VERSION 5.8 ;
BUSBITCHARS "[]" ;
DIVIDERCHAR "/" ;
UNITS
    DATABASE MICRONS 1000 ;
END UNITS

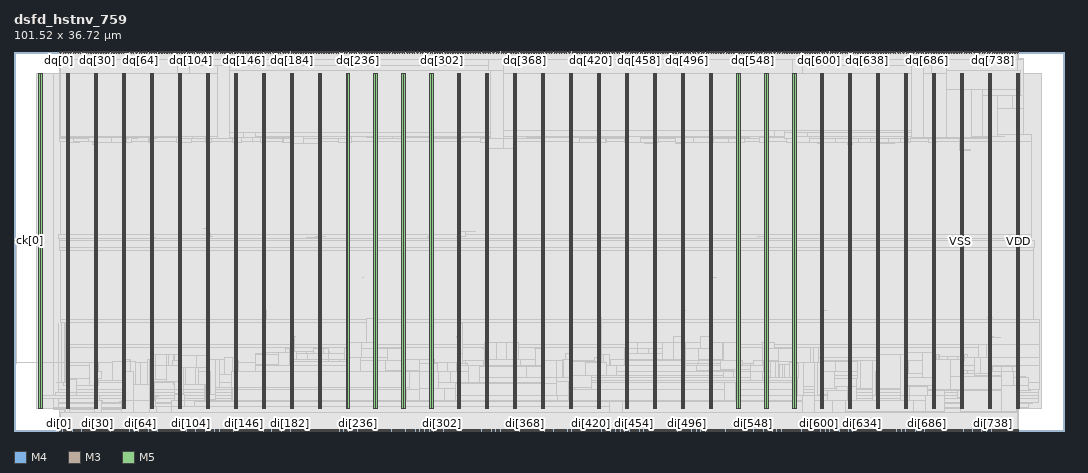
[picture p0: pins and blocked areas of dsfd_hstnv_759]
MACRO dsfd_hstnv_759
  FOREIGN dsfd_hstnv_759 0 0 ;
  CLASS BLOCK ;
  SIZE 101.52 BY 36.72 ;
  PIN ck[0]
    DIRECTION INPUT ;
    USE SIGNAL ;
    PORT
      LAYER M4 ;
        RECT  0 18.384 0.192 18.408 ;
    END
    PORT
      LAYER M4 ;
        RECT  0.156 18.384 0.275 18.408 ;
    END
  END ck[0]
  PIN di[0]
    DIRECTION INPUT ;
    USE SIGNAL ;
    PORT
      LAYER M3 ;
        RECT  4.356 0 4.374 0.144 ;
    END
  END di[0]
  PIN di[100]
    DIRECTION INPUT ;
    USE SIGNAL ;
    PORT
      LAYER M3 ;
        RECT  16.596 0 16.614 0.144 ;
    END
  END di[100]
  PIN di[101]
    DIRECTION INPUT ;
    USE SIGNAL ;
    PORT
      LAYER M5 ;
        RECT  16.752 0 16.776 0.192 ;
    END
  END di[101]
  PIN di[102]
    DIRECTION INPUT ;
    USE SIGNAL ;
    PORT
      LAYER M3 ;
        RECT  16.848 0 16.866 0.144 ;
    END
  END di[102]
  PIN di[103]
    DIRECTION INPUT ;
    USE SIGNAL ;
    PORT
      LAYER M5 ;
        RECT  16.992 0 17.016 0.192 ;
    END
  END di[103]
  PIN di[104]
    DIRECTION INPUT ;
    USE SIGNAL ;
    PORT
      LAYER M3 ;
        RECT  17.1 0 17.118 0.144 ;
    END
  END di[104]
  PIN di[105]
    DIRECTION INPUT ;
    USE SIGNAL ;
    PORT
      LAYER M5 ;
        RECT  17.232 0 17.256 0.192 ;
    END
  END di[105]
  PIN di[106]
    DIRECTION INPUT ;
    USE SIGNAL ;
    PORT
      LAYER M3 ;
        RECT  17.352 0 17.37 0.144 ;
    END
  END di[106]
  PIN di[107]
    DIRECTION INPUT ;
    USE SIGNAL ;
    PORT
      LAYER M5 ;
        RECT  17.472 0 17.496 0.192 ;
    END
  END di[107]
  PIN di[108]
    DIRECTION INPUT ;
    USE SIGNAL ;
    PORT
      LAYER M3 ;
        RECT  17.604 0 17.622 0.144 ;
    END
  END di[108]
  PIN di[109]
    DIRECTION INPUT ;
    USE SIGNAL ;
    PORT
      LAYER M5 ;
        RECT  17.712 0 17.736 0.192 ;
    END
  END di[109]
  PIN di[10]
    DIRECTION INPUT ;
    USE SIGNAL ;
    PORT
      LAYER M3 ;
        RECT  5.58 0 5.598 0.144 ;
    END
  END di[10]
  PIN di[110]
    DIRECTION INPUT ;
    USE SIGNAL ;
    PORT
      LAYER M3 ;
        RECT  17.82 0 17.838 0.144 ;
    END
  END di[110]
  PIN di[111]
    DIRECTION INPUT ;
    USE SIGNAL ;
    PORT
      LAYER M5 ;
        RECT  17.952 0 17.976 0.192 ;
    END
  END di[111]
  PIN di[112]
    DIRECTION INPUT ;
    USE SIGNAL ;
    PORT
      LAYER M3 ;
        RECT  18.072 0 18.09 0.144 ;
    END
  END di[112]
  PIN di[113]
    DIRECTION INPUT ;
    USE SIGNAL ;
    PORT
      LAYER M5 ;
        RECT  18.192 0 18.216 0.192 ;
    END
  END di[113]
  PIN di[114]
    DIRECTION INPUT ;
    USE SIGNAL ;
    PORT
      LAYER M3 ;
        RECT  18.324 0 18.342 0.144 ;
    END
  END di[114]
  PIN di[115]
    DIRECTION INPUT ;
    USE SIGNAL ;
    PORT
      LAYER M5 ;
        RECT  18.432 0 18.456 0.192 ;
    END
  END di[115]
  PIN di[116]
    DIRECTION INPUT ;
    USE SIGNAL ;
    PORT
      LAYER M3 ;
        RECT  18.576 0 18.594 0.144 ;
    END
  END di[116]
  PIN di[117]
    DIRECTION INPUT ;
    USE SIGNAL ;
    PORT
      LAYER M5 ;
        RECT  18.672 0 18.696 0.192 ;
    END
  END di[117]
  PIN di[118]
    DIRECTION INPUT ;
    USE SIGNAL ;
    PORT
      LAYER M3 ;
        RECT  18.828 0 18.846 0.144 ;
    END
  END di[118]
  PIN di[119]
    DIRECTION INPUT ;
    USE SIGNAL ;
    PORT
      LAYER M5 ;
        RECT  18.912 0 18.936 0.192 ;
    END
  END di[119]
  PIN di[11]
    DIRECTION INPUT ;
    USE SIGNAL ;
    PORT
      LAYER M5 ;
        RECT  5.712 0 5.736 0.192 ;
    END
  END di[11]
  PIN di[120]
    DIRECTION INPUT ;
    USE SIGNAL ;
    PORT
      LAYER M3 ;
        RECT  19.044 0 19.062 0.144 ;
    END
  END di[120]
  PIN di[121]
    DIRECTION INPUT ;
    USE SIGNAL ;
    PORT
      LAYER M5 ;
        RECT  19.2 0 19.224 0.192 ;
    END
  END di[121]
  PIN di[122]
    DIRECTION INPUT ;
    USE SIGNAL ;
    PORT
      LAYER M3 ;
        RECT  19.296 0 19.314 0.144 ;
    END
  END di[122]
  PIN di[123]
    DIRECTION INPUT ;
    USE SIGNAL ;
    PORT
      LAYER M5 ;
        RECT  19.44 0 19.464 0.192 ;
    END
  END di[123]
  PIN di[124]
    DIRECTION INPUT ;
    USE SIGNAL ;
    PORT
      LAYER M3 ;
        RECT  19.548 0 19.566 0.144 ;
    END
  END di[124]
  PIN di[125]
    DIRECTION INPUT ;
    USE SIGNAL ;
    PORT
      LAYER M5 ;
        RECT  19.68 0 19.704 0.192 ;
    END
  END di[125]
  PIN di[126]
    DIRECTION INPUT ;
    USE SIGNAL ;
    PORT
      LAYER M3 ;
        RECT  19.8 0 19.818 0.144 ;
    END
  END di[126]
  PIN di[127]
    DIRECTION INPUT ;
    USE SIGNAL ;
    PORT
      LAYER M5 ;
        RECT  19.92 0 19.944 0.192 ;
    END
  END di[127]
  PIN di[128]
    DIRECTION INPUT ;
    USE SIGNAL ;
    PORT
      LAYER M3 ;
        RECT  20.052 0 20.07 0.144 ;
    END
  END di[128]
  PIN di[129]
    DIRECTION INPUT ;
    USE SIGNAL ;
    PORT
      LAYER M5 ;
        RECT  20.16 0 20.184 0.192 ;
    END
  END di[129]
  PIN di[12]
    DIRECTION INPUT ;
    USE SIGNAL ;
    PORT
      LAYER M3 ;
        RECT  5.832 0 5.85 0.144 ;
    END
  END di[12]
  PIN di[130]
    DIRECTION INPUT ;
    USE SIGNAL ;
    PORT
      LAYER M3 ;
        RECT  20.268 0 20.286 0.144 ;
    END
  END di[130]
  PIN di[131]
    DIRECTION INPUT ;
    USE SIGNAL ;
    PORT
      LAYER M5 ;
        RECT  20.4 0 20.424 0.192 ;
    END
  END di[131]
  PIN di[132]
    DIRECTION INPUT ;
    USE SIGNAL ;
    PORT
      LAYER M3 ;
        RECT  20.52 0 20.538 0.144 ;
    END
  END di[132]
  PIN di[133]
    DIRECTION INPUT ;
    USE SIGNAL ;
    PORT
      LAYER M5 ;
        RECT  20.64 0 20.664 0.192 ;
    END
  END di[133]
  PIN di[134]
    DIRECTION INPUT ;
    USE SIGNAL ;
    PORT
      LAYER M3 ;
        RECT  20.772 0 20.79 0.144 ;
    END
  END di[134]
  PIN di[135]
    DIRECTION INPUT ;
    USE SIGNAL ;
    PORT
      LAYER M5 ;
        RECT  20.88 0 20.904 0.192 ;
    END
  END di[135]
  PIN di[136]
    DIRECTION INPUT ;
    USE SIGNAL ;
    PORT
      LAYER M3 ;
        RECT  21.024 0 21.042 0.144 ;
    END
  END di[136]
  PIN di[137]
    DIRECTION INPUT ;
    USE SIGNAL ;
    PORT
      LAYER M5 ;
        RECT  21.12 0 21.144 0.192 ;
    END
  END di[137]
  PIN di[138]
    DIRECTION INPUT ;
    USE SIGNAL ;
    PORT
      LAYER M3 ;
        RECT  21.276 0 21.294 0.144 ;
    END
  END di[138]
  PIN di[139]
    DIRECTION INPUT ;
    USE SIGNAL ;
    PORT
      LAYER M5 ;
        RECT  21.36 0 21.384 0.192 ;
    END
  END di[139]
  PIN di[13]
    DIRECTION INPUT ;
    USE SIGNAL ;
    PORT
      LAYER M5 ;
        RECT  5.952 0 5.976 0.192 ;
    END
  END di[13]
  PIN di[140]
    DIRECTION INPUT ;
    USE SIGNAL ;
    PORT
      LAYER M3 ;
        RECT  21.492 0 21.51 0.144 ;
    END
  END di[140]
  PIN di[141]
    DIRECTION INPUT ;
    USE SIGNAL ;
    PORT
      LAYER M5 ;
        RECT  21.6 0 21.624 0.192 ;
    END
  END di[141]
  PIN di[142]
    DIRECTION INPUT ;
    USE SIGNAL ;
    PORT
      LAYER M3 ;
        RECT  21.744 0 21.762 0.144 ;
    END
  END di[142]
  PIN di[143]
    DIRECTION INPUT ;
    USE SIGNAL ;
    PORT
      LAYER M5 ;
        RECT  21.888 0 21.912 0.192 ;
    END
  END di[143]
  PIN di[144]
    DIRECTION INPUT ;
    USE SIGNAL ;
    PORT
      LAYER M3 ;
        RECT  21.996 0 22.014 0.144 ;
    END
  END di[144]
  PIN di[145]
    DIRECTION INPUT ;
    USE SIGNAL ;
    PORT
      LAYER M5 ;
        RECT  22.128 0 22.152 0.192 ;
    END
  END di[145]
  PIN di[146]
    DIRECTION INPUT ;
    USE SIGNAL ;
    PORT
      LAYER M3 ;
        RECT  22.248 0 22.266 0.144 ;
    END
  END di[146]
  PIN di[147]
    DIRECTION INPUT ;
    USE SIGNAL ;
    PORT
      LAYER M5 ;
        RECT  22.368 0 22.392 0.192 ;
    END
  END di[147]
  PIN di[148]
    DIRECTION INPUT ;
    USE SIGNAL ;
    PORT
      LAYER M3 ;
        RECT  22.5 0 22.518 0.144 ;
    END
  END di[148]
  PIN di[149]
    DIRECTION INPUT ;
    USE SIGNAL ;
    PORT
      LAYER M5 ;
        RECT  22.608 0 22.632 0.192 ;
    END
    PORT
      LAYER M5 ;
        RECT  22.512 0.133 22.776 0.144 ;
    END
  END di[149]
  PIN di[14]
    DIRECTION INPUT ;
    USE SIGNAL ;
    PORT
      LAYER M3 ;
        RECT  6.084 0 6.102 0.144 ;
    END
  END di[14]
  PIN di[150]
    DIRECTION INPUT ;
    USE SIGNAL ;
    PORT
      LAYER M3 ;
        RECT  22.716 0 22.734 0.144 ;
    END
  END di[150]
  PIN di[151]
    DIRECTION INPUT ;
    USE SIGNAL ;
    PORT
      LAYER M5 ;
        RECT  22.848 0 22.872 0.192 ;
    END
  END di[151]
  PIN di[152]
    DIRECTION INPUT ;
    USE SIGNAL ;
    PORT
      LAYER M3 ;
        RECT  22.968 0 22.986 0.144 ;
    END
  END di[152]
  PIN di[153]
    DIRECTION INPUT ;
    USE SIGNAL ;
    PORT
      LAYER M5 ;
        RECT  23.088 0 23.112 0.192 ;
    END
  END di[153]
  PIN di[154]
    DIRECTION INPUT ;
    USE SIGNAL ;
    PORT
      LAYER M3 ;
        RECT  23.22 0 23.238 0.144 ;
    END
  END di[154]
  PIN di[155]
    DIRECTION INPUT ;
    USE SIGNAL ;
    PORT
      LAYER M5 ;
        RECT  23.328 0 23.352 0.192 ;
    END
  END di[155]
  PIN di[156]
    DIRECTION INPUT ;
    USE SIGNAL ;
    PORT
      LAYER M3 ;
        RECT  23.472 0 23.49 0.144 ;
    END
  END di[156]
  PIN di[157]
    DIRECTION INPUT ;
    USE SIGNAL ;
    PORT
      LAYER M5 ;
        RECT  23.568 0 23.592 0.192 ;
    END
  END di[157]
  PIN di[158]
    DIRECTION INPUT ;
    USE SIGNAL ;
    PORT
      LAYER M3 ;
        RECT  23.724 0 23.742 0.144 ;
    END
  END di[158]
  PIN di[159]
    DIRECTION INPUT ;
    USE SIGNAL ;
    PORT
      LAYER M5 ;
        RECT  23.808 0 23.832 0.192 ;
    END
  END di[159]
  PIN di[15]
    DIRECTION INPUT ;
    USE SIGNAL ;
    PORT
      LAYER M5 ;
        RECT  6.192 0 6.216 0.192 ;
    END
  END di[15]
  PIN di[160]
    DIRECTION INPUT ;
    USE SIGNAL ;
    PORT
      LAYER M3 ;
        RECT  23.94 0 23.958 0.144 ;
    END
  END di[160]
  PIN di[161]
    DIRECTION INPUT ;
    USE SIGNAL ;
    PORT
      LAYER M5 ;
        RECT  24.048 0 24.072 0.192 ;
    END
  END di[161]
  PIN di[162]
    DIRECTION INPUT ;
    USE SIGNAL ;
    PORT
      LAYER M3 ;
        RECT  24.192 0 24.21 0.144 ;
    END
  END di[162]
  PIN di[163]
    DIRECTION INPUT ;
    USE SIGNAL ;
    PORT
      LAYER M5 ;
        RECT  24.336 0 24.36 0.192 ;
    END
  END di[163]
  PIN di[164]
    DIRECTION INPUT ;
    USE SIGNAL ;
    PORT
      LAYER M3 ;
        RECT  24.444 0 24.462 0.144 ;
    END
  END di[164]
  PIN di[165]
    DIRECTION INPUT ;
    USE SIGNAL ;
    PORT
      LAYER M5 ;
        RECT  24.576 0 24.6 0.192 ;
    END
  END di[165]
  PIN di[166]
    DIRECTION INPUT ;
    USE SIGNAL ;
    PORT
      LAYER M3 ;
        RECT  24.696 0 24.714 0.144 ;
    END
  END di[166]
  PIN di[167]
    DIRECTION INPUT ;
    USE SIGNAL ;
    PORT
      LAYER M5 ;
        RECT  24.816 0 24.84 0.192 ;
    END
  END di[167]
  PIN di[168]
    DIRECTION INPUT ;
    USE SIGNAL ;
    PORT
      LAYER M3 ;
        RECT  24.948 0 24.966 0.144 ;
    END
  END di[168]
  PIN di[169]
    DIRECTION INPUT ;
    USE SIGNAL ;
    PORT
      LAYER M5 ;
        RECT  25.056 0 25.08 0.192 ;
    END
  END di[169]
  PIN di[16]
    DIRECTION INPUT ;
    USE SIGNAL ;
    PORT
      LAYER M3 ;
        RECT  6.336 0 6.354 0.144 ;
    END
  END di[16]
  PIN di[170]
    DIRECTION INPUT ;
    USE SIGNAL ;
    PORT
      LAYER M3 ;
        RECT  25.164 0 25.182 0.144 ;
    END
  END di[170]
  PIN di[171]
    DIRECTION INPUT ;
    USE SIGNAL ;
    PORT
      LAYER M5 ;
        RECT  25.296 0 25.32 0.192 ;
    END
  END di[171]
  PIN di[172]
    DIRECTION INPUT ;
    USE SIGNAL ;
    PORT
      LAYER M3 ;
        RECT  25.416 0 25.434 0.144 ;
    END
  END di[172]
  PIN di[173]
    DIRECTION INPUT ;
    USE SIGNAL ;
    PORT
      LAYER M5 ;
        RECT  25.536 0 25.56 0.192 ;
    END
  END di[173]
  PIN di[174]
    DIRECTION INPUT ;
    USE SIGNAL ;
    PORT
      LAYER M3 ;
        RECT  25.668 0 25.686 0.144 ;
    END
  END di[174]
  PIN di[175]
    DIRECTION INPUT ;
    USE SIGNAL ;
    PORT
      LAYER M5 ;
        RECT  25.776 0 25.8 0.192 ;
    END
  END di[175]
  PIN di[176]
    DIRECTION INPUT ;
    USE SIGNAL ;
    PORT
      LAYER M3 ;
        RECT  25.92 0 25.938 0.144 ;
    END
  END di[176]
  PIN di[177]
    DIRECTION INPUT ;
    USE SIGNAL ;
    PORT
      LAYER M5 ;
        RECT  26.016 0 26.04 0.192 ;
    END
  END di[177]
  PIN di[178]
    DIRECTION INPUT ;
    USE SIGNAL ;
    PORT
      LAYER M3 ;
        RECT  26.172 0 26.19 0.144 ;
    END
  END di[178]
  PIN di[179]
    DIRECTION INPUT ;
    USE SIGNAL ;
    PORT
      LAYER M5 ;
        RECT  26.256 0 26.28 0.192 ;
    END
  END di[179]
  PIN di[17]
    DIRECTION INPUT ;
    USE SIGNAL ;
    PORT
      LAYER M5 ;
        RECT  6.432 0 6.456 0.192 ;
    END
  END di[17]
  PIN di[180]
    DIRECTION INPUT ;
    USE SIGNAL ;
    PORT
      LAYER M3 ;
        RECT  26.388 0 26.406 0.144 ;
    END
  END di[180]
  PIN di[181]
    DIRECTION INPUT ;
    USE SIGNAL ;
    PORT
      LAYER M5 ;
        RECT  26.496 0 26.52 0.192 ;
    END
  END di[181]
  PIN di[182]
    DIRECTION INPUT ;
    USE SIGNAL ;
    PORT
      LAYER M3 ;
        RECT  26.64 0 26.658 0.144 ;
    END
  END di[182]
  PIN di[183]
    DIRECTION INPUT ;
    USE SIGNAL ;
    PORT
      LAYER M5 ;
        RECT  26.784 0 26.808 0.192 ;
    END
  END di[183]
  PIN di[184]
    DIRECTION INPUT ;
    USE SIGNAL ;
    PORT
      LAYER M3 ;
        RECT  26.892 0 26.91 0.144 ;
    END
  END di[184]
  PIN di[185]
    DIRECTION INPUT ;
    USE SIGNAL ;
    PORT
      LAYER M5 ;
        RECT  27.024 0 27.048 0.192 ;
    END
  END di[185]
  PIN di[186]
    DIRECTION INPUT ;
    USE SIGNAL ;
    PORT
      LAYER M3 ;
        RECT  27.144 0 27.162 0.144 ;
    END
  END di[186]
  PIN di[187]
    DIRECTION INPUT ;
    USE SIGNAL ;
    PORT
      LAYER M5 ;
        RECT  27.264 0 27.288 0.192 ;
    END
  END di[187]
  PIN di[188]
    DIRECTION INPUT ;
    USE SIGNAL ;
    PORT
      LAYER M3 ;
        RECT  27.396 0 27.414 0.144 ;
    END
  END di[188]
  PIN di[189]
    DIRECTION INPUT ;
    USE SIGNAL ;
    PORT
      LAYER M5 ;
        RECT  27.504 0 27.528 0.192 ;
    END
  END di[189]
  PIN di[18]
    DIRECTION INPUT ;
    USE SIGNAL ;
    PORT
      LAYER M3 ;
        RECT  6.588 0 6.606 0.144 ;
    END
  END di[18]
  PIN di[190]
    DIRECTION INPUT ;
    USE SIGNAL ;
    PORT
      LAYER M3 ;
        RECT  27.612 0 27.63 0.144 ;
    END
  END di[190]
  PIN di[191]
    DIRECTION INPUT ;
    USE SIGNAL ;
    PORT
      LAYER M5 ;
        RECT  27.744 0 27.768 0.192 ;
    END
  END di[191]
  PIN di[192]
    DIRECTION INPUT ;
    USE SIGNAL ;
    PORT
      LAYER M3 ;
        RECT  27.864 0 27.882 0.144 ;
    END
  END di[192]
  PIN di[193]
    DIRECTION INPUT ;
    USE SIGNAL ;
    PORT
      LAYER M5 ;
        RECT  27.984 0 28.008 0.192 ;
    END
  END di[193]
  PIN di[194]
    DIRECTION INPUT ;
    USE SIGNAL ;
    PORT
      LAYER M3 ;
        RECT  28.116 0 28.134 0.144 ;
    END
  END di[194]
  PIN di[195]
    DIRECTION INPUT ;
    USE SIGNAL ;
    PORT
      LAYER M5 ;
        RECT  28.224 0 28.248 0.192 ;
    END
  END di[195]
  PIN di[196]
    DIRECTION INPUT ;
    USE SIGNAL ;
    PORT
      LAYER M3 ;
        RECT  28.368 0 28.386 0.144 ;
    END
  END di[196]
  PIN di[197]
    DIRECTION INPUT ;
    USE SIGNAL ;
    PORT
      LAYER M5 ;
        RECT  28.464 0 28.488 0.192 ;
    END
  END di[197]
  PIN di[198]
    DIRECTION INPUT ;
    USE SIGNAL ;
    PORT
      LAYER M3 ;
        RECT  28.584 0 28.602 0.144 ;
    END
  END di[198]
  PIN di[199]
    DIRECTION INPUT ;
    USE SIGNAL ;
    PORT
      LAYER M5 ;
        RECT  28.704 0 28.728 0.192 ;
    END
  END di[199]
  PIN di[19]
    DIRECTION INPUT ;
    USE SIGNAL ;
    PORT
      LAYER M5 ;
        RECT  6.672 0 6.696 0.192 ;
    END
  END di[19]
  PIN di[1]
    DIRECTION INPUT ;
    USE SIGNAL ;
    PORT
      LAYER M5 ;
        RECT  4.512 0 4.536 0.192 ;
    END
  END di[1]
  PIN di[200]
    DIRECTION INPUT ;
    USE SIGNAL ;
    PORT
      LAYER M3 ;
        RECT  28.836 0 28.854 0.144 ;
    END
  END di[200]
  PIN di[201]
    DIRECTION INPUT ;
    USE SIGNAL ;
    PORT
      LAYER M5 ;
        RECT  28.944 0 28.968 0.192 ;
    END
  END di[201]
  PIN di[202]
    DIRECTION INPUT ;
    USE SIGNAL ;
    PORT
      LAYER M3 ;
        RECT  29.088 0 29.106 0.144 ;
    END
  END di[202]
  PIN di[203]
    DIRECTION INPUT ;
    USE SIGNAL ;
    PORT
      LAYER M5 ;
        RECT  29.232 0 29.256 0.192 ;
    END
  END di[203]
  PIN di[204]
    DIRECTION INPUT ;
    USE SIGNAL ;
    PORT
      LAYER M3 ;
        RECT  29.34 0 29.358 0.144 ;
    END
  END di[204]
  PIN di[205]
    DIRECTION INPUT ;
    USE SIGNAL ;
    PORT
      LAYER M5 ;
        RECT  29.472 0 29.496 0.192 ;
    END
  END di[205]
  PIN di[206]
    DIRECTION INPUT ;
    USE SIGNAL ;
    PORT
      LAYER M3 ;
        RECT  29.592 0 29.61 0.144 ;
    END
  END di[206]
  PIN di[207]
    DIRECTION INPUT ;
    USE SIGNAL ;
    PORT
      LAYER M5 ;
        RECT  29.712 0 29.736 0.192 ;
    END
  END di[207]
  PIN di[208]
    DIRECTION INPUT ;
    USE SIGNAL ;
    PORT
      LAYER M3 ;
        RECT  29.808 0 29.826 0.144 ;
    END
  END di[208]
  PIN di[209]
    DIRECTION INPUT ;
    USE SIGNAL ;
    PORT
      LAYER M5 ;
        RECT  29.952 0 29.976 0.192 ;
    END
  END di[209]
  PIN di[20]
    DIRECTION INPUT ;
    USE SIGNAL ;
    PORT
      LAYER M3 ;
        RECT  6.804 0 6.822 0.144 ;
    END
  END di[20]
  PIN di[210]
    DIRECTION INPUT ;
    USE SIGNAL ;
    PORT
      LAYER M3 ;
        RECT  30.06 0 30.078 0.144 ;
    END
  END di[210]
  PIN di[211]
    DIRECTION INPUT ;
    USE SIGNAL ;
    PORT
      LAYER M5 ;
        RECT  30.192 0 30.216 0.192 ;
    END
  END di[211]
  PIN di[212]
    DIRECTION INPUT ;
    USE SIGNAL ;
    PORT
      LAYER M3 ;
        RECT  30.312 0 30.33 0.144 ;
    END
  END di[212]
  PIN di[213]
    DIRECTION INPUT ;
    USE SIGNAL ;
    PORT
      LAYER M5 ;
        RECT  30.432 0 30.456 0.192 ;
    END
  END di[213]
  PIN di[214]
    DIRECTION INPUT ;
    USE SIGNAL ;
    PORT
      LAYER M3 ;
        RECT  30.564 0 30.582 0.144 ;
    END
  END di[214]
  PIN di[215]
    DIRECTION INPUT ;
    USE SIGNAL ;
    PORT
      LAYER M5 ;
        RECT  30.672 0 30.696 0.192 ;
    END
  END di[215]
  PIN di[216]
    DIRECTION INPUT ;
    USE SIGNAL ;
    PORT
      LAYER M3 ;
        RECT  30.816 0 30.834 0.144 ;
    END
  END di[216]
  PIN di[217]
    DIRECTION INPUT ;
    USE SIGNAL ;
    PORT
      LAYER M5 ;
        RECT  30.912 0 30.936 0.192 ;
    END
  END di[217]
  PIN di[218]
    DIRECTION INPUT ;
    USE SIGNAL ;
    PORT
      LAYER M3 ;
        RECT  31.032 0 31.05 0.144 ;
    END
  END di[218]
  PIN di[219]
    DIRECTION INPUT ;
    USE SIGNAL ;
    PORT
      LAYER M5 ;
        RECT  31.152 0 31.176 0.192 ;
    END
  END di[219]
  PIN di[21]
    DIRECTION INPUT ;
    USE SIGNAL ;
    PORT
      LAYER M5 ;
        RECT  6.96 0 6.984 0.192 ;
    END
  END di[21]
  PIN di[220]
    DIRECTION INPUT ;
    USE SIGNAL ;
    PORT
      LAYER M3 ;
        RECT  31.284 0 31.302 0.144 ;
    END
  END di[220]
  PIN di[221]
    DIRECTION INPUT ;
    USE SIGNAL ;
    PORT
      LAYER M5 ;
        RECT  31.392 0 31.416 0.192 ;
    END
  END di[221]
  PIN di[222]
    DIRECTION INPUT ;
    USE SIGNAL ;
    PORT
      LAYER M3 ;
        RECT  31.536 0 31.554 0.144 ;
    END
  END di[222]
  PIN di[223]
    DIRECTION INPUT ;
    USE SIGNAL ;
    PORT
      LAYER M5 ;
        RECT  31.68 0 31.704 0.192 ;
    END
  END di[223]
  PIN di[224]
    DIRECTION INPUT ;
    USE SIGNAL ;
    PORT
      LAYER M3 ;
        RECT  31.788 0 31.806 0.144 ;
    END
  END di[224]
  PIN di[225]
    DIRECTION INPUT ;
    USE SIGNAL ;
    PORT
      LAYER M5 ;
        RECT  31.92 0 31.944 0.192 ;
    END
  END di[225]
  PIN di[226]
    DIRECTION INPUT ;
    USE SIGNAL ;
    PORT
      LAYER M3 ;
        RECT  32.04 0 32.058 0.144 ;
    END
  END di[226]
  PIN di[227]
    DIRECTION INPUT ;
    USE SIGNAL ;
    PORT
      LAYER M5 ;
        RECT  32.16 0 32.184 0.192 ;
    END
  END di[227]
  PIN di[228]
    DIRECTION INPUT ;
    USE SIGNAL ;
    PORT
      LAYER M3 ;
        RECT  32.256 0 32.274 0.144 ;
    END
  END di[228]
  PIN di[229]
    DIRECTION INPUT ;
    USE SIGNAL ;
    PORT
      LAYER M5 ;
        RECT  32.4 0 32.424 0.192 ;
    END
  END di[229]
  PIN di[22]
    DIRECTION INPUT ;
    USE SIGNAL ;
    PORT
      LAYER M3 ;
        RECT  7.056 0 7.074 0.144 ;
    END
  END di[22]
  PIN di[230]
    DIRECTION INPUT ;
    USE SIGNAL ;
    PORT
      LAYER M3 ;
        RECT  32.508 0 32.526 0.144 ;
    END
  END di[230]
  PIN di[231]
    DIRECTION INPUT ;
    USE SIGNAL ;
    PORT
      LAYER M5 ;
        RECT  32.64 0 32.664 0.192 ;
    END
  END di[231]
  PIN di[232]
    DIRECTION INPUT ;
    USE SIGNAL ;
    PORT
      LAYER M3 ;
        RECT  32.76 0 32.778 0.144 ;
    END
  END di[232]
  PIN di[233]
    DIRECTION INPUT ;
    USE SIGNAL ;
    PORT
      LAYER M5 ;
        RECT  32.88 0 32.904 0.192 ;
    END
  END di[233]
  PIN di[234]
    DIRECTION INPUT ;
    USE SIGNAL ;
    PORT
      LAYER M3 ;
        RECT  33.012 0 33.03 0.144 ;
    END
  END di[234]
  PIN di[235]
    DIRECTION INPUT ;
    USE SIGNAL ;
    PORT
      LAYER M5 ;
        RECT  33.12 0 33.144 0.192 ;
    END
  END di[235]
  PIN di[236]
    DIRECTION INPUT ;
    USE SIGNAL ;
    PORT
      LAYER M3 ;
        RECT  33.264 0 33.282 0.144 ;
    END
  END di[236]
  PIN di[237]
    DIRECTION INPUT ;
    USE SIGNAL ;
    PORT
      LAYER M5 ;
        RECT  33.36 0 33.384 0.192 ;
    END
  END di[237]
  PIN di[238]
    DIRECTION INPUT ;
    USE SIGNAL ;
    PORT
      LAYER M3 ;
        RECT  33.48 0 33.498 0.144 ;
    END
  END di[238]
  PIN di[239]
    DIRECTION INPUT ;
    USE SIGNAL ;
    PORT
      LAYER M5 ;
        RECT  33.6 0 33.624 0.192 ;
    END
  END di[239]
  PIN di[23]
    DIRECTION INPUT ;
    USE SIGNAL ;
    PORT
      LAYER M5 ;
        RECT  7.2 0 7.224 0.192 ;
    END
  END di[23]
  PIN di[240]
    DIRECTION INPUT ;
    USE SIGNAL ;
    PORT
      LAYER M3 ;
        RECT  33.732 0 33.75 0.144 ;
    END
  END di[240]
  PIN di[241]
    DIRECTION INPUT ;
    USE SIGNAL ;
    PORT
      LAYER M5 ;
        RECT  33.84 0 33.864 0.192 ;
    END
  END di[241]
  PIN di[242]
    DIRECTION INPUT ;
    USE SIGNAL ;
    PORT
      LAYER M3 ;
        RECT  33.984 0 34.002 0.144 ;
    END
  END di[242]
  PIN di[243]
    DIRECTION INPUT ;
    USE SIGNAL ;
    PORT
      LAYER M5 ;
        RECT  34.128 0 34.152 0.192 ;
    END
  END di[243]
  PIN di[244]
    DIRECTION INPUT ;
    USE SIGNAL ;
    PORT
      LAYER M3 ;
        RECT  34.236 0 34.254 0.144 ;
    END
  END di[244]
  PIN di[245]
    DIRECTION INPUT ;
    USE SIGNAL ;
    PORT
      LAYER M5 ;
        RECT  34.368 0 34.392 0.192 ;
    END
  END di[245]
  PIN di[246]
    DIRECTION INPUT ;
    USE SIGNAL ;
    PORT
      LAYER M3 ;
        RECT  34.488 0 34.506 0.144 ;
    END
  END di[246]
  PIN di[247]
    DIRECTION INPUT ;
    USE SIGNAL ;
    PORT
      LAYER M5 ;
        RECT  34.608 0 34.632 0.192 ;
    END
  END di[247]
  PIN di[248]
    DIRECTION INPUT ;
    USE SIGNAL ;
    PORT
      LAYER M3 ;
        RECT  34.704 0 34.722 0.144 ;
    END
  END di[248]
  PIN di[249]
    DIRECTION INPUT ;
    USE SIGNAL ;
    PORT
      LAYER M5 ;
        RECT  34.848 0 34.872 0.192 ;
    END
  END di[249]
  PIN di[24]
    DIRECTION INPUT ;
    USE SIGNAL ;
    PORT
      LAYER M3 ;
        RECT  7.308 0 7.326 0.144 ;
    END
  END di[24]
  PIN di[250]
    DIRECTION INPUT ;
    USE SIGNAL ;
    PORT
      LAYER M3 ;
        RECT  34.956 0 34.974 0.144 ;
    END
  END di[250]
  PIN di[251]
    DIRECTION INPUT ;
    USE SIGNAL ;
    PORT
      LAYER M5 ;
        RECT  35.088 0 35.112 0.192 ;
    END
  END di[251]
  PIN di[252]
    DIRECTION INPUT ;
    USE SIGNAL ;
    PORT
      LAYER M3 ;
        RECT  35.208 0 35.226 0.144 ;
    END
  END di[252]
  PIN di[253]
    DIRECTION INPUT ;
    USE SIGNAL ;
    PORT
      LAYER M5 ;
        RECT  35.328 0 35.352 0.192 ;
    END
  END di[253]
  PIN di[254]
    DIRECTION INPUT ;
    USE SIGNAL ;
    PORT
      LAYER M3 ;
        RECT  35.46 0 35.478 0.144 ;
    END
  END di[254]
  PIN di[255]
    DIRECTION INPUT ;
    USE SIGNAL ;
    PORT
      LAYER M5 ;
        RECT  35.568 0 35.592 0.192 ;
    END
  END di[255]
  PIN di[256]
    DIRECTION INPUT ;
    USE SIGNAL ;
    PORT
      LAYER M3 ;
        RECT  35.712 0 35.73 0.144 ;
    END
  END di[256]
  PIN di[257]
    DIRECTION INPUT ;
    USE SIGNAL ;
    PORT
      LAYER M5 ;
        RECT  35.808 0 35.832 0.192 ;
    END
  END di[257]
  PIN di[258]
    DIRECTION INPUT ;
    USE SIGNAL ;
    PORT
      LAYER M3 ;
        RECT  35.928 0 35.946 0.144 ;
    END
  END di[258]
  PIN di[259]
    DIRECTION INPUT ;
    USE SIGNAL ;
    PORT
      LAYER M5 ;
        RECT  36.048 0 36.072 0.192 ;
    END
  END di[259]
  PIN di[25]
    DIRECTION INPUT ;
    USE SIGNAL ;
    PORT
      LAYER M5 ;
        RECT  7.44 0 7.464 0.192 ;
    END
  END di[25]
  PIN di[260]
    DIRECTION INPUT ;
    USE SIGNAL ;
    PORT
      LAYER M3 ;
        RECT  36.18 0 36.198 0.144 ;
    END
  END di[260]
  PIN di[261]
    DIRECTION INPUT ;
    USE SIGNAL ;
    PORT
      LAYER M5 ;
        RECT  36.288 0 36.312 0.192 ;
    END
  END di[261]
  PIN di[262]
    DIRECTION INPUT ;
    USE SIGNAL ;
    PORT
      LAYER M3 ;
        RECT  36.432 0 36.45 0.144 ;
    END
  END di[262]
  PIN di[263]
    DIRECTION INPUT ;
    USE SIGNAL ;
    PORT
      LAYER M5 ;
        RECT  36.576 0 36.6 0.192 ;
    END
  END di[263]
  PIN di[264]
    DIRECTION INPUT ;
    USE SIGNAL ;
    PORT
      LAYER M3 ;
        RECT  36.684 0 36.702 0.144 ;
    END
  END di[264]
  PIN di[265]
    DIRECTION INPUT ;
    USE SIGNAL ;
    PORT
      LAYER M5 ;
        RECT  36.816 0 36.84 0.192 ;
    END
  END di[265]
  PIN di[266]
    DIRECTION INPUT ;
    USE SIGNAL ;
    PORT
      LAYER M3 ;
        RECT  36.936 0 36.954 0.144 ;
    END
  END di[266]
  PIN di[267]
    DIRECTION INPUT ;
    USE SIGNAL ;
    PORT
      LAYER M5 ;
        RECT  37.056 0 37.08 0.192 ;
    END
  END di[267]
  PIN di[268]
    DIRECTION INPUT ;
    USE SIGNAL ;
    PORT
      LAYER M3 ;
        RECT  37.152 0 37.17 0.144 ;
    END
  END di[268]
  PIN di[269]
    DIRECTION INPUT ;
    USE SIGNAL ;
    PORT
      LAYER M5 ;
        RECT  37.296 0 37.32 0.192 ;
    END
  END di[269]
  PIN di[26]
    DIRECTION INPUT ;
    USE SIGNAL ;
    PORT
      LAYER M3 ;
        RECT  7.56 0 7.578 0.144 ;
    END
  END di[26]
  PIN di[270]
    DIRECTION INPUT ;
    USE SIGNAL ;
    PORT
      LAYER M3 ;
        RECT  37.404 0 37.422 0.144 ;
    END
  END di[270]
  PIN di[271]
    DIRECTION INPUT ;
    USE SIGNAL ;
    PORT
      LAYER M5 ;
        RECT  37.536 0 37.56 0.192 ;
    END
  END di[271]
  PIN di[272]
    DIRECTION INPUT ;
    USE SIGNAL ;
    PORT
      LAYER M3 ;
        RECT  37.656 0 37.674 0.144 ;
    END
  END di[272]
  PIN di[273]
    DIRECTION INPUT ;
    USE SIGNAL ;
    PORT
      LAYER M5 ;
        RECT  37.776 0 37.8 0.192 ;
    END
  END di[273]
  PIN di[274]
    DIRECTION INPUT ;
    USE SIGNAL ;
    PORT
      LAYER M3 ;
        RECT  37.908 0 37.926 0.144 ;
    END
  END di[274]
  PIN di[275]
    DIRECTION INPUT ;
    USE SIGNAL ;
    PORT
      LAYER M5 ;
        RECT  38.016 0 38.04 0.192 ;
    END
  END di[275]
  PIN di[276]
    DIRECTION INPUT ;
    USE SIGNAL ;
    PORT
      LAYER M3 ;
        RECT  38.16 0 38.178 0.144 ;
    END
  END di[276]
  PIN di[277]
    DIRECTION INPUT ;
    USE SIGNAL ;
    PORT
      LAYER M5 ;
        RECT  38.256 0 38.28 0.192 ;
    END
  END di[277]
  PIN di[278]
    DIRECTION INPUT ;
    USE SIGNAL ;
    PORT
      LAYER M3 ;
        RECT  38.376 0 38.394 0.144 ;
    END
  END di[278]
  PIN di[279]
    DIRECTION INPUT ;
    USE SIGNAL ;
    PORT
      LAYER M5 ;
        RECT  38.496 0 38.52 0.192 ;
    END
  END di[279]
  PIN di[27]
    DIRECTION INPUT ;
    USE SIGNAL ;
    PORT
      LAYER M5 ;
        RECT  7.68 0 7.704 0.192 ;
    END
  END di[27]
  PIN di[280]
    DIRECTION INPUT ;
    USE SIGNAL ;
    PORT
      LAYER M3 ;
        RECT  38.628 0 38.646 0.144 ;
    END
  END di[280]
  PIN di[281]
    DIRECTION INPUT ;
    USE SIGNAL ;
    PORT
      LAYER M5 ;
        RECT  38.736 0 38.76 0.192 ;
    END
  END di[281]
  PIN di[282]
    DIRECTION INPUT ;
    USE SIGNAL ;
    PORT
      LAYER M3 ;
        RECT  38.88 0 38.898 0.144 ;
    END
  END di[282]
  PIN di[283]
    DIRECTION INPUT ;
    USE SIGNAL ;
    PORT
      LAYER M5 ;
        RECT  39.024 0 39.048 0.192 ;
    END
  END di[283]
  PIN di[284]
    DIRECTION INPUT ;
    USE SIGNAL ;
    PORT
      LAYER M3 ;
        RECT  39.132 0 39.15 0.144 ;
    END
  END di[284]
  PIN di[285]
    DIRECTION INPUT ;
    USE SIGNAL ;
    PORT
      LAYER M5 ;
        RECT  39.264 0 39.288 0.192 ;
    END
  END di[285]
  PIN di[286]
    DIRECTION INPUT ;
    USE SIGNAL ;
    PORT
      LAYER M3 ;
        RECT  39.384 0 39.402 0.144 ;
    END
  END di[286]
  PIN di[287]
    DIRECTION INPUT ;
    USE SIGNAL ;
    PORT
      LAYER M5 ;
        RECT  39.504 0 39.528 0.192 ;
    END
  END di[287]
  PIN di[288]
    DIRECTION INPUT ;
    USE SIGNAL ;
    PORT
      LAYER M3 ;
        RECT  39.6 0 39.618 0.144 ;
    END
  END di[288]
  PIN di[289]
    DIRECTION INPUT ;
    USE SIGNAL ;
    PORT
      LAYER M5 ;
        RECT  39.744 0 39.768 0.192 ;
    END
  END di[289]
  PIN di[28]
    DIRECTION INPUT ;
    USE SIGNAL ;
    PORT
      LAYER M3 ;
        RECT  7.812 0 7.83 0.144 ;
    END
  END di[28]
  PIN di[290]
    DIRECTION INPUT ;
    USE SIGNAL ;
    PORT
      LAYER M3 ;
        RECT  39.852 0 39.87 0.144 ;
    END
  END di[290]
  PIN di[291]
    DIRECTION INPUT ;
    USE SIGNAL ;
    PORT
      LAYER M5 ;
        RECT  39.984 0 40.008 0.192 ;
    END
  END di[291]
  PIN di[292]
    DIRECTION INPUT ;
    USE SIGNAL ;
    PORT
      LAYER M3 ;
        RECT  40.104 0 40.122 0.144 ;
    END
  END di[292]
  PIN di[293]
    DIRECTION INPUT ;
    USE SIGNAL ;
    PORT
      LAYER M5 ;
        RECT  40.224 0 40.248 0.192 ;
    END
  END di[293]
  PIN di[294]
    DIRECTION INPUT ;
    USE SIGNAL ;
    PORT
      LAYER M3 ;
        RECT  40.356 0 40.374 0.144 ;
    END
  END di[294]
  PIN di[295]
    DIRECTION INPUT ;
    USE SIGNAL ;
    PORT
      LAYER M5 ;
        RECT  40.464 0 40.488 0.192 ;
    END
  END di[295]
  PIN di[296]
    DIRECTION INPUT ;
    USE SIGNAL ;
    PORT
      LAYER M3 ;
        RECT  40.608 0 40.626 0.144 ;
    END
  END di[296]
  PIN di[297]
    DIRECTION INPUT ;
    USE SIGNAL ;
    PORT
      LAYER M5 ;
        RECT  40.704 0 40.728 0.192 ;
    END
  END di[297]
  PIN di[298]
    DIRECTION INPUT ;
    USE SIGNAL ;
    PORT
      LAYER M3 ;
        RECT  40.824 0 40.842 0.144 ;
    END
  END di[298]
  PIN di[299]
    DIRECTION INPUT ;
    USE SIGNAL ;
    PORT
      LAYER M5 ;
        RECT  40.944 0 40.968 0.192 ;
    END
  END di[299]
  PIN di[29]
    DIRECTION INPUT ;
    USE SIGNAL ;
    PORT
      LAYER M5 ;
        RECT  7.92 0 7.944 0.192 ;
    END
  END di[29]
  PIN di[2]
    DIRECTION INPUT ;
    USE SIGNAL ;
    PORT
      LAYER M3 ;
        RECT  4.608 0 4.626 0.144 ;
    END
  END di[2]
  PIN di[300]
    DIRECTION INPUT ;
    USE SIGNAL ;
    PORT
      LAYER M3 ;
        RECT  41.076 0 41.094 0.144 ;
    END
  END di[300]
  PIN di[301]
    DIRECTION INPUT ;
    USE SIGNAL ;
    PORT
      LAYER M5 ;
        RECT  41.184 0 41.208 0.192 ;
    END
  END di[301]
  PIN di[302]
    DIRECTION INPUT ;
    USE SIGNAL ;
    PORT
      LAYER M3 ;
        RECT  41.328 0 41.346 0.144 ;
    END
  END di[302]
  PIN di[303]
    DIRECTION INPUT ;
    USE SIGNAL ;
    PORT
      LAYER M5 ;
        RECT  41.424 0 41.448 0.192 ;
    END
  END di[303]
  PIN di[304]
    DIRECTION INPUT ;
    USE SIGNAL ;
    PORT
      LAYER M3 ;
        RECT  41.58 0 41.598 0.144 ;
    END
  END di[304]
  PIN di[305]
    DIRECTION INPUT ;
    USE SIGNAL ;
    PORT
      LAYER M5 ;
        RECT  41.712 0 41.736 0.192 ;
    END
  END di[305]
  PIN di[306]
    DIRECTION INPUT ;
    USE SIGNAL ;
    PORT
      LAYER M3 ;
        RECT  41.832 0 41.85 0.144 ;
    END
  END di[306]
  PIN di[307]
    DIRECTION INPUT ;
    USE SIGNAL ;
    PORT
      LAYER M5 ;
        RECT  41.952 0 41.976 0.192 ;
    END
  END di[307]
  PIN di[308]
    DIRECTION INPUT ;
    USE SIGNAL ;
    PORT
      LAYER M3 ;
        RECT  42.048 0 42.066 0.144 ;
    END
  END di[308]
  PIN di[309]
    DIRECTION INPUT ;
    USE SIGNAL ;
    PORT
      LAYER M5 ;
        RECT  42.192 0 42.216 0.192 ;
    END
  END di[309]
  PIN di[30]
    DIRECTION INPUT ;
    USE SIGNAL ;
    PORT
      LAYER M3 ;
        RECT  8.028 0 8.046 0.144 ;
    END
  END di[30]
  PIN di[310]
    DIRECTION INPUT ;
    USE SIGNAL ;
    PORT
      LAYER M3 ;
        RECT  42.3 0 42.318 0.144 ;
    END
  END di[310]
  PIN di[311]
    DIRECTION INPUT ;
    USE SIGNAL ;
    PORT
      LAYER M5 ;
        RECT  42.432 0 42.456 0.192 ;
    END
  END di[311]
  PIN di[312]
    DIRECTION INPUT ;
    USE SIGNAL ;
    PORT
      LAYER M3 ;
        RECT  42.552 0 42.57 0.144 ;
    END
  END di[312]
  PIN di[313]
    DIRECTION INPUT ;
    USE SIGNAL ;
    PORT
      LAYER M5 ;
        RECT  42.672 0 42.696 0.192 ;
    END
  END di[313]
  PIN di[314]
    DIRECTION INPUT ;
    USE SIGNAL ;
    PORT
      LAYER M3 ;
        RECT  42.804 0 42.822 0.144 ;
    END
  END di[314]
  PIN di[315]
    DIRECTION INPUT ;
    USE SIGNAL ;
    PORT
      LAYER M5 ;
        RECT  42.912 0 42.936 0.192 ;
    END
  END di[315]
  PIN di[316]
    DIRECTION INPUT ;
    USE SIGNAL ;
    PORT
      LAYER M3 ;
        RECT  43.056 0 43.074 0.144 ;
    END
  END di[316]
  PIN di[317]
    DIRECTION INPUT ;
    USE SIGNAL ;
    PORT
      LAYER M5 ;
        RECT  43.152 0 43.176 0.192 ;
    END
  END di[317]
  PIN di[318]
    DIRECTION INPUT ;
    USE SIGNAL ;
    PORT
      LAYER M3 ;
        RECT  43.272 0 43.29 0.144 ;
    END
  END di[318]
  PIN di[319]
    DIRECTION INPUT ;
    USE SIGNAL ;
    PORT
      LAYER M5 ;
        RECT  43.392 0 43.416 0.192 ;
    END
  END di[319]
  PIN di[31]
    DIRECTION INPUT ;
    USE SIGNAL ;
    PORT
      LAYER M5 ;
        RECT  8.16 0 8.184 0.192 ;
    END
  END di[31]
  PIN di[320]
    DIRECTION INPUT ;
    USE SIGNAL ;
    PORT
      LAYER M3 ;
        RECT  43.524 0 43.542 0.144 ;
    END
  END di[320]
  PIN di[321]
    DIRECTION INPUT ;
    USE SIGNAL ;
    PORT
      LAYER M5 ;
        RECT  43.632 0 43.656 0.192 ;
    END
  END di[321]
  PIN di[322]
    DIRECTION INPUT ;
    USE SIGNAL ;
    PORT
      LAYER M3 ;
        RECT  43.776 0 43.794 0.144 ;
    END
  END di[322]
  PIN di[323]
    DIRECTION INPUT ;
    USE SIGNAL ;
    PORT
      LAYER M5 ;
        RECT  43.872 0 43.896 0.192 ;
    END
  END di[323]
  PIN di[324]
    DIRECTION INPUT ;
    USE SIGNAL ;
    PORT
      LAYER M3 ;
        RECT  44.028 0 44.046 0.144 ;
    END
  END di[324]
  PIN di[325]
    DIRECTION INPUT ;
    USE SIGNAL ;
    PORT
      LAYER M5 ;
        RECT  44.16 0 44.184 0.192 ;
    END
  END di[325]
  PIN di[326]
    DIRECTION INPUT ;
    USE SIGNAL ;
    PORT
      LAYER M3 ;
        RECT  44.28 0 44.298 0.144 ;
    END
  END di[326]
  PIN di[327]
    DIRECTION INPUT ;
    USE SIGNAL ;
    PORT
      LAYER M5 ;
        RECT  44.4 0 44.424 0.192 ;
    END
  END di[327]
  PIN di[328]
    DIRECTION INPUT ;
    USE SIGNAL ;
    PORT
      LAYER M3 ;
        RECT  44.496 0 44.514 0.144 ;
    END
  END di[328]
  PIN di[329]
    DIRECTION INPUT ;
    USE SIGNAL ;
    PORT
      LAYER M5 ;
        RECT  44.64 0 44.664 0.192 ;
    END
  END di[329]
  PIN di[32]
    DIRECTION INPUT ;
    USE SIGNAL ;
    PORT
      LAYER M3 ;
        RECT  8.28 0 8.298 0.144 ;
    END
  END di[32]
  PIN di[330]
    DIRECTION INPUT ;
    USE SIGNAL ;
    PORT
      LAYER M3 ;
        RECT  44.748 0 44.766 0.144 ;
    END
  END di[330]
  PIN di[331]
    DIRECTION INPUT ;
    USE SIGNAL ;
    PORT
      LAYER M5 ;
        RECT  44.88 0 44.904 0.192 ;
    END
  END di[331]
  PIN di[332]
    DIRECTION INPUT ;
    USE SIGNAL ;
    PORT
      LAYER M3 ;
        RECT  45 0 45.018 0.144 ;
    END
  END di[332]
  PIN di[333]
    DIRECTION INPUT ;
    USE SIGNAL ;
    PORT
      LAYER M5 ;
        RECT  45.12 0 45.144 0.192 ;
    END
  END di[333]
  PIN di[334]
    DIRECTION INPUT ;
    USE SIGNAL ;
    PORT
      LAYER M3 ;
        RECT  45.252 0 45.27 0.144 ;
    END
  END di[334]
  PIN di[335]
    DIRECTION INPUT ;
    USE SIGNAL ;
    PORT
      LAYER M5 ;
        RECT  45.36 0 45.384 0.192 ;
    END
  END di[335]
  PIN di[336]
    DIRECTION INPUT ;
    USE SIGNAL ;
    PORT
      LAYER M3 ;
        RECT  45.504 0 45.522 0.144 ;
    END
  END di[336]
  PIN di[337]
    DIRECTION INPUT ;
    USE SIGNAL ;
    PORT
      LAYER M5 ;
        RECT  45.6 0 45.624 0.192 ;
    END
  END di[337]
  PIN di[338]
    DIRECTION INPUT ;
    USE SIGNAL ;
    PORT
      LAYER M3 ;
        RECT  45.72 0 45.738 0.144 ;
    END
  END di[338]
  PIN di[339]
    DIRECTION INPUT ;
    USE SIGNAL ;
    PORT
      LAYER M5 ;
        RECT  45.84 0 45.864 0.192 ;
    END
  END di[339]
  PIN di[33]
    DIRECTION INPUT ;
    USE SIGNAL ;
    PORT
      LAYER M5 ;
        RECT  8.4 0 8.424 0.192 ;
    END
  END di[33]
  PIN di[340]
    DIRECTION INPUT ;
    USE SIGNAL ;
    PORT
      LAYER M3 ;
        RECT  45.972 0 45.99 0.144 ;
    END
  END di[340]
  PIN di[341]
    DIRECTION INPUT ;
    USE SIGNAL ;
    PORT
      LAYER M5 ;
        RECT  46.08 0 46.104 0.192 ;
    END
  END di[341]
  PIN di[342]
    DIRECTION INPUT ;
    USE SIGNAL ;
    PORT
      LAYER M3 ;
        RECT  46.224 0 46.242 0.144 ;
    END
  END di[342]
  PIN di[343]
    DIRECTION INPUT ;
    USE SIGNAL ;
    PORT
      LAYER M5 ;
        RECT  46.32 0 46.344 0.192 ;
    END
  END di[343]
  PIN di[344]
    DIRECTION INPUT ;
    USE SIGNAL ;
    PORT
      LAYER M3 ;
        RECT  46.476 0 46.494 0.144 ;
    END
  END di[344]
  PIN di[345]
    DIRECTION INPUT ;
    USE SIGNAL ;
    PORT
      LAYER M5 ;
        RECT  46.608 0 46.632 0.192 ;
    END
  END di[345]
  PIN di[346]
    DIRECTION INPUT ;
    USE SIGNAL ;
    PORT
      LAYER M3 ;
        RECT  46.728 0 46.746 0.144 ;
    END
  END di[346]
  PIN di[347]
    DIRECTION INPUT ;
    USE SIGNAL ;
    PORT
      LAYER M5 ;
        RECT  46.848 0 46.872 0.192 ;
    END
  END di[347]
  PIN di[348]
    DIRECTION INPUT ;
    USE SIGNAL ;
    PORT
      LAYER M3 ;
        RECT  46.944 0 46.962 0.144 ;
    END
  END di[348]
  PIN di[349]
    DIRECTION INPUT ;
    USE SIGNAL ;
    PORT
      LAYER M5 ;
        RECT  47.088 0 47.112 0.192 ;
    END
  END di[349]
  PIN di[34]
    DIRECTION INPUT ;
    USE SIGNAL ;
    PORT
      LAYER M3 ;
        RECT  8.532 0 8.55 0.144 ;
    END
  END di[34]
  PIN di[350]
    DIRECTION INPUT ;
    USE SIGNAL ;
    PORT
      LAYER M3 ;
        RECT  47.196 0 47.214 0.144 ;
    END
  END di[350]
  PIN di[351]
    DIRECTION INPUT ;
    USE SIGNAL ;
    PORT
      LAYER M5 ;
        RECT  47.328 0 47.352 0.192 ;
    END
  END di[351]
  PIN di[352]
    DIRECTION INPUT ;
    USE SIGNAL ;
    PORT
      LAYER M3 ;
        RECT  47.448 0 47.466 0.144 ;
    END
  END di[352]
  PIN di[353]
    DIRECTION INPUT ;
    USE SIGNAL ;
    PORT
      LAYER M5 ;
        RECT  47.568 0 47.592 0.192 ;
    END
  END di[353]
  PIN di[354]
    DIRECTION INPUT ;
    USE SIGNAL ;
    PORT
      LAYER M3 ;
        RECT  47.7 0 47.718 0.144 ;
    END
  END di[354]
  PIN di[355]
    DIRECTION INPUT ;
    USE SIGNAL ;
    PORT
      LAYER M5 ;
        RECT  47.808 0 47.832 0.192 ;
    END
  END di[355]
  PIN di[356]
    DIRECTION INPUT ;
    USE SIGNAL ;
    PORT
      LAYER M3 ;
        RECT  47.952 0 47.97 0.144 ;
    END
  END di[356]
  PIN di[357]
    DIRECTION INPUT ;
    USE SIGNAL ;
    PORT
      LAYER M5 ;
        RECT  48.048 0 48.072 0.192 ;
    END
  END di[357]
  PIN di[358]
    DIRECTION INPUT ;
    USE SIGNAL ;
    PORT
      LAYER M3 ;
        RECT  48.168 0 48.186 0.144 ;
    END
  END di[358]
  PIN di[359]
    DIRECTION INPUT ;
    USE SIGNAL ;
    PORT
      LAYER M5 ;
        RECT  48.288 0 48.312 0.192 ;
    END
  END di[359]
  PIN di[35]
    DIRECTION INPUT ;
    USE SIGNAL ;
    PORT
      LAYER M5 ;
        RECT  8.64 0 8.664 0.192 ;
    END
  END di[35]
  PIN di[360]
    DIRECTION INPUT ;
    USE SIGNAL ;
    PORT
      LAYER M3 ;
        RECT  48.42 0 48.438 0.144 ;
    END
  END di[360]
  PIN di[361]
    DIRECTION INPUT ;
    USE SIGNAL ;
    PORT
      LAYER M5 ;
        RECT  48.528 0 48.552 0.192 ;
    END
  END di[361]
  PIN di[362]
    DIRECTION INPUT ;
    USE SIGNAL ;
    PORT
      LAYER M3 ;
        RECT  48.672 0 48.69 0.144 ;
    END
  END di[362]
  PIN di[363]
    DIRECTION INPUT ;
    USE SIGNAL ;
    PORT
      LAYER M5 ;
        RECT  48.768 0 48.792 0.192 ;
    END
  END di[363]
  PIN di[364]
    DIRECTION INPUT ;
    USE SIGNAL ;
    PORT
      LAYER M3 ;
        RECT  48.924 0 48.942 0.144 ;
    END
  END di[364]
  PIN di[365]
    DIRECTION INPUT ;
    USE SIGNAL ;
    PORT
      LAYER M5 ;
        RECT  49.056 0 49.08 0.192 ;
    END
  END di[365]
  PIN di[366]
    DIRECTION INPUT ;
    USE SIGNAL ;
    PORT
      LAYER M3 ;
        RECT  49.176 0 49.194 0.144 ;
    END
  END di[366]
  PIN di[367]
    DIRECTION INPUT ;
    USE SIGNAL ;
    PORT
      LAYER M5 ;
        RECT  49.296 0 49.32 0.192 ;
    END
  END di[367]
  PIN di[368]
    DIRECTION INPUT ;
    USE SIGNAL ;
    PORT
      LAYER M3 ;
        RECT  49.392 0 49.41 0.144 ;
    END
  END di[368]
  PIN di[369]
    DIRECTION INPUT ;
    USE SIGNAL ;
    PORT
      LAYER M5 ;
        RECT  49.536 0 49.56 0.192 ;
    END
  END di[369]
  PIN di[36]
    DIRECTION INPUT ;
    USE SIGNAL ;
    PORT
      LAYER M3 ;
        RECT  8.784 0 8.802 0.144 ;
    END
  END di[36]
  PIN di[370]
    DIRECTION INPUT ;
    USE SIGNAL ;
    PORT
      LAYER M3 ;
        RECT  49.644 0 49.662 0.144 ;
    END
  END di[370]
  PIN di[371]
    DIRECTION INPUT ;
    USE SIGNAL ;
    PORT
      LAYER M5 ;
        RECT  49.776 0 49.8 0.192 ;
    END
  END di[371]
  PIN di[372]
    DIRECTION INPUT ;
    USE SIGNAL ;
    PORT
      LAYER M3 ;
        RECT  49.896 0 49.914 0.144 ;
    END
  END di[372]
  PIN di[373]
    DIRECTION INPUT ;
    USE SIGNAL ;
    PORT
      LAYER M5 ;
        RECT  50.016 0 50.04 0.192 ;
    END
  END di[373]
  PIN di[374]
    DIRECTION INPUT ;
    USE SIGNAL ;
    PORT
      LAYER M3 ;
        RECT  50.148 0 50.166 0.144 ;
    END
  END di[374]
  PIN di[375]
    DIRECTION INPUT ;
    USE SIGNAL ;
    PORT
      LAYER M5 ;
        RECT  50.256 0 50.28 0.192 ;
    END
  END di[375]
  PIN di[376]
    DIRECTION INPUT ;
    USE SIGNAL ;
    PORT
      LAYER M3 ;
        RECT  50.4 0 50.418 0.144 ;
    END
  END di[376]
  PIN di[377]
    DIRECTION INPUT ;
    USE SIGNAL ;
    PORT
      LAYER M5 ;
        RECT  50.496 0 50.52 0.192 ;
    END
  END di[377]
  PIN di[378]
    DIRECTION INPUT ;
    USE SIGNAL ;
    PORT
      LAYER M3 ;
        RECT  50.616 0 50.634 0.144 ;
    END
  END di[378]
  PIN di[379]
    DIRECTION INPUT ;
    USE SIGNAL ;
    PORT
      LAYER M5 ;
        RECT  50.736 0 50.76 0.192 ;
    END
  END di[379]
  PIN di[37]
    DIRECTION INPUT ;
    USE SIGNAL ;
    PORT
      LAYER M5 ;
        RECT  8.88 0 8.904 0.192 ;
    END
  END di[37]
  PIN di[380]
    DIRECTION INPUT ;
    USE SIGNAL ;
    PORT
      LAYER M3 ;
        RECT  50.868 0 50.886 0.144 ;
    END
  END di[380]
  PIN di[381]
    DIRECTION INPUT ;
    USE SIGNAL ;
    PORT
      LAYER M5 ;
        RECT  50.976 0 51 0.192 ;
    END
  END di[381]
  PIN di[382]
    DIRECTION INPUT ;
    USE SIGNAL ;
    PORT
      LAYER M3 ;
        RECT  51.12 0 51.138 0.144 ;
    END
  END di[382]
  PIN di[383]
    DIRECTION INPUT ;
    USE SIGNAL ;
    PORT
      LAYER M5 ;
        RECT  51.216 0 51.24 0.192 ;
    END
  END di[383]
  PIN di[384]
    DIRECTION INPUT ;
    USE SIGNAL ;
    PORT
      LAYER M3 ;
        RECT  51.372 0 51.39 0.144 ;
    END
  END di[384]
  PIN di[385]
    DIRECTION INPUT ;
    USE SIGNAL ;
    PORT
      LAYER M5 ;
        RECT  51.504 0 51.528 0.192 ;
    END
  END di[385]
  PIN di[386]
    DIRECTION INPUT ;
    USE SIGNAL ;
    PORT
      LAYER M3 ;
        RECT  51.624 0 51.642 0.144 ;
    END
  END di[386]
  PIN di[387]
    DIRECTION INPUT ;
    USE SIGNAL ;
    PORT
      LAYER M5 ;
        RECT  51.744 0 51.768 0.192 ;
    END
  END di[387]
  PIN di[388]
    DIRECTION INPUT ;
    USE SIGNAL ;
    PORT
      LAYER M3 ;
        RECT  51.84 0 51.858 0.144 ;
    END
  END di[388]
  PIN di[389]
    DIRECTION INPUT ;
    USE SIGNAL ;
    PORT
      LAYER M5 ;
        RECT  51.984 0 52.008 0.192 ;
    END
  END di[389]
  PIN di[38]
    DIRECTION INPUT ;
    USE SIGNAL ;
    PORT
      LAYER M3 ;
        RECT  9.036 0 9.054 0.144 ;
    END
  END di[38]
  PIN di[390]
    DIRECTION INPUT ;
    USE SIGNAL ;
    PORT
      LAYER M3 ;
        RECT  52.092 0 52.11 0.144 ;
    END
  END di[390]
  PIN di[391]
    DIRECTION INPUT ;
    USE SIGNAL ;
    PORT
      LAYER M5 ;
        RECT  52.224 0 52.248 0.192 ;
    END
  END di[391]
  PIN di[392]
    DIRECTION INPUT ;
    USE SIGNAL ;
    PORT
      LAYER M3 ;
        RECT  52.344 0 52.362 0.144 ;
    END
  END di[392]
  PIN di[393]
    DIRECTION INPUT ;
    USE SIGNAL ;
    PORT
      LAYER M5 ;
        RECT  52.464 0 52.488 0.192 ;
    END
  END di[393]
  PIN di[394]
    DIRECTION INPUT ;
    USE SIGNAL ;
    PORT
      LAYER M3 ;
        RECT  52.596 0 52.614 0.144 ;
    END
  END di[394]
  PIN di[395]
    DIRECTION INPUT ;
    USE SIGNAL ;
    PORT
      LAYER M5 ;
        RECT  52.704 0 52.728 0.192 ;
    END
  END di[395]
  PIN di[396]
    DIRECTION INPUT ;
    USE SIGNAL ;
    PORT
      LAYER M3 ;
        RECT  52.848 0 52.866 0.144 ;
    END
  END di[396]
  PIN di[397]
    DIRECTION INPUT ;
    USE SIGNAL ;
    PORT
      LAYER M5 ;
        RECT  52.944 0 52.968 0.192 ;
    END
  END di[397]
  PIN di[398]
    DIRECTION INPUT ;
    USE SIGNAL ;
    PORT
      LAYER M3 ;
        RECT  53.064 0 53.082 0.144 ;
    END
  END di[398]
  PIN di[399]
    DIRECTION INPUT ;
    USE SIGNAL ;
    PORT
      LAYER M5 ;
        RECT  53.184 0 53.208 0.192 ;
    END
  END di[399]
  PIN di[39]
    DIRECTION INPUT ;
    USE SIGNAL ;
    PORT
      LAYER M5 ;
        RECT  9.12 0 9.144 0.192 ;
    END
  END di[39]
  PIN di[3]
    DIRECTION INPUT ;
    USE SIGNAL ;
    PORT
      LAYER M5 ;
        RECT  4.752 0 4.776 0.192 ;
    END
  END di[3]
  PIN di[400]
    DIRECTION INPUT ;
    USE SIGNAL ;
    PORT
      LAYER M3 ;
        RECT  53.316 0 53.334 0.144 ;
    END
  END di[400]
  PIN di[401]
    DIRECTION INPUT ;
    USE SIGNAL ;
    PORT
      LAYER M5 ;
        RECT  53.424 0 53.448 0.192 ;
    END
  END di[401]
  PIN di[402]
    DIRECTION INPUT ;
    USE SIGNAL ;
    PORT
      LAYER M3 ;
        RECT  53.568 0 53.586 0.144 ;
    END
  END di[402]
  PIN di[403]
    DIRECTION INPUT ;
    USE SIGNAL ;
    PORT
      LAYER M5 ;
        RECT  53.664 0 53.688 0.192 ;
    END
  END di[403]
  PIN di[404]
    DIRECTION INPUT ;
    USE SIGNAL ;
    PORT
      LAYER M3 ;
        RECT  53.82 0 53.838 0.144 ;
    END
  END di[404]
  PIN di[405]
    DIRECTION INPUT ;
    USE SIGNAL ;
    PORT
      LAYER M5 ;
        RECT  53.952 0 53.976 0.192 ;
    END
  END di[405]
  PIN di[406]
    DIRECTION INPUT ;
    USE SIGNAL ;
    PORT
      LAYER M3 ;
        RECT  54.072 0 54.09 0.144 ;
    END
  END di[406]
  PIN di[407]
    DIRECTION INPUT ;
    USE SIGNAL ;
    PORT
      LAYER M5 ;
        RECT  54.192 0 54.216 0.192 ;
    END
  END di[407]
  PIN di[408]
    DIRECTION INPUT ;
    USE SIGNAL ;
    PORT
      LAYER M3 ;
        RECT  54.288 0 54.306 0.144 ;
    END
  END di[408]
  PIN di[409]
    DIRECTION INPUT ;
    USE SIGNAL ;
    PORT
      LAYER M5 ;
        RECT  54.432 0 54.456 0.192 ;
    END
  END di[409]
  PIN di[40]
    DIRECTION INPUT ;
    USE SIGNAL ;
    PORT
      LAYER M3 ;
        RECT  9.252 0 9.27 0.144 ;
    END
  END di[40]
  PIN di[410]
    DIRECTION INPUT ;
    USE SIGNAL ;
    PORT
      LAYER M3 ;
        RECT  54.54 0 54.558 0.144 ;
    END
  END di[410]
  PIN di[411]
    DIRECTION INPUT ;
    USE SIGNAL ;
    PORT
      LAYER M5 ;
        RECT  54.672 0 54.696 0.192 ;
    END
  END di[411]
  PIN di[412]
    DIRECTION INPUT ;
    USE SIGNAL ;
    PORT
      LAYER M3 ;
        RECT  54.792 0 54.81 0.144 ;
    END
  END di[412]
  PIN di[413]
    DIRECTION INPUT ;
    USE SIGNAL ;
    PORT
      LAYER M5 ;
        RECT  54.912 0 54.936 0.192 ;
    END
  END di[413]
  PIN di[414]
    DIRECTION INPUT ;
    USE SIGNAL ;
    PORT
      LAYER M3 ;
        RECT  55.044 0 55.062 0.144 ;
    END
  END di[414]
  PIN di[415]
    DIRECTION INPUT ;
    USE SIGNAL ;
    PORT
      LAYER M5 ;
        RECT  55.152 0 55.176 0.192 ;
    END
  END di[415]
  PIN di[416]
    DIRECTION INPUT ;
    USE SIGNAL ;
    PORT
      LAYER M3 ;
        RECT  55.296 0 55.314 0.144 ;
    END
  END di[416]
  PIN di[417]
    DIRECTION INPUT ;
    USE SIGNAL ;
    PORT
      LAYER M5 ;
        RECT  55.392 0 55.416 0.192 ;
    END
  END di[417]
  PIN di[418]
    DIRECTION INPUT ;
    USE SIGNAL ;
    PORT
      LAYER M3 ;
        RECT  55.512 0 55.53 0.144 ;
    END
  END di[418]
  PIN di[419]
    DIRECTION INPUT ;
    USE SIGNAL ;
    PORT
      LAYER M5 ;
        RECT  55.632 0 55.656 0.192 ;
    END
  END di[419]
  PIN di[41]
    DIRECTION INPUT ;
    USE SIGNAL ;
    PORT
      LAYER M5 ;
        RECT  9.408 0 9.432 0.192 ;
    END
  END di[41]
  PIN di[420]
    DIRECTION INPUT ;
    USE SIGNAL ;
    PORT
      LAYER M3 ;
        RECT  55.764 0 55.782 0.144 ;
    END
  END di[420]
  PIN di[421]
    DIRECTION INPUT ;
    USE SIGNAL ;
    PORT
      LAYER M5 ;
        RECT  55.872 0 55.896 0.192 ;
    END
  END di[421]
  PIN di[422]
    DIRECTION INPUT ;
    USE SIGNAL ;
    PORT
      LAYER M3 ;
        RECT  56.016 0 56.034 0.144 ;
    END
  END di[422]
  PIN di[423]
    DIRECTION INPUT ;
    USE SIGNAL ;
    PORT
      LAYER M5 ;
        RECT  56.112 0 56.136 0.192 ;
    END
  END di[423]
  PIN di[424]
    DIRECTION INPUT ;
    USE SIGNAL ;
    PORT
      LAYER M3 ;
        RECT  56.268 0 56.286 0.144 ;
    END
  END di[424]
  PIN di[425]
    DIRECTION INPUT ;
    USE SIGNAL ;
    PORT
      LAYER M5 ;
        RECT  56.4 0 56.424 0.192 ;
    END
  END di[425]
  PIN di[426]
    DIRECTION INPUT ;
    USE SIGNAL ;
    PORT
      LAYER M3 ;
        RECT  56.52 0 56.538 0.144 ;
    END
  END di[426]
  PIN di[427]
    DIRECTION INPUT ;
    USE SIGNAL ;
    PORT
      LAYER M5 ;
        RECT  56.64 0 56.664 0.192 ;
    END
  END di[427]
  PIN di[428]
    DIRECTION INPUT ;
    USE SIGNAL ;
    PORT
      LAYER M3 ;
        RECT  56.736 0 56.754 0.144 ;
    END
  END di[428]
  PIN di[429]
    DIRECTION INPUT ;
    USE SIGNAL ;
    PORT
      LAYER M5 ;
        RECT  56.88 0 56.904 0.192 ;
    END
  END di[429]
  PIN di[42]
    DIRECTION INPUT ;
    USE SIGNAL ;
    PORT
      LAYER M3 ;
        RECT  9.504 0 9.522 0.144 ;
    END
  END di[42]
  PIN di[430]
    DIRECTION INPUT ;
    USE SIGNAL ;
    PORT
      LAYER M3 ;
        RECT  56.988 0 57.006 0.144 ;
    END
  END di[430]
  PIN di[431]
    DIRECTION INPUT ;
    USE SIGNAL ;
    PORT
      LAYER M5 ;
        RECT  57.12 0 57.144 0.192 ;
    END
  END di[431]
  PIN di[432]
    DIRECTION INPUT ;
    USE SIGNAL ;
    PORT
      LAYER M3 ;
        RECT  57.24 0 57.258 0.144 ;
    END
  END di[432]
  PIN di[433]
    DIRECTION INPUT ;
    USE SIGNAL ;
    PORT
      LAYER M5 ;
        RECT  57.36 0 57.384 0.192 ;
    END
  END di[433]
  PIN di[434]
    DIRECTION INPUT ;
    USE SIGNAL ;
    PORT
      LAYER M3 ;
        RECT  57.492 0 57.51 0.144 ;
    END
  END di[434]
  PIN di[435]
    DIRECTION INPUT ;
    USE SIGNAL ;
    PORT
      LAYER M5 ;
        RECT  57.6 0 57.624 0.192 ;
    END
  END di[435]
  PIN di[436]
    DIRECTION INPUT ;
    USE SIGNAL ;
    PORT
      LAYER M3 ;
        RECT  57.744 0 57.762 0.144 ;
    END
  END di[436]
  PIN di[437]
    DIRECTION INPUT ;
    USE SIGNAL ;
    PORT
      LAYER M5 ;
        RECT  57.84 0 57.864 0.192 ;
    END
  END di[437]
  PIN di[438]
    DIRECTION INPUT ;
    USE SIGNAL ;
    PORT
      LAYER M3 ;
        RECT  57.96 0 57.978 0.144 ;
    END
  END di[438]
  PIN di[439]
    DIRECTION INPUT ;
    USE SIGNAL ;
    PORT
      LAYER M5 ;
        RECT  58.08 0 58.104 0.192 ;
    END
  END di[439]
  PIN di[43]
    DIRECTION INPUT ;
    USE SIGNAL ;
    PORT
      LAYER M5 ;
        RECT  9.648 0 9.672 0.192 ;
    END
  END di[43]
  PIN di[440]
    DIRECTION INPUT ;
    USE SIGNAL ;
    PORT
      LAYER M3 ;
        RECT  58.212 0 58.23 0.144 ;
    END
  END di[440]
  PIN di[441]
    DIRECTION INPUT ;
    USE SIGNAL ;
    PORT
      LAYER M5 ;
        RECT  58.32 0 58.344 0.192 ;
    END
  END di[441]
  PIN di[442]
    DIRECTION INPUT ;
    USE SIGNAL ;
    PORT
      LAYER M3 ;
        RECT  58.464 0 58.482 0.144 ;
    END
  END di[442]
  PIN di[443]
    DIRECTION INPUT ;
    USE SIGNAL ;
    PORT
      LAYER M5 ;
        RECT  58.56 0 58.584 0.192 ;
    END
  END di[443]
  PIN di[444]
    DIRECTION INPUT ;
    USE SIGNAL ;
    PORT
      LAYER M3 ;
        RECT  58.716 0 58.734 0.144 ;
    END
  END di[444]
  PIN di[445]
    DIRECTION INPUT ;
    USE SIGNAL ;
    PORT
      LAYER M5 ;
        RECT  58.848 0 58.872 0.192 ;
    END
  END di[445]
  PIN di[446]
    DIRECTION INPUT ;
    USE SIGNAL ;
    PORT
      LAYER M3 ;
        RECT  58.932 0 58.95 0.144 ;
    END
  END di[446]
  PIN di[447]
    DIRECTION INPUT ;
    USE SIGNAL ;
    PORT
      LAYER M5 ;
        RECT  59.088 0 59.112 0.192 ;
    END
  END di[447]
  PIN di[448]
    DIRECTION INPUT ;
    USE SIGNAL ;
    PORT
      LAYER M3 ;
        RECT  59.184 0 59.202 0.144 ;
    END
  END di[448]
  PIN di[449]
    DIRECTION INPUT ;
    USE SIGNAL ;
    PORT
      LAYER M5 ;
        RECT  59.328 0 59.352 0.192 ;
    END
  END di[449]
  PIN di[44]
    DIRECTION INPUT ;
    USE SIGNAL ;
    PORT
      LAYER M3 ;
        RECT  9.756 0 9.774 0.144 ;
    END
  END di[44]
  PIN di[450]
    DIRECTION INPUT ;
    USE SIGNAL ;
    PORT
      LAYER M3 ;
        RECT  59.436 0 59.454 0.144 ;
    END
  END di[450]
  PIN di[451]
    DIRECTION INPUT ;
    USE SIGNAL ;
    PORT
      LAYER M5 ;
        RECT  59.568 0 59.592 0.192 ;
    END
  END di[451]
  PIN di[452]
    DIRECTION INPUT ;
    USE SIGNAL ;
    PORT
      LAYER M3 ;
        RECT  59.688 0 59.706 0.144 ;
    END
  END di[452]
  PIN di[453]
    DIRECTION INPUT ;
    USE SIGNAL ;
    PORT
      LAYER M5 ;
        RECT  59.808 0 59.832 0.192 ;
    END
  END di[453]
  PIN di[454]
    DIRECTION INPUT ;
    USE SIGNAL ;
    PORT
      LAYER M3 ;
        RECT  59.94 0 59.958 0.144 ;
    END
  END di[454]
  PIN di[455]
    DIRECTION INPUT ;
    USE SIGNAL ;
    PORT
      LAYER M5 ;
        RECT  60.048 0 60.072 0.192 ;
    END
  END di[455]
  PIN di[456]
    DIRECTION INPUT ;
    USE SIGNAL ;
    PORT
      LAYER M3 ;
        RECT  60.156 0 60.174 0.144 ;
    END
  END di[456]
  PIN di[457]
    DIRECTION INPUT ;
    USE SIGNAL ;
    PORT
      LAYER M5 ;
        RECT  60.288 0 60.312 0.192 ;
    END
  END di[457]
  PIN di[458]
    DIRECTION INPUT ;
    USE SIGNAL ;
    PORT
      LAYER M3 ;
        RECT  60.408 0 60.426 0.144 ;
    END
  END di[458]
  PIN di[459]
    DIRECTION INPUT ;
    USE SIGNAL ;
    PORT
      LAYER M5 ;
        RECT  60.528 0 60.552 0.192 ;
    END
  END di[459]
  PIN di[45]
    DIRECTION INPUT ;
    USE SIGNAL ;
    PORT
      LAYER M5 ;
        RECT  9.888 0 9.912 0.192 ;
    END
  END di[45]
  PIN di[460]
    DIRECTION INPUT ;
    USE SIGNAL ;
    PORT
      LAYER M3 ;
        RECT  60.66 0 60.678 0.144 ;
    END
  END di[460]
  PIN di[461]
    DIRECTION INPUT ;
    USE SIGNAL ;
    PORT
      LAYER M5 ;
        RECT  60.768 0 60.792 0.192 ;
    END
  END di[461]
  PIN di[462]
    DIRECTION INPUT ;
    USE SIGNAL ;
    PORT
      LAYER M3 ;
        RECT  60.912 0 60.93 0.144 ;
    END
  END di[462]
  PIN di[463]
    DIRECTION INPUT ;
    USE SIGNAL ;
    PORT
      LAYER M5 ;
        RECT  61.008 0 61.032 0.192 ;
    END
  END di[463]
  PIN di[464]
    DIRECTION INPUT ;
    USE SIGNAL ;
    PORT
      LAYER M3 ;
        RECT  61.164 0 61.182 0.144 ;
    END
  END di[464]
  PIN di[465]
    DIRECTION INPUT ;
    USE SIGNAL ;
    PORT
      LAYER M5 ;
        RECT  61.248 0 61.272 0.192 ;
    END
  END di[465]
  PIN di[466]
    DIRECTION INPUT ;
    USE SIGNAL ;
    PORT
      LAYER M3 ;
        RECT  61.38 0 61.398 0.144 ;
    END
  END di[466]
  PIN di[467]
    DIRECTION INPUT ;
    USE SIGNAL ;
    PORT
      LAYER M5 ;
        RECT  61.536 0 61.56 0.192 ;
    END
  END di[467]
  PIN di[468]
    DIRECTION INPUT ;
    USE SIGNAL ;
    PORT
      LAYER M3 ;
        RECT  61.632 0 61.65 0.144 ;
    END
  END di[468]
  PIN di[469]
    DIRECTION INPUT ;
    USE SIGNAL ;
    PORT
      LAYER M5 ;
        RECT  61.776 0 61.8 0.192 ;
    END
  END di[469]
  PIN di[46]
    DIRECTION INPUT ;
    USE SIGNAL ;
    PORT
      LAYER M3 ;
        RECT  10.008 0 10.026 0.144 ;
    END
  END di[46]
  PIN di[470]
    DIRECTION INPUT ;
    USE SIGNAL ;
    PORT
      LAYER M3 ;
        RECT  61.884 0 61.902 0.144 ;
    END
  END di[470]
  PIN di[471]
    DIRECTION INPUT ;
    USE SIGNAL ;
    PORT
      LAYER M5 ;
        RECT  62.016 0 62.04 0.192 ;
    END
  END di[471]
  PIN di[472]
    DIRECTION INPUT ;
    USE SIGNAL ;
    PORT
      LAYER M3 ;
        RECT  62.136 0 62.154 0.144 ;
    END
  END di[472]
  PIN di[473]
    DIRECTION INPUT ;
    USE SIGNAL ;
    PORT
      LAYER M5 ;
        RECT  62.256 0 62.28 0.192 ;
    END
  END di[473]
  PIN di[474]
    DIRECTION INPUT ;
    USE SIGNAL ;
    PORT
      LAYER M3 ;
        RECT  62.388 0 62.406 0.144 ;
    END
  END di[474]
  PIN di[475]
    DIRECTION INPUT ;
    USE SIGNAL ;
    PORT
      LAYER M5 ;
        RECT  62.496 0 62.52 0.192 ;
    END
  END di[475]
  PIN di[476]
    DIRECTION INPUT ;
    USE SIGNAL ;
    PORT
      LAYER M3 ;
        RECT  62.604 0 62.622 0.144 ;
    END
  END di[476]
  PIN di[477]
    DIRECTION INPUT ;
    USE SIGNAL ;
    PORT
      LAYER M5 ;
        RECT  62.736 0 62.76 0.192 ;
    END
  END di[477]
  PIN di[478]
    DIRECTION INPUT ;
    USE SIGNAL ;
    PORT
      LAYER M3 ;
        RECT  62.856 0 62.874 0.144 ;
    END
  END di[478]
  PIN di[479]
    DIRECTION INPUT ;
    USE SIGNAL ;
    PORT
      LAYER M5 ;
        RECT  62.976 0 63 0.192 ;
    END
  END di[479]
  PIN di[47]
    DIRECTION INPUT ;
    USE SIGNAL ;
    PORT
      LAYER M5 ;
        RECT  10.128 0 10.152 0.192 ;
    END
  END di[47]
  PIN di[480]
    DIRECTION INPUT ;
    USE SIGNAL ;
    PORT
      LAYER M3 ;
        RECT  63.108 0 63.126 0.144 ;
    END
  END di[480]
  PIN di[481]
    DIRECTION INPUT ;
    USE SIGNAL ;
    PORT
      LAYER M5 ;
        RECT  63.216 0 63.24 0.192 ;
    END
  END di[481]
  PIN di[482]
    DIRECTION INPUT ;
    USE SIGNAL ;
    PORT
      LAYER M3 ;
        RECT  63.36 0 63.378 0.144 ;
    END
  END di[482]
  PIN di[483]
    DIRECTION INPUT ;
    USE SIGNAL ;
    PORT
      LAYER M5 ;
        RECT  63.456 0 63.48 0.192 ;
    END
  END di[483]
  PIN di[484]
    DIRECTION INPUT ;
    USE SIGNAL ;
    PORT
      LAYER M3 ;
        RECT  63.612 0 63.63 0.144 ;
    END
  END di[484]
  PIN di[485]
    DIRECTION INPUT ;
    USE SIGNAL ;
    PORT
      LAYER M5 ;
        RECT  63.696 0 63.72 0.192 ;
    END
  END di[485]
  PIN di[486]
    DIRECTION INPUT ;
    USE SIGNAL ;
    PORT
      LAYER M3 ;
        RECT  63.828 0 63.846 0.144 ;
    END
  END di[486]
  PIN di[487]
    DIRECTION INPUT ;
    USE SIGNAL ;
    PORT
      LAYER M5 ;
        RECT  63.984 0 64.008 0.192 ;
    END
  END di[487]
  PIN di[488]
    DIRECTION INPUT ;
    USE SIGNAL ;
    PORT
      LAYER M3 ;
        RECT  64.08 0 64.098 0.144 ;
    END
  END di[488]
  PIN di[489]
    DIRECTION INPUT ;
    USE SIGNAL ;
    PORT
      LAYER M5 ;
        RECT  64.224 0 64.248 0.192 ;
    END
  END di[489]
  PIN di[48]
    DIRECTION INPUT ;
    USE SIGNAL ;
    PORT
      LAYER M3 ;
        RECT  10.26 0 10.278 0.144 ;
    END
  END di[48]
  PIN di[490]
    DIRECTION INPUT ;
    USE SIGNAL ;
    PORT
      LAYER M3 ;
        RECT  64.332 0 64.35 0.144 ;
    END
  END di[490]
  PIN di[491]
    DIRECTION INPUT ;
    USE SIGNAL ;
    PORT
      LAYER M5 ;
        RECT  64.464 0 64.488 0.192 ;
    END
  END di[491]
  PIN di[492]
    DIRECTION INPUT ;
    USE SIGNAL ;
    PORT
      LAYER M3 ;
        RECT  64.584 0 64.602 0.144 ;
    END
  END di[492]
  PIN di[493]
    DIRECTION INPUT ;
    USE SIGNAL ;
    PORT
      LAYER M5 ;
        RECT  64.704 0 64.728 0.192 ;
    END
  END di[493]
  PIN di[494]
    DIRECTION INPUT ;
    USE SIGNAL ;
    PORT
      LAYER M3 ;
        RECT  64.836 0 64.854 0.144 ;
    END
  END di[494]
  PIN di[495]
    DIRECTION INPUT ;
    USE SIGNAL ;
    PORT
      LAYER M5 ;
        RECT  64.944 0 64.968 0.192 ;
    END
  END di[495]
  PIN di[496]
    DIRECTION INPUT ;
    USE SIGNAL ;
    PORT
      LAYER M3 ;
        RECT  65.052 0 65.07 0.144 ;
    END
  END di[496]
  PIN di[497]
    DIRECTION INPUT ;
    USE SIGNAL ;
    PORT
      LAYER M5 ;
        RECT  65.184 0 65.208 0.192 ;
    END
  END di[497]
  PIN di[498]
    DIRECTION INPUT ;
    USE SIGNAL ;
    PORT
      LAYER M3 ;
        RECT  65.304 0 65.322 0.144 ;
    END
  END di[498]
  PIN di[499]
    DIRECTION INPUT ;
    USE SIGNAL ;
    PORT
      LAYER M5 ;
        RECT  65.424 0 65.448 0.192 ;
    END
  END di[499]
  PIN di[49]
    DIRECTION INPUT ;
    USE SIGNAL ;
    PORT
      LAYER M5 ;
        RECT  10.368 0 10.392 0.192 ;
    END
  END di[49]
  PIN di[4]
    DIRECTION INPUT ;
    USE SIGNAL ;
    PORT
      LAYER M3 ;
        RECT  4.86 0 4.878 0.144 ;
    END
  END di[4]
  PIN di[500]
    DIRECTION INPUT ;
    USE SIGNAL ;
    PORT
      LAYER M3 ;
        RECT  65.556 0 65.574 0.144 ;
    END
  END di[500]
  PIN di[501]
    DIRECTION INPUT ;
    USE SIGNAL ;
    PORT
      LAYER M5 ;
        RECT  65.664 0 65.688 0.192 ;
    END
  END di[501]
  PIN di[502]
    DIRECTION INPUT ;
    USE SIGNAL ;
    PORT
      LAYER M3 ;
        RECT  65.808 0 65.826 0.144 ;
    END
  END di[502]
  PIN di[503]
    DIRECTION INPUT ;
    USE SIGNAL ;
    PORT
      LAYER M5 ;
        RECT  65.904 0 65.928 0.192 ;
    END
  END di[503]
  PIN di[504]
    DIRECTION INPUT ;
    USE SIGNAL ;
    PORT
      LAYER M3 ;
        RECT  66.06 0 66.078 0.144 ;
    END
  END di[504]
  PIN di[505]
    DIRECTION INPUT ;
    USE SIGNAL ;
    PORT
      LAYER M5 ;
        RECT  66.144 0 66.168 0.192 ;
    END
  END di[505]
  PIN di[506]
    DIRECTION INPUT ;
    USE SIGNAL ;
    PORT
      LAYER M3 ;
        RECT  66.276 0 66.294 0.144 ;
    END
  END di[506]
  PIN di[507]
    DIRECTION INPUT ;
    USE SIGNAL ;
    PORT
      LAYER M5 ;
        RECT  66.432 0 66.456 0.192 ;
    END
  END di[507]
  PIN di[508]
    DIRECTION INPUT ;
    USE SIGNAL ;
    PORT
      LAYER M3 ;
        RECT  66.528 0 66.546 0.144 ;
    END
  END di[508]
  PIN di[509]
    DIRECTION INPUT ;
    USE SIGNAL ;
    PORT
      LAYER M5 ;
        RECT  66.672 0 66.696 0.192 ;
    END
  END di[509]
  PIN di[50]
    DIRECTION INPUT ;
    USE SIGNAL ;
    PORT
      LAYER M3 ;
        RECT  10.476 0 10.494 0.144 ;
    END
  END di[50]
  PIN di[510]
    DIRECTION INPUT ;
    USE SIGNAL ;
    PORT
      LAYER M3 ;
        RECT  66.78 0 66.798 0.144 ;
    END
  END di[510]
  PIN di[511]
    DIRECTION INPUT ;
    USE SIGNAL ;
    PORT
      LAYER M5 ;
        RECT  66.912 0 66.936 0.192 ;
    END
  END di[511]
  PIN di[512]
    DIRECTION INPUT ;
    USE SIGNAL ;
    PORT
      LAYER M3 ;
        RECT  67.032 0 67.05 0.144 ;
    END
  END di[512]
  PIN di[513]
    DIRECTION INPUT ;
    USE SIGNAL ;
    PORT
      LAYER M5 ;
        RECT  67.152 0 67.176 0.192 ;
    END
  END di[513]
  PIN di[514]
    DIRECTION INPUT ;
    USE SIGNAL ;
    PORT
      LAYER M3 ;
        RECT  67.284 0 67.302 0.144 ;
    END
  END di[514]
  PIN di[515]
    DIRECTION INPUT ;
    USE SIGNAL ;
    PORT
      LAYER M5 ;
        RECT  67.392 0 67.416 0.192 ;
    END
  END di[515]
  PIN di[516]
    DIRECTION INPUT ;
    USE SIGNAL ;
    PORT
      LAYER M3 ;
        RECT  67.5 0 67.518 0.144 ;
    END
  END di[516]
  PIN di[517]
    DIRECTION INPUT ;
    USE SIGNAL ;
    PORT
      LAYER M5 ;
        RECT  67.632 0 67.656 0.192 ;
    END
  END di[517]
  PIN di[518]
    DIRECTION INPUT ;
    USE SIGNAL ;
    PORT
      LAYER M3 ;
        RECT  67.752 0 67.77 0.144 ;
    END
  END di[518]
  PIN di[519]
    DIRECTION INPUT ;
    USE SIGNAL ;
    PORT
      LAYER M5 ;
        RECT  67.872 0 67.896 0.192 ;
    END
  END di[519]
  PIN di[51]
    DIRECTION INPUT ;
    USE SIGNAL ;
    PORT
      LAYER M5 ;
        RECT  10.608 0 10.632 0.192 ;
    END
  END di[51]
  PIN di[520]
    DIRECTION INPUT ;
    USE SIGNAL ;
    PORT
      LAYER M3 ;
        RECT  68.004 0 68.022 0.144 ;
    END
  END di[520]
  PIN di[521]
    DIRECTION INPUT ;
    USE SIGNAL ;
    PORT
      LAYER M5 ;
        RECT  68.112 0 68.136 0.192 ;
    END
  END di[521]
  PIN di[522]
    DIRECTION INPUT ;
    USE SIGNAL ;
    PORT
      LAYER M3 ;
        RECT  68.256 0 68.274 0.144 ;
    END
  END di[522]
  PIN di[523]
    DIRECTION INPUT ;
    USE SIGNAL ;
    PORT
      LAYER M5 ;
        RECT  68.352 0 68.376 0.192 ;
    END
  END di[523]
  PIN di[524]
    DIRECTION INPUT ;
    USE SIGNAL ;
    PORT
      LAYER M3 ;
        RECT  68.508 0 68.526 0.144 ;
    END
  END di[524]
  PIN di[525]
    DIRECTION INPUT ;
    USE SIGNAL ;
    PORT
      LAYER M5 ;
        RECT  68.592 0 68.616 0.192 ;
    END
  END di[525]
  PIN di[526]
    DIRECTION INPUT ;
    USE SIGNAL ;
    PORT
      LAYER M3 ;
        RECT  68.724 0 68.742 0.144 ;
    END
  END di[526]
  PIN di[527]
    DIRECTION INPUT ;
    USE SIGNAL ;
    PORT
      LAYER M5 ;
        RECT  68.88 0 68.904 0.192 ;
    END
  END di[527]
  PIN di[528]
    DIRECTION INPUT ;
    USE SIGNAL ;
    PORT
      LAYER M3 ;
        RECT  68.976 0 68.994 0.144 ;
    END
  END di[528]
  PIN di[529]
    DIRECTION INPUT ;
    USE SIGNAL ;
    PORT
      LAYER M5 ;
        RECT  69.12 0 69.144 0.192 ;
    END
  END di[529]
  PIN di[52]
    DIRECTION INPUT ;
    USE SIGNAL ;
    PORT
      LAYER M3 ;
        RECT  10.728 0 10.746 0.144 ;
    END
  END di[52]
  PIN di[530]
    DIRECTION INPUT ;
    USE SIGNAL ;
    PORT
      LAYER M3 ;
        RECT  69.228 0 69.246 0.144 ;
    END
  END di[530]
  PIN di[531]
    DIRECTION INPUT ;
    USE SIGNAL ;
    PORT
      LAYER M5 ;
        RECT  69.36 0 69.384 0.192 ;
    END
  END di[531]
  PIN di[532]
    DIRECTION INPUT ;
    USE SIGNAL ;
    PORT
      LAYER M3 ;
        RECT  69.48 0 69.498 0.144 ;
    END
  END di[532]
  PIN di[533]
    DIRECTION INPUT ;
    USE SIGNAL ;
    PORT
      LAYER M5 ;
        RECT  69.6 0 69.624 0.192 ;
    END
  END di[533]
  PIN di[534]
    DIRECTION INPUT ;
    USE SIGNAL ;
    PORT
      LAYER M3 ;
        RECT  69.732 0 69.75 0.144 ;
    END
  END di[534]
  PIN di[535]
    DIRECTION INPUT ;
    USE SIGNAL ;
    PORT
      LAYER M5 ;
        RECT  69.84 0 69.864 0.192 ;
    END
  END di[535]
  PIN di[536]
    DIRECTION INPUT ;
    USE SIGNAL ;
    PORT
      LAYER M3 ;
        RECT  69.948 0 69.966 0.144 ;
    END
  END di[536]
  PIN di[537]
    DIRECTION INPUT ;
    USE SIGNAL ;
    PORT
      LAYER M5 ;
        RECT  70.08 0 70.104 0.192 ;
    END
  END di[537]
  PIN di[538]
    DIRECTION INPUT ;
    USE SIGNAL ;
    PORT
      LAYER M3 ;
        RECT  70.2 0 70.218 0.144 ;
    END
  END di[538]
  PIN di[539]
    DIRECTION INPUT ;
    USE SIGNAL ;
    PORT
      LAYER M5 ;
        RECT  70.32 0 70.344 0.192 ;
    END
  END di[539]
  PIN di[53]
    DIRECTION INPUT ;
    USE SIGNAL ;
    PORT
      LAYER M5 ;
        RECT  10.848 0 10.872 0.192 ;
    END
  END di[53]
  PIN di[540]
    DIRECTION INPUT ;
    USE SIGNAL ;
    PORT
      LAYER M3 ;
        RECT  70.452 0 70.47 0.144 ;
    END
  END di[540]
  PIN di[541]
    DIRECTION INPUT ;
    USE SIGNAL ;
    PORT
      LAYER M5 ;
        RECT  70.56 0 70.584 0.192 ;
    END
  END di[541]
  PIN di[542]
    DIRECTION INPUT ;
    USE SIGNAL ;
    PORT
      LAYER M3 ;
        RECT  70.704 0 70.722 0.144 ;
    END
  END di[542]
  PIN di[543]
    DIRECTION INPUT ;
    USE SIGNAL ;
    PORT
      LAYER M5 ;
        RECT  70.8 0 70.824 0.192 ;
    END
  END di[543]
  PIN di[544]
    DIRECTION INPUT ;
    USE SIGNAL ;
    PORT
      LAYER M3 ;
        RECT  70.956 0 70.974 0.144 ;
    END
  END di[544]
  PIN di[545]
    DIRECTION INPUT ;
    USE SIGNAL ;
    PORT
      LAYER M5 ;
        RECT  71.04 0 71.064 0.192 ;
    END
  END di[545]
  PIN di[546]
    DIRECTION INPUT ;
    USE SIGNAL ;
    PORT
      LAYER M3 ;
        RECT  71.172 0 71.19 0.144 ;
    END
  END di[546]
  PIN di[547]
    DIRECTION INPUT ;
    USE SIGNAL ;
    PORT
      LAYER M5 ;
        RECT  71.328 0 71.352 0.192 ;
    END
  END di[547]
  PIN di[548]
    DIRECTION INPUT ;
    USE SIGNAL ;
    PORT
      LAYER M3 ;
        RECT  71.424 0 71.442 0.144 ;
    END
  END di[548]
  PIN di[549]
    DIRECTION INPUT ;
    USE SIGNAL ;
    PORT
      LAYER M5 ;
        RECT  71.568 0 71.592 0.192 ;
    END
  END di[549]
  PIN di[54]
    DIRECTION INPUT ;
    USE SIGNAL ;
    PORT
      LAYER M3 ;
        RECT  10.98 0 10.998 0.144 ;
    END
  END di[54]
  PIN di[550]
    DIRECTION INPUT ;
    USE SIGNAL ;
    PORT
      LAYER M3 ;
        RECT  71.676 0 71.694 0.144 ;
    END
  END di[550]
  PIN di[551]
    DIRECTION INPUT ;
    USE SIGNAL ;
    PORT
      LAYER M5 ;
        RECT  71.808 0 71.832 0.192 ;
    END
  END di[551]
  PIN di[552]
    DIRECTION INPUT ;
    USE SIGNAL ;
    PORT
      LAYER M3 ;
        RECT  71.928 0 71.946 0.144 ;
    END
  END di[552]
  PIN di[553]
    DIRECTION INPUT ;
    USE SIGNAL ;
    PORT
      LAYER M5 ;
        RECT  72.048 0 72.072 0.192 ;
    END
  END di[553]
  PIN di[554]
    DIRECTION INPUT ;
    USE SIGNAL ;
    PORT
      LAYER M3 ;
        RECT  72.18 0 72.198 0.144 ;
    END
  END di[554]
  PIN di[555]
    DIRECTION INPUT ;
    USE SIGNAL ;
    PORT
      LAYER M5 ;
        RECT  72.288 0 72.312 0.192 ;
    END
  END di[555]
  PIN di[556]
    DIRECTION INPUT ;
    USE SIGNAL ;
    PORT
      LAYER M3 ;
        RECT  72.396 0 72.414 0.144 ;
    END
  END di[556]
  PIN di[557]
    DIRECTION INPUT ;
    USE SIGNAL ;
    PORT
      LAYER M5 ;
        RECT  72.528 0 72.552 0.192 ;
    END
  END di[557]
  PIN di[558]
    DIRECTION INPUT ;
    USE SIGNAL ;
    PORT
      LAYER M3 ;
        RECT  72.648 0 72.666 0.144 ;
    END
  END di[558]
  PIN di[559]
    DIRECTION INPUT ;
    USE SIGNAL ;
    PORT
      LAYER M5 ;
        RECT  72.768 0 72.792 0.192 ;
    END
  END di[559]
  PIN di[55]
    DIRECTION INPUT ;
    USE SIGNAL ;
    PORT
      LAYER M5 ;
        RECT  11.088 0 11.112 0.192 ;
    END
  END di[55]
  PIN di[560]
    DIRECTION INPUT ;
    USE SIGNAL ;
    PORT
      LAYER M3 ;
        RECT  72.9 0 72.918 0.144 ;
    END
  END di[560]
  PIN di[561]
    DIRECTION INPUT ;
    USE SIGNAL ;
    PORT
      LAYER M5 ;
        RECT  73.008 0 73.032 0.192 ;
    END
  END di[561]
  PIN di[562]
    DIRECTION INPUT ;
    USE SIGNAL ;
    PORT
      LAYER M3 ;
        RECT  73.152 0 73.17 0.144 ;
    END
  END di[562]
  PIN di[563]
    DIRECTION INPUT ;
    USE SIGNAL ;
    PORT
      LAYER M5 ;
        RECT  73.248 0 73.272 0.192 ;
    END
  END di[563]
  PIN di[564]
    DIRECTION INPUT ;
    USE SIGNAL ;
    PORT
      LAYER M3 ;
        RECT  73.404 0 73.422 0.144 ;
    END
  END di[564]
  PIN di[565]
    DIRECTION INPUT ;
    USE SIGNAL ;
    PORT
      LAYER M5 ;
        RECT  73.488 0 73.512 0.192 ;
    END
  END di[565]
  PIN di[566]
    DIRECTION INPUT ;
    USE SIGNAL ;
    PORT
      LAYER M3 ;
        RECT  73.62 0 73.638 0.144 ;
    END
  END di[566]
  PIN di[567]
    DIRECTION INPUT ;
    USE SIGNAL ;
    PORT
      LAYER M5 ;
        RECT  73.776 0 73.8 0.192 ;
    END
  END di[567]
  PIN di[568]
    DIRECTION INPUT ;
    USE SIGNAL ;
    PORT
      LAYER M3 ;
        RECT  73.872 0 73.89 0.144 ;
    END
  END di[568]
  PIN di[569]
    DIRECTION INPUT ;
    USE SIGNAL ;
    PORT
      LAYER M5 ;
        RECT  74.016 0 74.04 0.192 ;
    END
  END di[569]
  PIN di[56]
    DIRECTION INPUT ;
    USE SIGNAL ;
    PORT
      LAYER M3 ;
        RECT  11.232 0 11.25 0.144 ;
    END
  END di[56]
  PIN di[570]
    DIRECTION INPUT ;
    USE SIGNAL ;
    PORT
      LAYER M3 ;
        RECT  74.124 0 74.142 0.144 ;
    END
  END di[570]
  PIN di[571]
    DIRECTION INPUT ;
    USE SIGNAL ;
    PORT
      LAYER M5 ;
        RECT  74.256 0 74.28 0.192 ;
    END
  END di[571]
  PIN di[572]
    DIRECTION INPUT ;
    USE SIGNAL ;
    PORT
      LAYER M3 ;
        RECT  74.376 0 74.394 0.144 ;
    END
  END di[572]
  PIN di[573]
    DIRECTION INPUT ;
    USE SIGNAL ;
    PORT
      LAYER M5 ;
        RECT  74.496 0 74.52 0.192 ;
    END
  END di[573]
  PIN di[574]
    DIRECTION INPUT ;
    USE SIGNAL ;
    PORT
      LAYER M3 ;
        RECT  74.628 0 74.646 0.144 ;
    END
  END di[574]
  PIN di[575]
    DIRECTION INPUT ;
    USE SIGNAL ;
    PORT
      LAYER M5 ;
        RECT  74.736 0 74.76 0.192 ;
    END
  END di[575]
  PIN di[576]
    DIRECTION INPUT ;
    USE SIGNAL ;
    PORT
      LAYER M3 ;
        RECT  74.844 0 74.862 0.144 ;
    END
  END di[576]
  PIN di[577]
    DIRECTION INPUT ;
    USE SIGNAL ;
    PORT
      LAYER M5 ;
        RECT  74.976 0 75 0.192 ;
    END
  END di[577]
  PIN di[578]
    DIRECTION INPUT ;
    USE SIGNAL ;
    PORT
      LAYER M3 ;
        RECT  75.096 0 75.114 0.144 ;
    END
  END di[578]
  PIN di[579]
    DIRECTION INPUT ;
    USE SIGNAL ;
    PORT
      LAYER M5 ;
        RECT  75.216 0 75.24 0.192 ;
    END
  END di[579]
  PIN di[57]
    DIRECTION INPUT ;
    USE SIGNAL ;
    PORT
      LAYER M5 ;
        RECT  11.328 0 11.352 0.192 ;
    END
  END di[57]
  PIN di[580]
    DIRECTION INPUT ;
    USE SIGNAL ;
    PORT
      LAYER M3 ;
        RECT  75.348 0 75.366 0.144 ;
    END
  END di[580]
  PIN di[581]
    DIRECTION INPUT ;
    USE SIGNAL ;
    PORT
      LAYER M5 ;
        RECT  75.456 0 75.48 0.192 ;
    END
  END di[581]
  PIN di[582]
    DIRECTION INPUT ;
    USE SIGNAL ;
    PORT
      LAYER M3 ;
        RECT  75.6 0 75.618 0.144 ;
    END
  END di[582]
  PIN di[583]
    DIRECTION INPUT ;
    USE SIGNAL ;
    PORT
      LAYER M5 ;
        RECT  75.696 0 75.72 0.192 ;
    END
  END di[583]
  PIN di[584]
    DIRECTION INPUT ;
    USE SIGNAL ;
    PORT
      LAYER M3 ;
        RECT  75.852 0 75.87 0.144 ;
    END
  END di[584]
  PIN di[585]
    DIRECTION INPUT ;
    USE SIGNAL ;
    PORT
      LAYER M5 ;
        RECT  75.936 0 75.96 0.192 ;
    END
  END di[585]
  PIN di[586]
    DIRECTION INPUT ;
    USE SIGNAL ;
    PORT
      LAYER M3 ;
        RECT  76.068 0 76.086 0.144 ;
    END
  END di[586]
  PIN di[587]
    DIRECTION INPUT ;
    USE SIGNAL ;
    PORT
      LAYER M5 ;
        RECT  76.224 0 76.248 0.192 ;
    END
  END di[587]
  PIN di[588]
    DIRECTION INPUT ;
    USE SIGNAL ;
    PORT
      LAYER M3 ;
        RECT  76.32 0 76.338 0.144 ;
    END
  END di[588]
  PIN di[589]
    DIRECTION INPUT ;
    USE SIGNAL ;
    PORT
      LAYER M5 ;
        RECT  76.464 0 76.488 0.192 ;
    END
  END di[589]
  PIN di[58]
    DIRECTION INPUT ;
    USE SIGNAL ;
    PORT
      LAYER M3 ;
        RECT  11.484 0 11.502 0.144 ;
    END
  END di[58]
  PIN di[590]
    DIRECTION INPUT ;
    USE SIGNAL ;
    PORT
      LAYER M3 ;
        RECT  76.572 0 76.59 0.144 ;
    END
  END di[590]
  PIN di[591]
    DIRECTION INPUT ;
    USE SIGNAL ;
    PORT
      LAYER M5 ;
        RECT  76.704 0 76.728 0.192 ;
    END
  END di[591]
  PIN di[592]
    DIRECTION INPUT ;
    USE SIGNAL ;
    PORT
      LAYER M3 ;
        RECT  76.824 0 76.842 0.144 ;
    END
  END di[592]
  PIN di[593]
    DIRECTION INPUT ;
    USE SIGNAL ;
    PORT
      LAYER M5 ;
        RECT  76.944 0 76.968 0.192 ;
    END
  END di[593]
  PIN di[594]
    DIRECTION INPUT ;
    USE SIGNAL ;
    PORT
      LAYER M3 ;
        RECT  77.076 0 77.094 0.144 ;
    END
  END di[594]
  PIN di[595]
    DIRECTION INPUT ;
    USE SIGNAL ;
    PORT
      LAYER M5 ;
        RECT  77.184 0 77.208 0.192 ;
    END
  END di[595]
  PIN di[596]
    DIRECTION INPUT ;
    USE SIGNAL ;
    PORT
      LAYER M3 ;
        RECT  77.292 0 77.31 0.144 ;
    END
  END di[596]
  PIN di[597]
    DIRECTION INPUT ;
    USE SIGNAL ;
    PORT
      LAYER M5 ;
        RECT  77.424 0 77.448 0.192 ;
    END
  END di[597]
  PIN di[598]
    DIRECTION INPUT ;
    USE SIGNAL ;
    PORT
      LAYER M3 ;
        RECT  77.544 0 77.562 0.144 ;
    END
  END di[598]
  PIN di[599]
    DIRECTION INPUT ;
    USE SIGNAL ;
    PORT
      LAYER M5 ;
        RECT  77.664 0 77.688 0.192 ;
    END
  END di[599]
  PIN di[59]
    DIRECTION INPUT ;
    USE SIGNAL ;
    PORT
      LAYER M5 ;
        RECT  11.568 0 11.592 0.192 ;
    END
  END di[59]
  PIN di[5]
    DIRECTION INPUT ;
    USE SIGNAL ;
    PORT
      LAYER M5 ;
        RECT  4.992 0 5.016 0.192 ;
    END
  END di[5]
  PIN di[600]
    DIRECTION INPUT ;
    USE SIGNAL ;
    PORT
      LAYER M3 ;
        RECT  77.796 0 77.814 0.144 ;
    END
  END di[600]
  PIN di[601]
    DIRECTION INPUT ;
    USE SIGNAL ;
    PORT
      LAYER M5 ;
        RECT  77.904 0 77.928 0.192 ;
    END
  END di[601]
  PIN di[602]
    DIRECTION INPUT ;
    USE SIGNAL ;
    PORT
      LAYER M3 ;
        RECT  78.048 0 78.066 0.144 ;
    END
  END di[602]
  PIN di[603]
    DIRECTION INPUT ;
    USE SIGNAL ;
    PORT
      LAYER M5 ;
        RECT  78.144 0 78.168 0.192 ;
    END
  END di[603]
  PIN di[604]
    DIRECTION INPUT ;
    USE SIGNAL ;
    PORT
      LAYER M3 ;
        RECT  78.3 0 78.318 0.144 ;
    END
  END di[604]
  PIN di[605]
    DIRECTION INPUT ;
    USE SIGNAL ;
    PORT
      LAYER M5 ;
        RECT  78.384 0 78.408 0.192 ;
    END
  END di[605]
  PIN di[606]
    DIRECTION INPUT ;
    USE SIGNAL ;
    PORT
      LAYER M3 ;
        RECT  78.516 0 78.534 0.144 ;
    END
  END di[606]
  PIN di[607]
    DIRECTION INPUT ;
    USE SIGNAL ;
    PORT
      LAYER M5 ;
        RECT  78.672 0 78.696 0.192 ;
    END
  END di[607]
  PIN di[608]
    DIRECTION INPUT ;
    USE SIGNAL ;
    PORT
      LAYER M3 ;
        RECT  78.768 0 78.786 0.144 ;
    END
  END di[608]
  PIN di[609]
    DIRECTION INPUT ;
    USE SIGNAL ;
    PORT
      LAYER M5 ;
        RECT  78.912 0 78.936 0.192 ;
    END
  END di[609]
  PIN di[60]
    DIRECTION INPUT ;
    USE SIGNAL ;
    PORT
      LAYER M3 ;
        RECT  11.7 0 11.718 0.144 ;
    END
  END di[60]
  PIN di[610]
    DIRECTION INPUT ;
    USE SIGNAL ;
    PORT
      LAYER M3 ;
        RECT  79.02 0 79.038 0.144 ;
    END
  END di[610]
  PIN di[611]
    DIRECTION INPUT ;
    USE SIGNAL ;
    PORT
      LAYER M5 ;
        RECT  79.152 0 79.176 0.192 ;
    END
  END di[611]
  PIN di[612]
    DIRECTION INPUT ;
    USE SIGNAL ;
    PORT
      LAYER M3 ;
        RECT  79.272 0 79.29 0.144 ;
    END
  END di[612]
  PIN di[613]
    DIRECTION INPUT ;
    USE SIGNAL ;
    PORT
      LAYER M5 ;
        RECT  79.392 0 79.416 0.192 ;
    END
  END di[613]
  PIN di[614]
    DIRECTION INPUT ;
    USE SIGNAL ;
    PORT
      LAYER M3 ;
        RECT  79.524 0 79.542 0.144 ;
    END
  END di[614]
  PIN di[615]
    DIRECTION INPUT ;
    USE SIGNAL ;
    PORT
      LAYER M5 ;
        RECT  79.632 0 79.656 0.192 ;
    END
  END di[615]
  PIN di[616]
    DIRECTION INPUT ;
    USE SIGNAL ;
    PORT
      LAYER M3 ;
        RECT  79.74 0 79.758 0.144 ;
    END
  END di[616]
  PIN di[617]
    DIRECTION INPUT ;
    USE SIGNAL ;
    PORT
      LAYER M5 ;
        RECT  79.872 0 79.896 0.192 ;
    END
  END di[617]
  PIN di[618]
    DIRECTION INPUT ;
    USE SIGNAL ;
    PORT
      LAYER M3 ;
        RECT  79.992 0 80.01 0.144 ;
    END
  END di[618]
  PIN di[619]
    DIRECTION INPUT ;
    USE SIGNAL ;
    PORT
      LAYER M5 ;
        RECT  80.112 0 80.136 0.192 ;
    END
  END di[619]
  PIN di[61]
    DIRECTION INPUT ;
    USE SIGNAL ;
    PORT
      LAYER M5 ;
        RECT  11.856 0 11.88 0.192 ;
    END
  END di[61]
  PIN di[620]
    DIRECTION INPUT ;
    USE SIGNAL ;
    PORT
      LAYER M3 ;
        RECT  80.244 0 80.262 0.144 ;
    END
  END di[620]
  PIN di[621]
    DIRECTION INPUT ;
    USE SIGNAL ;
    PORT
      LAYER M5 ;
        RECT  80.352 0 80.376 0.192 ;
    END
  END di[621]
  PIN di[622]
    DIRECTION INPUT ;
    USE SIGNAL ;
    PORT
      LAYER M3 ;
        RECT  80.496 0 80.514 0.144 ;
    END
  END di[622]
  PIN di[623]
    DIRECTION INPUT ;
    USE SIGNAL ;
    PORT
      LAYER M5 ;
        RECT  80.592 0 80.616 0.192 ;
    END
  END di[623]
  PIN di[624]
    DIRECTION INPUT ;
    USE SIGNAL ;
    PORT
      LAYER M3 ;
        RECT  80.748 0 80.766 0.144 ;
    END
  END di[624]
  PIN di[625]
    DIRECTION INPUT ;
    USE SIGNAL ;
    PORT
      LAYER M5 ;
        RECT  80.832 0 80.856 0.192 ;
    END
  END di[625]
  PIN di[626]
    DIRECTION INPUT ;
    USE SIGNAL ;
    PORT
      LAYER M3 ;
        RECT  80.964 0 80.982 0.144 ;
    END
  END di[626]
  PIN di[627]
    DIRECTION INPUT ;
    USE SIGNAL ;
    PORT
      LAYER M5 ;
        RECT  81.12 0 81.144 0.192 ;
    END
  END di[627]
  PIN di[628]
    DIRECTION INPUT ;
    USE SIGNAL ;
    PORT
      LAYER M3 ;
        RECT  81.216 0 81.234 0.144 ;
    END
  END di[628]
  PIN di[629]
    DIRECTION INPUT ;
    USE SIGNAL ;
    PORT
      LAYER M5 ;
        RECT  81.36 0 81.384 0.192 ;
    END
  END di[629]
  PIN di[62]
    DIRECTION INPUT ;
    USE SIGNAL ;
    PORT
      LAYER M3 ;
        RECT  11.952 0 11.97 0.144 ;
    END
  END di[62]
  PIN di[630]
    DIRECTION INPUT ;
    USE SIGNAL ;
    PORT
      LAYER M3 ;
        RECT  81.468 0 81.486 0.144 ;
    END
  END di[630]
  PIN di[631]
    DIRECTION INPUT ;
    USE SIGNAL ;
    PORT
      LAYER M5 ;
        RECT  81.6 0 81.624 0.192 ;
    END
  END di[631]
  PIN di[632]
    DIRECTION INPUT ;
    USE SIGNAL ;
    PORT
      LAYER M3 ;
        RECT  81.72 0 81.738 0.144 ;
    END
  END di[632]
  PIN di[633]
    DIRECTION INPUT ;
    USE SIGNAL ;
    PORT
      LAYER M5 ;
        RECT  81.84 0 81.864 0.192 ;
    END
  END di[633]
  PIN di[634]
    DIRECTION INPUT ;
    USE SIGNAL ;
    PORT
      LAYER M3 ;
        RECT  81.972 0 81.99 0.144 ;
    END
  END di[634]
  PIN di[635]
    DIRECTION INPUT ;
    USE SIGNAL ;
    PORT
      LAYER M5 ;
        RECT  82.08 0 82.104 0.192 ;
    END
  END di[635]
  PIN di[636]
    DIRECTION INPUT ;
    USE SIGNAL ;
    PORT
      LAYER M3 ;
        RECT  82.188 0 82.206 0.144 ;
    END
  END di[636]
  PIN di[637]
    DIRECTION INPUT ;
    USE SIGNAL ;
    PORT
      LAYER M5 ;
        RECT  82.32 0 82.344 0.192 ;
    END
  END di[637]
  PIN di[638]
    DIRECTION INPUT ;
    USE SIGNAL ;
    PORT
      LAYER M3 ;
        RECT  82.44 0 82.458 0.144 ;
    END
  END di[638]
  PIN di[639]
    DIRECTION INPUT ;
    USE SIGNAL ;
    PORT
      LAYER M5 ;
        RECT  82.56 0 82.584 0.192 ;
    END
  END di[639]
  PIN di[63]
    DIRECTION INPUT ;
    USE SIGNAL ;
    PORT
      LAYER M5 ;
        RECT  12.096 0 12.12 0.192 ;
    END
  END di[63]
  PIN di[640]
    DIRECTION INPUT ;
    USE SIGNAL ;
    PORT
      LAYER M3 ;
        RECT  82.692 0 82.71 0.144 ;
    END
  END di[640]
  PIN di[641]
    DIRECTION INPUT ;
    USE SIGNAL ;
    PORT
      LAYER M5 ;
        RECT  82.8 0 82.824 0.192 ;
    END
  END di[641]
  PIN di[642]
    DIRECTION INPUT ;
    USE SIGNAL ;
    PORT
      LAYER M3 ;
        RECT  82.944 0 82.962 0.144 ;
    END
  END di[642]
  PIN di[643]
    DIRECTION INPUT ;
    USE SIGNAL ;
    PORT
      LAYER M5 ;
        RECT  83.04 0 83.064 0.192 ;
    END
  END di[643]
  PIN di[644]
    DIRECTION INPUT ;
    USE SIGNAL ;
    PORT
      LAYER M3 ;
        RECT  83.196 0 83.214 0.144 ;
    END
  END di[644]
  PIN di[645]
    DIRECTION INPUT ;
    USE SIGNAL ;
    PORT
      LAYER M5 ;
        RECT  83.28 0 83.304 0.192 ;
    END
  END di[645]
  PIN di[646]
    DIRECTION INPUT ;
    USE SIGNAL ;
    PORT
      LAYER M3 ;
        RECT  83.412 0 83.43 0.144 ;
    END
  END di[646]
  PIN di[647]
    DIRECTION INPUT ;
    USE SIGNAL ;
    PORT
      LAYER M5 ;
        RECT  83.52 0 83.544 0.192 ;
    END
  END di[647]
  PIN di[648]
    DIRECTION INPUT ;
    USE SIGNAL ;
    PORT
      LAYER M3 ;
        RECT  83.664 0 83.682 0.144 ;
    END
  END di[648]
  PIN di[649]
    DIRECTION INPUT ;
    USE SIGNAL ;
    PORT
      LAYER M5 ;
        RECT  83.808 0 83.832 0.192 ;
    END
  END di[649]
  PIN di[64]
    DIRECTION INPUT ;
    USE SIGNAL ;
    PORT
      LAYER M3 ;
        RECT  12.204 0 12.222 0.144 ;
    END
  END di[64]
  PIN di[650]
    DIRECTION INPUT ;
    USE SIGNAL ;
    PORT
      LAYER M3 ;
        RECT  83.916 0 83.934 0.144 ;
    END
  END di[650]
  PIN di[651]
    DIRECTION INPUT ;
    USE SIGNAL ;
    PORT
      LAYER M5 ;
        RECT  84.048 0 84.072 0.192 ;
    END
  END di[651]
  PIN di[652]
    DIRECTION INPUT ;
    USE SIGNAL ;
    PORT
      LAYER M3 ;
        RECT  84.168 0 84.186 0.144 ;
    END
  END di[652]
  PIN di[653]
    DIRECTION INPUT ;
    USE SIGNAL ;
    PORT
      LAYER M5 ;
        RECT  84.288 0 84.312 0.192 ;
    END
  END di[653]
  PIN di[654]
    DIRECTION INPUT ;
    USE SIGNAL ;
    PORT
      LAYER M3 ;
        RECT  84.42 0 84.438 0.144 ;
    END
  END di[654]
  PIN di[655]
    DIRECTION INPUT ;
    USE SIGNAL ;
    PORT
      LAYER M5 ;
        RECT  84.528 0 84.552 0.192 ;
    END
  END di[655]
  PIN di[656]
    DIRECTION INPUT ;
    USE SIGNAL ;
    PORT
      LAYER M3 ;
        RECT  84.636 0 84.654 0.144 ;
    END
  END di[656]
  PIN di[657]
    DIRECTION INPUT ;
    USE SIGNAL ;
    PORT
      LAYER M5 ;
        RECT  84.768 0 84.792 0.192 ;
    END
  END di[657]
  PIN di[658]
    DIRECTION INPUT ;
    USE SIGNAL ;
    PORT
      LAYER M3 ;
        RECT  84.888 0 84.906 0.144 ;
    END
  END di[658]
  PIN di[659]
    DIRECTION INPUT ;
    USE SIGNAL ;
    PORT
      LAYER M5 ;
        RECT  85.008 0 85.032 0.192 ;
    END
  END di[659]
  PIN di[65]
    DIRECTION INPUT ;
    USE SIGNAL ;
    PORT
      LAYER M5 ;
        RECT  12.336 0 12.36 0.192 ;
    END
  END di[65]
  PIN di[660]
    DIRECTION INPUT ;
    USE SIGNAL ;
    PORT
      LAYER M3 ;
        RECT  85.14 0 85.158 0.144 ;
    END
  END di[660]
  PIN di[661]
    DIRECTION INPUT ;
    USE SIGNAL ;
    PORT
      LAYER M5 ;
        RECT  85.248 0 85.272 0.192 ;
    END
  END di[661]
  PIN di[662]
    DIRECTION INPUT ;
    USE SIGNAL ;
    PORT
      LAYER M3 ;
        RECT  85.392 0 85.41 0.144 ;
    END
  END di[662]
  PIN di[663]
    DIRECTION INPUT ;
    USE SIGNAL ;
    PORT
      LAYER M5 ;
        RECT  85.488 0 85.512 0.192 ;
    END
  END di[663]
  PIN di[664]
    DIRECTION INPUT ;
    USE SIGNAL ;
    PORT
      LAYER M3 ;
        RECT  85.644 0 85.662 0.144 ;
    END
  END di[664]
  PIN di[665]
    DIRECTION INPUT ;
    USE SIGNAL ;
    PORT
      LAYER M5 ;
        RECT  85.728 0 85.752 0.192 ;
    END
  END di[665]
  PIN di[666]
    DIRECTION INPUT ;
    USE SIGNAL ;
    PORT
      LAYER M3 ;
        RECT  85.86 0 85.878 0.144 ;
    END
  END di[666]
  PIN di[667]
    DIRECTION INPUT ;
    USE SIGNAL ;
    PORT
      LAYER M5 ;
        RECT  85.968 0 85.992 0.192 ;
    END
  END di[667]
  PIN di[668]
    DIRECTION INPUT ;
    USE SIGNAL ;
    PORT
      LAYER M3 ;
        RECT  86.112 0 86.13 0.144 ;
    END
  END di[668]
  PIN di[669]
    DIRECTION INPUT ;
    USE SIGNAL ;
    PORT
      LAYER M5 ;
        RECT  86.256 0 86.28 0.192 ;
    END
  END di[669]
  PIN di[66]
    DIRECTION INPUT ;
    USE SIGNAL ;
    PORT
      LAYER M3 ;
        RECT  12.456 0 12.474 0.144 ;
    END
  END di[66]
  PIN di[670]
    DIRECTION INPUT ;
    USE SIGNAL ;
    PORT
      LAYER M3 ;
        RECT  86.364 0 86.382 0.144 ;
    END
  END di[670]
  PIN di[671]
    DIRECTION INPUT ;
    USE SIGNAL ;
    PORT
      LAYER M5 ;
        RECT  86.496 0 86.52 0.192 ;
    END
  END di[671]
  PIN di[672]
    DIRECTION INPUT ;
    USE SIGNAL ;
    PORT
      LAYER M3 ;
        RECT  86.616 0 86.634 0.144 ;
    END
  END di[672]
  PIN di[673]
    DIRECTION INPUT ;
    USE SIGNAL ;
    PORT
      LAYER M5 ;
        RECT  86.736 0 86.76 0.192 ;
    END
  END di[673]
  PIN di[674]
    DIRECTION INPUT ;
    USE SIGNAL ;
    PORT
      LAYER M3 ;
        RECT  86.868 0 86.886 0.144 ;
    END
  END di[674]
  PIN di[675]
    DIRECTION INPUT ;
    USE SIGNAL ;
    PORT
      LAYER M5 ;
        RECT  86.976 0 87 0.192 ;
    END
  END di[675]
  PIN di[676]
    DIRECTION INPUT ;
    USE SIGNAL ;
    PORT
      LAYER M3 ;
        RECT  87.084 0 87.102 0.144 ;
    END
  END di[676]
  PIN di[677]
    DIRECTION INPUT ;
    USE SIGNAL ;
    PORT
      LAYER M5 ;
        RECT  87.216 0 87.24 0.192 ;
    END
  END di[677]
  PIN di[678]
    DIRECTION INPUT ;
    USE SIGNAL ;
    PORT
      LAYER M3 ;
        RECT  87.336 0 87.354 0.144 ;
    END
  END di[678]
  PIN di[679]
    DIRECTION INPUT ;
    USE SIGNAL ;
    PORT
      LAYER M5 ;
        RECT  87.456 0 87.48 0.192 ;
    END
  END di[679]
  PIN di[67]
    DIRECTION INPUT ;
    USE SIGNAL ;
    PORT
      LAYER M5 ;
        RECT  12.576 0 12.6 0.192 ;
    END
  END di[67]
  PIN di[680]
    DIRECTION INPUT ;
    USE SIGNAL ;
    PORT
      LAYER M3 ;
        RECT  87.588 0 87.606 0.144 ;
    END
  END di[680]
  PIN di[681]
    DIRECTION INPUT ;
    USE SIGNAL ;
    PORT
      LAYER M5 ;
        RECT  87.696 0 87.72 0.192 ;
    END
  END di[681]
  PIN di[682]
    DIRECTION INPUT ;
    USE SIGNAL ;
    PORT
      LAYER M3 ;
        RECT  87.84 0 87.858 0.144 ;
    END
  END di[682]
  PIN di[683]
    DIRECTION INPUT ;
    USE SIGNAL ;
    PORT
      LAYER M5 ;
        RECT  87.936 0 87.96 0.192 ;
    END
  END di[683]
  PIN di[684]
    DIRECTION INPUT ;
    USE SIGNAL ;
    PORT
      LAYER M3 ;
        RECT  88.092 0 88.11 0.144 ;
    END
  END di[684]
  PIN di[685]
    DIRECTION INPUT ;
    USE SIGNAL ;
    PORT
      LAYER M5 ;
        RECT  88.176 0 88.2 0.192 ;
    END
  END di[685]
  PIN di[686]
    DIRECTION INPUT ;
    USE SIGNAL ;
    PORT
      LAYER M3 ;
        RECT  88.308 0 88.326 0.144 ;
    END
  END di[686]
  PIN di[687]
    DIRECTION INPUT ;
    USE SIGNAL ;
    PORT
      LAYER M5 ;
        RECT  88.416 0 88.44 0.192 ;
    END
  END di[687]
  PIN di[688]
    DIRECTION INPUT ;
    USE SIGNAL ;
    PORT
      LAYER M3 ;
        RECT  88.56 0 88.578 0.144 ;
    END
  END di[688]
  PIN di[689]
    DIRECTION INPUT ;
    USE SIGNAL ;
    PORT
      LAYER M5 ;
        RECT  88.704 0 88.728 0.192 ;
    END
  END di[689]
  PIN di[68]
    DIRECTION INPUT ;
    USE SIGNAL ;
    PORT
      LAYER M3 ;
        RECT  12.708 0 12.726 0.144 ;
    END
  END di[68]
  PIN di[690]
    DIRECTION INPUT ;
    USE SIGNAL ;
    PORT
      LAYER M3 ;
        RECT  88.812 0 88.83 0.144 ;
    END
  END di[690]
  PIN di[691]
    DIRECTION INPUT ;
    USE SIGNAL ;
    PORT
      LAYER M5 ;
        RECT  88.944 0 88.968 0.192 ;
    END
  END di[691]
  PIN di[692]
    DIRECTION INPUT ;
    USE SIGNAL ;
    PORT
      LAYER M3 ;
        RECT  89.064 0 89.082 0.144 ;
    END
  END di[692]
  PIN di[693]
    DIRECTION INPUT ;
    USE SIGNAL ;
    PORT
      LAYER M5 ;
        RECT  89.184 0 89.208 0.192 ;
    END
  END di[693]
  PIN di[694]
    DIRECTION INPUT ;
    USE SIGNAL ;
    PORT
      LAYER M3 ;
        RECT  89.316 0 89.334 0.144 ;
    END
  END di[694]
  PIN di[695]
    DIRECTION INPUT ;
    USE SIGNAL ;
    PORT
      LAYER M5 ;
        RECT  89.424 0 89.448 0.192 ;
    END
  END di[695]
  PIN di[696]
    DIRECTION INPUT ;
    USE SIGNAL ;
    PORT
      LAYER M3 ;
        RECT  89.532 0 89.55 0.144 ;
    END
  END di[696]
  PIN di[697]
    DIRECTION INPUT ;
    USE SIGNAL ;
    PORT
      LAYER M5 ;
        RECT  89.664 0 89.688 0.192 ;
    END
  END di[697]
  PIN di[698]
    DIRECTION INPUT ;
    USE SIGNAL ;
    PORT
      LAYER M3 ;
        RECT  89.784 0 89.802 0.144 ;
    END
  END di[698]
  PIN di[699]
    DIRECTION INPUT ;
    USE SIGNAL ;
    PORT
      LAYER M5 ;
        RECT  89.904 0 89.928 0.192 ;
    END
  END di[699]
  PIN di[69]
    DIRECTION INPUT ;
    USE SIGNAL ;
    PORT
      LAYER M5 ;
        RECT  12.816 0 12.84 0.192 ;
    END
  END di[69]
  PIN di[6]
    DIRECTION INPUT ;
    USE SIGNAL ;
    PORT
      LAYER M3 ;
        RECT  5.112 0 5.13 0.144 ;
    END
  END di[6]
  PIN di[700]
    DIRECTION INPUT ;
    USE SIGNAL ;
    PORT
      LAYER M3 ;
        RECT  90.036 0 90.054 0.144 ;
    END
  END di[700]
  PIN di[701]
    DIRECTION INPUT ;
    USE SIGNAL ;
    PORT
      LAYER M5 ;
        RECT  90.144 0 90.168 0.192 ;
    END
  END di[701]
  PIN di[702]
    DIRECTION INPUT ;
    USE SIGNAL ;
    PORT
      LAYER M3 ;
        RECT  90.288 0 90.306 0.144 ;
    END
  END di[702]
  PIN di[703]
    DIRECTION INPUT ;
    USE SIGNAL ;
    PORT
      LAYER M5 ;
        RECT  90.384 0 90.408 0.192 ;
    END
  END di[703]
  PIN di[704]
    DIRECTION INPUT ;
    USE SIGNAL ;
    PORT
      LAYER M3 ;
        RECT  90.504 0 90.522 0.144 ;
    END
  END di[704]
  PIN di[705]
    DIRECTION INPUT ;
    USE SIGNAL ;
    PORT
      LAYER M5 ;
        RECT  90.624 0 90.648 0.192 ;
    END
  END di[705]
  PIN di[706]
    DIRECTION INPUT ;
    USE SIGNAL ;
    PORT
      LAYER M3 ;
        RECT  90.756 0 90.774 0.144 ;
    END
  END di[706]
  PIN di[707]
    DIRECTION INPUT ;
    USE SIGNAL ;
    PORT
      LAYER M5 ;
        RECT  90.864 0 90.888 0.192 ;
    END
  END di[707]
  PIN di[708]
    DIRECTION INPUT ;
    USE SIGNAL ;
    PORT
      LAYER M3 ;
        RECT  91.008 0 91.026 0.144 ;
    END
  END di[708]
  PIN di[709]
    DIRECTION INPUT ;
    USE SIGNAL ;
    PORT
      LAYER M5 ;
        RECT  91.152 0 91.176 0.192 ;
    END
  END di[709]
  PIN di[70]
    DIRECTION INPUT ;
    USE SIGNAL ;
    PORT
      LAYER M3 ;
        RECT  12.924 0 12.942 0.144 ;
    END
  END di[70]
  PIN di[710]
    DIRECTION INPUT ;
    USE SIGNAL ;
    PORT
      LAYER M3 ;
        RECT  91.26 0 91.278 0.144 ;
    END
  END di[710]
  PIN di[711]
    DIRECTION INPUT ;
    USE SIGNAL ;
    PORT
      LAYER M5 ;
        RECT  91.392 0 91.416 0.192 ;
    END
  END di[711]
  PIN di[712]
    DIRECTION INPUT ;
    USE SIGNAL ;
    PORT
      LAYER M3 ;
        RECT  91.512 0 91.53 0.144 ;
    END
  END di[712]
  PIN di[713]
    DIRECTION INPUT ;
    USE SIGNAL ;
    PORT
      LAYER M5 ;
        RECT  91.632 0 91.656 0.192 ;
    END
  END di[713]
  PIN di[714]
    DIRECTION INPUT ;
    USE SIGNAL ;
    PORT
      LAYER M3 ;
        RECT  91.728 0 91.746 0.144 ;
    END
  END di[714]
  PIN di[715]
    DIRECTION INPUT ;
    USE SIGNAL ;
    PORT
      LAYER M5 ;
        RECT  91.872 0 91.896 0.192 ;
    END
  END di[715]
  PIN di[716]
    DIRECTION INPUT ;
    USE SIGNAL ;
    PORT
      LAYER M3 ;
        RECT  91.98 0 91.998 0.144 ;
    END
  END di[716]
  PIN di[717]
    DIRECTION INPUT ;
    USE SIGNAL ;
    PORT
      LAYER M5 ;
        RECT  92.112 0 92.136 0.192 ;
    END
  END di[717]
  PIN di[718]
    DIRECTION INPUT ;
    USE SIGNAL ;
    PORT
      LAYER M3 ;
        RECT  92.232 0 92.25 0.144 ;
    END
  END di[718]
  PIN di[719]
    DIRECTION INPUT ;
    USE SIGNAL ;
    PORT
      LAYER M5 ;
        RECT  92.352 0 92.376 0.192 ;
    END
  END di[719]
  PIN di[71]
    DIRECTION INPUT ;
    USE SIGNAL ;
    PORT
      LAYER M5 ;
        RECT  13.056 0 13.08 0.192 ;
    END
  END di[71]
  PIN di[720]
    DIRECTION INPUT ;
    USE SIGNAL ;
    PORT
      LAYER M3 ;
        RECT  92.484 0 92.502 0.144 ;
    END
  END di[720]
  PIN di[721]
    DIRECTION INPUT ;
    USE SIGNAL ;
    PORT
      LAYER M5 ;
        RECT  92.592 0 92.616 0.192 ;
    END
  END di[721]
  PIN di[722]
    DIRECTION INPUT ;
    USE SIGNAL ;
    PORT
      LAYER M3 ;
        RECT  92.736 0 92.754 0.144 ;
    END
  END di[722]
  PIN di[723]
    DIRECTION INPUT ;
    USE SIGNAL ;
    PORT
      LAYER M5 ;
        RECT  92.832 0 92.856 0.192 ;
    END
  END di[723]
  PIN di[724]
    DIRECTION INPUT ;
    USE SIGNAL ;
    PORT
      LAYER M3 ;
        RECT  92.952 0 92.97 0.144 ;
    END
  END di[724]
  PIN di[725]
    DIRECTION INPUT ;
    USE SIGNAL ;
    PORT
      LAYER M5 ;
        RECT  93.072 0 93.096 0.192 ;
    END
  END di[725]
  PIN di[726]
    DIRECTION INPUT ;
    USE SIGNAL ;
    PORT
      LAYER M3 ;
        RECT  93.204 0 93.222 0.144 ;
    END
  END di[726]
  PIN di[727]
    DIRECTION INPUT ;
    USE SIGNAL ;
    PORT
      LAYER M5 ;
        RECT  93.312 0 93.336 0.192 ;
    END
  END di[727]
  PIN di[728]
    DIRECTION INPUT ;
    USE SIGNAL ;
    PORT
      LAYER M3 ;
        RECT  93.456 0 93.474 0.144 ;
    END
  END di[728]
  PIN di[729]
    DIRECTION INPUT ;
    USE SIGNAL ;
    PORT
      LAYER M5 ;
        RECT  93.6 0 93.624 0.192 ;
    END
  END di[729]
  PIN di[72]
    DIRECTION INPUT ;
    USE SIGNAL ;
    PORT
      LAYER M3 ;
        RECT  13.176 0 13.194 0.144 ;
    END
  END di[72]
  PIN di[730]
    DIRECTION INPUT ;
    USE SIGNAL ;
    PORT
      LAYER M3 ;
        RECT  93.708 0 93.726 0.144 ;
    END
  END di[730]
  PIN di[731]
    DIRECTION INPUT ;
    USE SIGNAL ;
    PORT
      LAYER M5 ;
        RECT  93.84 0 93.864 0.192 ;
    END
  END di[731]
  PIN di[732]
    DIRECTION INPUT ;
    USE SIGNAL ;
    PORT
      LAYER M3 ;
        RECT  93.96 0 93.978 0.144 ;
    END
  END di[732]
  PIN di[733]
    DIRECTION INPUT ;
    USE SIGNAL ;
    PORT
      LAYER M5 ;
        RECT  94.08 0 94.104 0.192 ;
    END
  END di[733]
  PIN di[734]
    DIRECTION INPUT ;
    USE SIGNAL ;
    PORT
      LAYER M3 ;
        RECT  94.176 0 94.194 0.144 ;
    END
  END di[734]
  PIN di[735]
    DIRECTION INPUT ;
    USE SIGNAL ;
    PORT
      LAYER M5 ;
        RECT  94.32 0 94.344 0.192 ;
    END
  END di[735]
  PIN di[736]
    DIRECTION INPUT ;
    USE SIGNAL ;
    PORT
      LAYER M3 ;
        RECT  94.428 0 94.446 0.144 ;
    END
  END di[736]
  PIN di[737]
    DIRECTION INPUT ;
    USE SIGNAL ;
    PORT
      LAYER M5 ;
        RECT  94.56 0 94.584 0.192 ;
    END
  END di[737]
  PIN di[738]
    DIRECTION INPUT ;
    USE SIGNAL ;
    PORT
      LAYER M3 ;
        RECT  94.68 0 94.698 0.144 ;
    END
  END di[738]
  PIN di[739]
    DIRECTION INPUT ;
    USE SIGNAL ;
    PORT
      LAYER M5 ;
        RECT  94.8 0 94.824 0.192 ;
    END
  END di[739]
  PIN di[73]
    DIRECTION INPUT ;
    USE SIGNAL ;
    PORT
      LAYER M5 ;
        RECT  13.296 0 13.32 0.192 ;
    END
  END di[73]
  PIN di[740]
    DIRECTION INPUT ;
    USE SIGNAL ;
    PORT
      LAYER M3 ;
        RECT  94.932 0 94.95 0.144 ;
    END
  END di[740]
  PIN di[741]
    DIRECTION INPUT ;
    USE SIGNAL ;
    PORT
      LAYER M5 ;
        RECT  95.04 0 95.064 0.192 ;
    END
  END di[741]
  PIN di[742]
    DIRECTION INPUT ;
    USE SIGNAL ;
    PORT
      LAYER M3 ;
        RECT  95.184 0 95.202 0.144 ;
    END
  END di[742]
  PIN di[743]
    DIRECTION INPUT ;
    USE SIGNAL ;
    PORT
      LAYER M5 ;
        RECT  95.28 0 95.304 0.192 ;
    END
  END di[743]
  PIN di[744]
    DIRECTION INPUT ;
    USE SIGNAL ;
    PORT
      LAYER M3 ;
        RECT  95.4 0 95.418 0.144 ;
    END
  END di[744]
  PIN di[745]
    DIRECTION INPUT ;
    USE SIGNAL ;
    PORT
      LAYER M5 ;
        RECT  95.52 0 95.544 0.192 ;
    END
  END di[745]
  PIN di[746]
    DIRECTION INPUT ;
    USE SIGNAL ;
    PORT
      LAYER M3 ;
        RECT  95.652 0 95.67 0.144 ;
    END
  END di[746]
  PIN di[747]
    DIRECTION INPUT ;
    USE SIGNAL ;
    PORT
      LAYER M5 ;
        RECT  95.76 0 95.784 0.192 ;
    END
  END di[747]
  PIN di[748]
    DIRECTION INPUT ;
    USE SIGNAL ;
    PORT
      LAYER M3 ;
        RECT  95.904 0 95.922 0.144 ;
    END
  END di[748]
  PIN di[749]
    DIRECTION INPUT ;
    USE SIGNAL ;
    PORT
      LAYER M5 ;
        RECT  96.048 0 96.072 0.192 ;
    END
  END di[749]
  PIN di[74]
    DIRECTION INPUT ;
    USE SIGNAL ;
    PORT
      LAYER M3 ;
        RECT  13.428 0 13.446 0.144 ;
    END
  END di[74]
  PIN di[750]
    DIRECTION INPUT ;
    USE SIGNAL ;
    PORT
      LAYER M3 ;
        RECT  96.156 0 96.174 0.144 ;
    END
  END di[750]
  PIN di[751]
    DIRECTION INPUT ;
    USE SIGNAL ;
    PORT
      LAYER M5 ;
        RECT  96.288 0 96.312 0.192 ;
    END
  END di[751]
  PIN di[752]
    DIRECTION INPUT ;
    USE SIGNAL ;
    PORT
      LAYER M3 ;
        RECT  96.408 0 96.426 0.144 ;
    END
  END di[752]
  PIN di[753]
    DIRECTION INPUT ;
    USE SIGNAL ;
    PORT
      LAYER M5 ;
        RECT  96.528 0 96.552 0.192 ;
    END
  END di[753]
  PIN di[754]
    DIRECTION INPUT ;
    USE SIGNAL ;
    PORT
      LAYER M3 ;
        RECT  96.624 0 96.642 0.144 ;
    END
  END di[754]
  PIN di[755]
    DIRECTION INPUT ;
    USE SIGNAL ;
    PORT
      LAYER M5 ;
        RECT  96.768 0 96.792 0.192 ;
    END
  END di[755]
  PIN di[756]
    DIRECTION INPUT ;
    USE SIGNAL ;
    PORT
      LAYER M3 ;
        RECT  96.876 0 96.894 0.144 ;
    END
  END di[756]
  PIN di[757]
    DIRECTION INPUT ;
    USE SIGNAL ;
    PORT
      LAYER M5 ;
        RECT  97.008 0 97.032 0.192 ;
    END
  END di[757]
  PIN di[758]
    DIRECTION INPUT ;
    USE SIGNAL ;
    PORT
      LAYER M3 ;
        RECT  97.128 0 97.146 0.144 ;
    END
  END di[758]
  PIN di[75]
    DIRECTION INPUT ;
    USE SIGNAL ;
    PORT
      LAYER M5 ;
        RECT  13.536 0 13.56 0.192 ;
    END
  END di[75]
  PIN di[76]
    DIRECTION INPUT ;
    USE SIGNAL ;
    PORT
      LAYER M3 ;
        RECT  13.68 0 13.698 0.144 ;
    END
  END di[76]
  PIN di[77]
    DIRECTION INPUT ;
    USE SIGNAL ;
    PORT
      LAYER M5 ;
        RECT  13.776 0 13.8 0.192 ;
    END
  END di[77]
  PIN di[78]
    DIRECTION INPUT ;
    USE SIGNAL ;
    PORT
      LAYER M3 ;
        RECT  13.932 0 13.95 0.144 ;
    END
  END di[78]
  PIN di[79]
    DIRECTION INPUT ;
    USE SIGNAL ;
    PORT
      LAYER M5 ;
        RECT  14.016 0 14.04 0.192 ;
    END
  END di[79]
  PIN di[7]
    DIRECTION INPUT ;
    USE SIGNAL ;
    PORT
      LAYER M5 ;
        RECT  5.232 0 5.256 0.192 ;
    END
  END di[7]
  PIN di[80]
    DIRECTION INPUT ;
    USE SIGNAL ;
    PORT
      LAYER M3 ;
        RECT  14.148 0 14.166 0.144 ;
    END
  END di[80]
  PIN di[81]
    DIRECTION INPUT ;
    USE SIGNAL ;
    PORT
      LAYER M5 ;
        RECT  14.304 0 14.328 0.192 ;
    END
  END di[81]
  PIN di[82]
    DIRECTION INPUT ;
    USE SIGNAL ;
    PORT
      LAYER M3 ;
        RECT  14.4 0 14.418 0.144 ;
    END
  END di[82]
  PIN di[83]
    DIRECTION INPUT ;
    USE SIGNAL ;
    PORT
      LAYER M5 ;
        RECT  14.544 0 14.568 0.192 ;
    END
  END di[83]
  PIN di[84]
    DIRECTION INPUT ;
    USE SIGNAL ;
    PORT
      LAYER M3 ;
        RECT  14.652 0 14.67 0.144 ;
    END
  END di[84]
  PIN di[85]
    DIRECTION INPUT ;
    USE SIGNAL ;
    PORT
      LAYER M5 ;
        RECT  14.784 0 14.808 0.192 ;
    END
  END di[85]
  PIN di[86]
    DIRECTION INPUT ;
    USE SIGNAL ;
    PORT
      LAYER M3 ;
        RECT  14.904 0 14.922 0.144 ;
    END
  END di[86]
  PIN di[87]
    DIRECTION INPUT ;
    USE SIGNAL ;
    PORT
      LAYER M5 ;
        RECT  15.024 0 15.048 0.192 ;
    END
  END di[87]
  PIN di[88]
    DIRECTION INPUT ;
    USE SIGNAL ;
    PORT
      LAYER M3 ;
        RECT  15.156 0 15.174 0.144 ;
    END
  END di[88]
  PIN di[89]
    DIRECTION INPUT ;
    USE SIGNAL ;
    PORT
      LAYER M5 ;
        RECT  15.264 0 15.288 0.192 ;
    END
  END di[89]
  PIN di[8]
    DIRECTION INPUT ;
    USE SIGNAL ;
    PORT
      LAYER M3 ;
        RECT  5.364 0 5.382 0.144 ;
    END
  END di[8]
  PIN di[90]
    DIRECTION INPUT ;
    USE SIGNAL ;
    PORT
      LAYER M3 ;
        RECT  15.372 0 15.39 0.144 ;
    END
  END di[90]
  PIN di[91]
    DIRECTION INPUT ;
    USE SIGNAL ;
    PORT
      LAYER M5 ;
        RECT  15.504 0 15.528 0.192 ;
    END
  END di[91]
  PIN di[92]
    DIRECTION INPUT ;
    USE SIGNAL ;
    PORT
      LAYER M3 ;
        RECT  15.624 0 15.642 0.144 ;
    END
  END di[92]
  PIN di[93]
    DIRECTION INPUT ;
    USE SIGNAL ;
    PORT
      LAYER M5 ;
        RECT  15.744 0 15.768 0.192 ;
    END
  END di[93]
  PIN di[94]
    DIRECTION INPUT ;
    USE SIGNAL ;
    PORT
      LAYER M3 ;
        RECT  15.876 0 15.894 0.144 ;
    END
  END di[94]
  PIN di[95]
    DIRECTION INPUT ;
    USE SIGNAL ;
    PORT
      LAYER M5 ;
        RECT  15.984 0 16.008 0.192 ;
    END
  END di[95]
  PIN di[96]
    DIRECTION INPUT ;
    USE SIGNAL ;
    PORT
      LAYER M3 ;
        RECT  16.128 0 16.146 0.144 ;
    END
  END di[96]
  PIN di[97]
    DIRECTION INPUT ;
    USE SIGNAL ;
    PORT
      LAYER M5 ;
        RECT  16.224 0 16.248 0.192 ;
    END
  END di[97]
  PIN di[98]
    DIRECTION INPUT ;
    USE SIGNAL ;
    PORT
      LAYER M3 ;
        RECT  16.38 0 16.398 0.144 ;
    END
  END di[98]
  PIN di[99]
    DIRECTION INPUT ;
    USE SIGNAL ;
    PORT
      LAYER M5 ;
        RECT  16.464 0 16.488 0.192 ;
    END
  END di[99]
  PIN di[9]
    DIRECTION INPUT ;
    USE SIGNAL ;
    PORT
      LAYER M5 ;
        RECT  5.472 0 5.496 0.192 ;
    END
  END di[9]
  PIN dq[0]
    DIRECTION OUTPUT ;
    USE SIGNAL ;
    PORT
      LAYER M3 ;
        RECT  4.356 36.576 4.374 36.72 ;
    END
  END dq[0]
  PIN dq[100]
    DIRECTION OUTPUT ;
    USE SIGNAL ;
    PORT
      LAYER M3 ;
        RECT  16.596 36.576 16.614 36.72 ;
    END
  END dq[100]
  PIN dq[101]
    DIRECTION OUTPUT ;
    USE SIGNAL ;
    PORT
      LAYER M5 ;
        RECT  16.752 36.528 16.776 36.72 ;
    END
  END dq[101]
  PIN dq[102]
    DIRECTION OUTPUT ;
    USE SIGNAL ;
    PORT
      LAYER M3 ;
        RECT  16.848 36.576 16.866 36.72 ;
    END
  END dq[102]
  PIN dq[103]
    DIRECTION OUTPUT ;
    USE SIGNAL ;
    PORT
      LAYER M5 ;
        RECT  16.992 36.528 17.016 36.72 ;
    END
  END dq[103]
  PIN dq[104]
    DIRECTION OUTPUT ;
    USE SIGNAL ;
    PORT
      LAYER M3 ;
        RECT  17.1 36.576 17.118 36.72 ;
    END
  END dq[104]
  PIN dq[105]
    DIRECTION OUTPUT ;
    USE SIGNAL ;
    PORT
      LAYER M5 ;
        RECT  17.232 36.528 17.256 36.72 ;
    END
  END dq[105]
  PIN dq[106]
    DIRECTION OUTPUT ;
    USE SIGNAL ;
    PORT
      LAYER M3 ;
        RECT  17.352 36.576 17.37 36.72 ;
    END
  END dq[106]
  PIN dq[107]
    DIRECTION OUTPUT ;
    USE SIGNAL ;
    PORT
      LAYER M5 ;
        RECT  17.472 36.528 17.496 36.72 ;
    END
  END dq[107]
  PIN dq[108]
    DIRECTION OUTPUT ;
    USE SIGNAL ;
    PORT
      LAYER M3 ;
        RECT  17.604 36.576 17.622 36.72 ;
    END
  END dq[108]
  PIN dq[109]
    DIRECTION OUTPUT ;
    USE SIGNAL ;
    PORT
      LAYER M5 ;
        RECT  17.712 36.528 17.736 36.72 ;
    END
  END dq[109]
  PIN dq[10]
    DIRECTION OUTPUT ;
    USE SIGNAL ;
    PORT
      LAYER M3 ;
        RECT  5.58 36.576 5.598 36.72 ;
    END
  END dq[10]
  PIN dq[110]
    DIRECTION OUTPUT ;
    USE SIGNAL ;
    PORT
      LAYER M3 ;
        RECT  17.82 36.576 17.838 36.72 ;
    END
  END dq[110]
  PIN dq[111]
    DIRECTION OUTPUT ;
    USE SIGNAL ;
    PORT
      LAYER M5 ;
        RECT  17.952 36.528 17.976 36.72 ;
    END
  END dq[111]
  PIN dq[112]
    DIRECTION OUTPUT ;
    USE SIGNAL ;
    PORT
      LAYER M3 ;
        RECT  18.072 36.576 18.09 36.72 ;
    END
  END dq[112]
  PIN dq[113]
    DIRECTION OUTPUT ;
    USE SIGNAL ;
    PORT
      LAYER M5 ;
        RECT  18.192 36.528 18.216 36.72 ;
    END
  END dq[113]
  PIN dq[114]
    DIRECTION OUTPUT ;
    USE SIGNAL ;
    PORT
      LAYER M3 ;
        RECT  18.324 36.576 18.342 36.72 ;
    END
  END dq[114]
  PIN dq[115]
    DIRECTION OUTPUT ;
    USE SIGNAL ;
    PORT
      LAYER M5 ;
        RECT  18.432 36.528 18.456 36.72 ;
    END
  END dq[115]
  PIN dq[116]
    DIRECTION OUTPUT ;
    USE SIGNAL ;
    PORT
      LAYER M3 ;
        RECT  18.576 36.576 18.594 36.72 ;
    END
  END dq[116]
  PIN dq[117]
    DIRECTION OUTPUT ;
    USE SIGNAL ;
    PORT
      LAYER M5 ;
        RECT  18.672 36.528 18.696 36.72 ;
    END
  END dq[117]
  PIN dq[118]
    DIRECTION OUTPUT ;
    USE SIGNAL ;
    PORT
      LAYER M3 ;
        RECT  18.828 36.576 18.846 36.72 ;
    END
  END dq[118]
  PIN dq[119]
    DIRECTION OUTPUT ;
    USE SIGNAL ;
    PORT
      LAYER M5 ;
        RECT  18.912 36.528 18.936 36.72 ;
    END
  END dq[119]
  PIN dq[11]
    DIRECTION OUTPUT ;
    USE SIGNAL ;
    PORT
      LAYER M5 ;
        RECT  5.712 36.528 5.736 36.72 ;
    END
  END dq[11]
  PIN dq[120]
    DIRECTION OUTPUT ;
    USE SIGNAL ;
    PORT
      LAYER M3 ;
        RECT  19.044 36.576 19.062 36.72 ;
    END
  END dq[120]
  PIN dq[121]
    DIRECTION OUTPUT ;
    USE SIGNAL ;
    PORT
      LAYER M5 ;
        RECT  19.2 36.528 19.224 36.72 ;
    END
  END dq[121]
  PIN dq[122]
    DIRECTION OUTPUT ;
    USE SIGNAL ;
    PORT
      LAYER M3 ;
        RECT  19.296 36.576 19.314 36.72 ;
    END
  END dq[122]
  PIN dq[123]
    DIRECTION OUTPUT ;
    USE SIGNAL ;
    PORT
      LAYER M5 ;
        RECT  19.44 36.528 19.464 36.72 ;
    END
  END dq[123]
  PIN dq[124]
    DIRECTION OUTPUT ;
    USE SIGNAL ;
    PORT
      LAYER M3 ;
        RECT  19.548 36.576 19.566 36.72 ;
    END
  END dq[124]
  PIN dq[125]
    DIRECTION OUTPUT ;
    USE SIGNAL ;
    PORT
      LAYER M5 ;
        RECT  19.68 36.528 19.704 36.72 ;
    END
  END dq[125]
  PIN dq[126]
    DIRECTION OUTPUT ;
    USE SIGNAL ;
    PORT
      LAYER M3 ;
        RECT  19.8 36.576 19.818 36.72 ;
    END
  END dq[126]
  PIN dq[127]
    DIRECTION OUTPUT ;
    USE SIGNAL ;
    PORT
      LAYER M5 ;
        RECT  19.92 36.528 19.944 36.72 ;
    END
  END dq[127]
  PIN dq[128]
    DIRECTION OUTPUT ;
    USE SIGNAL ;
    PORT
      LAYER M3 ;
        RECT  20.052 36.576 20.07 36.72 ;
    END
  END dq[128]
  PIN dq[129]
    DIRECTION OUTPUT ;
    USE SIGNAL ;
    PORT
      LAYER M5 ;
        RECT  20.16 36.528 20.184 36.72 ;
    END
  END dq[129]
  PIN dq[12]
    DIRECTION OUTPUT ;
    USE SIGNAL ;
    PORT
      LAYER M3 ;
        RECT  5.832 36.576 5.85 36.72 ;
    END
  END dq[12]
  PIN dq[130]
    DIRECTION OUTPUT ;
    USE SIGNAL ;
    PORT
      LAYER M3 ;
        RECT  20.268 36.576 20.286 36.72 ;
    END
  END dq[130]
  PIN dq[131]
    DIRECTION OUTPUT ;
    USE SIGNAL ;
    PORT
      LAYER M5 ;
        RECT  20.4 36.528 20.424 36.72 ;
    END
  END dq[131]
  PIN dq[132]
    DIRECTION OUTPUT ;
    USE SIGNAL ;
    PORT
      LAYER M3 ;
        RECT  20.52 36.576 20.538 36.72 ;
    END
  END dq[132]
  PIN dq[133]
    DIRECTION OUTPUT ;
    USE SIGNAL ;
    PORT
      LAYER M5 ;
        RECT  20.64 36.528 20.664 36.72 ;
    END
  END dq[133]
  PIN dq[134]
    DIRECTION OUTPUT ;
    USE SIGNAL ;
    PORT
      LAYER M3 ;
        RECT  20.772 36.576 20.79 36.72 ;
    END
  END dq[134]
  PIN dq[135]
    DIRECTION OUTPUT ;
    USE SIGNAL ;
    PORT
      LAYER M5 ;
        RECT  20.88 36.528 20.904 36.72 ;
    END
  END dq[135]
  PIN dq[136]
    DIRECTION OUTPUT ;
    USE SIGNAL ;
    PORT
      LAYER M3 ;
        RECT  21.024 36.576 21.042 36.72 ;
    END
  END dq[136]
  PIN dq[137]
    DIRECTION OUTPUT ;
    USE SIGNAL ;
    PORT
      LAYER M5 ;
        RECT  21.12 36.528 21.144 36.72 ;
    END
  END dq[137]
  PIN dq[138]
    DIRECTION OUTPUT ;
    USE SIGNAL ;
    PORT
      LAYER M3 ;
        RECT  21.276 36.576 21.294 36.72 ;
    END
  END dq[138]
  PIN dq[139]
    DIRECTION OUTPUT ;
    USE SIGNAL ;
    PORT
      LAYER M5 ;
        RECT  21.36 36.528 21.384 36.72 ;
    END
  END dq[139]
  PIN dq[13]
    DIRECTION OUTPUT ;
    USE SIGNAL ;
    PORT
      LAYER M5 ;
        RECT  5.952 36.528 5.976 36.72 ;
    END
  END dq[13]
  PIN dq[140]
    DIRECTION OUTPUT ;
    USE SIGNAL ;
    PORT
      LAYER M3 ;
        RECT  21.492 36.576 21.51 36.72 ;
    END
  END dq[140]
  PIN dq[141]
    DIRECTION OUTPUT ;
    USE SIGNAL ;
    PORT
      LAYER M5 ;
        RECT  21.6 36.528 21.624 36.72 ;
    END
  END dq[141]
  PIN dq[142]
    DIRECTION OUTPUT ;
    USE SIGNAL ;
    PORT
      LAYER M3 ;
        RECT  21.744 36.576 21.762 36.72 ;
    END
  END dq[142]
  PIN dq[143]
    DIRECTION OUTPUT ;
    USE SIGNAL ;
    PORT
      LAYER M5 ;
        RECT  21.888 36.528 21.912 36.72 ;
    END
  END dq[143]
  PIN dq[144]
    DIRECTION OUTPUT ;
    USE SIGNAL ;
    PORT
      LAYER M3 ;
        RECT  21.996 36.576 22.014 36.72 ;
    END
  END dq[144]
  PIN dq[145]
    DIRECTION OUTPUT ;
    USE SIGNAL ;
    PORT
      LAYER M5 ;
        RECT  22.128 36.528 22.152 36.72 ;
    END
  END dq[145]
  PIN dq[146]
    DIRECTION OUTPUT ;
    USE SIGNAL ;
    PORT
      LAYER M3 ;
        RECT  22.248 36.576 22.266 36.72 ;
    END
  END dq[146]
  PIN dq[147]
    DIRECTION OUTPUT ;
    USE SIGNAL ;
    PORT
      LAYER M5 ;
        RECT  22.368 36.528 22.392 36.72 ;
    END
  END dq[147]
  PIN dq[148]
    DIRECTION OUTPUT ;
    USE SIGNAL ;
    PORT
      LAYER M3 ;
        RECT  22.5 36.576 22.518 36.72 ;
    END
  END dq[148]
  PIN dq[149]
    DIRECTION OUTPUT ;
    USE SIGNAL ;
    PORT
      LAYER M5 ;
        RECT  22.608 36.528 22.632 36.72 ;
    END
  END dq[149]
  PIN dq[14]
    DIRECTION OUTPUT ;
    USE SIGNAL ;
    PORT
      LAYER M3 ;
        RECT  6.084 36.576 6.102 36.72 ;
    END
  END dq[14]
  PIN dq[150]
    DIRECTION OUTPUT ;
    USE SIGNAL ;
    PORT
      LAYER M3 ;
        RECT  22.716 36.576 22.734 36.72 ;
    END
  END dq[150]
  PIN dq[151]
    DIRECTION OUTPUT ;
    USE SIGNAL ;
    PORT
      LAYER M5 ;
        RECT  22.848 36.528 22.872 36.72 ;
    END
  END dq[151]
  PIN dq[152]
    DIRECTION OUTPUT ;
    USE SIGNAL ;
    PORT
      LAYER M3 ;
        RECT  22.968 36.576 22.986 36.72 ;
    END
  END dq[152]
  PIN dq[153]
    DIRECTION OUTPUT ;
    USE SIGNAL ;
    PORT
      LAYER M5 ;
        RECT  23.088 36.528 23.112 36.72 ;
    END
  END dq[153]
  PIN dq[154]
    DIRECTION OUTPUT ;
    USE SIGNAL ;
    PORT
      LAYER M3 ;
        RECT  23.22 36.576 23.238 36.72 ;
    END
  END dq[154]
  PIN dq[155]
    DIRECTION OUTPUT ;
    USE SIGNAL ;
    PORT
      LAYER M5 ;
        RECT  23.328 36.528 23.352 36.72 ;
    END
  END dq[155]
  PIN dq[156]
    DIRECTION OUTPUT ;
    USE SIGNAL ;
    PORT
      LAYER M3 ;
        RECT  23.472 36.576 23.49 36.72 ;
    END
  END dq[156]
  PIN dq[157]
    DIRECTION OUTPUT ;
    USE SIGNAL ;
    PORT
      LAYER M5 ;
        RECT  23.568 36.528 23.592 36.72 ;
    END
  END dq[157]
  PIN dq[158]
    DIRECTION OUTPUT ;
    USE SIGNAL ;
    PORT
      LAYER M3 ;
        RECT  23.724 36.576 23.742 36.72 ;
    END
  END dq[158]
  PIN dq[159]
    DIRECTION OUTPUT ;
    USE SIGNAL ;
    PORT
      LAYER M5 ;
        RECT  23.808 36.528 23.832 36.72 ;
    END
  END dq[159]
  PIN dq[15]
    DIRECTION OUTPUT ;
    USE SIGNAL ;
    PORT
      LAYER M5 ;
        RECT  6.192 36.528 6.216 36.72 ;
    END
  END dq[15]
  PIN dq[160]
    DIRECTION OUTPUT ;
    USE SIGNAL ;
    PORT
      LAYER M3 ;
        RECT  23.94 36.576 23.958 36.72 ;
    END
  END dq[160]
  PIN dq[161]
    DIRECTION OUTPUT ;
    USE SIGNAL ;
    PORT
      LAYER M5 ;
        RECT  24.048 36.528 24.072 36.72 ;
    END
  END dq[161]
  PIN dq[162]
    DIRECTION OUTPUT ;
    USE SIGNAL ;
    PORT
      LAYER M3 ;
        RECT  24.192 36.576 24.21 36.72 ;
    END
  END dq[162]
  PIN dq[163]
    DIRECTION OUTPUT ;
    USE SIGNAL ;
    PORT
      LAYER M5 ;
        RECT  24.336 36.528 24.36 36.72 ;
    END
  END dq[163]
  PIN dq[164]
    DIRECTION OUTPUT ;
    USE SIGNAL ;
    PORT
      LAYER M3 ;
        RECT  24.444 36.576 24.462 36.72 ;
    END
  END dq[164]
  PIN dq[165]
    DIRECTION OUTPUT ;
    USE SIGNAL ;
    PORT
      LAYER M5 ;
        RECT  24.576 36.528 24.6 36.72 ;
    END
  END dq[165]
  PIN dq[166]
    DIRECTION OUTPUT ;
    USE SIGNAL ;
    PORT
      LAYER M3 ;
        RECT  24.696 36.576 24.714 36.72 ;
    END
  END dq[166]
  PIN dq[167]
    DIRECTION OUTPUT ;
    USE SIGNAL ;
    PORT
      LAYER M5 ;
        RECT  24.816 36.528 24.84 36.72 ;
    END
  END dq[167]
  PIN dq[168]
    DIRECTION OUTPUT ;
    USE SIGNAL ;
    PORT
      LAYER M3 ;
        RECT  24.948 36.576 24.966 36.72 ;
    END
  END dq[168]
  PIN dq[169]
    DIRECTION OUTPUT ;
    USE SIGNAL ;
    PORT
      LAYER M5 ;
        RECT  25.056 36.528 25.08 36.72 ;
    END
  END dq[169]
  PIN dq[16]
    DIRECTION OUTPUT ;
    USE SIGNAL ;
    PORT
      LAYER M3 ;
        RECT  6.336 36.576 6.354 36.72 ;
    END
  END dq[16]
  PIN dq[170]
    DIRECTION OUTPUT ;
    USE SIGNAL ;
    PORT
      LAYER M3 ;
        RECT  25.164 36.576 25.182 36.72 ;
    END
  END dq[170]
  PIN dq[171]
    DIRECTION OUTPUT ;
    USE SIGNAL ;
    PORT
      LAYER M5 ;
        RECT  25.296 36.528 25.32 36.72 ;
    END
  END dq[171]
  PIN dq[172]
    DIRECTION OUTPUT ;
    USE SIGNAL ;
    PORT
      LAYER M3 ;
        RECT  25.416 36.576 25.434 36.72 ;
    END
  END dq[172]
  PIN dq[173]
    DIRECTION OUTPUT ;
    USE SIGNAL ;
    PORT
      LAYER M5 ;
        RECT  25.536 36.528 25.56 36.72 ;
    END
  END dq[173]
  PIN dq[174]
    DIRECTION OUTPUT ;
    USE SIGNAL ;
    PORT
      LAYER M3 ;
        RECT  25.668 36.576 25.686 36.72 ;
    END
  END dq[174]
  PIN dq[175]
    DIRECTION OUTPUT ;
    USE SIGNAL ;
    PORT
      LAYER M5 ;
        RECT  25.776 36.528 25.8 36.72 ;
    END
  END dq[175]
  PIN dq[176]
    DIRECTION OUTPUT ;
    USE SIGNAL ;
    PORT
      LAYER M3 ;
        RECT  25.92 36.576 25.938 36.72 ;
    END
  END dq[176]
  PIN dq[177]
    DIRECTION OUTPUT ;
    USE SIGNAL ;
    PORT
      LAYER M5 ;
        RECT  26.016 36.528 26.04 36.72 ;
    END
  END dq[177]
  PIN dq[178]
    DIRECTION OUTPUT ;
    USE SIGNAL ;
    PORT
      LAYER M3 ;
        RECT  26.172 36.576 26.19 36.72 ;
    END
  END dq[178]
  PIN dq[179]
    DIRECTION OUTPUT ;
    USE SIGNAL ;
    PORT
      LAYER M5 ;
        RECT  26.256 36.528 26.28 36.72 ;
    END
  END dq[179]
  PIN dq[17]
    DIRECTION OUTPUT ;
    USE SIGNAL ;
    PORT
      LAYER M5 ;
        RECT  6.432 36.528 6.456 36.72 ;
    END
  END dq[17]
  PIN dq[180]
    DIRECTION OUTPUT ;
    USE SIGNAL ;
    PORT
      LAYER M3 ;
        RECT  26.388 36.576 26.406 36.72 ;
    END
  END dq[180]
  PIN dq[181]
    DIRECTION OUTPUT ;
    USE SIGNAL ;
    PORT
      LAYER M5 ;
        RECT  26.496 36.528 26.52 36.72 ;
    END
  END dq[181]
  PIN dq[182]
    DIRECTION OUTPUT ;
    USE SIGNAL ;
    PORT
      LAYER M3 ;
        RECT  26.64 36.576 26.658 36.72 ;
    END
  END dq[182]
  PIN dq[183]
    DIRECTION OUTPUT ;
    USE SIGNAL ;
    PORT
      LAYER M5 ;
        RECT  26.784 36.528 26.808 36.72 ;
    END
  END dq[183]
  PIN dq[184]
    DIRECTION OUTPUT ;
    USE SIGNAL ;
    PORT
      LAYER M3 ;
        RECT  26.892 36.576 26.91 36.72 ;
    END
  END dq[184]
  PIN dq[185]
    DIRECTION OUTPUT ;
    USE SIGNAL ;
    PORT
      LAYER M5 ;
        RECT  27.024 36.528 27.048 36.72 ;
    END
  END dq[185]
  PIN dq[186]
    DIRECTION OUTPUT ;
    USE SIGNAL ;
    PORT
      LAYER M3 ;
        RECT  27.144 36.576 27.162 36.72 ;
    END
  END dq[186]
  PIN dq[187]
    DIRECTION OUTPUT ;
    USE SIGNAL ;
    PORT
      LAYER M5 ;
        RECT  27.264 36.528 27.288 36.72 ;
    END
  END dq[187]
  PIN dq[188]
    DIRECTION OUTPUT ;
    USE SIGNAL ;
    PORT
      LAYER M3 ;
        RECT  27.396 36.576 27.414 36.72 ;
    END
  END dq[188]
  PIN dq[189]
    DIRECTION OUTPUT ;
    USE SIGNAL ;
    PORT
      LAYER M5 ;
        RECT  27.504 36.528 27.528 36.72 ;
    END
  END dq[189]
  PIN dq[18]
    DIRECTION OUTPUT ;
    USE SIGNAL ;
    PORT
      LAYER M3 ;
        RECT  6.588 36.576 6.606 36.72 ;
    END
  END dq[18]
  PIN dq[190]
    DIRECTION OUTPUT ;
    USE SIGNAL ;
    PORT
      LAYER M3 ;
        RECT  27.612 36.576 27.63 36.72 ;
    END
  END dq[190]
  PIN dq[191]
    DIRECTION OUTPUT ;
    USE SIGNAL ;
    PORT
      LAYER M5 ;
        RECT  27.744 36.528 27.768 36.72 ;
    END
  END dq[191]
  PIN dq[192]
    DIRECTION OUTPUT ;
    USE SIGNAL ;
    PORT
      LAYER M3 ;
        RECT  27.864 36.576 27.882 36.72 ;
    END
  END dq[192]
  PIN dq[193]
    DIRECTION OUTPUT ;
    USE SIGNAL ;
    PORT
      LAYER M5 ;
        RECT  27.984 36.528 28.008 36.72 ;
    END
  END dq[193]
  PIN dq[194]
    DIRECTION OUTPUT ;
    USE SIGNAL ;
    PORT
      LAYER M3 ;
        RECT  28.116 36.576 28.134 36.72 ;
    END
  END dq[194]
  PIN dq[195]
    DIRECTION OUTPUT ;
    USE SIGNAL ;
    PORT
      LAYER M5 ;
        RECT  28.224 36.528 28.248 36.72 ;
    END
  END dq[195]
  PIN dq[196]
    DIRECTION OUTPUT ;
    USE SIGNAL ;
    PORT
      LAYER M3 ;
        RECT  28.368 36.576 28.386 36.72 ;
    END
  END dq[196]
  PIN dq[197]
    DIRECTION OUTPUT ;
    USE SIGNAL ;
    PORT
      LAYER M5 ;
        RECT  28.464 36.528 28.488 36.72 ;
    END
  END dq[197]
  PIN dq[198]
    DIRECTION OUTPUT ;
    USE SIGNAL ;
    PORT
      LAYER M3 ;
        RECT  28.584 36.576 28.602 36.72 ;
    END
  END dq[198]
  PIN dq[199]
    DIRECTION OUTPUT ;
    USE SIGNAL ;
    PORT
      LAYER M5 ;
        RECT  28.704 36.528 28.728 36.72 ;
    END
  END dq[199]
  PIN dq[19]
    DIRECTION OUTPUT ;
    USE SIGNAL ;
    PORT
      LAYER M5 ;
        RECT  6.672 36.528 6.696 36.72 ;
    END
  END dq[19]
  PIN dq[1]
    DIRECTION OUTPUT ;
    USE SIGNAL ;
    PORT
      LAYER M5 ;
        RECT  4.512 36.528 4.536 36.72 ;
    END
  END dq[1]
  PIN dq[200]
    DIRECTION OUTPUT ;
    USE SIGNAL ;
    PORT
      LAYER M3 ;
        RECT  28.836 36.576 28.854 36.72 ;
    END
  END dq[200]
  PIN dq[201]
    DIRECTION OUTPUT ;
    USE SIGNAL ;
    PORT
      LAYER M5 ;
        RECT  28.944 36.528 28.968 36.72 ;
    END
  END dq[201]
  PIN dq[202]
    DIRECTION OUTPUT ;
    USE SIGNAL ;
    PORT
      LAYER M3 ;
        RECT  29.088 36.576 29.106 36.72 ;
    END
  END dq[202]
  PIN dq[203]
    DIRECTION OUTPUT ;
    USE SIGNAL ;
    PORT
      LAYER M5 ;
        RECT  29.232 36.528 29.256 36.72 ;
    END
  END dq[203]
  PIN dq[204]
    DIRECTION OUTPUT ;
    USE SIGNAL ;
    PORT
      LAYER M3 ;
        RECT  29.34 36.576 29.358 36.72 ;
    END
  END dq[204]
  PIN dq[205]
    DIRECTION OUTPUT ;
    USE SIGNAL ;
    PORT
      LAYER M5 ;
        RECT  29.472 36.528 29.496 36.72 ;
    END
  END dq[205]
  PIN dq[206]
    DIRECTION OUTPUT ;
    USE SIGNAL ;
    PORT
      LAYER M3 ;
        RECT  29.592 36.576 29.61 36.72 ;
    END
  END dq[206]
  PIN dq[207]
    DIRECTION OUTPUT ;
    USE SIGNAL ;
    PORT
      LAYER M5 ;
        RECT  29.712 36.528 29.736 36.72 ;
    END
  END dq[207]
  PIN dq[208]
    DIRECTION OUTPUT ;
    USE SIGNAL ;
    PORT
      LAYER M3 ;
        RECT  29.808 36.576 29.826 36.72 ;
    END
  END dq[208]
  PIN dq[209]
    DIRECTION OUTPUT ;
    USE SIGNAL ;
    PORT
      LAYER M5 ;
        RECT  29.952 36.528 29.976 36.72 ;
    END
  END dq[209]
  PIN dq[20]
    DIRECTION OUTPUT ;
    USE SIGNAL ;
    PORT
      LAYER M3 ;
        RECT  6.804 36.576 6.822 36.72 ;
    END
  END dq[20]
  PIN dq[210]
    DIRECTION OUTPUT ;
    USE SIGNAL ;
    PORT
      LAYER M3 ;
        RECT  30.06 36.576 30.078 36.72 ;
    END
  END dq[210]
  PIN dq[211]
    DIRECTION OUTPUT ;
    USE SIGNAL ;
    PORT
      LAYER M5 ;
        RECT  30.192 36.528 30.216 36.72 ;
    END
  END dq[211]
  PIN dq[212]
    DIRECTION OUTPUT ;
    USE SIGNAL ;
    PORT
      LAYER M3 ;
        RECT  30.312 36.576 30.33 36.72 ;
    END
  END dq[212]
  PIN dq[213]
    DIRECTION OUTPUT ;
    USE SIGNAL ;
    PORT
      LAYER M5 ;
        RECT  30.432 36.528 30.456 36.72 ;
    END
  END dq[213]
  PIN dq[214]
    DIRECTION OUTPUT ;
    USE SIGNAL ;
    PORT
      LAYER M3 ;
        RECT  30.564 36.576 30.582 36.72 ;
    END
  END dq[214]
  PIN dq[215]
    DIRECTION OUTPUT ;
    USE SIGNAL ;
    PORT
      LAYER M5 ;
        RECT  30.672 36.528 30.696 36.72 ;
    END
  END dq[215]
  PIN dq[216]
    DIRECTION OUTPUT ;
    USE SIGNAL ;
    PORT
      LAYER M3 ;
        RECT  30.816 36.576 30.834 36.72 ;
    END
  END dq[216]
  PIN dq[217]
    DIRECTION OUTPUT ;
    USE SIGNAL ;
    PORT
      LAYER M5 ;
        RECT  30.912 36.528 30.936 36.72 ;
    END
  END dq[217]
  PIN dq[218]
    DIRECTION OUTPUT ;
    USE SIGNAL ;
    PORT
      LAYER M3 ;
        RECT  31.032 36.576 31.05 36.72 ;
    END
  END dq[218]
  PIN dq[219]
    DIRECTION OUTPUT ;
    USE SIGNAL ;
    PORT
      LAYER M5 ;
        RECT  31.152 36.528 31.176 36.72 ;
    END
  END dq[219]
  PIN dq[21]
    DIRECTION OUTPUT ;
    USE SIGNAL ;
    PORT
      LAYER M5 ;
        RECT  6.96 36.528 6.984 36.72 ;
    END
  END dq[21]
  PIN dq[220]
    DIRECTION OUTPUT ;
    USE SIGNAL ;
    PORT
      LAYER M3 ;
        RECT  31.284 36.576 31.302 36.72 ;
    END
  END dq[220]
  PIN dq[221]
    DIRECTION OUTPUT ;
    USE SIGNAL ;
    PORT
      LAYER M5 ;
        RECT  31.392 36.528 31.416 36.72 ;
    END
  END dq[221]
  PIN dq[222]
    DIRECTION OUTPUT ;
    USE SIGNAL ;
    PORT
      LAYER M3 ;
        RECT  31.536 36.576 31.554 36.72 ;
    END
  END dq[222]
  PIN dq[223]
    DIRECTION OUTPUT ;
    USE SIGNAL ;
    PORT
      LAYER M5 ;
        RECT  31.68 36.528 31.704 36.72 ;
    END
  END dq[223]
  PIN dq[224]
    DIRECTION OUTPUT ;
    USE SIGNAL ;
    PORT
      LAYER M3 ;
        RECT  31.788 36.576 31.806 36.72 ;
    END
  END dq[224]
  PIN dq[225]
    DIRECTION OUTPUT ;
    USE SIGNAL ;
    PORT
      LAYER M5 ;
        RECT  31.92 36.528 31.944 36.72 ;
    END
  END dq[225]
  PIN dq[226]
    DIRECTION OUTPUT ;
    USE SIGNAL ;
    PORT
      LAYER M3 ;
        RECT  32.04 36.576 32.058 36.72 ;
    END
  END dq[226]
  PIN dq[227]
    DIRECTION OUTPUT ;
    USE SIGNAL ;
    PORT
      LAYER M5 ;
        RECT  32.16 36.528 32.184 36.72 ;
    END
  END dq[227]
  PIN dq[228]
    DIRECTION OUTPUT ;
    USE SIGNAL ;
    PORT
      LAYER M3 ;
        RECT  32.256 36.576 32.274 36.72 ;
    END
  END dq[228]
  PIN dq[229]
    DIRECTION OUTPUT ;
    USE SIGNAL ;
    PORT
      LAYER M5 ;
        RECT  32.4 36.528 32.424 36.72 ;
    END
  END dq[229]
  PIN dq[22]
    DIRECTION OUTPUT ;
    USE SIGNAL ;
    PORT
      LAYER M3 ;
        RECT  7.056 36.576 7.074 36.72 ;
    END
  END dq[22]
  PIN dq[230]
    DIRECTION OUTPUT ;
    USE SIGNAL ;
    PORT
      LAYER M3 ;
        RECT  32.508 36.576 32.526 36.72 ;
    END
  END dq[230]
  PIN dq[231]
    DIRECTION OUTPUT ;
    USE SIGNAL ;
    PORT
      LAYER M5 ;
        RECT  32.64 36.528 32.664 36.72 ;
    END
  END dq[231]
  PIN dq[232]
    DIRECTION OUTPUT ;
    USE SIGNAL ;
    PORT
      LAYER M3 ;
        RECT  32.76 36.576 32.778 36.72 ;
    END
  END dq[232]
  PIN dq[233]
    DIRECTION OUTPUT ;
    USE SIGNAL ;
    PORT
      LAYER M5 ;
        RECT  32.88 36.528 32.904 36.72 ;
    END
  END dq[233]
  PIN dq[234]
    DIRECTION OUTPUT ;
    USE SIGNAL ;
    PORT
      LAYER M3 ;
        RECT  33.012 36.576 33.03 36.72 ;
    END
  END dq[234]
  PIN dq[235]
    DIRECTION OUTPUT ;
    USE SIGNAL ;
    PORT
      LAYER M5 ;
        RECT  33.12 36.528 33.144 36.72 ;
    END
  END dq[235]
  PIN dq[236]
    DIRECTION OUTPUT ;
    USE SIGNAL ;
    PORT
      LAYER M3 ;
        RECT  33.264 36.576 33.282 36.72 ;
    END
  END dq[236]
  PIN dq[237]
    DIRECTION OUTPUT ;
    USE SIGNAL ;
    PORT
      LAYER M5 ;
        RECT  33.36 36.528 33.384 36.72 ;
    END
  END dq[237]
  PIN dq[238]
    DIRECTION OUTPUT ;
    USE SIGNAL ;
    PORT
      LAYER M3 ;
        RECT  33.48 36.576 33.498 36.72 ;
    END
  END dq[238]
  PIN dq[239]
    DIRECTION OUTPUT ;
    USE SIGNAL ;
    PORT
      LAYER M5 ;
        RECT  33.6 36.528 33.624 36.72 ;
    END
  END dq[239]
  PIN dq[23]
    DIRECTION OUTPUT ;
    USE SIGNAL ;
    PORT
      LAYER M5 ;
        RECT  7.2 36.528 7.224 36.72 ;
    END
  END dq[23]
  PIN dq[240]
    DIRECTION OUTPUT ;
    USE SIGNAL ;
    PORT
      LAYER M3 ;
        RECT  33.732 36.576 33.75 36.72 ;
    END
  END dq[240]
  PIN dq[241]
    DIRECTION OUTPUT ;
    USE SIGNAL ;
    PORT
      LAYER M5 ;
        RECT  33.84 36.528 33.864 36.72 ;
    END
  END dq[241]
  PIN dq[242]
    DIRECTION OUTPUT ;
    USE SIGNAL ;
    PORT
      LAYER M3 ;
        RECT  33.984 36.576 34.002 36.72 ;
    END
  END dq[242]
  PIN dq[243]
    DIRECTION OUTPUT ;
    USE SIGNAL ;
    PORT
      LAYER M5 ;
        RECT  34.128 36.528 34.152 36.72 ;
    END
  END dq[243]
  PIN dq[244]
    DIRECTION OUTPUT ;
    USE SIGNAL ;
    PORT
      LAYER M3 ;
        RECT  34.236 36.576 34.254 36.72 ;
    END
  END dq[244]
  PIN dq[245]
    DIRECTION OUTPUT ;
    USE SIGNAL ;
    PORT
      LAYER M5 ;
        RECT  34.368 36.528 34.392 36.72 ;
    END
  END dq[245]
  PIN dq[246]
    DIRECTION OUTPUT ;
    USE SIGNAL ;
    PORT
      LAYER M3 ;
        RECT  34.488 36.576 34.506 36.72 ;
    END
  END dq[246]
  PIN dq[247]
    DIRECTION OUTPUT ;
    USE SIGNAL ;
    PORT
      LAYER M5 ;
        RECT  34.608 36.528 34.632 36.72 ;
    END
  END dq[247]
  PIN dq[248]
    DIRECTION OUTPUT ;
    USE SIGNAL ;
    PORT
      LAYER M3 ;
        RECT  34.704 36.576 34.722 36.72 ;
    END
  END dq[248]
  PIN dq[249]
    DIRECTION OUTPUT ;
    USE SIGNAL ;
    PORT
      LAYER M5 ;
        RECT  34.848 36.528 34.872 36.72 ;
    END
  END dq[249]
  PIN dq[24]
    DIRECTION OUTPUT ;
    USE SIGNAL ;
    PORT
      LAYER M3 ;
        RECT  7.308 36.576 7.326 36.72 ;
    END
  END dq[24]
  PIN dq[250]
    DIRECTION OUTPUT ;
    USE SIGNAL ;
    PORT
      LAYER M3 ;
        RECT  34.956 36.576 34.974 36.72 ;
    END
  END dq[250]
  PIN dq[251]
    DIRECTION OUTPUT ;
    USE SIGNAL ;
    PORT
      LAYER M5 ;
        RECT  35.088 36.528 35.112 36.72 ;
    END
  END dq[251]
  PIN dq[252]
    DIRECTION OUTPUT ;
    USE SIGNAL ;
    PORT
      LAYER M3 ;
        RECT  35.208 36.576 35.226 36.72 ;
    END
  END dq[252]
  PIN dq[253]
    DIRECTION OUTPUT ;
    USE SIGNAL ;
    PORT
      LAYER M5 ;
        RECT  35.328 36.528 35.352 36.72 ;
    END
  END dq[253]
  PIN dq[254]
    DIRECTION OUTPUT ;
    USE SIGNAL ;
    PORT
      LAYER M3 ;
        RECT  35.46 36.576 35.478 36.72 ;
    END
  END dq[254]
  PIN dq[255]
    DIRECTION OUTPUT ;
    USE SIGNAL ;
    PORT
      LAYER M5 ;
        RECT  35.568 36.528 35.592 36.72 ;
    END
  END dq[255]
  PIN dq[256]
    DIRECTION OUTPUT ;
    USE SIGNAL ;
    PORT
      LAYER M3 ;
        RECT  35.712 36.576 35.73 36.72 ;
    END
  END dq[256]
  PIN dq[257]
    DIRECTION OUTPUT ;
    USE SIGNAL ;
    PORT
      LAYER M5 ;
        RECT  35.808 36.528 35.832 36.72 ;
    END
  END dq[257]
  PIN dq[258]
    DIRECTION OUTPUT ;
    USE SIGNAL ;
    PORT
      LAYER M3 ;
        RECT  35.928 36.576 35.946 36.72 ;
    END
  END dq[258]
  PIN dq[259]
    DIRECTION OUTPUT ;
    USE SIGNAL ;
    PORT
      LAYER M5 ;
        RECT  36.048 36.528 36.072 36.72 ;
    END
  END dq[259]
  PIN dq[25]
    DIRECTION OUTPUT ;
    USE SIGNAL ;
    PORT
      LAYER M5 ;
        RECT  7.44 36.528 7.464 36.72 ;
    END
  END dq[25]
  PIN dq[260]
    DIRECTION OUTPUT ;
    USE SIGNAL ;
    PORT
      LAYER M3 ;
        RECT  36.18 36.576 36.198 36.72 ;
    END
  END dq[260]
  PIN dq[261]
    DIRECTION OUTPUT ;
    USE SIGNAL ;
    PORT
      LAYER M5 ;
        RECT  36.288 36.528 36.312 36.72 ;
    END
  END dq[261]
  PIN dq[262]
    DIRECTION OUTPUT ;
    USE SIGNAL ;
    PORT
      LAYER M3 ;
        RECT  36.432 36.576 36.45 36.72 ;
    END
  END dq[262]
  PIN dq[263]
    DIRECTION OUTPUT ;
    USE SIGNAL ;
    PORT
      LAYER M5 ;
        RECT  36.576 36.528 36.6 36.72 ;
    END
  END dq[263]
  PIN dq[264]
    DIRECTION OUTPUT ;
    USE SIGNAL ;
    PORT
      LAYER M3 ;
        RECT  36.684 36.576 36.702 36.72 ;
    END
  END dq[264]
  PIN dq[265]
    DIRECTION OUTPUT ;
    USE SIGNAL ;
    PORT
      LAYER M5 ;
        RECT  36.816 36.528 36.84 36.72 ;
    END
  END dq[265]
  PIN dq[266]
    DIRECTION OUTPUT ;
    USE SIGNAL ;
    PORT
      LAYER M3 ;
        RECT  36.936 36.576 36.954 36.72 ;
    END
  END dq[266]
  PIN dq[267]
    DIRECTION OUTPUT ;
    USE SIGNAL ;
    PORT
      LAYER M5 ;
        RECT  37.056 36.528 37.08 36.72 ;
    END
  END dq[267]
  PIN dq[268]
    DIRECTION OUTPUT ;
    USE SIGNAL ;
    PORT
      LAYER M3 ;
        RECT  37.152 36.576 37.17 36.72 ;
    END
  END dq[268]
  PIN dq[269]
    DIRECTION OUTPUT ;
    USE SIGNAL ;
    PORT
      LAYER M5 ;
        RECT  37.296 36.528 37.32 36.72 ;
    END
  END dq[269]
  PIN dq[26]
    DIRECTION OUTPUT ;
    USE SIGNAL ;
    PORT
      LAYER M3 ;
        RECT  7.56 36.576 7.578 36.72 ;
    END
  END dq[26]
  PIN dq[270]
    DIRECTION OUTPUT ;
    USE SIGNAL ;
    PORT
      LAYER M3 ;
        RECT  37.404 36.576 37.422 36.72 ;
    END
  END dq[270]
  PIN dq[271]
    DIRECTION OUTPUT ;
    USE SIGNAL ;
    PORT
      LAYER M5 ;
        RECT  37.536 36.528 37.56 36.72 ;
    END
  END dq[271]
  PIN dq[272]
    DIRECTION OUTPUT ;
    USE SIGNAL ;
    PORT
      LAYER M3 ;
        RECT  37.656 36.576 37.674 36.72 ;
    END
  END dq[272]
  PIN dq[273]
    DIRECTION OUTPUT ;
    USE SIGNAL ;
    PORT
      LAYER M5 ;
        RECT  37.776 36.528 37.8 36.72 ;
    END
  END dq[273]
  PIN dq[274]
    DIRECTION OUTPUT ;
    USE SIGNAL ;
    PORT
      LAYER M3 ;
        RECT  37.908 36.576 37.926 36.72 ;
    END
  END dq[274]
  PIN dq[275]
    DIRECTION OUTPUT ;
    USE SIGNAL ;
    PORT
      LAYER M5 ;
        RECT  38.016 36.528 38.04 36.72 ;
    END
  END dq[275]
  PIN dq[276]
    DIRECTION OUTPUT ;
    USE SIGNAL ;
    PORT
      LAYER M3 ;
        RECT  38.16 36.576 38.178 36.72 ;
    END
  END dq[276]
  PIN dq[277]
    DIRECTION OUTPUT ;
    USE SIGNAL ;
    PORT
      LAYER M5 ;
        RECT  38.256 36.528 38.28 36.72 ;
    END
  END dq[277]
  PIN dq[278]
    DIRECTION OUTPUT ;
    USE SIGNAL ;
    PORT
      LAYER M3 ;
        RECT  38.376 36.576 38.394 36.72 ;
    END
  END dq[278]
  PIN dq[279]
    DIRECTION OUTPUT ;
    USE SIGNAL ;
    PORT
      LAYER M5 ;
        RECT  38.496 36.528 38.52 36.72 ;
    END
  END dq[279]
  PIN dq[27]
    DIRECTION OUTPUT ;
    USE SIGNAL ;
    PORT
      LAYER M5 ;
        RECT  7.68 36.528 7.704 36.72 ;
    END
  END dq[27]
  PIN dq[280]
    DIRECTION OUTPUT ;
    USE SIGNAL ;
    PORT
      LAYER M3 ;
        RECT  38.628 36.576 38.646 36.72 ;
    END
  END dq[280]
  PIN dq[281]
    DIRECTION OUTPUT ;
    USE SIGNAL ;
    PORT
      LAYER M5 ;
        RECT  38.736 36.528 38.76 36.72 ;
    END
  END dq[281]
  PIN dq[282]
    DIRECTION OUTPUT ;
    USE SIGNAL ;
    PORT
      LAYER M3 ;
        RECT  38.88 36.576 38.898 36.72 ;
    END
  END dq[282]
  PIN dq[283]
    DIRECTION OUTPUT ;
    USE SIGNAL ;
    PORT
      LAYER M5 ;
        RECT  39.024 36.528 39.048 36.72 ;
    END
  END dq[283]
  PIN dq[284]
    DIRECTION OUTPUT ;
    USE SIGNAL ;
    PORT
      LAYER M3 ;
        RECT  39.132 36.576 39.15 36.72 ;
    END
  END dq[284]
  PIN dq[285]
    DIRECTION OUTPUT ;
    USE SIGNAL ;
    PORT
      LAYER M5 ;
        RECT  39.264 36.528 39.288 36.72 ;
    END
  END dq[285]
  PIN dq[286]
    DIRECTION OUTPUT ;
    USE SIGNAL ;
    PORT
      LAYER M3 ;
        RECT  39.384 36.576 39.402 36.72 ;
    END
  END dq[286]
  PIN dq[287]
    DIRECTION OUTPUT ;
    USE SIGNAL ;
    PORT
      LAYER M5 ;
        RECT  39.504 36.528 39.528 36.72 ;
    END
  END dq[287]
  PIN dq[288]
    DIRECTION OUTPUT ;
    USE SIGNAL ;
    PORT
      LAYER M3 ;
        RECT  39.6 36.576 39.618 36.72 ;
    END
  END dq[288]
  PIN dq[289]
    DIRECTION OUTPUT ;
    USE SIGNAL ;
    PORT
      LAYER M5 ;
        RECT  39.744 36.528 39.768 36.72 ;
    END
  END dq[289]
  PIN dq[28]
    DIRECTION OUTPUT ;
    USE SIGNAL ;
    PORT
      LAYER M3 ;
        RECT  7.812 36.576 7.83 36.72 ;
    END
  END dq[28]
  PIN dq[290]
    DIRECTION OUTPUT ;
    USE SIGNAL ;
    PORT
      LAYER M3 ;
        RECT  39.852 36.576 39.87 36.72 ;
    END
  END dq[290]
  PIN dq[291]
    DIRECTION OUTPUT ;
    USE SIGNAL ;
    PORT
      LAYER M5 ;
        RECT  39.984 36.528 40.008 36.72 ;
    END
  END dq[291]
  PIN dq[292]
    DIRECTION OUTPUT ;
    USE SIGNAL ;
    PORT
      LAYER M3 ;
        RECT  40.104 36.576 40.122 36.72 ;
    END
  END dq[292]
  PIN dq[293]
    DIRECTION OUTPUT ;
    USE SIGNAL ;
    PORT
      LAYER M5 ;
        RECT  40.224 36.528 40.248 36.72 ;
    END
  END dq[293]
  PIN dq[294]
    DIRECTION OUTPUT ;
    USE SIGNAL ;
    PORT
      LAYER M3 ;
        RECT  40.356 36.576 40.374 36.72 ;
    END
  END dq[294]
  PIN dq[295]
    DIRECTION OUTPUT ;
    USE SIGNAL ;
    PORT
      LAYER M5 ;
        RECT  40.464 36.528 40.488 36.72 ;
    END
  END dq[295]
  PIN dq[296]
    DIRECTION OUTPUT ;
    USE SIGNAL ;
    PORT
      LAYER M3 ;
        RECT  40.608 36.576 40.626 36.72 ;
    END
  END dq[296]
  PIN dq[297]
    DIRECTION OUTPUT ;
    USE SIGNAL ;
    PORT
      LAYER M5 ;
        RECT  40.704 36.528 40.728 36.72 ;
    END
  END dq[297]
  PIN dq[298]
    DIRECTION OUTPUT ;
    USE SIGNAL ;
    PORT
      LAYER M3 ;
        RECT  40.824 36.576 40.842 36.72 ;
    END
  END dq[298]
  PIN dq[299]
    DIRECTION OUTPUT ;
    USE SIGNAL ;
    PORT
      LAYER M5 ;
        RECT  40.944 36.528 40.968 36.72 ;
    END
  END dq[299]
  PIN dq[29]
    DIRECTION OUTPUT ;
    USE SIGNAL ;
    PORT
      LAYER M5 ;
        RECT  7.92 36.528 7.944 36.72 ;
    END
  END dq[29]
  PIN dq[2]
    DIRECTION OUTPUT ;
    USE SIGNAL ;
    PORT
      LAYER M3 ;
        RECT  4.608 36.576 4.626 36.72 ;
    END
  END dq[2]
  PIN dq[300]
    DIRECTION OUTPUT ;
    USE SIGNAL ;
    PORT
      LAYER M3 ;
        RECT  41.076 36.576 41.094 36.72 ;
    END
  END dq[300]
  PIN dq[301]
    DIRECTION OUTPUT ;
    USE SIGNAL ;
    PORT
      LAYER M5 ;
        RECT  41.184 36.528 41.208 36.72 ;
    END
  END dq[301]
  PIN dq[302]
    DIRECTION OUTPUT ;
    USE SIGNAL ;
    PORT
      LAYER M3 ;
        RECT  41.328 36.576 41.346 36.72 ;
    END
  END dq[302]
  PIN dq[303]
    DIRECTION OUTPUT ;
    USE SIGNAL ;
    PORT
      LAYER M5 ;
        RECT  41.424 36.528 41.448 36.72 ;
    END
  END dq[303]
  PIN dq[304]
    DIRECTION OUTPUT ;
    USE SIGNAL ;
    PORT
      LAYER M3 ;
        RECT  41.58 36.576 41.598 36.72 ;
    END
  END dq[304]
  PIN dq[305]
    DIRECTION OUTPUT ;
    USE SIGNAL ;
    PORT
      LAYER M5 ;
        RECT  41.712 36.528 41.736 36.72 ;
    END
  END dq[305]
  PIN dq[306]
    DIRECTION OUTPUT ;
    USE SIGNAL ;
    PORT
      LAYER M3 ;
        RECT  41.832 36.576 41.85 36.72 ;
    END
  END dq[306]
  PIN dq[307]
    DIRECTION OUTPUT ;
    USE SIGNAL ;
    PORT
      LAYER M5 ;
        RECT  41.952 36.528 41.976 36.72 ;
    END
  END dq[307]
  PIN dq[308]
    DIRECTION OUTPUT ;
    USE SIGNAL ;
    PORT
      LAYER M3 ;
        RECT  42.048 36.576 42.066 36.72 ;
    END
  END dq[308]
  PIN dq[309]
    DIRECTION OUTPUT ;
    USE SIGNAL ;
    PORT
      LAYER M5 ;
        RECT  42.192 36.528 42.216 36.72 ;
    END
  END dq[309]
  PIN dq[30]
    DIRECTION OUTPUT ;
    USE SIGNAL ;
    PORT
      LAYER M3 ;
        RECT  8.028 36.576 8.046 36.72 ;
    END
  END dq[30]
  PIN dq[310]
    DIRECTION OUTPUT ;
    USE SIGNAL ;
    PORT
      LAYER M3 ;
        RECT  42.3 36.576 42.318 36.72 ;
    END
  END dq[310]
  PIN dq[311]
    DIRECTION OUTPUT ;
    USE SIGNAL ;
    PORT
      LAYER M5 ;
        RECT  42.432 36.528 42.456 36.72 ;
    END
  END dq[311]
  PIN dq[312]
    DIRECTION OUTPUT ;
    USE SIGNAL ;
    PORT
      LAYER M3 ;
        RECT  42.552 36.576 42.57 36.72 ;
    END
  END dq[312]
  PIN dq[313]
    DIRECTION OUTPUT ;
    USE SIGNAL ;
    PORT
      LAYER M5 ;
        RECT  42.672 36.528 42.696 36.72 ;
    END
  END dq[313]
  PIN dq[314]
    DIRECTION OUTPUT ;
    USE SIGNAL ;
    PORT
      LAYER M3 ;
        RECT  42.804 36.576 42.822 36.72 ;
    END
  END dq[314]
  PIN dq[315]
    DIRECTION OUTPUT ;
    USE SIGNAL ;
    PORT
      LAYER M5 ;
        RECT  42.912 36.528 42.936 36.72 ;
    END
  END dq[315]
  PIN dq[316]
    DIRECTION OUTPUT ;
    USE SIGNAL ;
    PORT
      LAYER M3 ;
        RECT  43.056 36.576 43.074 36.72 ;
    END
  END dq[316]
  PIN dq[317]
    DIRECTION OUTPUT ;
    USE SIGNAL ;
    PORT
      LAYER M5 ;
        RECT  43.152 36.528 43.176 36.72 ;
    END
  END dq[317]
  PIN dq[318]
    DIRECTION OUTPUT ;
    USE SIGNAL ;
    PORT
      LAYER M3 ;
        RECT  43.272 36.576 43.29 36.72 ;
    END
  END dq[318]
  PIN dq[319]
    DIRECTION OUTPUT ;
    USE SIGNAL ;
    PORT
      LAYER M5 ;
        RECT  43.392 36.528 43.416 36.72 ;
    END
  END dq[319]
  PIN dq[31]
    DIRECTION OUTPUT ;
    USE SIGNAL ;
    PORT
      LAYER M5 ;
        RECT  8.16 36.528 8.184 36.72 ;
    END
  END dq[31]
  PIN dq[320]
    DIRECTION OUTPUT ;
    USE SIGNAL ;
    PORT
      LAYER M3 ;
        RECT  43.524 36.576 43.542 36.72 ;
    END
  END dq[320]
  PIN dq[321]
    DIRECTION OUTPUT ;
    USE SIGNAL ;
    PORT
      LAYER M5 ;
        RECT  43.632 36.528 43.656 36.72 ;
    END
  END dq[321]
  PIN dq[322]
    DIRECTION OUTPUT ;
    USE SIGNAL ;
    PORT
      LAYER M3 ;
        RECT  43.776 36.576 43.794 36.72 ;
    END
  END dq[322]
  PIN dq[323]
    DIRECTION OUTPUT ;
    USE SIGNAL ;
    PORT
      LAYER M5 ;
        RECT  43.872 36.528 43.896 36.72 ;
    END
  END dq[323]
  PIN dq[324]
    DIRECTION OUTPUT ;
    USE SIGNAL ;
    PORT
      LAYER M3 ;
        RECT  44.028 36.576 44.046 36.72 ;
    END
  END dq[324]
  PIN dq[325]
    DIRECTION OUTPUT ;
    USE SIGNAL ;
    PORT
      LAYER M5 ;
        RECT  44.16 36.528 44.184 36.72 ;
    END
  END dq[325]
  PIN dq[326]
    DIRECTION OUTPUT ;
    USE SIGNAL ;
    PORT
      LAYER M3 ;
        RECT  44.28 36.576 44.298 36.72 ;
    END
  END dq[326]
  PIN dq[327]
    DIRECTION OUTPUT ;
    USE SIGNAL ;
    PORT
      LAYER M5 ;
        RECT  44.4 36.528 44.424 36.72 ;
    END
  END dq[327]
  PIN dq[328]
    DIRECTION OUTPUT ;
    USE SIGNAL ;
    PORT
      LAYER M3 ;
        RECT  44.496 36.576 44.514 36.72 ;
    END
  END dq[328]
  PIN dq[329]
    DIRECTION OUTPUT ;
    USE SIGNAL ;
    PORT
      LAYER M5 ;
        RECT  44.64 36.528 44.664 36.72 ;
    END
  END dq[329]
  PIN dq[32]
    DIRECTION OUTPUT ;
    USE SIGNAL ;
    PORT
      LAYER M3 ;
        RECT  8.28 36.576 8.298 36.72 ;
    END
  END dq[32]
  PIN dq[330]
    DIRECTION OUTPUT ;
    USE SIGNAL ;
    PORT
      LAYER M3 ;
        RECT  44.748 36.576 44.766 36.72 ;
    END
  END dq[330]
  PIN dq[331]
    DIRECTION OUTPUT ;
    USE SIGNAL ;
    PORT
      LAYER M5 ;
        RECT  44.88 36.528 44.904 36.72 ;
    END
  END dq[331]
  PIN dq[332]
    DIRECTION OUTPUT ;
    USE SIGNAL ;
    PORT
      LAYER M3 ;
        RECT  45 36.576 45.018 36.72 ;
    END
  END dq[332]
  PIN dq[333]
    DIRECTION OUTPUT ;
    USE SIGNAL ;
    PORT
      LAYER M5 ;
        RECT  45.12 36.528 45.144 36.72 ;
    END
  END dq[333]
  PIN dq[334]
    DIRECTION OUTPUT ;
    USE SIGNAL ;
    PORT
      LAYER M3 ;
        RECT  45.252 36.576 45.27 36.72 ;
    END
  END dq[334]
  PIN dq[335]
    DIRECTION OUTPUT ;
    USE SIGNAL ;
    PORT
      LAYER M5 ;
        RECT  45.36 36.528 45.384 36.72 ;
    END
  END dq[335]
  PIN dq[336]
    DIRECTION OUTPUT ;
    USE SIGNAL ;
    PORT
      LAYER M3 ;
        RECT  45.504 36.576 45.522 36.72 ;
    END
  END dq[336]
  PIN dq[337]
    DIRECTION OUTPUT ;
    USE SIGNAL ;
    PORT
      LAYER M5 ;
        RECT  45.6 36.528 45.624 36.72 ;
    END
  END dq[337]
  PIN dq[338]
    DIRECTION OUTPUT ;
    USE SIGNAL ;
    PORT
      LAYER M3 ;
        RECT  45.72 36.576 45.738 36.72 ;
    END
  END dq[338]
  PIN dq[339]
    DIRECTION OUTPUT ;
    USE SIGNAL ;
    PORT
      LAYER M5 ;
        RECT  45.84 36.528 45.864 36.72 ;
    END
  END dq[339]
  PIN dq[33]
    DIRECTION OUTPUT ;
    USE SIGNAL ;
    PORT
      LAYER M5 ;
        RECT  8.4 36.528 8.424 36.72 ;
    END
  END dq[33]
  PIN dq[340]
    DIRECTION OUTPUT ;
    USE SIGNAL ;
    PORT
      LAYER M3 ;
        RECT  45.972 36.576 45.99 36.72 ;
    END
  END dq[340]
  PIN dq[341]
    DIRECTION OUTPUT ;
    USE SIGNAL ;
    PORT
      LAYER M5 ;
        RECT  46.08 36.528 46.104 36.72 ;
    END
  END dq[341]
  PIN dq[342]
    DIRECTION OUTPUT ;
    USE SIGNAL ;
    PORT
      LAYER M3 ;
        RECT  46.224 36.576 46.242 36.72 ;
    END
  END dq[342]
  PIN dq[343]
    DIRECTION OUTPUT ;
    USE SIGNAL ;
    PORT
      LAYER M5 ;
        RECT  46.32 36.528 46.344 36.72 ;
    END
  END dq[343]
  PIN dq[344]
    DIRECTION OUTPUT ;
    USE SIGNAL ;
    PORT
      LAYER M3 ;
        RECT  46.476 36.576 46.494 36.72 ;
    END
  END dq[344]
  PIN dq[345]
    DIRECTION OUTPUT ;
    USE SIGNAL ;
    PORT
      LAYER M5 ;
        RECT  46.608 36.528 46.632 36.72 ;
    END
  END dq[345]
  PIN dq[346]
    DIRECTION OUTPUT ;
    USE SIGNAL ;
    PORT
      LAYER M3 ;
        RECT  46.728 36.576 46.746 36.72 ;
    END
  END dq[346]
  PIN dq[347]
    DIRECTION OUTPUT ;
    USE SIGNAL ;
    PORT
      LAYER M5 ;
        RECT  46.848 36.528 46.872 36.72 ;
    END
  END dq[347]
  PIN dq[348]
    DIRECTION OUTPUT ;
    USE SIGNAL ;
    PORT
      LAYER M3 ;
        RECT  46.944 36.576 46.962 36.72 ;
    END
  END dq[348]
  PIN dq[349]
    DIRECTION OUTPUT ;
    USE SIGNAL ;
    PORT
      LAYER M5 ;
        RECT  47.088 36.528 47.112 36.72 ;
    END
  END dq[349]
  PIN dq[34]
    DIRECTION OUTPUT ;
    USE SIGNAL ;
    PORT
      LAYER M3 ;
        RECT  8.532 36.576 8.55 36.72 ;
    END
  END dq[34]
  PIN dq[350]
    DIRECTION OUTPUT ;
    USE SIGNAL ;
    PORT
      LAYER M3 ;
        RECT  47.196 36.576 47.214 36.72 ;
    END
  END dq[350]
  PIN dq[351]
    DIRECTION OUTPUT ;
    USE SIGNAL ;
    PORT
      LAYER M5 ;
        RECT  47.328 36.528 47.352 36.72 ;
    END
  END dq[351]
  PIN dq[352]
    DIRECTION OUTPUT ;
    USE SIGNAL ;
    PORT
      LAYER M3 ;
        RECT  47.448 36.576 47.466 36.72 ;
    END
  END dq[352]
  PIN dq[353]
    DIRECTION OUTPUT ;
    USE SIGNAL ;
    PORT
      LAYER M5 ;
        RECT  47.568 36.528 47.592 36.72 ;
    END
  END dq[353]
  PIN dq[354]
    DIRECTION OUTPUT ;
    USE SIGNAL ;
    PORT
      LAYER M3 ;
        RECT  47.7 36.576 47.718 36.72 ;
    END
  END dq[354]
  PIN dq[355]
    DIRECTION OUTPUT ;
    USE SIGNAL ;
    PORT
      LAYER M5 ;
        RECT  47.808 36.528 47.832 36.72 ;
    END
  END dq[355]
  PIN dq[356]
    DIRECTION OUTPUT ;
    USE SIGNAL ;
    PORT
      LAYER M3 ;
        RECT  47.952 36.576 47.97 36.72 ;
    END
  END dq[356]
  PIN dq[357]
    DIRECTION OUTPUT ;
    USE SIGNAL ;
    PORT
      LAYER M5 ;
        RECT  48.048 36.528 48.072 36.72 ;
    END
  END dq[357]
  PIN dq[358]
    DIRECTION OUTPUT ;
    USE SIGNAL ;
    PORT
      LAYER M3 ;
        RECT  48.168 36.576 48.186 36.72 ;
    END
  END dq[358]
  PIN dq[359]
    DIRECTION OUTPUT ;
    USE SIGNAL ;
    PORT
      LAYER M5 ;
        RECT  48.288 36.528 48.312 36.72 ;
    END
  END dq[359]
  PIN dq[35]
    DIRECTION OUTPUT ;
    USE SIGNAL ;
    PORT
      LAYER M5 ;
        RECT  8.64 36.528 8.664 36.72 ;
    END
  END dq[35]
  PIN dq[360]
    DIRECTION OUTPUT ;
    USE SIGNAL ;
    PORT
      LAYER M3 ;
        RECT  48.42 36.576 48.438 36.72 ;
    END
  END dq[360]
  PIN dq[361]
    DIRECTION OUTPUT ;
    USE SIGNAL ;
    PORT
      LAYER M5 ;
        RECT  48.528 36.528 48.552 36.72 ;
    END
  END dq[361]
  PIN dq[362]
    DIRECTION OUTPUT ;
    USE SIGNAL ;
    PORT
      LAYER M3 ;
        RECT  48.672 36.576 48.69 36.72 ;
    END
  END dq[362]
  PIN dq[363]
    DIRECTION OUTPUT ;
    USE SIGNAL ;
    PORT
      LAYER M5 ;
        RECT  48.768 36.528 48.792 36.72 ;
    END
  END dq[363]
  PIN dq[364]
    DIRECTION OUTPUT ;
    USE SIGNAL ;
    PORT
      LAYER M3 ;
        RECT  48.924 36.576 48.942 36.72 ;
    END
  END dq[364]
  PIN dq[365]
    DIRECTION OUTPUT ;
    USE SIGNAL ;
    PORT
      LAYER M5 ;
        RECT  49.056 36.528 49.08 36.72 ;
    END
  END dq[365]
  PIN dq[366]
    DIRECTION OUTPUT ;
    USE SIGNAL ;
    PORT
      LAYER M3 ;
        RECT  49.176 36.576 49.194 36.72 ;
    END
  END dq[366]
  PIN dq[367]
    DIRECTION OUTPUT ;
    USE SIGNAL ;
    PORT
      LAYER M5 ;
        RECT  49.296 36.528 49.32 36.72 ;
    END
  END dq[367]
  PIN dq[368]
    DIRECTION OUTPUT ;
    USE SIGNAL ;
    PORT
      LAYER M3 ;
        RECT  49.392 36.576 49.41 36.72 ;
    END
  END dq[368]
  PIN dq[369]
    DIRECTION OUTPUT ;
    USE SIGNAL ;
    PORT
      LAYER M5 ;
        RECT  49.536 36.528 49.56 36.72 ;
    END
  END dq[369]
  PIN dq[36]
    DIRECTION OUTPUT ;
    USE SIGNAL ;
    PORT
      LAYER M3 ;
        RECT  8.784 36.576 8.802 36.72 ;
    END
  END dq[36]
  PIN dq[370]
    DIRECTION OUTPUT ;
    USE SIGNAL ;
    PORT
      LAYER M3 ;
        RECT  49.644 36.576 49.662 36.72 ;
    END
  END dq[370]
  PIN dq[371]
    DIRECTION OUTPUT ;
    USE SIGNAL ;
    PORT
      LAYER M5 ;
        RECT  49.776 36.528 49.8 36.72 ;
    END
  END dq[371]
  PIN dq[372]
    DIRECTION OUTPUT ;
    USE SIGNAL ;
    PORT
      LAYER M3 ;
        RECT  49.896 36.576 49.914 36.72 ;
    END
  END dq[372]
  PIN dq[373]
    DIRECTION OUTPUT ;
    USE SIGNAL ;
    PORT
      LAYER M5 ;
        RECT  50.016 36.528 50.04 36.72 ;
    END
  END dq[373]
  PIN dq[374]
    DIRECTION OUTPUT ;
    USE SIGNAL ;
    PORT
      LAYER M3 ;
        RECT  50.148 36.576 50.166 36.72 ;
    END
  END dq[374]
  PIN dq[375]
    DIRECTION OUTPUT ;
    USE SIGNAL ;
    PORT
      LAYER M5 ;
        RECT  50.256 36.528 50.28 36.72 ;
    END
  END dq[375]
  PIN dq[376]
    DIRECTION OUTPUT ;
    USE SIGNAL ;
    PORT
      LAYER M3 ;
        RECT  50.4 36.576 50.418 36.72 ;
    END
  END dq[376]
  PIN dq[377]
    DIRECTION OUTPUT ;
    USE SIGNAL ;
    PORT
      LAYER M5 ;
        RECT  50.496 36.528 50.52 36.72 ;
    END
  END dq[377]
  PIN dq[378]
    DIRECTION OUTPUT ;
    USE SIGNAL ;
    PORT
      LAYER M3 ;
        RECT  50.616 36.576 50.634 36.72 ;
    END
  END dq[378]
  PIN dq[379]
    DIRECTION OUTPUT ;
    USE SIGNAL ;
    PORT
      LAYER M5 ;
        RECT  50.736 36.528 50.76 36.72 ;
    END
  END dq[379]
  PIN dq[37]
    DIRECTION OUTPUT ;
    USE SIGNAL ;
    PORT
      LAYER M5 ;
        RECT  8.88 36.528 8.904 36.72 ;
    END
  END dq[37]
  PIN dq[380]
    DIRECTION OUTPUT ;
    USE SIGNAL ;
    PORT
      LAYER M3 ;
        RECT  50.868 36.576 50.886 36.72 ;
    END
  END dq[380]
  PIN dq[381]
    DIRECTION OUTPUT ;
    USE SIGNAL ;
    PORT
      LAYER M5 ;
        RECT  50.976 36.528 51 36.72 ;
    END
  END dq[381]
  PIN dq[382]
    DIRECTION OUTPUT ;
    USE SIGNAL ;
    PORT
      LAYER M3 ;
        RECT  51.12 36.576 51.138 36.72 ;
    END
  END dq[382]
  PIN dq[383]
    DIRECTION OUTPUT ;
    USE SIGNAL ;
    PORT
      LAYER M5 ;
        RECT  51.216 36.528 51.24 36.72 ;
    END
  END dq[383]
  PIN dq[384]
    DIRECTION OUTPUT ;
    USE SIGNAL ;
    PORT
      LAYER M3 ;
        RECT  51.372 36.576 51.39 36.72 ;
    END
  END dq[384]
  PIN dq[385]
    DIRECTION OUTPUT ;
    USE SIGNAL ;
    PORT
      LAYER M5 ;
        RECT  51.504 36.528 51.528 36.72 ;
    END
  END dq[385]
  PIN dq[386]
    DIRECTION OUTPUT ;
    USE SIGNAL ;
    PORT
      LAYER M3 ;
        RECT  51.624 36.576 51.642 36.72 ;
    END
  END dq[386]
  PIN dq[387]
    DIRECTION OUTPUT ;
    USE SIGNAL ;
    PORT
      LAYER M5 ;
        RECT  51.744 36.528 51.768 36.72 ;
    END
  END dq[387]
  PIN dq[388]
    DIRECTION OUTPUT ;
    USE SIGNAL ;
    PORT
      LAYER M3 ;
        RECT  51.84 36.576 51.858 36.72 ;
    END
  END dq[388]
  PIN dq[389]
    DIRECTION OUTPUT ;
    USE SIGNAL ;
    PORT
      LAYER M5 ;
        RECT  51.984 36.528 52.008 36.72 ;
    END
  END dq[389]
  PIN dq[38]
    DIRECTION OUTPUT ;
    USE SIGNAL ;
    PORT
      LAYER M3 ;
        RECT  9.036 36.576 9.054 36.72 ;
    END
  END dq[38]
  PIN dq[390]
    DIRECTION OUTPUT ;
    USE SIGNAL ;
    PORT
      LAYER M3 ;
        RECT  52.092 36.576 52.11 36.72 ;
    END
  END dq[390]
  PIN dq[391]
    DIRECTION OUTPUT ;
    USE SIGNAL ;
    PORT
      LAYER M5 ;
        RECT  52.224 36.528 52.248 36.72 ;
    END
  END dq[391]
  PIN dq[392]
    DIRECTION OUTPUT ;
    USE SIGNAL ;
    PORT
      LAYER M3 ;
        RECT  52.344 36.576 52.362 36.72 ;
    END
  END dq[392]
  PIN dq[393]
    DIRECTION OUTPUT ;
    USE SIGNAL ;
    PORT
      LAYER M5 ;
        RECT  52.464 36.528 52.488 36.72 ;
    END
  END dq[393]
  PIN dq[394]
    DIRECTION OUTPUT ;
    USE SIGNAL ;
    PORT
      LAYER M3 ;
        RECT  52.596 36.576 52.614 36.72 ;
    END
  END dq[394]
  PIN dq[395]
    DIRECTION OUTPUT ;
    USE SIGNAL ;
    PORT
      LAYER M5 ;
        RECT  52.704 36.528 52.728 36.72 ;
    END
  END dq[395]
  PIN dq[396]
    DIRECTION OUTPUT ;
    USE SIGNAL ;
    PORT
      LAYER M3 ;
        RECT  52.848 36.576 52.866 36.72 ;
    END
  END dq[396]
  PIN dq[397]
    DIRECTION OUTPUT ;
    USE SIGNAL ;
    PORT
      LAYER M5 ;
        RECT  52.944 36.528 52.968 36.72 ;
    END
  END dq[397]
  PIN dq[398]
    DIRECTION OUTPUT ;
    USE SIGNAL ;
    PORT
      LAYER M3 ;
        RECT  53.064 36.576 53.082 36.72 ;
    END
  END dq[398]
  PIN dq[399]
    DIRECTION OUTPUT ;
    USE SIGNAL ;
    PORT
      LAYER M5 ;
        RECT  53.184 36.528 53.208 36.72 ;
    END
  END dq[399]
  PIN dq[39]
    DIRECTION OUTPUT ;
    USE SIGNAL ;
    PORT
      LAYER M5 ;
        RECT  9.12 36.528 9.144 36.72 ;
    END
  END dq[39]
  PIN dq[3]
    DIRECTION OUTPUT ;
    USE SIGNAL ;
    PORT
      LAYER M5 ;
        RECT  4.752 36.528 4.776 36.72 ;
    END
  END dq[3]
  PIN dq[400]
    DIRECTION OUTPUT ;
    USE SIGNAL ;
    PORT
      LAYER M3 ;
        RECT  53.316 36.576 53.334 36.72 ;
    END
  END dq[400]
  PIN dq[401]
    DIRECTION OUTPUT ;
    USE SIGNAL ;
    PORT
      LAYER M5 ;
        RECT  53.424 36.528 53.448 36.72 ;
    END
  END dq[401]
  PIN dq[402]
    DIRECTION OUTPUT ;
    USE SIGNAL ;
    PORT
      LAYER M3 ;
        RECT  53.568 36.576 53.586 36.72 ;
    END
  END dq[402]
  PIN dq[403]
    DIRECTION OUTPUT ;
    USE SIGNAL ;
    PORT
      LAYER M5 ;
        RECT  53.664 36.528 53.688 36.72 ;
    END
  END dq[403]
  PIN dq[404]
    DIRECTION OUTPUT ;
    USE SIGNAL ;
    PORT
      LAYER M3 ;
        RECT  53.82 36.576 53.838 36.72 ;
    END
  END dq[404]
  PIN dq[405]
    DIRECTION OUTPUT ;
    USE SIGNAL ;
    PORT
      LAYER M5 ;
        RECT  53.952 36.528 53.976 36.72 ;
    END
  END dq[405]
  PIN dq[406]
    DIRECTION OUTPUT ;
    USE SIGNAL ;
    PORT
      LAYER M3 ;
        RECT  54.072 36.576 54.09 36.72 ;
    END
  END dq[406]
  PIN dq[407]
    DIRECTION OUTPUT ;
    USE SIGNAL ;
    PORT
      LAYER M5 ;
        RECT  54.192 36.528 54.216 36.72 ;
    END
  END dq[407]
  PIN dq[408]
    DIRECTION OUTPUT ;
    USE SIGNAL ;
    PORT
      LAYER M3 ;
        RECT  54.288 36.576 54.306 36.72 ;
    END
  END dq[408]
  PIN dq[409]
    DIRECTION OUTPUT ;
    USE SIGNAL ;
    PORT
      LAYER M5 ;
        RECT  54.432 36.528 54.456 36.72 ;
    END
  END dq[409]
  PIN dq[40]
    DIRECTION OUTPUT ;
    USE SIGNAL ;
    PORT
      LAYER M3 ;
        RECT  9.252 36.576 9.27 36.72 ;
    END
  END dq[40]
  PIN dq[410]
    DIRECTION OUTPUT ;
    USE SIGNAL ;
    PORT
      LAYER M3 ;
        RECT  54.54 36.576 54.558 36.72 ;
    END
  END dq[410]
  PIN dq[411]
    DIRECTION OUTPUT ;
    USE SIGNAL ;
    PORT
      LAYER M5 ;
        RECT  54.672 36.528 54.696 36.72 ;
    END
  END dq[411]
  PIN dq[412]
    DIRECTION OUTPUT ;
    USE SIGNAL ;
    PORT
      LAYER M3 ;
        RECT  54.792 36.576 54.81 36.72 ;
    END
  END dq[412]
  PIN dq[413]
    DIRECTION OUTPUT ;
    USE SIGNAL ;
    PORT
      LAYER M5 ;
        RECT  54.912 36.528 54.936 36.72 ;
    END
  END dq[413]
  PIN dq[414]
    DIRECTION OUTPUT ;
    USE SIGNAL ;
    PORT
      LAYER M3 ;
        RECT  55.044 36.576 55.062 36.72 ;
    END
  END dq[414]
  PIN dq[415]
    DIRECTION OUTPUT ;
    USE SIGNAL ;
    PORT
      LAYER M5 ;
        RECT  55.152 36.528 55.176 36.72 ;
    END
  END dq[415]
  PIN dq[416]
    DIRECTION OUTPUT ;
    USE SIGNAL ;
    PORT
      LAYER M3 ;
        RECT  55.296 36.576 55.314 36.72 ;
    END
  END dq[416]
  PIN dq[417]
    DIRECTION OUTPUT ;
    USE SIGNAL ;
    PORT
      LAYER M5 ;
        RECT  55.392 36.528 55.416 36.72 ;
    END
  END dq[417]
  PIN dq[418]
    DIRECTION OUTPUT ;
    USE SIGNAL ;
    PORT
      LAYER M3 ;
        RECT  55.512 36.576 55.53 36.72 ;
    END
  END dq[418]
  PIN dq[419]
    DIRECTION OUTPUT ;
    USE SIGNAL ;
    PORT
      LAYER M5 ;
        RECT  55.632 36.528 55.656 36.72 ;
    END
  END dq[419]
  PIN dq[41]
    DIRECTION OUTPUT ;
    USE SIGNAL ;
    PORT
      LAYER M5 ;
        RECT  9.408 36.528 9.432 36.72 ;
    END
  END dq[41]
  PIN dq[420]
    DIRECTION OUTPUT ;
    USE SIGNAL ;
    PORT
      LAYER M3 ;
        RECT  55.764 36.576 55.782 36.72 ;
    END
  END dq[420]
  PIN dq[421]
    DIRECTION OUTPUT ;
    USE SIGNAL ;
    PORT
      LAYER M5 ;
        RECT  55.872 36.528 55.896 36.72 ;
    END
  END dq[421]
  PIN dq[422]
    DIRECTION OUTPUT ;
    USE SIGNAL ;
    PORT
      LAYER M3 ;
        RECT  56.016 36.576 56.034 36.72 ;
    END
  END dq[422]
  PIN dq[423]
    DIRECTION OUTPUT ;
    USE SIGNAL ;
    PORT
      LAYER M5 ;
        RECT  56.112 36.528 56.136 36.72 ;
    END
  END dq[423]
  PIN dq[424]
    DIRECTION OUTPUT ;
    USE SIGNAL ;
    PORT
      LAYER M3 ;
        RECT  56.268 36.576 56.286 36.72 ;
    END
  END dq[424]
  PIN dq[425]
    DIRECTION OUTPUT ;
    USE SIGNAL ;
    PORT
      LAYER M5 ;
        RECT  56.4 36.528 56.424 36.72 ;
    END
  END dq[425]
  PIN dq[426]
    DIRECTION OUTPUT ;
    USE SIGNAL ;
    PORT
      LAYER M3 ;
        RECT  56.52 36.576 56.538 36.72 ;
    END
  END dq[426]
  PIN dq[427]
    DIRECTION OUTPUT ;
    USE SIGNAL ;
    PORT
      LAYER M5 ;
        RECT  56.64 36.528 56.664 36.72 ;
    END
  END dq[427]
  PIN dq[428]
    DIRECTION OUTPUT ;
    USE SIGNAL ;
    PORT
      LAYER M3 ;
        RECT  56.736 36.576 56.754 36.72 ;
    END
  END dq[428]
  PIN dq[429]
    DIRECTION OUTPUT ;
    USE SIGNAL ;
    PORT
      LAYER M5 ;
        RECT  56.88 36.528 56.904 36.72 ;
    END
  END dq[429]
  PIN dq[42]
    DIRECTION OUTPUT ;
    USE SIGNAL ;
    PORT
      LAYER M3 ;
        RECT  9.504 36.576 9.522 36.72 ;
    END
  END dq[42]
  PIN dq[430]
    DIRECTION OUTPUT ;
    USE SIGNAL ;
    PORT
      LAYER M3 ;
        RECT  56.988 36.576 57.006 36.72 ;
    END
  END dq[430]
  PIN dq[431]
    DIRECTION OUTPUT ;
    USE SIGNAL ;
    PORT
      LAYER M5 ;
        RECT  57.12 36.528 57.144 36.72 ;
    END
  END dq[431]
  PIN dq[432]
    DIRECTION OUTPUT ;
    USE SIGNAL ;
    PORT
      LAYER M3 ;
        RECT  57.24 36.576 57.258 36.72 ;
    END
  END dq[432]
  PIN dq[433]
    DIRECTION OUTPUT ;
    USE SIGNAL ;
    PORT
      LAYER M5 ;
        RECT  57.36 36.528 57.384 36.72 ;
    END
  END dq[433]
  PIN dq[434]
    DIRECTION OUTPUT ;
    USE SIGNAL ;
    PORT
      LAYER M3 ;
        RECT  57.492 36.576 57.51 36.72 ;
    END
  END dq[434]
  PIN dq[435]
    DIRECTION OUTPUT ;
    USE SIGNAL ;
    PORT
      LAYER M5 ;
        RECT  57.6 36.528 57.624 36.72 ;
    END
  END dq[435]
  PIN dq[436]
    DIRECTION OUTPUT ;
    USE SIGNAL ;
    PORT
      LAYER M3 ;
        RECT  57.744 36.576 57.762 36.72 ;
    END
  END dq[436]
  PIN dq[437]
    DIRECTION OUTPUT ;
    USE SIGNAL ;
    PORT
      LAYER M5 ;
        RECT  57.84 36.528 57.864 36.72 ;
    END
  END dq[437]
  PIN dq[438]
    DIRECTION OUTPUT ;
    USE SIGNAL ;
    PORT
      LAYER M3 ;
        RECT  57.96 36.576 57.978 36.72 ;
    END
  END dq[438]
  PIN dq[439]
    DIRECTION OUTPUT ;
    USE SIGNAL ;
    PORT
      LAYER M5 ;
        RECT  58.08 36.528 58.104 36.72 ;
    END
  END dq[439]
  PIN dq[43]
    DIRECTION OUTPUT ;
    USE SIGNAL ;
    PORT
      LAYER M5 ;
        RECT  9.648 36.528 9.672 36.72 ;
    END
  END dq[43]
  PIN dq[440]
    DIRECTION OUTPUT ;
    USE SIGNAL ;
    PORT
      LAYER M3 ;
        RECT  58.212 36.576 58.23 36.72 ;
    END
  END dq[440]
  PIN dq[441]
    DIRECTION OUTPUT ;
    USE SIGNAL ;
    PORT
      LAYER M5 ;
        RECT  58.32 36.528 58.344 36.72 ;
    END
  END dq[441]
  PIN dq[442]
    DIRECTION OUTPUT ;
    USE SIGNAL ;
    PORT
      LAYER M3 ;
        RECT  58.464 36.576 58.482 36.72 ;
    END
  END dq[442]
  PIN dq[443]
    DIRECTION OUTPUT ;
    USE SIGNAL ;
    PORT
      LAYER M5 ;
        RECT  58.56 36.528 58.584 36.72 ;
    END
  END dq[443]
  PIN dq[444]
    DIRECTION OUTPUT ;
    USE SIGNAL ;
    PORT
      LAYER M3 ;
        RECT  58.716 36.576 58.734 36.72 ;
    END
  END dq[444]
  PIN dq[445]
    DIRECTION OUTPUT ;
    USE SIGNAL ;
    PORT
      LAYER M5 ;
        RECT  58.848 36.528 58.872 36.72 ;
    END
  END dq[445]
  PIN dq[446]
    DIRECTION OUTPUT ;
    USE SIGNAL ;
    PORT
      LAYER M3 ;
        RECT  58.932 36.576 58.95 36.72 ;
    END
  END dq[446]
  PIN dq[447]
    DIRECTION OUTPUT ;
    USE SIGNAL ;
    PORT
      LAYER M5 ;
        RECT  59.088 36.528 59.112 36.72 ;
    END
  END dq[447]
  PIN dq[448]
    DIRECTION OUTPUT ;
    USE SIGNAL ;
    PORT
      LAYER M3 ;
        RECT  59.184 36.576 59.202 36.72 ;
    END
  END dq[448]
  PIN dq[449]
    DIRECTION OUTPUT ;
    USE SIGNAL ;
    PORT
      LAYER M5 ;
        RECT  59.328 36.528 59.352 36.72 ;
    END
  END dq[449]
  PIN dq[44]
    DIRECTION OUTPUT ;
    USE SIGNAL ;
    PORT
      LAYER M3 ;
        RECT  9.756 36.576 9.774 36.72 ;
    END
  END dq[44]
  PIN dq[450]
    DIRECTION OUTPUT ;
    USE SIGNAL ;
    PORT
      LAYER M3 ;
        RECT  59.436 36.576 59.454 36.72 ;
    END
  END dq[450]
  PIN dq[451]
    DIRECTION OUTPUT ;
    USE SIGNAL ;
    PORT
      LAYER M5 ;
        RECT  59.568 36.528 59.592 36.72 ;
    END
  END dq[451]
  PIN dq[452]
    DIRECTION OUTPUT ;
    USE SIGNAL ;
    PORT
      LAYER M3 ;
        RECT  59.688 36.576 59.706 36.72 ;
    END
  END dq[452]
  PIN dq[453]
    DIRECTION OUTPUT ;
    USE SIGNAL ;
    PORT
      LAYER M5 ;
        RECT  59.808 36.528 59.832 36.72 ;
    END
  END dq[453]
  PIN dq[454]
    DIRECTION OUTPUT ;
    USE SIGNAL ;
    PORT
      LAYER M3 ;
        RECT  59.94 36.576 59.958 36.72 ;
    END
  END dq[454]
  PIN dq[455]
    DIRECTION OUTPUT ;
    USE SIGNAL ;
    PORT
      LAYER M5 ;
        RECT  60.048 36.528 60.072 36.72 ;
    END
  END dq[455]
  PIN dq[456]
    DIRECTION OUTPUT ;
    USE SIGNAL ;
    PORT
      LAYER M3 ;
        RECT  60.156 36.576 60.174 36.72 ;
    END
  END dq[456]
  PIN dq[457]
    DIRECTION OUTPUT ;
    USE SIGNAL ;
    PORT
      LAYER M5 ;
        RECT  60.288 36.528 60.312 36.72 ;
    END
  END dq[457]
  PIN dq[458]
    DIRECTION OUTPUT ;
    USE SIGNAL ;
    PORT
      LAYER M3 ;
        RECT  60.408 36.576 60.426 36.72 ;
    END
  END dq[458]
  PIN dq[459]
    DIRECTION OUTPUT ;
    USE SIGNAL ;
    PORT
      LAYER M5 ;
        RECT  60.528 36.528 60.552 36.72 ;
    END
  END dq[459]
  PIN dq[45]
    DIRECTION OUTPUT ;
    USE SIGNAL ;
    PORT
      LAYER M5 ;
        RECT  9.888 36.528 9.912 36.72 ;
    END
  END dq[45]
  PIN dq[460]
    DIRECTION OUTPUT ;
    USE SIGNAL ;
    PORT
      LAYER M3 ;
        RECT  60.66 36.576 60.678 36.72 ;
    END
  END dq[460]
  PIN dq[461]
    DIRECTION OUTPUT ;
    USE SIGNAL ;
    PORT
      LAYER M5 ;
        RECT  60.768 36.528 60.792 36.72 ;
    END
  END dq[461]
  PIN dq[462]
    DIRECTION OUTPUT ;
    USE SIGNAL ;
    PORT
      LAYER M3 ;
        RECT  60.912 36.576 60.93 36.72 ;
    END
  END dq[462]
  PIN dq[463]
    DIRECTION OUTPUT ;
    USE SIGNAL ;
    PORT
      LAYER M5 ;
        RECT  61.008 36.528 61.032 36.72 ;
    END
  END dq[463]
  PIN dq[464]
    DIRECTION OUTPUT ;
    USE SIGNAL ;
    PORT
      LAYER M3 ;
        RECT  61.164 36.576 61.182 36.72 ;
    END
  END dq[464]
  PIN dq[465]
    DIRECTION OUTPUT ;
    USE SIGNAL ;
    PORT
      LAYER M5 ;
        RECT  61.248 36.528 61.272 36.72 ;
    END
  END dq[465]
  PIN dq[466]
    DIRECTION OUTPUT ;
    USE SIGNAL ;
    PORT
      LAYER M3 ;
        RECT  61.38 36.576 61.398 36.72 ;
    END
  END dq[466]
  PIN dq[467]
    DIRECTION OUTPUT ;
    USE SIGNAL ;
    PORT
      LAYER M5 ;
        RECT  61.536 36.528 61.56 36.72 ;
    END
  END dq[467]
  PIN dq[468]
    DIRECTION OUTPUT ;
    USE SIGNAL ;
    PORT
      LAYER M3 ;
        RECT  61.632 36.576 61.65 36.72 ;
    END
  END dq[468]
  PIN dq[469]
    DIRECTION OUTPUT ;
    USE SIGNAL ;
    PORT
      LAYER M5 ;
        RECT  61.776 36.528 61.8 36.72 ;
    END
  END dq[469]
  PIN dq[46]
    DIRECTION OUTPUT ;
    USE SIGNAL ;
    PORT
      LAYER M3 ;
        RECT  10.008 36.576 10.026 36.72 ;
    END
  END dq[46]
  PIN dq[470]
    DIRECTION OUTPUT ;
    USE SIGNAL ;
    PORT
      LAYER M3 ;
        RECT  61.884 36.576 61.902 36.72 ;
    END
  END dq[470]
  PIN dq[471]
    DIRECTION OUTPUT ;
    USE SIGNAL ;
    PORT
      LAYER M5 ;
        RECT  62.016 36.528 62.04 36.72 ;
    END
  END dq[471]
  PIN dq[472]
    DIRECTION OUTPUT ;
    USE SIGNAL ;
    PORT
      LAYER M3 ;
        RECT  62.136 36.576 62.154 36.72 ;
    END
  END dq[472]
  PIN dq[473]
    DIRECTION OUTPUT ;
    USE SIGNAL ;
    PORT
      LAYER M5 ;
        RECT  62.256 36.528 62.28 36.72 ;
    END
  END dq[473]
  PIN dq[474]
    DIRECTION OUTPUT ;
    USE SIGNAL ;
    PORT
      LAYER M3 ;
        RECT  62.388 36.576 62.406 36.72 ;
    END
  END dq[474]
  PIN dq[475]
    DIRECTION OUTPUT ;
    USE SIGNAL ;
    PORT
      LAYER M5 ;
        RECT  62.496 36.528 62.52 36.72 ;
    END
  END dq[475]
  PIN dq[476]
    DIRECTION OUTPUT ;
    USE SIGNAL ;
    PORT
      LAYER M3 ;
        RECT  62.604 36.576 62.622 36.72 ;
    END
  END dq[476]
  PIN dq[477]
    DIRECTION OUTPUT ;
    USE SIGNAL ;
    PORT
      LAYER M5 ;
        RECT  62.736 36.528 62.76 36.72 ;
    END
  END dq[477]
  PIN dq[478]
    DIRECTION OUTPUT ;
    USE SIGNAL ;
    PORT
      LAYER M3 ;
        RECT  62.856 36.576 62.874 36.72 ;
    END
  END dq[478]
  PIN dq[479]
    DIRECTION OUTPUT ;
    USE SIGNAL ;
    PORT
      LAYER M5 ;
        RECT  62.976 36.528 63 36.72 ;
    END
  END dq[479]
  PIN dq[47]
    DIRECTION OUTPUT ;
    USE SIGNAL ;
    PORT
      LAYER M5 ;
        RECT  10.128 36.528 10.152 36.72 ;
    END
  END dq[47]
  PIN dq[480]
    DIRECTION OUTPUT ;
    USE SIGNAL ;
    PORT
      LAYER M3 ;
        RECT  63.108 36.576 63.126 36.72 ;
    END
  END dq[480]
  PIN dq[481]
    DIRECTION OUTPUT ;
    USE SIGNAL ;
    PORT
      LAYER M5 ;
        RECT  63.216 36.528 63.24 36.72 ;
    END
  END dq[481]
  PIN dq[482]
    DIRECTION OUTPUT ;
    USE SIGNAL ;
    PORT
      LAYER M3 ;
        RECT  63.36 36.576 63.378 36.72 ;
    END
  END dq[482]
  PIN dq[483]
    DIRECTION OUTPUT ;
    USE SIGNAL ;
    PORT
      LAYER M5 ;
        RECT  63.456 36.528 63.48 36.72 ;
    END
  END dq[483]
  PIN dq[484]
    DIRECTION OUTPUT ;
    USE SIGNAL ;
    PORT
      LAYER M3 ;
        RECT  63.612 36.576 63.63 36.72 ;
    END
  END dq[484]
  PIN dq[485]
    DIRECTION OUTPUT ;
    USE SIGNAL ;
    PORT
      LAYER M5 ;
        RECT  63.696 36.528 63.72 36.72 ;
    END
  END dq[485]
  PIN dq[486]
    DIRECTION OUTPUT ;
    USE SIGNAL ;
    PORT
      LAYER M3 ;
        RECT  63.828 36.576 63.846 36.72 ;
    END
  END dq[486]
  PIN dq[487]
    DIRECTION OUTPUT ;
    USE SIGNAL ;
    PORT
      LAYER M5 ;
        RECT  63.984 36.528 64.008 36.72 ;
    END
  END dq[487]
  PIN dq[488]
    DIRECTION OUTPUT ;
    USE SIGNAL ;
    PORT
      LAYER M3 ;
        RECT  64.08 36.576 64.098 36.72 ;
    END
  END dq[488]
  PIN dq[489]
    DIRECTION OUTPUT ;
    USE SIGNAL ;
    PORT
      LAYER M5 ;
        RECT  64.224 36.528 64.248 36.72 ;
    END
  END dq[489]
  PIN dq[48]
    DIRECTION OUTPUT ;
    USE SIGNAL ;
    PORT
      LAYER M3 ;
        RECT  10.26 36.576 10.278 36.72 ;
    END
  END dq[48]
  PIN dq[490]
    DIRECTION OUTPUT ;
    USE SIGNAL ;
    PORT
      LAYER M3 ;
        RECT  64.332 36.576 64.35 36.72 ;
    END
  END dq[490]
  PIN dq[491]
    DIRECTION OUTPUT ;
    USE SIGNAL ;
    PORT
      LAYER M5 ;
        RECT  64.464 36.528 64.488 36.72 ;
    END
  END dq[491]
  PIN dq[492]
    DIRECTION OUTPUT ;
    USE SIGNAL ;
    PORT
      LAYER M3 ;
        RECT  64.584 36.576 64.602 36.72 ;
    END
  END dq[492]
  PIN dq[493]
    DIRECTION OUTPUT ;
    USE SIGNAL ;
    PORT
      LAYER M5 ;
        RECT  64.704 36.528 64.728 36.72 ;
    END
  END dq[493]
  PIN dq[494]
    DIRECTION OUTPUT ;
    USE SIGNAL ;
    PORT
      LAYER M3 ;
        RECT  64.836 36.576 64.854 36.72 ;
    END
  END dq[494]
  PIN dq[495]
    DIRECTION OUTPUT ;
    USE SIGNAL ;
    PORT
      LAYER M5 ;
        RECT  64.944 36.528 64.968 36.72 ;
    END
  END dq[495]
  PIN dq[496]
    DIRECTION OUTPUT ;
    USE SIGNAL ;
    PORT
      LAYER M3 ;
        RECT  65.052 36.576 65.07 36.72 ;
    END
  END dq[496]
  PIN dq[497]
    DIRECTION OUTPUT ;
    USE SIGNAL ;
    PORT
      LAYER M5 ;
        RECT  65.184 36.528 65.208 36.72 ;
    END
  END dq[497]
  PIN dq[498]
    DIRECTION OUTPUT ;
    USE SIGNAL ;
    PORT
      LAYER M3 ;
        RECT  65.304 36.576 65.322 36.72 ;
    END
  END dq[498]
  PIN dq[499]
    DIRECTION OUTPUT ;
    USE SIGNAL ;
    PORT
      LAYER M5 ;
        RECT  65.424 36.528 65.448 36.72 ;
    END
  END dq[499]
  PIN dq[49]
    DIRECTION OUTPUT ;
    USE SIGNAL ;
    PORT
      LAYER M5 ;
        RECT  10.368 36.528 10.392 36.72 ;
    END
  END dq[49]
  PIN dq[4]
    DIRECTION OUTPUT ;
    USE SIGNAL ;
    PORT
      LAYER M3 ;
        RECT  4.86 36.576 4.878 36.72 ;
    END
  END dq[4]
  PIN dq[500]
    DIRECTION OUTPUT ;
    USE SIGNAL ;
    PORT
      LAYER M3 ;
        RECT  65.556 36.576 65.574 36.72 ;
    END
  END dq[500]
  PIN dq[501]
    DIRECTION OUTPUT ;
    USE SIGNAL ;
    PORT
      LAYER M5 ;
        RECT  65.664 36.528 65.688 36.72 ;
    END
  END dq[501]
  PIN dq[502]
    DIRECTION OUTPUT ;
    USE SIGNAL ;
    PORT
      LAYER M3 ;
        RECT  65.808 36.576 65.826 36.72 ;
    END
  END dq[502]
  PIN dq[503]
    DIRECTION OUTPUT ;
    USE SIGNAL ;
    PORT
      LAYER M5 ;
        RECT  65.904 36.528 65.928 36.72 ;
    END
  END dq[503]
  PIN dq[504]
    DIRECTION OUTPUT ;
    USE SIGNAL ;
    PORT
      LAYER M3 ;
        RECT  66.06 36.576 66.078 36.72 ;
    END
  END dq[504]
  PIN dq[505]
    DIRECTION OUTPUT ;
    USE SIGNAL ;
    PORT
      LAYER M5 ;
        RECT  66.144 36.528 66.168 36.72 ;
    END
  END dq[505]
  PIN dq[506]
    DIRECTION OUTPUT ;
    USE SIGNAL ;
    PORT
      LAYER M3 ;
        RECT  66.276 36.576 66.294 36.72 ;
    END
  END dq[506]
  PIN dq[507]
    DIRECTION OUTPUT ;
    USE SIGNAL ;
    PORT
      LAYER M5 ;
        RECT  66.432 36.528 66.456 36.72 ;
    END
  END dq[507]
  PIN dq[508]
    DIRECTION OUTPUT ;
    USE SIGNAL ;
    PORT
      LAYER M3 ;
        RECT  66.528 36.576 66.546 36.72 ;
    END
  END dq[508]
  PIN dq[509]
    DIRECTION OUTPUT ;
    USE SIGNAL ;
    PORT
      LAYER M5 ;
        RECT  66.672 36.528 66.696 36.72 ;
    END
  END dq[509]
  PIN dq[50]
    DIRECTION OUTPUT ;
    USE SIGNAL ;
    PORT
      LAYER M3 ;
        RECT  10.476 36.576 10.494 36.72 ;
    END
  END dq[50]
  PIN dq[510]
    DIRECTION OUTPUT ;
    USE SIGNAL ;
    PORT
      LAYER M3 ;
        RECT  66.78 36.576 66.798 36.72 ;
    END
  END dq[510]
  PIN dq[511]
    DIRECTION OUTPUT ;
    USE SIGNAL ;
    PORT
      LAYER M5 ;
        RECT  66.912 36.528 66.936 36.72 ;
    END
  END dq[511]
  PIN dq[512]
    DIRECTION OUTPUT ;
    USE SIGNAL ;
    PORT
      LAYER M3 ;
        RECT  67.032 36.576 67.05 36.72 ;
    END
  END dq[512]
  PIN dq[513]
    DIRECTION OUTPUT ;
    USE SIGNAL ;
    PORT
      LAYER M5 ;
        RECT  67.152 36.528 67.176 36.72 ;
    END
  END dq[513]
  PIN dq[514]
    DIRECTION OUTPUT ;
    USE SIGNAL ;
    PORT
      LAYER M3 ;
        RECT  67.284 36.576 67.302 36.72 ;
    END
  END dq[514]
  PIN dq[515]
    DIRECTION OUTPUT ;
    USE SIGNAL ;
    PORT
      LAYER M5 ;
        RECT  67.392 36.528 67.416 36.72 ;
    END
  END dq[515]
  PIN dq[516]
    DIRECTION OUTPUT ;
    USE SIGNAL ;
    PORT
      LAYER M3 ;
        RECT  67.5 36.576 67.518 36.72 ;
    END
  END dq[516]
  PIN dq[517]
    DIRECTION OUTPUT ;
    USE SIGNAL ;
    PORT
      LAYER M5 ;
        RECT  67.632 36.528 67.656 36.72 ;
    END
  END dq[517]
  PIN dq[518]
    DIRECTION OUTPUT ;
    USE SIGNAL ;
    PORT
      LAYER M3 ;
        RECT  67.752 36.576 67.77 36.72 ;
    END
  END dq[518]
  PIN dq[519]
    DIRECTION OUTPUT ;
    USE SIGNAL ;
    PORT
      LAYER M5 ;
        RECT  67.872 36.528 67.896 36.72 ;
    END
  END dq[519]
  PIN dq[51]
    DIRECTION OUTPUT ;
    USE SIGNAL ;
    PORT
      LAYER M5 ;
        RECT  10.608 36.528 10.632 36.72 ;
    END
  END dq[51]
  PIN dq[520]
    DIRECTION OUTPUT ;
    USE SIGNAL ;
    PORT
      LAYER M3 ;
        RECT  68.004 36.576 68.022 36.72 ;
    END
  END dq[520]
  PIN dq[521]
    DIRECTION OUTPUT ;
    USE SIGNAL ;
    PORT
      LAYER M5 ;
        RECT  68.112 36.528 68.136 36.72 ;
    END
  END dq[521]
  PIN dq[522]
    DIRECTION OUTPUT ;
    USE SIGNAL ;
    PORT
      LAYER M3 ;
        RECT  68.256 36.576 68.274 36.72 ;
    END
  END dq[522]
  PIN dq[523]
    DIRECTION OUTPUT ;
    USE SIGNAL ;
    PORT
      LAYER M5 ;
        RECT  68.352 36.528 68.376 36.72 ;
    END
  END dq[523]
  PIN dq[524]
    DIRECTION OUTPUT ;
    USE SIGNAL ;
    PORT
      LAYER M3 ;
        RECT  68.508 36.576 68.526 36.72 ;
    END
  END dq[524]
  PIN dq[525]
    DIRECTION OUTPUT ;
    USE SIGNAL ;
    PORT
      LAYER M5 ;
        RECT  68.592 36.528 68.616 36.72 ;
    END
  END dq[525]
  PIN dq[526]
    DIRECTION OUTPUT ;
    USE SIGNAL ;
    PORT
      LAYER M3 ;
        RECT  68.724 36.576 68.742 36.72 ;
    END
  END dq[526]
  PIN dq[527]
    DIRECTION OUTPUT ;
    USE SIGNAL ;
    PORT
      LAYER M5 ;
        RECT  68.88 36.528 68.904 36.72 ;
    END
  END dq[527]
  PIN dq[528]
    DIRECTION OUTPUT ;
    USE SIGNAL ;
    PORT
      LAYER M3 ;
        RECT  68.976 36.576 68.994 36.72 ;
    END
  END dq[528]
  PIN dq[529]
    DIRECTION OUTPUT ;
    USE SIGNAL ;
    PORT
      LAYER M5 ;
        RECT  69.12 36.528 69.144 36.72 ;
    END
  END dq[529]
  PIN dq[52]
    DIRECTION OUTPUT ;
    USE SIGNAL ;
    PORT
      LAYER M3 ;
        RECT  10.728 36.576 10.746 36.72 ;
    END
  END dq[52]
  PIN dq[530]
    DIRECTION OUTPUT ;
    USE SIGNAL ;
    PORT
      LAYER M3 ;
        RECT  69.228 36.576 69.246 36.72 ;
    END
  END dq[530]
  PIN dq[531]
    DIRECTION OUTPUT ;
    USE SIGNAL ;
    PORT
      LAYER M5 ;
        RECT  69.36 36.528 69.384 36.72 ;
    END
  END dq[531]
  PIN dq[532]
    DIRECTION OUTPUT ;
    USE SIGNAL ;
    PORT
      LAYER M3 ;
        RECT  69.48 36.576 69.498 36.72 ;
    END
  END dq[532]
  PIN dq[533]
    DIRECTION OUTPUT ;
    USE SIGNAL ;
    PORT
      LAYER M5 ;
        RECT  69.6 36.528 69.624 36.72 ;
    END
  END dq[533]
  PIN dq[534]
    DIRECTION OUTPUT ;
    USE SIGNAL ;
    PORT
      LAYER M3 ;
        RECT  69.732 36.576 69.75 36.72 ;
    END
  END dq[534]
  PIN dq[535]
    DIRECTION OUTPUT ;
    USE SIGNAL ;
    PORT
      LAYER M5 ;
        RECT  69.84 36.528 69.864 36.72 ;
    END
  END dq[535]
  PIN dq[536]
    DIRECTION OUTPUT ;
    USE SIGNAL ;
    PORT
      LAYER M3 ;
        RECT  69.948 36.576 69.966 36.72 ;
    END
  END dq[536]
  PIN dq[537]
    DIRECTION OUTPUT ;
    USE SIGNAL ;
    PORT
      LAYER M5 ;
        RECT  70.08 36.528 70.104 36.72 ;
    END
  END dq[537]
  PIN dq[538]
    DIRECTION OUTPUT ;
    USE SIGNAL ;
    PORT
      LAYER M3 ;
        RECT  70.2 36.576 70.218 36.72 ;
    END
  END dq[538]
  PIN dq[539]
    DIRECTION OUTPUT ;
    USE SIGNAL ;
    PORT
      LAYER M5 ;
        RECT  70.32 36.528 70.344 36.72 ;
    END
  END dq[539]
  PIN dq[53]
    DIRECTION OUTPUT ;
    USE SIGNAL ;
    PORT
      LAYER M5 ;
        RECT  10.848 36.528 10.872 36.72 ;
    END
  END dq[53]
  PIN dq[540]
    DIRECTION OUTPUT ;
    USE SIGNAL ;
    PORT
      LAYER M3 ;
        RECT  70.452 36.576 70.47 36.72 ;
    END
  END dq[540]
  PIN dq[541]
    DIRECTION OUTPUT ;
    USE SIGNAL ;
    PORT
      LAYER M5 ;
        RECT  70.56 36.528 70.584 36.72 ;
    END
  END dq[541]
  PIN dq[542]
    DIRECTION OUTPUT ;
    USE SIGNAL ;
    PORT
      LAYER M3 ;
        RECT  70.704 36.576 70.722 36.72 ;
    END
  END dq[542]
  PIN dq[543]
    DIRECTION OUTPUT ;
    USE SIGNAL ;
    PORT
      LAYER M5 ;
        RECT  70.8 36.528 70.824 36.72 ;
    END
  END dq[543]
  PIN dq[544]
    DIRECTION OUTPUT ;
    USE SIGNAL ;
    PORT
      LAYER M3 ;
        RECT  70.956 36.576 70.974 36.72 ;
    END
  END dq[544]
  PIN dq[545]
    DIRECTION OUTPUT ;
    USE SIGNAL ;
    PORT
      LAYER M5 ;
        RECT  71.04 36.528 71.064 36.72 ;
    END
  END dq[545]
  PIN dq[546]
    DIRECTION OUTPUT ;
    USE SIGNAL ;
    PORT
      LAYER M3 ;
        RECT  71.172 36.576 71.19 36.72 ;
    END
  END dq[546]
  PIN dq[547]
    DIRECTION OUTPUT ;
    USE SIGNAL ;
    PORT
      LAYER M5 ;
        RECT  71.328 36.528 71.352 36.72 ;
    END
  END dq[547]
  PIN dq[548]
    DIRECTION OUTPUT ;
    USE SIGNAL ;
    PORT
      LAYER M3 ;
        RECT  71.424 36.576 71.442 36.72 ;
    END
  END dq[548]
  PIN dq[549]
    DIRECTION OUTPUT ;
    USE SIGNAL ;
    PORT
      LAYER M5 ;
        RECT  71.568 36.528 71.592 36.72 ;
    END
  END dq[549]
  PIN dq[54]
    DIRECTION OUTPUT ;
    USE SIGNAL ;
    PORT
      LAYER M3 ;
        RECT  10.98 36.576 10.998 36.72 ;
    END
  END dq[54]
  PIN dq[550]
    DIRECTION OUTPUT ;
    USE SIGNAL ;
    PORT
      LAYER M3 ;
        RECT  71.676 36.576 71.694 36.72 ;
    END
  END dq[550]
  PIN dq[551]
    DIRECTION OUTPUT ;
    USE SIGNAL ;
    PORT
      LAYER M5 ;
        RECT  71.808 36.528 71.832 36.72 ;
    END
  END dq[551]
  PIN dq[552]
    DIRECTION OUTPUT ;
    USE SIGNAL ;
    PORT
      LAYER M3 ;
        RECT  71.928 36.576 71.946 36.72 ;
    END
  END dq[552]
  PIN dq[553]
    DIRECTION OUTPUT ;
    USE SIGNAL ;
    PORT
      LAYER M5 ;
        RECT  72.048 36.528 72.072 36.72 ;
    END
  END dq[553]
  PIN dq[554]
    DIRECTION OUTPUT ;
    USE SIGNAL ;
    PORT
      LAYER M3 ;
        RECT  72.18 36.576 72.198 36.72 ;
    END
  END dq[554]
  PIN dq[555]
    DIRECTION OUTPUT ;
    USE SIGNAL ;
    PORT
      LAYER M5 ;
        RECT  72.288 36.528 72.312 36.72 ;
    END
  END dq[555]
  PIN dq[556]
    DIRECTION OUTPUT ;
    USE SIGNAL ;
    PORT
      LAYER M3 ;
        RECT  72.396 36.576 72.414 36.72 ;
    END
  END dq[556]
  PIN dq[557]
    DIRECTION OUTPUT ;
    USE SIGNAL ;
    PORT
      LAYER M5 ;
        RECT  72.528 36.528 72.552 36.72 ;
    END
  END dq[557]
  PIN dq[558]
    DIRECTION OUTPUT ;
    USE SIGNAL ;
    PORT
      LAYER M3 ;
        RECT  72.648 36.576 72.666 36.72 ;
    END
  END dq[558]
  PIN dq[559]
    DIRECTION OUTPUT ;
    USE SIGNAL ;
    PORT
      LAYER M5 ;
        RECT  72.768 36.528 72.792 36.72 ;
    END
  END dq[559]
  PIN dq[55]
    DIRECTION OUTPUT ;
    USE SIGNAL ;
    PORT
      LAYER M5 ;
        RECT  11.088 36.528 11.112 36.72 ;
    END
  END dq[55]
  PIN dq[560]
    DIRECTION OUTPUT ;
    USE SIGNAL ;
    PORT
      LAYER M3 ;
        RECT  72.9 36.576 72.918 36.72 ;
    END
    PORT
      LAYER M3 ;
        RECT  72.828 36.588 72.954 36.653 ;
    END
  END dq[560]
  PIN dq[561]
    DIRECTION OUTPUT ;
    USE SIGNAL ;
    PORT
      LAYER M5 ;
        RECT  73.008 36.528 73.032 36.72 ;
    END
  END dq[561]
  PIN dq[562]
    DIRECTION OUTPUT ;
    USE SIGNAL ;
    PORT
      LAYER M3 ;
        RECT  73.152 36.576 73.17 36.72 ;
    END
  END dq[562]
  PIN dq[563]
    DIRECTION OUTPUT ;
    USE SIGNAL ;
    PORT
      LAYER M5 ;
        RECT  73.248 36.528 73.272 36.72 ;
    END
  END dq[563]
  PIN dq[564]
    DIRECTION OUTPUT ;
    USE SIGNAL ;
    PORT
      LAYER M3 ;
        RECT  73.404 36.576 73.422 36.72 ;
    END
  END dq[564]
  PIN dq[565]
    DIRECTION OUTPUT ;
    USE SIGNAL ;
    PORT
      LAYER M5 ;
        RECT  73.488 36.528 73.512 36.72 ;
    END
  END dq[565]
  PIN dq[566]
    DIRECTION OUTPUT ;
    USE SIGNAL ;
    PORT
      LAYER M3 ;
        RECT  73.62 36.576 73.638 36.72 ;
    END
  END dq[566]
  PIN dq[567]
    DIRECTION OUTPUT ;
    USE SIGNAL ;
    PORT
      LAYER M5 ;
        RECT  73.776 36.528 73.8 36.72 ;
    END
  END dq[567]
  PIN dq[568]
    DIRECTION OUTPUT ;
    USE SIGNAL ;
    PORT
      LAYER M3 ;
        RECT  73.872 36.576 73.89 36.72 ;
    END
  END dq[568]
  PIN dq[569]
    DIRECTION OUTPUT ;
    USE SIGNAL ;
    PORT
      LAYER M5 ;
        RECT  74.016 36.528 74.04 36.72 ;
    END
  END dq[569]
  PIN dq[56]
    DIRECTION OUTPUT ;
    USE SIGNAL ;
    PORT
      LAYER M3 ;
        RECT  11.232 36.576 11.25 36.72 ;
    END
  END dq[56]
  PIN dq[570]
    DIRECTION OUTPUT ;
    USE SIGNAL ;
    PORT
      LAYER M3 ;
        RECT  74.124 36.576 74.142 36.72 ;
    END
  END dq[570]
  PIN dq[571]
    DIRECTION OUTPUT ;
    USE SIGNAL ;
    PORT
      LAYER M5 ;
        RECT  74.256 36.528 74.28 36.72 ;
    END
  END dq[571]
  PIN dq[572]
    DIRECTION OUTPUT ;
    USE SIGNAL ;
    PORT
      LAYER M3 ;
        RECT  74.376 36.576 74.394 36.72 ;
    END
  END dq[572]
  PIN dq[573]
    DIRECTION OUTPUT ;
    USE SIGNAL ;
    PORT
      LAYER M5 ;
        RECT  74.496 36.528 74.52 36.72 ;
    END
  END dq[573]
  PIN dq[574]
    DIRECTION OUTPUT ;
    USE SIGNAL ;
    PORT
      LAYER M3 ;
        RECT  74.628 36.576 74.646 36.72 ;
    END
  END dq[574]
  PIN dq[575]
    DIRECTION OUTPUT ;
    USE SIGNAL ;
    PORT
      LAYER M5 ;
        RECT  74.736 36.528 74.76 36.72 ;
    END
  END dq[575]
  PIN dq[576]
    DIRECTION OUTPUT ;
    USE SIGNAL ;
    PORT
      LAYER M3 ;
        RECT  74.844 36.576 74.862 36.72 ;
    END
  END dq[576]
  PIN dq[577]
    DIRECTION OUTPUT ;
    USE SIGNAL ;
    PORT
      LAYER M5 ;
        RECT  74.976 36.528 75 36.72 ;
    END
  END dq[577]
  PIN dq[578]
    DIRECTION OUTPUT ;
    USE SIGNAL ;
    PORT
      LAYER M3 ;
        RECT  75.096 36.576 75.114 36.72 ;
    END
  END dq[578]
  PIN dq[579]
    DIRECTION OUTPUT ;
    USE SIGNAL ;
    PORT
      LAYER M5 ;
        RECT  75.216 36.528 75.24 36.72 ;
    END
  END dq[579]
  PIN dq[57]
    DIRECTION OUTPUT ;
    USE SIGNAL ;
    PORT
      LAYER M5 ;
        RECT  11.328 36.528 11.352 36.72 ;
    END
  END dq[57]
  PIN dq[580]
    DIRECTION OUTPUT ;
    USE SIGNAL ;
    PORT
      LAYER M3 ;
        RECT  75.348 36.576 75.366 36.72 ;
    END
  END dq[580]
  PIN dq[581]
    DIRECTION OUTPUT ;
    USE SIGNAL ;
    PORT
      LAYER M5 ;
        RECT  75.456 36.528 75.48 36.72 ;
    END
  END dq[581]
  PIN dq[582]
    DIRECTION OUTPUT ;
    USE SIGNAL ;
    PORT
      LAYER M3 ;
        RECT  75.6 36.576 75.618 36.72 ;
    END
  END dq[582]
  PIN dq[583]
    DIRECTION OUTPUT ;
    USE SIGNAL ;
    PORT
      LAYER M5 ;
        RECT  75.696 36.528 75.72 36.72 ;
    END
  END dq[583]
  PIN dq[584]
    DIRECTION OUTPUT ;
    USE SIGNAL ;
    PORT
      LAYER M3 ;
        RECT  75.852 36.576 75.87 36.72 ;
    END
  END dq[584]
  PIN dq[585]
    DIRECTION OUTPUT ;
    USE SIGNAL ;
    PORT
      LAYER M5 ;
        RECT  75.936 36.528 75.96 36.72 ;
    END
  END dq[585]
  PIN dq[586]
    DIRECTION OUTPUT ;
    USE SIGNAL ;
    PORT
      LAYER M3 ;
        RECT  76.068 36.576 76.086 36.72 ;
    END
  END dq[586]
  PIN dq[587]
    DIRECTION OUTPUT ;
    USE SIGNAL ;
    PORT
      LAYER M5 ;
        RECT  76.224 36.528 76.248 36.72 ;
    END
  END dq[587]
  PIN dq[588]
    DIRECTION OUTPUT ;
    USE SIGNAL ;
    PORT
      LAYER M3 ;
        RECT  76.32 36.576 76.338 36.72 ;
    END
  END dq[588]
  PIN dq[589]
    DIRECTION OUTPUT ;
    USE SIGNAL ;
    PORT
      LAYER M5 ;
        RECT  76.464 36.528 76.488 36.72 ;
    END
  END dq[589]
  PIN dq[58]
    DIRECTION OUTPUT ;
    USE SIGNAL ;
    PORT
      LAYER M3 ;
        RECT  11.484 36.576 11.502 36.72 ;
    END
  END dq[58]
  PIN dq[590]
    DIRECTION OUTPUT ;
    USE SIGNAL ;
    PORT
      LAYER M3 ;
        RECT  76.572 36.576 76.59 36.72 ;
    END
  END dq[590]
  PIN dq[591]
    DIRECTION OUTPUT ;
    USE SIGNAL ;
    PORT
      LAYER M5 ;
        RECT  76.704 36.528 76.728 36.72 ;
    END
  END dq[591]
  PIN dq[592]
    DIRECTION OUTPUT ;
    USE SIGNAL ;
    PORT
      LAYER M3 ;
        RECT  76.824 36.576 76.842 36.72 ;
    END
  END dq[592]
  PIN dq[593]
    DIRECTION OUTPUT ;
    USE SIGNAL ;
    PORT
      LAYER M5 ;
        RECT  76.944 36.528 76.968 36.72 ;
    END
  END dq[593]
  PIN dq[594]
    DIRECTION OUTPUT ;
    USE SIGNAL ;
    PORT
      LAYER M3 ;
        RECT  77.076 36.576 77.094 36.72 ;
    END
  END dq[594]
  PIN dq[595]
    DIRECTION OUTPUT ;
    USE SIGNAL ;
    PORT
      LAYER M5 ;
        RECT  77.184 36.528 77.208 36.72 ;
    END
  END dq[595]
  PIN dq[596]
    DIRECTION OUTPUT ;
    USE SIGNAL ;
    PORT
      LAYER M3 ;
        RECT  77.292 36.576 77.31 36.72 ;
    END
  END dq[596]
  PIN dq[597]
    DIRECTION OUTPUT ;
    USE SIGNAL ;
    PORT
      LAYER M5 ;
        RECT  77.424 36.528 77.448 36.72 ;
    END
  END dq[597]
  PIN dq[598]
    DIRECTION OUTPUT ;
    USE SIGNAL ;
    PORT
      LAYER M3 ;
        RECT  77.544 36.576 77.562 36.72 ;
    END
  END dq[598]
  PIN dq[599]
    DIRECTION OUTPUT ;
    USE SIGNAL ;
    PORT
      LAYER M5 ;
        RECT  77.664 36.528 77.688 36.72 ;
    END
  END dq[599]
  PIN dq[59]
    DIRECTION OUTPUT ;
    USE SIGNAL ;
    PORT
      LAYER M5 ;
        RECT  11.568 36.528 11.592 36.72 ;
    END
  END dq[59]
  PIN dq[5]
    DIRECTION OUTPUT ;
    USE SIGNAL ;
    PORT
      LAYER M5 ;
        RECT  4.992 36.528 5.016 36.72 ;
    END
  END dq[5]
  PIN dq[600]
    DIRECTION OUTPUT ;
    USE SIGNAL ;
    PORT
      LAYER M3 ;
        RECT  77.796 36.576 77.814 36.72 ;
    END
  END dq[600]
  PIN dq[601]
    DIRECTION OUTPUT ;
    USE SIGNAL ;
    PORT
      LAYER M5 ;
        RECT  77.904 36.528 77.928 36.72 ;
    END
  END dq[601]
  PIN dq[602]
    DIRECTION OUTPUT ;
    USE SIGNAL ;
    PORT
      LAYER M3 ;
        RECT  78.048 36.576 78.066 36.72 ;
    END
  END dq[602]
  PIN dq[603]
    DIRECTION OUTPUT ;
    USE SIGNAL ;
    PORT
      LAYER M5 ;
        RECT  78.144 36.528 78.168 36.72 ;
    END
  END dq[603]
  PIN dq[604]
    DIRECTION OUTPUT ;
    USE SIGNAL ;
    PORT
      LAYER M3 ;
        RECT  78.3 36.576 78.318 36.72 ;
    END
  END dq[604]
  PIN dq[605]
    DIRECTION OUTPUT ;
    USE SIGNAL ;
    PORT
      LAYER M5 ;
        RECT  78.384 36.528 78.408 36.72 ;
    END
  END dq[605]
  PIN dq[606]
    DIRECTION OUTPUT ;
    USE SIGNAL ;
    PORT
      LAYER M3 ;
        RECT  78.516 36.576 78.534 36.72 ;
    END
  END dq[606]
  PIN dq[607]
    DIRECTION OUTPUT ;
    USE SIGNAL ;
    PORT
      LAYER M5 ;
        RECT  78.672 36.528 78.696 36.72 ;
    END
  END dq[607]
  PIN dq[608]
    DIRECTION OUTPUT ;
    USE SIGNAL ;
    PORT
      LAYER M3 ;
        RECT  78.768 36.576 78.786 36.72 ;
    END
  END dq[608]
  PIN dq[609]
    DIRECTION OUTPUT ;
    USE SIGNAL ;
    PORT
      LAYER M5 ;
        RECT  78.912 36.528 78.936 36.72 ;
    END
  END dq[609]
  PIN dq[60]
    DIRECTION OUTPUT ;
    USE SIGNAL ;
    PORT
      LAYER M3 ;
        RECT  11.7 36.576 11.718 36.72 ;
    END
  END dq[60]
  PIN dq[610]
    DIRECTION OUTPUT ;
    USE SIGNAL ;
    PORT
      LAYER M3 ;
        RECT  79.02 36.576 79.038 36.72 ;
    END
  END dq[610]
  PIN dq[611]
    DIRECTION OUTPUT ;
    USE SIGNAL ;
    PORT
      LAYER M5 ;
        RECT  79.152 36.528 79.176 36.72 ;
    END
  END dq[611]
  PIN dq[612]
    DIRECTION OUTPUT ;
    USE SIGNAL ;
    PORT
      LAYER M3 ;
        RECT  79.272 36.576 79.29 36.72 ;
    END
  END dq[612]
  PIN dq[613]
    DIRECTION OUTPUT ;
    USE SIGNAL ;
    PORT
      LAYER M5 ;
        RECT  79.392 36.528 79.416 36.72 ;
    END
  END dq[613]
  PIN dq[614]
    DIRECTION OUTPUT ;
    USE SIGNAL ;
    PORT
      LAYER M3 ;
        RECT  79.524 36.576 79.542 36.72 ;
    END
  END dq[614]
  PIN dq[615]
    DIRECTION OUTPUT ;
    USE SIGNAL ;
    PORT
      LAYER M5 ;
        RECT  79.632 36.528 79.656 36.72 ;
    END
  END dq[615]
  PIN dq[616]
    DIRECTION OUTPUT ;
    USE SIGNAL ;
    PORT
      LAYER M3 ;
        RECT  79.74 36.576 79.758 36.72 ;
    END
  END dq[616]
  PIN dq[617]
    DIRECTION OUTPUT ;
    USE SIGNAL ;
    PORT
      LAYER M5 ;
        RECT  79.872 36.528 79.896 36.72 ;
    END
  END dq[617]
  PIN dq[618]
    DIRECTION OUTPUT ;
    USE SIGNAL ;
    PORT
      LAYER M3 ;
        RECT  79.992 36.576 80.01 36.72 ;
    END
  END dq[618]
  PIN dq[619]
    DIRECTION OUTPUT ;
    USE SIGNAL ;
    PORT
      LAYER M5 ;
        RECT  80.112 36.528 80.136 36.72 ;
    END
  END dq[619]
  PIN dq[61]
    DIRECTION OUTPUT ;
    USE SIGNAL ;
    PORT
      LAYER M5 ;
        RECT  11.856 36.528 11.88 36.72 ;
    END
  END dq[61]
  PIN dq[620]
    DIRECTION OUTPUT ;
    USE SIGNAL ;
    PORT
      LAYER M3 ;
        RECT  80.244 36.576 80.262 36.72 ;
    END
  END dq[620]
  PIN dq[621]
    DIRECTION OUTPUT ;
    USE SIGNAL ;
    PORT
      LAYER M5 ;
        RECT  80.352 36.528 80.376 36.72 ;
    END
  END dq[621]
  PIN dq[622]
    DIRECTION OUTPUT ;
    USE SIGNAL ;
    PORT
      LAYER M3 ;
        RECT  80.496 36.576 80.514 36.72 ;
    END
  END dq[622]
  PIN dq[623]
    DIRECTION OUTPUT ;
    USE SIGNAL ;
    PORT
      LAYER M5 ;
        RECT  80.592 36.528 80.616 36.72 ;
    END
  END dq[623]
  PIN dq[624]
    DIRECTION OUTPUT ;
    USE SIGNAL ;
    PORT
      LAYER M3 ;
        RECT  80.748 36.576 80.766 36.72 ;
    END
  END dq[624]
  PIN dq[625]
    DIRECTION OUTPUT ;
    USE SIGNAL ;
    PORT
      LAYER M5 ;
        RECT  80.832 36.528 80.856 36.72 ;
    END
  END dq[625]
  PIN dq[626]
    DIRECTION OUTPUT ;
    USE SIGNAL ;
    PORT
      LAYER M3 ;
        RECT  80.964 36.576 80.982 36.72 ;
    END
  END dq[626]
  PIN dq[627]
    DIRECTION OUTPUT ;
    USE SIGNAL ;
    PORT
      LAYER M5 ;
        RECT  81.12 36.528 81.144 36.72 ;
    END
  END dq[627]
  PIN dq[628]
    DIRECTION OUTPUT ;
    USE SIGNAL ;
    PORT
      LAYER M3 ;
        RECT  81.216 36.576 81.234 36.72 ;
    END
  END dq[628]
  PIN dq[629]
    DIRECTION OUTPUT ;
    USE SIGNAL ;
    PORT
      LAYER M5 ;
        RECT  81.36 36.528 81.384 36.72 ;
    END
  END dq[629]
  PIN dq[62]
    DIRECTION OUTPUT ;
    USE SIGNAL ;
    PORT
      LAYER M3 ;
        RECT  11.952 36.576 11.97 36.72 ;
    END
  END dq[62]
  PIN dq[630]
    DIRECTION OUTPUT ;
    USE SIGNAL ;
    PORT
      LAYER M3 ;
        RECT  81.468 36.576 81.486 36.72 ;
    END
  END dq[630]
  PIN dq[631]
    DIRECTION OUTPUT ;
    USE SIGNAL ;
    PORT
      LAYER M5 ;
        RECT  81.6 36.528 81.624 36.72 ;
    END
  END dq[631]
  PIN dq[632]
    DIRECTION OUTPUT ;
    USE SIGNAL ;
    PORT
      LAYER M3 ;
        RECT  81.72 36.576 81.738 36.72 ;
    END
  END dq[632]
  PIN dq[633]
    DIRECTION OUTPUT ;
    USE SIGNAL ;
    PORT
      LAYER M5 ;
        RECT  81.84 36.528 81.864 36.72 ;
    END
  END dq[633]
  PIN dq[634]
    DIRECTION OUTPUT ;
    USE SIGNAL ;
    PORT
      LAYER M3 ;
        RECT  81.972 36.576 81.99 36.72 ;
    END
  END dq[634]
  PIN dq[635]
    DIRECTION OUTPUT ;
    USE SIGNAL ;
    PORT
      LAYER M5 ;
        RECT  82.08 36.528 82.104 36.72 ;
    END
  END dq[635]
  PIN dq[636]
    DIRECTION OUTPUT ;
    USE SIGNAL ;
    PORT
      LAYER M3 ;
        RECT  82.188 36.576 82.206 36.72 ;
    END
  END dq[636]
  PIN dq[637]
    DIRECTION OUTPUT ;
    USE SIGNAL ;
    PORT
      LAYER M5 ;
        RECT  82.32 36.528 82.344 36.72 ;
    END
  END dq[637]
  PIN dq[638]
    DIRECTION OUTPUT ;
    USE SIGNAL ;
    PORT
      LAYER M3 ;
        RECT  82.44 36.576 82.458 36.72 ;
    END
  END dq[638]
  PIN dq[639]
    DIRECTION OUTPUT ;
    USE SIGNAL ;
    PORT
      LAYER M5 ;
        RECT  82.56 36.528 82.584 36.72 ;
    END
  END dq[639]
  PIN dq[63]
    DIRECTION OUTPUT ;
    USE SIGNAL ;
    PORT
      LAYER M5 ;
        RECT  12.096 36.528 12.12 36.72 ;
    END
  END dq[63]
  PIN dq[640]
    DIRECTION OUTPUT ;
    USE SIGNAL ;
    PORT
      LAYER M3 ;
        RECT  82.692 36.576 82.71 36.72 ;
    END
  END dq[640]
  PIN dq[641]
    DIRECTION OUTPUT ;
    USE SIGNAL ;
    PORT
      LAYER M5 ;
        RECT  82.8 36.528 82.824 36.72 ;
    END
  END dq[641]
  PIN dq[642]
    DIRECTION OUTPUT ;
    USE SIGNAL ;
    PORT
      LAYER M3 ;
        RECT  82.944 36.576 82.962 36.72 ;
    END
  END dq[642]
  PIN dq[643]
    DIRECTION OUTPUT ;
    USE SIGNAL ;
    PORT
      LAYER M5 ;
        RECT  83.04 36.528 83.064 36.72 ;
    END
  END dq[643]
  PIN dq[644]
    DIRECTION OUTPUT ;
    USE SIGNAL ;
    PORT
      LAYER M3 ;
        RECT  83.196 36.576 83.214 36.72 ;
    END
  END dq[644]
  PIN dq[645]
    DIRECTION OUTPUT ;
    USE SIGNAL ;
    PORT
      LAYER M5 ;
        RECT  83.28 36.528 83.304 36.72 ;
    END
  END dq[645]
  PIN dq[646]
    DIRECTION OUTPUT ;
    USE SIGNAL ;
    PORT
      LAYER M3 ;
        RECT  83.412 36.576 83.43 36.72 ;
    END
  END dq[646]
  PIN dq[647]
    DIRECTION OUTPUT ;
    USE SIGNAL ;
    PORT
      LAYER M5 ;
        RECT  83.52 36.528 83.544 36.72 ;
    END
  END dq[647]
  PIN dq[648]
    DIRECTION OUTPUT ;
    USE SIGNAL ;
    PORT
      LAYER M3 ;
        RECT  83.664 36.576 83.682 36.72 ;
    END
  END dq[648]
  PIN dq[649]
    DIRECTION OUTPUT ;
    USE SIGNAL ;
    PORT
      LAYER M5 ;
        RECT  83.808 36.528 83.832 36.72 ;
    END
  END dq[649]
  PIN dq[64]
    DIRECTION OUTPUT ;
    USE SIGNAL ;
    PORT
      LAYER M3 ;
        RECT  12.204 36.576 12.222 36.72 ;
    END
  END dq[64]
  PIN dq[650]
    DIRECTION OUTPUT ;
    USE SIGNAL ;
    PORT
      LAYER M3 ;
        RECT  83.916 36.576 83.934 36.72 ;
    END
  END dq[650]
  PIN dq[651]
    DIRECTION OUTPUT ;
    USE SIGNAL ;
    PORT
      LAYER M5 ;
        RECT  84.048 36.528 84.072 36.72 ;
    END
  END dq[651]
  PIN dq[652]
    DIRECTION OUTPUT ;
    USE SIGNAL ;
    PORT
      LAYER M3 ;
        RECT  84.168 36.576 84.186 36.72 ;
    END
  END dq[652]
  PIN dq[653]
    DIRECTION OUTPUT ;
    USE SIGNAL ;
    PORT
      LAYER M5 ;
        RECT  84.288 36.528 84.312 36.72 ;
    END
  END dq[653]
  PIN dq[654]
    DIRECTION OUTPUT ;
    USE SIGNAL ;
    PORT
      LAYER M3 ;
        RECT  84.42 36.576 84.438 36.72 ;
    END
  END dq[654]
  PIN dq[655]
    DIRECTION OUTPUT ;
    USE SIGNAL ;
    PORT
      LAYER M5 ;
        RECT  84.528 36.528 84.552 36.72 ;
    END
  END dq[655]
  PIN dq[656]
    DIRECTION OUTPUT ;
    USE SIGNAL ;
    PORT
      LAYER M3 ;
        RECT  84.636 36.576 84.654 36.72 ;
    END
  END dq[656]
  PIN dq[657]
    DIRECTION OUTPUT ;
    USE SIGNAL ;
    PORT
      LAYER M5 ;
        RECT  84.768 36.528 84.792 36.72 ;
    END
  END dq[657]
  PIN dq[658]
    DIRECTION OUTPUT ;
    USE SIGNAL ;
    PORT
      LAYER M3 ;
        RECT  84.888 36.576 84.906 36.72 ;
    END
  END dq[658]
  PIN dq[659]
    DIRECTION OUTPUT ;
    USE SIGNAL ;
    PORT
      LAYER M5 ;
        RECT  85.008 36.528 85.032 36.72 ;
    END
  END dq[659]
  PIN dq[65]
    DIRECTION OUTPUT ;
    USE SIGNAL ;
    PORT
      LAYER M5 ;
        RECT  12.336 36.528 12.36 36.72 ;
    END
  END dq[65]
  PIN dq[660]
    DIRECTION OUTPUT ;
    USE SIGNAL ;
    PORT
      LAYER M3 ;
        RECT  85.14 36.576 85.158 36.72 ;
    END
  END dq[660]
  PIN dq[661]
    DIRECTION OUTPUT ;
    USE SIGNAL ;
    PORT
      LAYER M5 ;
        RECT  85.248 36.528 85.272 36.72 ;
    END
  END dq[661]
  PIN dq[662]
    DIRECTION OUTPUT ;
    USE SIGNAL ;
    PORT
      LAYER M3 ;
        RECT  85.392 36.576 85.41 36.72 ;
    END
  END dq[662]
  PIN dq[663]
    DIRECTION OUTPUT ;
    USE SIGNAL ;
    PORT
      LAYER M5 ;
        RECT  85.488 36.528 85.512 36.72 ;
    END
  END dq[663]
  PIN dq[664]
    DIRECTION OUTPUT ;
    USE SIGNAL ;
    PORT
      LAYER M3 ;
        RECT  85.644 36.576 85.662 36.72 ;
    END
  END dq[664]
  PIN dq[665]
    DIRECTION OUTPUT ;
    USE SIGNAL ;
    PORT
      LAYER M5 ;
        RECT  85.728 36.528 85.752 36.72 ;
    END
  END dq[665]
  PIN dq[666]
    DIRECTION OUTPUT ;
    USE SIGNAL ;
    PORT
      LAYER M3 ;
        RECT  85.86 36.576 85.878 36.72 ;
    END
  END dq[666]
  PIN dq[667]
    DIRECTION OUTPUT ;
    USE SIGNAL ;
    PORT
      LAYER M5 ;
        RECT  85.968 36.528 85.992 36.72 ;
    END
  END dq[667]
  PIN dq[668]
    DIRECTION OUTPUT ;
    USE SIGNAL ;
    PORT
      LAYER M3 ;
        RECT  86.112 36.576 86.13 36.72 ;
    END
  END dq[668]
  PIN dq[669]
    DIRECTION OUTPUT ;
    USE SIGNAL ;
    PORT
      LAYER M5 ;
        RECT  86.256 36.528 86.28 36.72 ;
    END
  END dq[669]
  PIN dq[66]
    DIRECTION OUTPUT ;
    USE SIGNAL ;
    PORT
      LAYER M3 ;
        RECT  12.456 36.576 12.474 36.72 ;
    END
  END dq[66]
  PIN dq[670]
    DIRECTION OUTPUT ;
    USE SIGNAL ;
    PORT
      LAYER M3 ;
        RECT  86.364 36.576 86.382 36.72 ;
    END
  END dq[670]
  PIN dq[671]
    DIRECTION OUTPUT ;
    USE SIGNAL ;
    PORT
      LAYER M5 ;
        RECT  86.496 36.528 86.52 36.72 ;
    END
  END dq[671]
  PIN dq[672]
    DIRECTION OUTPUT ;
    USE SIGNAL ;
    PORT
      LAYER M3 ;
        RECT  86.616 36.576 86.634 36.72 ;
    END
  END dq[672]
  PIN dq[673]
    DIRECTION OUTPUT ;
    USE SIGNAL ;
    PORT
      LAYER M5 ;
        RECT  86.736 36.528 86.76 36.72 ;
    END
  END dq[673]
  PIN dq[674]
    DIRECTION OUTPUT ;
    USE SIGNAL ;
    PORT
      LAYER M3 ;
        RECT  86.868 36.576 86.886 36.72 ;
    END
  END dq[674]
  PIN dq[675]
    DIRECTION OUTPUT ;
    USE SIGNAL ;
    PORT
      LAYER M5 ;
        RECT  86.976 36.528 87 36.72 ;
    END
  END dq[675]
  PIN dq[676]
    DIRECTION OUTPUT ;
    USE SIGNAL ;
    PORT
      LAYER M3 ;
        RECT  87.084 36.576 87.102 36.72 ;
    END
  END dq[676]
  PIN dq[677]
    DIRECTION OUTPUT ;
    USE SIGNAL ;
    PORT
      LAYER M5 ;
        RECT  87.216 36.528 87.24 36.72 ;
    END
  END dq[677]
  PIN dq[678]
    DIRECTION OUTPUT ;
    USE SIGNAL ;
    PORT
      LAYER M3 ;
        RECT  87.336 36.576 87.354 36.72 ;
    END
  END dq[678]
  PIN dq[679]
    DIRECTION OUTPUT ;
    USE SIGNAL ;
    PORT
      LAYER M5 ;
        RECT  87.456 36.528 87.48 36.72 ;
    END
  END dq[679]
  PIN dq[67]
    DIRECTION OUTPUT ;
    USE SIGNAL ;
    PORT
      LAYER M5 ;
        RECT  12.576 36.528 12.6 36.72 ;
    END
  END dq[67]
  PIN dq[680]
    DIRECTION OUTPUT ;
    USE SIGNAL ;
    PORT
      LAYER M3 ;
        RECT  87.588 36.576 87.606 36.72 ;
    END
  END dq[680]
  PIN dq[681]
    DIRECTION OUTPUT ;
    USE SIGNAL ;
    PORT
      LAYER M5 ;
        RECT  87.696 36.528 87.72 36.72 ;
    END
  END dq[681]
  PIN dq[682]
    DIRECTION OUTPUT ;
    USE SIGNAL ;
    PORT
      LAYER M3 ;
        RECT  87.84 36.576 87.858 36.72 ;
    END
  END dq[682]
  PIN dq[683]
    DIRECTION OUTPUT ;
    USE SIGNAL ;
    PORT
      LAYER M5 ;
        RECT  87.936 36.528 87.96 36.72 ;
    END
  END dq[683]
  PIN dq[684]
    DIRECTION OUTPUT ;
    USE SIGNAL ;
    PORT
      LAYER M3 ;
        RECT  88.092 36.576 88.11 36.72 ;
    END
  END dq[684]
  PIN dq[685]
    DIRECTION OUTPUT ;
    USE SIGNAL ;
    PORT
      LAYER M5 ;
        RECT  88.176 36.528 88.2 36.72 ;
    END
  END dq[685]
  PIN dq[686]
    DIRECTION OUTPUT ;
    USE SIGNAL ;
    PORT
      LAYER M3 ;
        RECT  88.308 36.576 88.326 36.72 ;
    END
  END dq[686]
  PIN dq[687]
    DIRECTION OUTPUT ;
    USE SIGNAL ;
    PORT
      LAYER M5 ;
        RECT  88.416 36.528 88.44 36.72 ;
    END
  END dq[687]
  PIN dq[688]
    DIRECTION OUTPUT ;
    USE SIGNAL ;
    PORT
      LAYER M3 ;
        RECT  88.56 36.576 88.578 36.72 ;
    END
  END dq[688]
  PIN dq[689]
    DIRECTION OUTPUT ;
    USE SIGNAL ;
    PORT
      LAYER M5 ;
        RECT  88.704 36.528 88.728 36.72 ;
    END
  END dq[689]
  PIN dq[68]
    DIRECTION OUTPUT ;
    USE SIGNAL ;
    PORT
      LAYER M3 ;
        RECT  12.708 36.576 12.726 36.72 ;
    END
  END dq[68]
  PIN dq[690]
    DIRECTION OUTPUT ;
    USE SIGNAL ;
    PORT
      LAYER M3 ;
        RECT  88.812 36.576 88.83 36.72 ;
    END
  END dq[690]
  PIN dq[691]
    DIRECTION OUTPUT ;
    USE SIGNAL ;
    PORT
      LAYER M5 ;
        RECT  88.944 36.528 88.968 36.72 ;
    END
  END dq[691]
  PIN dq[692]
    DIRECTION OUTPUT ;
    USE SIGNAL ;
    PORT
      LAYER M3 ;
        RECT  89.064 36.576 89.082 36.72 ;
    END
  END dq[692]
  PIN dq[693]
    DIRECTION OUTPUT ;
    USE SIGNAL ;
    PORT
      LAYER M5 ;
        RECT  89.184 36.528 89.208 36.72 ;
    END
  END dq[693]
  PIN dq[694]
    DIRECTION OUTPUT ;
    USE SIGNAL ;
    PORT
      LAYER M3 ;
        RECT  89.316 36.576 89.334 36.72 ;
    END
  END dq[694]
  PIN dq[695]
    DIRECTION OUTPUT ;
    USE SIGNAL ;
    PORT
      LAYER M5 ;
        RECT  89.424 36.528 89.448 36.72 ;
    END
  END dq[695]
  PIN dq[696]
    DIRECTION OUTPUT ;
    USE SIGNAL ;
    PORT
      LAYER M3 ;
        RECT  89.532 36.576 89.55 36.72 ;
    END
  END dq[696]
  PIN dq[697]
    DIRECTION OUTPUT ;
    USE SIGNAL ;
    PORT
      LAYER M5 ;
        RECT  89.664 36.528 89.688 36.72 ;
    END
  END dq[697]
  PIN dq[698]
    DIRECTION OUTPUT ;
    USE SIGNAL ;
    PORT
      LAYER M3 ;
        RECT  89.784 36.576 89.802 36.72 ;
    END
  END dq[698]
  PIN dq[699]
    DIRECTION OUTPUT ;
    USE SIGNAL ;
    PORT
      LAYER M5 ;
        RECT  89.904 36.528 89.928 36.72 ;
    END
  END dq[699]
  PIN dq[69]
    DIRECTION OUTPUT ;
    USE SIGNAL ;
    PORT
      LAYER M5 ;
        RECT  12.816 36.528 12.84 36.72 ;
    END
  END dq[69]
  PIN dq[6]
    DIRECTION OUTPUT ;
    USE SIGNAL ;
    PORT
      LAYER M3 ;
        RECT  5.112 36.576 5.13 36.72 ;
    END
  END dq[6]
  PIN dq[700]
    DIRECTION OUTPUT ;
    USE SIGNAL ;
    PORT
      LAYER M3 ;
        RECT  90.036 36.576 90.054 36.72 ;
    END
  END dq[700]
  PIN dq[701]
    DIRECTION OUTPUT ;
    USE SIGNAL ;
    PORT
      LAYER M5 ;
        RECT  90.144 36.528 90.168 36.72 ;
    END
  END dq[701]
  PIN dq[702]
    DIRECTION OUTPUT ;
    USE SIGNAL ;
    PORT
      LAYER M3 ;
        RECT  90.288 36.576 90.306 36.72 ;
    END
  END dq[702]
  PIN dq[703]
    DIRECTION OUTPUT ;
    USE SIGNAL ;
    PORT
      LAYER M5 ;
        RECT  90.384 36.528 90.408 36.72 ;
    END
  END dq[703]
  PIN dq[704]
    DIRECTION OUTPUT ;
    USE SIGNAL ;
    PORT
      LAYER M3 ;
        RECT  90.504 36.576 90.522 36.72 ;
    END
  END dq[704]
  PIN dq[705]
    DIRECTION OUTPUT ;
    USE SIGNAL ;
    PORT
      LAYER M5 ;
        RECT  90.624 36.528 90.648 36.72 ;
    END
  END dq[705]
  PIN dq[706]
    DIRECTION OUTPUT ;
    USE SIGNAL ;
    PORT
      LAYER M3 ;
        RECT  90.756 36.576 90.774 36.72 ;
    END
  END dq[706]
  PIN dq[707]
    DIRECTION OUTPUT ;
    USE SIGNAL ;
    PORT
      LAYER M5 ;
        RECT  90.864 36.528 90.888 36.72 ;
    END
  END dq[707]
  PIN dq[708]
    DIRECTION OUTPUT ;
    USE SIGNAL ;
    PORT
      LAYER M3 ;
        RECT  91.008 36.576 91.026 36.72 ;
    END
  END dq[708]
  PIN dq[709]
    DIRECTION OUTPUT ;
    USE SIGNAL ;
    PORT
      LAYER M5 ;
        RECT  91.152 36.528 91.176 36.72 ;
    END
  END dq[709]
  PIN dq[70]
    DIRECTION OUTPUT ;
    USE SIGNAL ;
    PORT
      LAYER M3 ;
        RECT  12.924 36.576 12.942 36.72 ;
    END
  END dq[70]
  PIN dq[710]
    DIRECTION OUTPUT ;
    USE SIGNAL ;
    PORT
      LAYER M3 ;
        RECT  91.26 36.576 91.278 36.72 ;
    END
  END dq[710]
  PIN dq[711]
    DIRECTION OUTPUT ;
    USE SIGNAL ;
    PORT
      LAYER M5 ;
        RECT  91.392 36.528 91.416 36.72 ;
    END
  END dq[711]
  PIN dq[712]
    DIRECTION OUTPUT ;
    USE SIGNAL ;
    PORT
      LAYER M3 ;
        RECT  91.512 36.576 91.53 36.72 ;
    END
  END dq[712]
  PIN dq[713]
    DIRECTION OUTPUT ;
    USE SIGNAL ;
    PORT
      LAYER M5 ;
        RECT  91.632 36.528 91.656 36.72 ;
    END
  END dq[713]
  PIN dq[714]
    DIRECTION OUTPUT ;
    USE SIGNAL ;
    PORT
      LAYER M3 ;
        RECT  91.728 36.576 91.746 36.72 ;
    END
  END dq[714]
  PIN dq[715]
    DIRECTION OUTPUT ;
    USE SIGNAL ;
    PORT
      LAYER M5 ;
        RECT  91.872 36.528 91.896 36.72 ;
    END
  END dq[715]
  PIN dq[716]
    DIRECTION OUTPUT ;
    USE SIGNAL ;
    PORT
      LAYER M3 ;
        RECT  91.98 36.576 91.998 36.72 ;
    END
  END dq[716]
  PIN dq[717]
    DIRECTION OUTPUT ;
    USE SIGNAL ;
    PORT
      LAYER M5 ;
        RECT  92.112 36.528 92.136 36.72 ;
    END
  END dq[717]
  PIN dq[718]
    DIRECTION OUTPUT ;
    USE SIGNAL ;
    PORT
      LAYER M3 ;
        RECT  92.232 36.576 92.25 36.72 ;
    END
  END dq[718]
  PIN dq[719]
    DIRECTION OUTPUT ;
    USE SIGNAL ;
    PORT
      LAYER M5 ;
        RECT  92.352 36.528 92.376 36.72 ;
    END
  END dq[719]
  PIN dq[71]
    DIRECTION OUTPUT ;
    USE SIGNAL ;
    PORT
      LAYER M5 ;
        RECT  13.056 36.528 13.08 36.72 ;
    END
  END dq[71]
  PIN dq[720]
    DIRECTION OUTPUT ;
    USE SIGNAL ;
    PORT
      LAYER M3 ;
        RECT  92.484 36.576 92.502 36.72 ;
    END
  END dq[720]
  PIN dq[721]
    DIRECTION OUTPUT ;
    USE SIGNAL ;
    PORT
      LAYER M5 ;
        RECT  92.592 36.528 92.616 36.72 ;
    END
  END dq[721]
  PIN dq[722]
    DIRECTION OUTPUT ;
    USE SIGNAL ;
    PORT
      LAYER M3 ;
        RECT  92.736 36.576 92.754 36.72 ;
    END
  END dq[722]
  PIN dq[723]
    DIRECTION OUTPUT ;
    USE SIGNAL ;
    PORT
      LAYER M5 ;
        RECT  92.832 36.528 92.856 36.72 ;
    END
  END dq[723]
  PIN dq[724]
    DIRECTION OUTPUT ;
    USE SIGNAL ;
    PORT
      LAYER M3 ;
        RECT  92.952 36.576 92.97 36.72 ;
    END
  END dq[724]
  PIN dq[725]
    DIRECTION OUTPUT ;
    USE SIGNAL ;
    PORT
      LAYER M5 ;
        RECT  93.072 36.528 93.096 36.72 ;
    END
  END dq[725]
  PIN dq[726]
    DIRECTION OUTPUT ;
    USE SIGNAL ;
    PORT
      LAYER M3 ;
        RECT  93.204 36.576 93.222 36.72 ;
    END
  END dq[726]
  PIN dq[727]
    DIRECTION OUTPUT ;
    USE SIGNAL ;
    PORT
      LAYER M5 ;
        RECT  93.312 36.528 93.336 36.72 ;
    END
  END dq[727]
  PIN dq[728]
    DIRECTION OUTPUT ;
    USE SIGNAL ;
    PORT
      LAYER M3 ;
        RECT  93.456 36.576 93.474 36.72 ;
    END
  END dq[728]
  PIN dq[729]
    DIRECTION OUTPUT ;
    USE SIGNAL ;
    PORT
      LAYER M5 ;
        RECT  93.6 36.528 93.624 36.72 ;
    END
  END dq[729]
  PIN dq[72]
    DIRECTION OUTPUT ;
    USE SIGNAL ;
    PORT
      LAYER M3 ;
        RECT  13.176 36.576 13.194 36.72 ;
    END
  END dq[72]
  PIN dq[730]
    DIRECTION OUTPUT ;
    USE SIGNAL ;
    PORT
      LAYER M3 ;
        RECT  93.708 36.576 93.726 36.72 ;
    END
  END dq[730]
  PIN dq[731]
    DIRECTION OUTPUT ;
    USE SIGNAL ;
    PORT
      LAYER M5 ;
        RECT  93.84 36.528 93.864 36.72 ;
    END
  END dq[731]
  PIN dq[732]
    DIRECTION OUTPUT ;
    USE SIGNAL ;
    PORT
      LAYER M3 ;
        RECT  93.96 36.576 93.978 36.72 ;
    END
  END dq[732]
  PIN dq[733]
    DIRECTION OUTPUT ;
    USE SIGNAL ;
    PORT
      LAYER M5 ;
        RECT  94.08 36.528 94.104 36.72 ;
    END
  END dq[733]
  PIN dq[734]
    DIRECTION OUTPUT ;
    USE SIGNAL ;
    PORT
      LAYER M3 ;
        RECT  94.176 36.576 94.194 36.72 ;
    END
  END dq[734]
  PIN dq[735]
    DIRECTION OUTPUT ;
    USE SIGNAL ;
    PORT
      LAYER M5 ;
        RECT  94.32 36.528 94.344 36.72 ;
    END
  END dq[735]
  PIN dq[736]
    DIRECTION OUTPUT ;
    USE SIGNAL ;
    PORT
      LAYER M3 ;
        RECT  94.428 36.576 94.446 36.72 ;
    END
  END dq[736]
  PIN dq[737]
    DIRECTION OUTPUT ;
    USE SIGNAL ;
    PORT
      LAYER M5 ;
        RECT  94.56 36.528 94.584 36.72 ;
    END
  END dq[737]
  PIN dq[738]
    DIRECTION OUTPUT ;
    USE SIGNAL ;
    PORT
      LAYER M3 ;
        RECT  94.68 36.576 94.698 36.72 ;
    END
  END dq[738]
  PIN dq[739]
    DIRECTION OUTPUT ;
    USE SIGNAL ;
    PORT
      LAYER M5 ;
        RECT  94.8 36.528 94.824 36.72 ;
    END
  END dq[739]
  PIN dq[73]
    DIRECTION OUTPUT ;
    USE SIGNAL ;
    PORT
      LAYER M5 ;
        RECT  13.296 36.528 13.32 36.72 ;
    END
  END dq[73]
  PIN dq[740]
    DIRECTION OUTPUT ;
    USE SIGNAL ;
    PORT
      LAYER M3 ;
        RECT  94.932 36.576 94.95 36.72 ;
    END
  END dq[740]
  PIN dq[741]
    DIRECTION OUTPUT ;
    USE SIGNAL ;
    PORT
      LAYER M5 ;
        RECT  95.04 36.528 95.064 36.72 ;
    END
  END dq[741]
  PIN dq[742]
    DIRECTION OUTPUT ;
    USE SIGNAL ;
    PORT
      LAYER M3 ;
        RECT  95.184 36.576 95.202 36.72 ;
    END
  END dq[742]
  PIN dq[743]
    DIRECTION OUTPUT ;
    USE SIGNAL ;
    PORT
      LAYER M5 ;
        RECT  95.28 36.528 95.304 36.72 ;
    END
  END dq[743]
  PIN dq[744]
    DIRECTION OUTPUT ;
    USE SIGNAL ;
    PORT
      LAYER M3 ;
        RECT  95.4 36.576 95.418 36.72 ;
    END
  END dq[744]
  PIN dq[745]
    DIRECTION OUTPUT ;
    USE SIGNAL ;
    PORT
      LAYER M5 ;
        RECT  95.52 36.528 95.544 36.72 ;
    END
  END dq[745]
  PIN dq[746]
    DIRECTION OUTPUT ;
    USE SIGNAL ;
    PORT
      LAYER M3 ;
        RECT  95.652 36.576 95.67 36.72 ;
    END
  END dq[746]
  PIN dq[747]
    DIRECTION OUTPUT ;
    USE SIGNAL ;
    PORT
      LAYER M5 ;
        RECT  95.76 36.528 95.784 36.72 ;
    END
  END dq[747]
  PIN dq[748]
    DIRECTION OUTPUT ;
    USE SIGNAL ;
    PORT
      LAYER M3 ;
        RECT  95.904 36.576 95.922 36.72 ;
    END
  END dq[748]
  PIN dq[749]
    DIRECTION OUTPUT ;
    USE SIGNAL ;
    PORT
      LAYER M5 ;
        RECT  96.048 36.528 96.072 36.72 ;
    END
  END dq[749]
  PIN dq[74]
    DIRECTION OUTPUT ;
    USE SIGNAL ;
    PORT
      LAYER M3 ;
        RECT  13.428 36.576 13.446 36.72 ;
    END
  END dq[74]
  PIN dq[750]
    DIRECTION OUTPUT ;
    USE SIGNAL ;
    PORT
      LAYER M3 ;
        RECT  96.156 36.576 96.174 36.72 ;
    END
  END dq[750]
  PIN dq[751]
    DIRECTION OUTPUT ;
    USE SIGNAL ;
    PORT
      LAYER M5 ;
        RECT  96.288 36.528 96.312 36.72 ;
    END
  END dq[751]
  PIN dq[752]
    DIRECTION OUTPUT ;
    USE SIGNAL ;
    PORT
      LAYER M3 ;
        RECT  96.408 36.576 96.426 36.72 ;
    END
  END dq[752]
  PIN dq[753]
    DIRECTION OUTPUT ;
    USE SIGNAL ;
    PORT
      LAYER M5 ;
        RECT  96.528 36.528 96.552 36.72 ;
    END
  END dq[753]
  PIN dq[754]
    DIRECTION OUTPUT ;
    USE SIGNAL ;
    PORT
      LAYER M3 ;
        RECT  96.624 36.576 96.642 36.72 ;
    END
  END dq[754]
  PIN dq[755]
    DIRECTION OUTPUT ;
    USE SIGNAL ;
    PORT
      LAYER M5 ;
        RECT  96.768 36.528 96.792 36.72 ;
    END
  END dq[755]
  PIN dq[756]
    DIRECTION OUTPUT ;
    USE SIGNAL ;
    PORT
      LAYER M3 ;
        RECT  96.876 36.576 96.894 36.72 ;
    END
  END dq[756]
  PIN dq[757]
    DIRECTION OUTPUT ;
    USE SIGNAL ;
    PORT
      LAYER M5 ;
        RECT  97.008 36.528 97.032 36.72 ;
    END
  END dq[757]
  PIN dq[758]
    DIRECTION OUTPUT ;
    USE SIGNAL ;
    PORT
      LAYER M3 ;
        RECT  97.128 36.576 97.146 36.72 ;
    END
  END dq[758]
  PIN dq[75]
    DIRECTION OUTPUT ;
    USE SIGNAL ;
    PORT
      LAYER M5 ;
        RECT  13.536 36.528 13.56 36.72 ;
    END
  END dq[75]
  PIN dq[76]
    DIRECTION OUTPUT ;
    USE SIGNAL ;
    PORT
      LAYER M3 ;
        RECT  13.68 36.576 13.698 36.72 ;
    END
  END dq[76]
  PIN dq[77]
    DIRECTION OUTPUT ;
    USE SIGNAL ;
    PORT
      LAYER M5 ;
        RECT  13.776 36.528 13.8 36.72 ;
    END
  END dq[77]
  PIN dq[78]
    DIRECTION OUTPUT ;
    USE SIGNAL ;
    PORT
      LAYER M3 ;
        RECT  13.932 36.576 13.95 36.72 ;
    END
  END dq[78]
  PIN dq[79]
    DIRECTION OUTPUT ;
    USE SIGNAL ;
    PORT
      LAYER M5 ;
        RECT  14.016 36.528 14.04 36.72 ;
    END
  END dq[79]
  PIN dq[7]
    DIRECTION OUTPUT ;
    USE SIGNAL ;
    PORT
      LAYER M5 ;
        RECT  5.232 36.528 5.256 36.72 ;
    END
  END dq[7]
  PIN dq[80]
    DIRECTION OUTPUT ;
    USE SIGNAL ;
    PORT
      LAYER M3 ;
        RECT  14.148 36.576 14.166 36.72 ;
    END
  END dq[80]
  PIN dq[81]
    DIRECTION OUTPUT ;
    USE SIGNAL ;
    PORT
      LAYER M5 ;
        RECT  14.304 36.528 14.328 36.72 ;
    END
  END dq[81]
  PIN dq[82]
    DIRECTION OUTPUT ;
    USE SIGNAL ;
    PORT
      LAYER M3 ;
        RECT  14.4 36.576 14.418 36.72 ;
    END
  END dq[82]
  PIN dq[83]
    DIRECTION OUTPUT ;
    USE SIGNAL ;
    PORT
      LAYER M5 ;
        RECT  14.544 36.528 14.568 36.72 ;
    END
  END dq[83]
  PIN dq[84]
    DIRECTION OUTPUT ;
    USE SIGNAL ;
    PORT
      LAYER M3 ;
        RECT  14.652 36.576 14.67 36.72 ;
    END
  END dq[84]
  PIN dq[85]
    DIRECTION OUTPUT ;
    USE SIGNAL ;
    PORT
      LAYER M5 ;
        RECT  14.784 36.528 14.808 36.72 ;
    END
  END dq[85]
  PIN dq[86]
    DIRECTION OUTPUT ;
    USE SIGNAL ;
    PORT
      LAYER M3 ;
        RECT  14.904 36.576 14.922 36.72 ;
    END
  END dq[86]
  PIN dq[87]
    DIRECTION OUTPUT ;
    USE SIGNAL ;
    PORT
      LAYER M5 ;
        RECT  15.024 36.528 15.048 36.72 ;
    END
  END dq[87]
  PIN dq[88]
    DIRECTION OUTPUT ;
    USE SIGNAL ;
    PORT
      LAYER M3 ;
        RECT  15.156 36.576 15.174 36.72 ;
    END
  END dq[88]
  PIN dq[89]
    DIRECTION OUTPUT ;
    USE SIGNAL ;
    PORT
      LAYER M5 ;
        RECT  15.264 36.528 15.288 36.72 ;
    END
  END dq[89]
  PIN dq[8]
    DIRECTION OUTPUT ;
    USE SIGNAL ;
    PORT
      LAYER M3 ;
        RECT  5.364 36.576 5.382 36.72 ;
    END
  END dq[8]
  PIN dq[90]
    DIRECTION OUTPUT ;
    USE SIGNAL ;
    PORT
      LAYER M3 ;
        RECT  15.372 36.576 15.39 36.72 ;
    END
  END dq[90]
  PIN dq[91]
    DIRECTION OUTPUT ;
    USE SIGNAL ;
    PORT
      LAYER M5 ;
        RECT  15.504 36.528 15.528 36.72 ;
    END
  END dq[91]
  PIN dq[92]
    DIRECTION OUTPUT ;
    USE SIGNAL ;
    PORT
      LAYER M3 ;
        RECT  15.624 36.576 15.642 36.72 ;
    END
  END dq[92]
  PIN dq[93]
    DIRECTION OUTPUT ;
    USE SIGNAL ;
    PORT
      LAYER M5 ;
        RECT  15.744 36.528 15.768 36.72 ;
    END
  END dq[93]
  PIN dq[94]
    DIRECTION OUTPUT ;
    USE SIGNAL ;
    PORT
      LAYER M3 ;
        RECT  15.876 36.576 15.894 36.72 ;
    END
  END dq[94]
  PIN dq[95]
    DIRECTION OUTPUT ;
    USE SIGNAL ;
    PORT
      LAYER M5 ;
        RECT  15.984 36.528 16.008 36.72 ;
    END
  END dq[95]
  PIN dq[96]
    DIRECTION OUTPUT ;
    USE SIGNAL ;
    PORT
      LAYER M3 ;
        RECT  16.128 36.576 16.146 36.72 ;
    END
  END dq[96]
  PIN dq[97]
    DIRECTION OUTPUT ;
    USE SIGNAL ;
    PORT
      LAYER M5 ;
        RECT  16.224 36.528 16.248 36.72 ;
    END
  END dq[97]
  PIN dq[98]
    DIRECTION OUTPUT ;
    USE SIGNAL ;
    PORT
      LAYER M3 ;
        RECT  16.38 36.576 16.398 36.72 ;
    END
  END dq[98]
  PIN dq[99]
    DIRECTION OUTPUT ;
    USE SIGNAL ;
    PORT
      LAYER M5 ;
        RECT  16.464 36.528 16.488 36.72 ;
    END
  END dq[99]
  PIN dq[9]
    DIRECTION OUTPUT ;
    USE SIGNAL ;
    PORT
      LAYER M5 ;
        RECT  5.472 36.528 5.496 36.72 ;
    END
  END dq[9]
  PIN VDD
    DIRECTION INOUT ;
    USE POWER ;
    PORT
      LAYER M5 ;
        RECT  97.092 2.151 97.212 34.569 ;
        RECT  94.392 2.151 94.512 34.569 ;
        RECT  91.692 2.151 91.812 34.569 ;
        RECT  88.992 2.151 89.112 34.569 ;
        RECT  86.292 2.151 86.412 34.569 ;
        RECT  83.592 2.151 83.712 34.569 ;
        RECT  80.892 2.151 81.012 34.569 ;
        RECT  78.192 2.151 78.312 34.569 ;
        RECT  75.492 2.151 75.612 34.569 ;
        RECT  72.792 2.151 72.912 34.569 ;
        RECT  70.092 2.151 70.212 34.569 ;
        RECT  67.392 2.151 67.512 34.569 ;
        RECT  64.692 2.151 64.812 34.569 ;
        RECT  61.992 2.151 62.112 34.569 ;
        RECT  59.292 2.151 59.412 34.569 ;
        RECT  56.592 2.151 56.712 34.569 ;
        RECT  53.892 2.151 54.012 34.569 ;
        RECT  51.192 2.151 51.312 34.569 ;
        RECT  48.492 2.151 48.612 34.569 ;
        RECT  45.792 2.151 45.912 34.569 ;
        RECT  43.092 2.151 43.212 34.569 ;
        RECT  40.392 2.151 40.512 34.569 ;
        RECT  37.692 2.151 37.812 34.569 ;
        RECT  34.992 2.151 35.112 34.569 ;
        RECT  32.292 2.151 32.412 34.569 ;
        RECT  29.592 2.151 29.712 34.569 ;
        RECT  26.892 2.151 27.012 34.569 ;
        RECT  24.192 2.151 24.312 34.569 ;
        RECT  21.492 2.151 21.612 34.569 ;
        RECT  18.792 2.151 18.912 34.569 ;
        RECT  16.092 2.151 16.212 34.569 ;
        RECT  13.392 2.151 13.512 34.569 ;
        RECT  10.692 2.151 10.812 34.569 ;
        RECT  7.992 2.151 8.112 34.569 ;
        RECT  5.292 2.151 5.412 34.569 ;
        RECT  2.592 2.151 2.712 34.569 ;
    END
  END VDD
  PIN VSS
    DIRECTION INOUT ;
    USE GROUND ;
    PORT
      LAYER M5 ;
        RECT  96.9 2.137 97.02 34.583 ;
        RECT  94.2 2.137 94.32 34.583 ;
        RECT  91.5 2.137 91.62 34.583 ;
        RECT  88.8 2.137 88.92 34.583 ;
        RECT  86.1 2.137 86.22 34.583 ;
        RECT  83.4 2.137 83.52 34.583 ;
        RECT  80.7 2.137 80.82 34.583 ;
        RECT  78 2.137 78.12 34.583 ;
        RECT  75.3 2.137 75.42 34.583 ;
        RECT  72.6 2.137 72.72 34.583 ;
        RECT  69.9 2.137 70.02 34.583 ;
        RECT  67.2 2.137 67.32 34.583 ;
        RECT  64.5 2.137 64.62 34.583 ;
        RECT  61.8 2.137 61.92 34.583 ;
        RECT  59.1 2.137 59.22 34.583 ;
        RECT  56.4 2.137 56.52 34.583 ;
        RECT  53.7 2.137 53.82 34.583 ;
        RECT  51 2.137 51.12 34.583 ;
        RECT  48.3 2.137 48.42 34.583 ;
        RECT  45.6 2.137 45.72 34.583 ;
        RECT  42.9 2.137 43.02 34.583 ;
        RECT  40.2 2.137 40.32 34.583 ;
        RECT  37.5 2.137 37.62 34.583 ;
        RECT  34.8 2.137 34.92 34.583 ;
        RECT  32.1 2.137 32.22 34.583 ;
        RECT  29.4 2.137 29.52 34.583 ;
        RECT  26.7 2.137 26.82 34.583 ;
        RECT  24 2.137 24.12 34.583 ;
        RECT  21.3 2.137 21.42 34.583 ;
        RECT  18.6 2.137 18.72 34.583 ;
        RECT  15.9 2.137 16.02 34.583 ;
        RECT  13.2 2.137 13.32 34.583 ;
        RECT  10.5 2.137 10.62 34.583 ;
        RECT  7.8 2.137 7.92 34.583 ;
        RECT  5.1 2.137 5.22 34.583 ;
        RECT  2.4 2.137 2.52 34.583 ;
    END
  END VSS
  # OT_OBS_CLOSED layer=M5 d_um=1.536 added=177
  OBS
    LAYER RVTN ;
     RECT  2.16 2.16 99.36 2.295 ;
     RECT  2.16 2.565 99.36 2.835 ;
     RECT  2.16 3.105 99.36 3.375 ;
     RECT  2.16 3.645 99.36 3.915 ;
     RECT  2.16 4.185 99.36 4.455 ;
     RECT  2.16 4.725 99.36 4.995 ;
     RECT  2.16 5.265 99.36 5.535 ;
     RECT  2.16 5.805 99.36 6.075 ;
     RECT  2.16 6.345 99.36 6.615 ;
     RECT  2.16 6.885 99.36 7.155 ;
     RECT  2.16 7.425 99.36 7.695 ;
     RECT  2.16 7.965 99.36 8.235 ;
     RECT  2.16 8.505 99.36 8.775 ;
     RECT  2.16 9.045 99.36 9.315 ;
     RECT  2.16 9.585 99.36 9.855 ;
     RECT  2.16 10.125 99.36 10.395 ;
     RECT  2.16 10.665 99.36 10.935 ;
     RECT  2.16 11.205 99.36 11.475 ;
     RECT  2.16 11.745 99.36 12.015 ;
     RECT  2.16 12.285 99.36 12.555 ;
     RECT  2.16 12.825 99.36 13.095 ;
     RECT  2.16 13.365 99.36 13.635 ;
     RECT  2.16 13.905 99.36 14.175 ;
     RECT  2.16 14.445 99.36 14.715 ;
     RECT  2.16 14.985 99.36 15.255 ;
     RECT  2.16 15.525 99.36 15.795 ;
     RECT  2.16 16.065 99.36 16.335 ;
     RECT  2.16 16.605 99.36 16.875 ;
     RECT  2.16 17.145 99.36 17.415 ;
     RECT  2.16 17.685 99.36 17.955 ;
     RECT  2.16 18.225 99.36 18.495 ;
     RECT  2.16 18.765 99.36 19.035 ;
     RECT  2.16 19.305 99.36 19.575 ;
     RECT  2.16 19.845 99.36 20.115 ;
     RECT  2.16 20.385 99.36 20.655 ;
     RECT  2.16 20.925 99.36 21.195 ;
     RECT  2.16 21.465 99.36 21.735 ;
     RECT  2.16 22.005 99.36 22.275 ;
     RECT  2.16 22.545 99.36 22.815 ;
     RECT  2.16 23.085 99.36 23.355 ;
     RECT  2.16 23.625 99.36 23.895 ;
     RECT  2.16 24.165 99.36 24.435 ;
     RECT  2.16 24.705 99.36 24.975 ;
     RECT  2.16 25.245 99.36 25.515 ;
     RECT  2.16 25.785 99.36 26.055 ;
     RECT  2.16 26.325 99.36 26.595 ;
     RECT  2.16 26.865 99.36 27.135 ;
     RECT  2.16 27.405 99.36 27.675 ;
     RECT  2.16 27.945 99.36 28.215 ;
     RECT  2.16 28.485 99.36 28.755 ;
     RECT  2.16 29.025 99.36 29.295 ;
     RECT  2.16 29.565 99.36 29.835 ;
     RECT  2.16 30.105 99.36 30.375 ;
     RECT  2.16 30.645 99.36 30.915 ;
     RECT  2.16 31.185 99.36 31.455 ;
     RECT  2.16 31.725 99.36 31.995 ;
     RECT  2.16 32.265 99.36 32.535 ;
     RECT  2.16 32.805 99.36 33.075 ;
     RECT  2.16 33.345 99.36 33.615 ;
     RECT  2.16 33.885 99.36 34.155 ;
     RECT  2.16 34.425 99.36 34.56 ;
    LAYER RVTP ;
     RECT  2.16 2.295 99.36 2.565 ;
     RECT  2.16 2.835 99.36 3.105 ;
     RECT  2.16 3.375 99.36 3.645 ;
     RECT  2.16 3.915 99.36 4.185 ;
     RECT  2.16 4.455 99.36 4.725 ;
     RECT  2.16 4.995 99.36 5.265 ;
     RECT  2.16 5.535 99.36 5.805 ;
     RECT  2.16 6.075 99.36 6.345 ;
     RECT  2.16 6.615 99.36 6.885 ;
     RECT  2.16 7.155 99.36 7.425 ;
     RECT  2.16 7.695 99.36 7.965 ;
     RECT  2.16 8.235 99.36 8.505 ;
     RECT  2.16 8.775 99.36 9.045 ;
     RECT  2.16 9.315 99.36 9.585 ;
     RECT  2.16 9.855 99.36 10.125 ;
     RECT  2.16 10.395 99.36 10.665 ;
     RECT  2.16 10.935 99.36 11.205 ;
     RECT  2.16 11.475 99.36 11.745 ;
     RECT  2.16 12.015 99.36 12.285 ;
     RECT  2.16 12.555 99.36 12.825 ;
     RECT  2.16 13.095 99.36 13.365 ;
     RECT  2.16 13.635 99.36 13.905 ;
     RECT  2.16 14.175 99.36 14.445 ;
     RECT  2.16 14.715 99.36 14.985 ;
     RECT  2.16 15.255 99.36 15.525 ;
     RECT  2.16 15.795 99.36 16.065 ;
     RECT  2.16 16.335 99.36 16.605 ;
     RECT  2.16 16.875 99.36 17.145 ;
     RECT  2.16 17.415 99.36 17.685 ;
     RECT  2.16 17.955 99.36 18.225 ;
     RECT  2.16 18.495 99.36 18.765 ;
     RECT  2.16 19.035 99.36 19.305 ;
     RECT  2.16 19.575 99.36 19.845 ;
     RECT  2.16 20.115 99.36 20.385 ;
     RECT  2.16 20.655 99.36 20.925 ;
     RECT  2.16 21.195 99.36 21.465 ;
     RECT  2.16 21.735 99.36 22.005 ;
     RECT  2.16 22.275 99.36 22.545 ;
     RECT  2.16 22.815 99.36 23.085 ;
     RECT  2.16 23.355 99.36 23.625 ;
     RECT  2.16 23.895 99.36 24.165 ;
     RECT  2.16 24.435 99.36 24.705 ;
     RECT  2.16 24.975 99.36 25.245 ;
     RECT  2.16 25.515 99.36 25.785 ;
     RECT  2.16 26.055 99.36 26.325 ;
     RECT  2.16 26.595 99.36 26.865 ;
     RECT  2.16 27.135 99.36 27.405 ;
     RECT  2.16 27.675 99.36 27.945 ;
     RECT  2.16 28.215 99.36 28.485 ;
     RECT  2.16 28.755 99.36 29.025 ;
     RECT  2.16 29.295 99.36 29.565 ;
     RECT  2.16 29.835 99.36 30.105 ;
     RECT  2.16 30.375 99.36 30.645 ;
     RECT  2.16 30.915 99.36 31.185 ;
     RECT  2.16 31.455 99.36 31.725 ;
     RECT  2.16 31.995 99.36 32.265 ;
     RECT  2.16 32.535 99.36 32.805 ;
     RECT  2.16 33.075 99.36 33.345 ;
     RECT  2.16 33.615 99.36 33.885 ;
     RECT  2.16 34.155 99.36 34.425 ;
    LAYER M1 ;
     RECT  2.16 2.151 99.36 34.569 ;
    LAYER M2 ;
     RECT  2.16 2.151 3.847 34.569 ;
     RECT  3.847 2.106 4.603 34.569 ;
     RECT  4.603 2.106 4.855 34.794 ;
     RECT  4.855 2.106 4.883 34.839 ;
     RECT  4.883 2.151 5.027 34.839 ;
     RECT  5.027 2.151 5.135 34.794 ;
     RECT  5.035 0.144 5.387 0.162 ;
     RECT  5.135 2.151 7.663 34.569 ;
     RECT  7.663 2.151 7.807 34.65 ;
     RECT  7.807 1.728 7.835 34.65 ;
     RECT  8.023 0.144 8.375 0.162 ;
     RECT  7.835 1.728 8.699 34.569 ;
     RECT  10.003 0.144 10.103 0.162 ;
     RECT  8.699 2.151 10.327 34.569 ;
     RECT  10.327 2.034 10.859 34.569 ;
     RECT  11.695 0.144 12.551 0.162 ;
     RECT  12.451 1.152 12.551 1.17 ;
     RECT  10.859 2.106 12.623 34.569 ;
     RECT  12.623 2.151 13.423 34.569 ;
     RECT  13.423 0.144 13.595 0.162 ;
     RECT  13.423 2.151 13.927 34.794 ;
     RECT  13.927 2.151 14.027 34.839 ;
     RECT  14.143 35.901 14.279 35.919 ;
     RECT  14.647 0.576 15.539 0.594 ;
     RECT  14.027 2.151 15.619 34.569 ;
     RECT  15.619 2.151 16.123 34.758 ;
     RECT  16.051 0.144 16.151 0.162 ;
     RECT  16.123 2.151 16.259 34.794 ;
     RECT  17.095 0.144 17.303 0.162 ;
     RECT  16.259 2.151 17.347 34.569 ;
     RECT  17.347 2.151 17.599 34.794 ;
     RECT  17.599 1.728 17.699 34.794 ;
     RECT  17.095 35.901 17.807 35.919 ;
     RECT  17.699 2.151 18.067 34.794 ;
     RECT  18.067 2.151 18.203 34.839 ;
     RECT  18.203 2.151 18.823 34.794 ;
     RECT  18.823 1.728 19.103 34.794 ;
     RECT  19.039 0.144 19.139 0.162 ;
     RECT  19.103 1.728 19.427 34.569 ;
     RECT  19.039 35.901 20.219 35.919 ;
     RECT  20.263 0.144 20.435 0.162 ;
     RECT  19.427 2.151 20.515 34.569 ;
     RECT  20.515 2.151 20.767 34.794 ;
     RECT  20.767 2.151 21.011 34.839 ;
     RECT  21.011 2.151 21.487 34.794 ;
     RECT  21.019 0.576 21.695 0.594 ;
     RECT  21.487 1.728 21.731 34.794 ;
     RECT  21.739 0.144 21.839 0.162 ;
     RECT  21.731 2.151 21.991 34.794 ;
     RECT  21.991 2.151 22.199 34.839 ;
     RECT  22.199 2.151 22.811 34.758 ;
     RECT  22.811 2.151 23.215 34.569 ;
     RECT  23.215 1.728 23.639 34.569 ;
     RECT  23.639 2.151 23.935 34.569 ;
     RECT  23.935 2.151 24.395 34.794 ;
     RECT  23.215 35.901 24.439 35.919 ;
     RECT  24.511 1.152 24.755 1.17 ;
     RECT  24.691 0.144 24.791 0.162 ;
     RECT  24.439 35.901 24.863 35.964 ;
     RECT  24.395 2.151 25.159 34.569 ;
     RECT  24.943 0.576 25.979 0.594 ;
     RECT  25.159 2.151 26.383 34.794 ;
     RECT  24.863 35.901 26.519 35.919 ;
     RECT  26.635 36.558 26.671 36.576 ;
     RECT  26.671 36.558 26.771 36.648 ;
     RECT  26.383 1.728 26.879 34.794 ;
     RECT  26.879 2.151 27.059 34.794 ;
     RECT  26.887 0.144 27.239 0.162 ;
     RECT  27.059 2.151 27.859 34.569 ;
     RECT  28.111 0.144 28.211 0.162 ;
     RECT  27.859 1.728 28.535 34.569 ;
     RECT  28.535 1.8 28.607 34.569 ;
     RECT  28.363 35.901 28.751 35.919 ;
     RECT  29.479 36.558 29.579 36.648 ;
     RECT  29.371 1.152 29.615 1.17 ;
     RECT  29.579 36.558 29.615 36.576 ;
     RECT  28.607 2.151 30.055 34.569 ;
     RECT  30.055 1.728 30.299 34.569 ;
     RECT  30.307 0.144 31.163 0.162 ;
     RECT  31.027 35.901 31.279 35.919 ;
     RECT  30.299 2.151 31.531 34.569 ;
     RECT  31.531 2.151 31.703 34.794 ;
     RECT  31.279 35.901 31.739 35.964 ;
     RECT  31.739 35.901 31.919 35.919 ;
     RECT  31.703 2.151 32.359 34.569 ;
     RECT  32.935 0.144 33.035 0.162 ;
     RECT  32.359 2.106 33.251 34.569 ;
     RECT  33.251 2.151 33.259 34.569 ;
     RECT  33.259 2.151 33.979 34.758 ;
     RECT  33.007 35.901 34.079 35.919 ;
     RECT  33.979 2.151 34.591 34.794 ;
     RECT  34.591 2.106 34.619 34.794 ;
     RECT  34.619 2.106 34.699 34.569 ;
     RECT  34.699 1.728 34.799 34.569 ;
     RECT  34.951 35.901 35.203 35.919 ;
     RECT  34.799 2.106 35.447 34.569 ;
     RECT  35.447 2.151 35.455 34.569 ;
     RECT  35.455 2.151 36.319 34.839 ;
     RECT  36.319 2.151 36.455 34.884 ;
     RECT  35.203 35.901 36.491 35.964 ;
     RECT  36.355 0.144 36.815 0.162 ;
     RECT  36.491 35.946 37.031 35.964 ;
     RECT  36.455 2.151 37.859 34.794 ;
     RECT  38.371 36.018 38.615 36.036 ;
     RECT  37.859 2.151 38.875 34.569 ;
     RECT  38.875 2.151 39.127 34.794 ;
     RECT  39.127 0.144 39.263 0.162 ;
     RECT  38.623 35.946 39.587 35.964 ;
     RECT  39.127 2.151 39.839 34.839 ;
     RECT  39.839 2.151 40.127 34.794 ;
     RECT  40.171 0.144 40.379 0.162 ;
     RECT  40.127 2.151 41.323 34.569 ;
     RECT  40.819 35.901 41.819 35.919 ;
     RECT  40.603 0.576 41.827 0.594 ;
     RECT  41.827 0.144 41.855 0.594 ;
     RECT  41.855 0.144 41.927 0.162 ;
     RECT  41.323 2.151 42.179 34.794 ;
     RECT  42.475 1.152 42.575 1.17 ;
     RECT  42.799 36.558 42.835 36.576 ;
     RECT  42.835 36.558 42.935 36.648 ;
     RECT  43.267 0.576 43.771 0.594 ;
     RECT  43.771 0.144 43.871 0.594 ;
     RECT  42.179 2.151 44.023 34.569 ;
     RECT  43.871 0.576 44.267 0.594 ;
     RECT  43.051 35.901 44.275 35.919 ;
     RECT  44.023 2.151 44.447 34.794 ;
     RECT  44.275 35.901 44.743 35.964 ;
     RECT  44.447 2.151 44.995 34.569 ;
     RECT  44.995 1.656 45.059 34.569 ;
     RECT  44.743 35.901 45.347 36.036 ;
     RECT  45.347 36.018 45.455 36.036 ;
     RECT  45.059 2.151 45.715 34.569 ;
     RECT  45.715 0.306 45.967 0.324 ;
     RECT  45.967 0.144 45.995 0.324 ;
     RECT  45.995 0.144 46.067 0.162 ;
     RECT  45.715 2.151 46.471 34.794 ;
     RECT  46.471 2.151 46.615 34.839 ;
     RECT  46.615 2.151 46.751 34.92 ;
     RECT  46.939 36.558 46.975 36.576 ;
     RECT  46.975 36.558 47.075 36.648 ;
     RECT  46.751 2.151 47.191 34.569 ;
     RECT  47.191 35.901 47.687 35.919 ;
     RECT  47.191 1.728 47.947 34.569 ;
     RECT  47.947 1.728 48.199 34.794 ;
     RECT  48.199 1.728 48.443 34.839 ;
     RECT  48.667 35.901 48.919 35.919 ;
     RECT  48.919 35.901 49.307 35.964 ;
     RECT  49.387 0.144 49.487 0.162 ;
     RECT  48.443 1.728 49.955 34.569 ;
     RECT  49.307 35.901 50.063 35.919 ;
     RECT  49.955 1.8 50.171 34.569 ;
     RECT  50.171 2.106 50.351 34.569 ;
     RECT  50.395 35.982 50.603 36 ;
     RECT  50.611 0.576 50.971 0.594 ;
     RECT  50.971 0.144 51.143 0.594 ;
     RECT  51.143 0.576 51.359 0.594 ;
     RECT  51.115 35.901 51.367 35.919 ;
     RECT  51.367 35.901 51.403 36.576 ;
     RECT  51.403 35.901 51.503 36.648 ;
     RECT  51.503 35.901 52.079 35.964 ;
     RECT  52.079 35.946 52.151 35.964 ;
     RECT  52.267 0.144 52.691 0.162 ;
     RECT  52.843 35.901 53.411 35.919 ;
     RECT  53.815 36.558 53.851 36.576 ;
     RECT  53.851 36.558 53.951 36.648 ;
     RECT  53.491 0.144 54.131 0.162 ;
     RECT  50.351 2.151 56.515 34.569 ;
     RECT  56.515 0.306 56.731 0.324 ;
     RECT  56.515 2.151 56.731 34.794 ;
     RECT  56.731 0.144 56.759 0.324 ;
     RECT  56.759 0.144 56.831 0.162 ;
     RECT  56.731 2.151 56.831 34.839 ;
     RECT  56.983 35.901 57.955 35.919 ;
     RECT  57.955 35.901 57.983 36 ;
     RECT  56.831 2.151 58.207 34.569 ;
     RECT  57.983 35.982 58.343 36 ;
     RECT  58.207 2.151 58.459 34.794 ;
     RECT  58.459 2.151 58.703 34.839 ;
     RECT  58.703 2.151 59.207 34.794 ;
     RECT  59.179 0.144 59.675 0.162 ;
     RECT  59.207 2.151 59.935 34.569 ;
     RECT  59.935 2.151 60.035 34.758 ;
     RECT  60.295 36.558 60.395 36.648 ;
     RECT  60.395 36.558 60.431 36.576 ;
     RECT  60.655 35.901 61.079 35.919 ;
     RECT  61.879 35.901 62.131 35.919 ;
     RECT  60.035 2.151 62.167 34.569 ;
     RECT  62.131 35.901 62.167 36.576 ;
     RECT  62.167 2.151 62.267 34.758 ;
     RECT  62.167 35.901 62.267 36.648 ;
     RECT  61.735 0.144 62.699 0.162 ;
     RECT  62.267 35.901 63.275 35.964 ;
     RECT  62.267 2.151 63.355 34.569 ;
     RECT  63.355 2.151 63.599 34.794 ;
     RECT  63.275 35.901 63.995 35.919 ;
     RECT  63.599 2.151 64.579 34.569 ;
     RECT  64.579 0.144 64.679 0.162 ;
     RECT  64.831 35.901 65.687 35.919 ;
     RECT  64.579 2.151 65.903 34.794 ;
     RECT  67.027 36.558 67.063 36.576 ;
     RECT  67.063 36.558 67.163 36.648 ;
     RECT  65.903 2.151 67.279 34.758 ;
     RECT  67.279 1.728 67.495 34.794 ;
     RECT  67.495 1.728 67.631 34.839 ;
     RECT  67.631 1.728 67.811 34.758 ;
     RECT  67.495 0.144 68.099 0.162 ;
     RECT  67.999 35.901 68.251 35.919 ;
     RECT  67.811 1.728 68.567 34.569 ;
     RECT  68.567 2.151 68.971 34.569 ;
     RECT  68.251 35.901 69.035 35.964 ;
     RECT  68.971 2.151 69.107 34.794 ;
     RECT  69.035 35.901 69.143 35.919 ;
     RECT  69.107 2.151 69.835 34.569 ;
     RECT  69.223 0.576 70.195 0.594 ;
     RECT  70.195 0.144 70.259 0.594 ;
     RECT  70.259 0.144 70.475 0.162 ;
     RECT  69.835 2.151 70.511 34.794 ;
     RECT  70.447 36.018 71.231 36.036 ;
     RECT  70.511 2.151 71.959 34.569 ;
     RECT  71.959 2.106 72.643 34.569 ;
     RECT  72.643 35.901 72.823 35.919 ;
     RECT  72.823 35.901 72.959 36.648 ;
     RECT  72.643 1.728 73.067 34.569 ;
     RECT  73.615 0.144 73.715 0.162 ;
     RECT  72.959 35.901 73.867 35.919 ;
     RECT  73.867 35.901 74.075 35.964 ;
     RECT  74.075 35.946 74.219 35.964 ;
     RECT  73.067 2.151 74.371 34.569 ;
     RECT  74.371 1.728 74.795 34.569 ;
     RECT  74.795 1.8 75.343 34.569 ;
     RECT  75.271 0.144 75.371 0.162 ;
     RECT  75.343 1.8 75.479 34.65 ;
     RECT  75.479 1.8 75.595 34.569 ;
     RECT  75.595 1.728 76.199 34.569 ;
     RECT  76.063 35.982 76.739 36 ;
     RECT  76.243 0.144 76.955 0.162 ;
     RECT  76.199 2.151 77.287 34.569 ;
     RECT  77.287 2.151 77.791 34.794 ;
     RECT  77.791 2.151 77.999 34.839 ;
     RECT  78.043 35.946 78.295 35.964 ;
     RECT  78.295 35.946 78.683 36.036 ;
     RECT  78.683 36.018 78.763 36.036 ;
     RECT  78.763 36.018 78.799 36.576 ;
     RECT  78.799 36.018 78.899 36.648 ;
     RECT  78.899 36.018 78.971 36.036 ;
     RECT  77.971 0.144 79.115 0.162 ;
     RECT  77.999 2.151 79.267 34.569 ;
     RECT  80.743 35.901 81.211 35.919 ;
     RECT  81.211 35.901 81.355 35.964 ;
     RECT  81.355 35.901 81.383 36.648 ;
     RECT  81.383 35.946 81.455 36.648 ;
     RECT  81.455 35.946 81.491 36.576 ;
     RECT  81.491 35.946 81.743 36 ;
     RECT  79.267 2.151 81.779 34.794 ;
     RECT  80.743 0.144 81.815 0.162 ;
     RECT  81.779 2.151 82.111 34.569 ;
     RECT  82.111 2.106 82.687 34.569 ;
     RECT  82.687 2.106 82.931 34.794 ;
     RECT  81.743 35.946 83.039 35.964 ;
     RECT  82.931 2.151 83.579 34.794 ;
     RECT  83.579 2.151 83.659 34.569 ;
     RECT  83.659 1.728 84.119 34.569 ;
     RECT  83.407 0.144 84.263 0.162 ;
     RECT  84.127 1.152 84.263 1.17 ;
     RECT  84.119 2.151 84.415 34.569 ;
     RECT  83.659 35.901 84.631 35.919 ;
     RECT  84.415 2.151 84.731 34.794 ;
     RECT  84.731 2.151 85.387 34.569 ;
     RECT  84.883 0.576 85.459 0.594 ;
     RECT  85.387 1.656 85.459 34.569 ;
     RECT  85.459 0.576 85.523 34.569 ;
     RECT  85.523 1.152 85.559 34.569 ;
     RECT  84.631 35.901 85.631 35.964 ;
     RECT  85.559 2.151 85.639 34.569 ;
     RECT  85.631 35.946 85.775 35.964 ;
     RECT  85.639 2.151 86.107 34.758 ;
     RECT  86.071 0.144 86.135 0.162 ;
     RECT  85.559 1.152 86.387 1.17 ;
     RECT  86.107 2.151 86.567 34.794 ;
     RECT  86.611 35.946 86.999 35.964 ;
     RECT  86.567 2.151 87.079 34.569 ;
     RECT  87.079 35.901 87.323 35.919 ;
     RECT  87.079 1.728 87.331 34.569 ;
     RECT  87.331 1.728 87.395 34.794 ;
     RECT  88.015 36.126 88.115 36.144 ;
     RECT  87.395 2.106 88.403 34.794 ;
     RECT  88.403 2.151 88.835 34.794 ;
     RECT  88.015 0.144 89.159 0.162 ;
     RECT  88.835 2.151 89.311 34.569 ;
     RECT  89.311 1.728 89.591 34.569 ;
     RECT  90.031 0.576 90.815 0.594 ;
     RECT  89.591 2.151 91.723 34.569 ;
     RECT  90.499 35.901 91.967 35.919 ;
     RECT  91.723 1.728 92.003 34.569 ;
     RECT  91.003 0.144 92.075 0.162 ;
     RECT  92.227 0.576 92.479 0.594 ;
     RECT  92.479 0.576 92.579 1.17 ;
     RECT  92.579 0.576 93.083 0.594 ;
     RECT  92.731 35.901 93.703 35.919 ;
     RECT  93.703 35.901 93.767 36.036 ;
     RECT  93.767 36.018 94.055 36.036 ;
     RECT  94.351 0.144 94.451 0.162 ;
     RECT  95.647 35.901 96.035 35.919 ;
     RECT  96.151 36.558 96.187 36.576 ;
     RECT  96.187 36.558 96.287 36.648 ;
     RECT  95.647 0.576 96.611 0.594 ;
     RECT  92.003 2.151 97.123 34.569 ;
     RECT  97.123 2.151 97.259 34.794 ;
     RECT  97.259 2.151 99.36 34.569 ;
    LAYER M3 ;
     RECT  4.374 0.108 4.608 0.144 ;
     RECT  4.626 0.108 4.86 0.144 ;
     RECT  4.878 0.108 5.112 0.144 ;
     RECT  5.13 0.108 5.364 0.144 ;
     RECT  5.382 0.108 5.58 0.144 ;
     RECT  5.598 0.108 5.832 0.144 ;
     RECT  5.85 0.108 6.084 0.144 ;
     RECT  6.102 0.108 6.336 0.144 ;
     RECT  6.354 0.108 6.588 0.144 ;
     RECT  6.606 0.108 6.804 0.144 ;
     RECT  6.822 0.108 7.056 0.144 ;
     RECT  7.074 0.108 7.308 0.144 ;
     RECT  7.326 0.108 7.56 0.144 ;
     RECT  7.578 0.108 7.812 0.144 ;
     RECT  7.83 0.108 8.028 0.144 ;
     RECT  8.046 0.108 8.28 0.144 ;
     RECT  8.298 0.108 8.532 0.144 ;
     RECT  8.55 0.108 8.784 0.144 ;
     RECT  8.802 0.108 9.036 0.144 ;
     RECT  9.054 0.108 9.252 0.144 ;
     RECT  9.27 0.108 9.504 0.144 ;
     RECT  9.522 0.108 9.756 0.144 ;
     RECT  9.774 0.108 10.008 0.144 ;
     RECT  10.026 0.108 10.26 0.144 ;
     RECT  10.278 0.108 10.476 0.144 ;
     RECT  10.494 0.108 10.728 0.144 ;
     RECT  10.746 0.108 10.98 0.144 ;
     RECT  10.998 0.108 11.232 0.144 ;
     RECT  11.25 0.108 11.484 0.144 ;
     RECT  11.502 0.108 11.7 0.144 ;
     RECT  11.718 0.108 11.952 0.144 ;
     RECT  11.97 0.108 12.204 0.144 ;
     RECT  12.222 0.108 12.456 0.144 ;
     RECT  12.474 0.108 12.708 0.144 ;
     RECT  12.726 0.108 12.924 0.144 ;
     RECT  12.942 0.108 13.176 0.144 ;
     RECT  13.194 0.108 13.428 0.144 ;
     RECT  13.446 0.108 13.68 0.144 ;
     RECT  13.698 0.108 13.932 0.144 ;
     RECT  13.95 0.108 14.148 0.144 ;
     RECT  14.166 0.108 14.4 0.144 ;
     RECT  14.418 0.108 14.652 0.144 ;
     RECT  14.67 0.108 14.904 0.144 ;
     RECT  14.922 0.108 15.156 0.144 ;
     RECT  15.174 0.108 15.372 0.144 ;
     RECT  15.39 0.108 15.624 0.144 ;
     RECT  15.642 0.108 15.876 0.144 ;
     RECT  15.894 0.108 16.128 0.144 ;
     RECT  16.146 0.108 16.38 0.144 ;
     RECT  16.398 0.108 16.596 0.144 ;
     RECT  16.614 0.108 16.848 0.144 ;
     RECT  16.866 0.108 17.1 0.144 ;
     RECT  17.118 0.108 17.352 0.144 ;
     RECT  17.37 0.108 17.604 0.144 ;
     RECT  17.622 0.108 17.82 0.144 ;
     RECT  17.838 0.108 18.072 0.144 ;
     RECT  18.09 0.108 18.324 0.144 ;
     RECT  18.342 0.108 18.576 0.144 ;
     RECT  18.594 0.108 18.828 0.144 ;
     RECT  18.846 0.108 19.044 0.144 ;
     RECT  19.062 0.108 19.296 0.144 ;
     RECT  19.314 0.108 19.548 0.144 ;
     RECT  19.566 0.108 19.8 0.144 ;
     RECT  19.818 0.108 20.052 0.144 ;
     RECT  20.07 0.108 20.268 0.144 ;
     RECT  20.286 0.108 20.52 0.144 ;
     RECT  20.538 0.108 20.772 0.144 ;
     RECT  20.79 0.108 21.024 0.144 ;
     RECT  21.042 0.108 21.276 0.144 ;
     RECT  21.294 0.108 21.492 0.144 ;
     RECT  21.51 0.108 21.744 0.144 ;
     RECT  21.762 0.108 21.996 0.144 ;
     RECT  22.014 0.108 22.248 0.144 ;
     RECT  22.266 0.108 22.5 0.144 ;
     RECT  22.518 0.108 22.716 0.144 ;
     RECT  22.734 0.108 22.968 0.144 ;
     RECT  22.986 0.108 23.22 0.144 ;
     RECT  23.238 0.108 23.472 0.144 ;
     RECT  23.49 0.108 23.724 0.144 ;
     RECT  23.742 0.108 23.94 0.144 ;
     RECT  23.958 0.108 24.192 0.144 ;
     RECT  24.21 0.108 24.444 0.144 ;
     RECT  24.462 0.108 24.696 0.144 ;
     RECT  24.714 0.108 24.948 0.144 ;
     RECT  24.966 0.108 25.164 0.144 ;
     RECT  25.182 0.108 25.416 0.144 ;
     RECT  25.434 0.108 25.668 0.144 ;
     RECT  25.686 0.108 25.92 0.144 ;
     RECT  25.938 0.108 26.172 0.144 ;
     RECT  26.19 0.108 26.388 0.144 ;
     RECT  26.406 0.108 26.64 0.144 ;
     RECT  26.658 0.108 26.892 0.144 ;
     RECT  26.91 0.108 27.144 0.144 ;
     RECT  27.162 0.108 27.396 0.144 ;
     RECT  27.414 0.108 27.612 0.144 ;
     RECT  27.63 0.108 27.864 0.144 ;
     RECT  27.882 0.108 28.116 0.144 ;
     RECT  28.134 0.108 28.368 0.144 ;
     RECT  28.386 0.108 28.584 0.144 ;
     RECT  28.602 0.108 28.836 0.144 ;
     RECT  28.854 0.108 29.088 0.144 ;
     RECT  29.106 0.108 29.34 0.144 ;
     RECT  29.358 0.108 29.592 0.144 ;
     RECT  29.61 0.108 29.808 0.144 ;
     RECT  29.826 0.108 30.06 0.144 ;
     RECT  30.078 0.108 30.312 0.144 ;
     RECT  30.33 0.108 30.564 0.144 ;
     RECT  30.582 0.108 30.816 0.144 ;
     RECT  30.834 0.108 31.032 0.144 ;
     RECT  31.05 0.108 31.284 0.144 ;
     RECT  31.302 0.108 31.536 0.144 ;
     RECT  31.554 0.108 31.788 0.144 ;
     RECT  31.806 0.108 32.04 0.144 ;
     RECT  32.058 0.108 32.256 0.144 ;
     RECT  32.274 0.108 32.508 0.144 ;
     RECT  32.526 0.108 32.76 0.144 ;
     RECT  32.778 0.108 33.012 0.144 ;
     RECT  33.03 0.108 33.264 0.144 ;
     RECT  33.282 0.108 33.48 0.144 ;
     RECT  33.498 0.108 33.732 0.144 ;
     RECT  33.75 0.108 33.984 0.144 ;
     RECT  34.002 0.108 34.236 0.144 ;
     RECT  34.254 0.108 34.488 0.144 ;
     RECT  34.506 0.108 34.704 0.144 ;
     RECT  34.722 0.108 34.956 0.144 ;
     RECT  34.974 0.108 35.208 0.144 ;
     RECT  35.226 0.108 35.46 0.144 ;
     RECT  35.478 0.108 35.712 0.144 ;
     RECT  35.73 0.108 35.928 0.144 ;
     RECT  35.946 0.108 36.18 0.144 ;
     RECT  36.198 0.108 36.432 0.144 ;
     RECT  36.45 0.108 36.684 0.144 ;
     RECT  36.702 0.108 36.936 0.144 ;
     RECT  36.954 0.108 37.152 0.144 ;
     RECT  37.17 0.108 37.404 0.144 ;
     RECT  37.422 0.108 37.656 0.144 ;
     RECT  37.674 0.108 37.908 0.144 ;
     RECT  37.926 0.108 38.16 0.144 ;
     RECT  38.178 0.108 38.376 0.144 ;
     RECT  38.394 0.108 38.628 0.144 ;
     RECT  38.646 0.108 38.88 0.144 ;
     RECT  38.898 0.108 39.132 0.144 ;
     RECT  39.15 0.108 39.384 0.144 ;
     RECT  39.402 0.108 39.6 0.144 ;
     RECT  39.618 0.108 39.852 0.144 ;
     RECT  39.87 0.108 40.104 0.144 ;
     RECT  40.122 0.108 40.356 0.144 ;
     RECT  40.374 0.108 40.608 0.144 ;
     RECT  40.626 0.108 40.824 0.144 ;
     RECT  40.842 0.108 41.076 0.144 ;
     RECT  41.094 0.108 41.328 0.144 ;
     RECT  41.346 0.108 41.58 0.144 ;
     RECT  41.598 0.108 41.832 0.144 ;
     RECT  41.85 0.108 42.048 0.144 ;
     RECT  42.066 0.108 42.3 0.144 ;
     RECT  42.318 0.108 42.552 0.144 ;
     RECT  42.57 0.108 42.804 0.144 ;
     RECT  42.822 0.108 43.056 0.144 ;
     RECT  43.074 0.108 43.272 0.144 ;
     RECT  43.29 0.108 43.524 0.144 ;
     RECT  43.542 0.108 43.776 0.144 ;
     RECT  43.794 0.108 44.028 0.144 ;
     RECT  44.046 0.108 44.28 0.144 ;
     RECT  44.298 0.108 44.496 0.144 ;
     RECT  44.514 0.108 44.748 0.144 ;
     RECT  44.766 0.108 45 0.144 ;
     RECT  45.018 0.108 45.252 0.144 ;
     RECT  45.27 0.108 45.504 0.144 ;
     RECT  45.522 0.108 45.72 0.144 ;
     RECT  45.738 0.108 45.972 0.144 ;
     RECT  45.99 0.108 46.224 0.144 ;
     RECT  46.242 0.108 46.476 0.144 ;
     RECT  46.494 0.108 46.728 0.144 ;
     RECT  46.746 0.108 46.944 0.144 ;
     RECT  46.962 0.108 47.196 0.144 ;
     RECT  47.214 0.108 47.448 0.144 ;
     RECT  47.466 0.108 47.7 0.144 ;
     RECT  47.718 0.108 47.952 0.144 ;
     RECT  47.97 0.108 48.168 0.144 ;
     RECT  48.186 0.108 48.42 0.144 ;
     RECT  48.438 0.108 48.672 0.144 ;
     RECT  48.69 0.108 48.924 0.144 ;
     RECT  48.942 0.108 49.176 0.144 ;
     RECT  49.194 0.108 49.392 0.144 ;
     RECT  49.41 0.108 49.644 0.144 ;
     RECT  49.662 0.108 49.896 0.144 ;
     RECT  49.914 0.108 50.148 0.144 ;
     RECT  50.166 0.108 50.4 0.144 ;
     RECT  50.418 0.108 50.616 0.144 ;
     RECT  50.634 0.108 50.868 0.144 ;
     RECT  50.886 0.108 51.12 0.144 ;
     RECT  51.138 0.108 51.372 0.144 ;
     RECT  51.39 0.108 51.624 0.144 ;
     RECT  51.642 0.108 51.84 0.144 ;
     RECT  51.858 0.108 52.092 0.144 ;
     RECT  52.11 0.108 52.344 0.144 ;
     RECT  52.362 0.108 52.596 0.144 ;
     RECT  52.614 0.108 52.848 0.144 ;
     RECT  52.866 0.108 53.064 0.144 ;
     RECT  53.082 0.108 53.316 0.144 ;
     RECT  53.334 0.108 53.568 0.144 ;
     RECT  53.586 0.108 53.82 0.144 ;
     RECT  53.838 0.108 54.072 0.144 ;
     RECT  54.09 0.108 54.288 0.144 ;
     RECT  54.306 0.108 54.54 0.144 ;
     RECT  54.558 0.108 54.792 0.144 ;
     RECT  54.81 0.108 55.044 0.144 ;
     RECT  55.062 0.108 55.296 0.144 ;
     RECT  55.314 0.108 55.512 0.144 ;
     RECT  55.53 0.108 55.764 0.144 ;
     RECT  55.782 0.108 56.016 0.144 ;
     RECT  56.034 0.108 56.268 0.144 ;
     RECT  56.286 0.108 56.52 0.144 ;
     RECT  56.538 0.108 56.736 0.144 ;
     RECT  56.754 0.108 56.988 0.144 ;
     RECT  57.006 0.108 57.24 0.144 ;
     RECT  57.258 0.108 57.492 0.144 ;
     RECT  57.51 0.108 57.744 0.144 ;
     RECT  57.762 0.108 57.96 0.144 ;
     RECT  57.978 0.108 58.212 0.144 ;
     RECT  58.23 0.108 58.464 0.144 ;
     RECT  58.482 0.108 58.716 0.144 ;
     RECT  58.734 0.108 58.932 0.144 ;
     RECT  58.95 0.108 59.184 0.144 ;
     RECT  59.202 0.108 59.436 0.144 ;
     RECT  59.454 0.108 59.688 0.144 ;
     RECT  59.706 0.108 59.94 0.144 ;
     RECT  59.958 0.108 60.156 0.144 ;
     RECT  60.174 0.108 60.408 0.144 ;
     RECT  60.426 0.108 60.66 0.144 ;
     RECT  60.678 0.108 60.912 0.144 ;
     RECT  60.93 0.108 61.164 0.144 ;
     RECT  61.182 0.108 61.38 0.144 ;
     RECT  61.398 0.108 61.632 0.144 ;
     RECT  61.65 0.108 61.884 0.144 ;
     RECT  61.902 0.108 62.136 0.144 ;
     RECT  62.154 0.108 62.388 0.144 ;
     RECT  62.406 0.108 62.604 0.144 ;
     RECT  62.622 0.108 62.856 0.144 ;
     RECT  62.874 0.108 63.108 0.144 ;
     RECT  63.126 0.108 63.36 0.144 ;
     RECT  63.378 0.108 63.612 0.144 ;
     RECT  63.63 0.108 63.828 0.144 ;
     RECT  63.846 0.108 64.08 0.144 ;
     RECT  64.098 0.108 64.332 0.144 ;
     RECT  64.35 0.108 64.584 0.144 ;
     RECT  64.602 0.108 64.836 0.144 ;
     RECT  64.854 0.108 65.052 0.144 ;
     RECT  65.07 0.108 65.304 0.144 ;
     RECT  65.322 0.108 65.556 0.144 ;
     RECT  65.574 0.108 65.808 0.144 ;
     RECT  65.826 0.108 66.06 0.144 ;
     RECT  66.078 0.108 66.276 0.144 ;
     RECT  66.294 0.108 66.528 0.144 ;
     RECT  66.546 0.108 66.78 0.144 ;
     RECT  66.798 0.108 67.032 0.144 ;
     RECT  67.05 0.108 67.284 0.144 ;
     RECT  67.302 0.108 67.5 0.144 ;
     RECT  67.518 0.108 67.752 0.144 ;
     RECT  67.77 0.108 68.004 0.144 ;
     RECT  68.022 0.108 68.256 0.144 ;
     RECT  68.274 0.108 68.508 0.144 ;
     RECT  68.526 0.108 68.724 0.144 ;
     RECT  68.742 0.108 68.976 0.144 ;
     RECT  68.994 0.108 69.228 0.144 ;
     RECT  69.246 0.108 69.48 0.144 ;
     RECT  69.498 0.108 69.732 0.144 ;
     RECT  69.75 0.108 69.948 0.144 ;
     RECT  69.966 0.108 70.2 0.144 ;
     RECT  70.218 0.108 70.452 0.144 ;
     RECT  70.47 0.108 70.704 0.144 ;
     RECT  70.722 0.108 70.956 0.144 ;
     RECT  70.974 0.108 71.172 0.144 ;
     RECT  71.19 0.108 71.424 0.144 ;
     RECT  71.442 0.108 71.676 0.144 ;
     RECT  71.694 0.108 71.928 0.144 ;
     RECT  71.946 0.108 72.18 0.144 ;
     RECT  72.198 0.108 72.396 0.144 ;
     RECT  72.414 0.108 72.648 0.144 ;
     RECT  72.666 0.108 72.9 0.144 ;
     RECT  72.918 0.108 73.152 0.144 ;
     RECT  73.17 0.108 73.404 0.144 ;
     RECT  73.422 0.108 73.62 0.144 ;
     RECT  73.638 0.108 73.872 0.144 ;
     RECT  73.89 0.108 74.124 0.144 ;
     RECT  74.142 0.108 74.376 0.144 ;
     RECT  74.394 0.108 74.628 0.144 ;
     RECT  74.646 0.108 74.844 0.144 ;
     RECT  74.862 0.108 75.096 0.144 ;
     RECT  75.114 0.108 75.348 0.144 ;
     RECT  75.366 0.108 75.6 0.144 ;
     RECT  75.618 0.108 75.852 0.144 ;
     RECT  75.87 0.108 76.068 0.144 ;
     RECT  76.086 0.108 76.32 0.144 ;
     RECT  76.338 0.108 76.572 0.144 ;
     RECT  76.59 0.108 76.824 0.144 ;
     RECT  76.842 0.108 77.076 0.144 ;
     RECT  77.094 0.108 77.292 0.144 ;
     RECT  77.31 0.108 77.544 0.144 ;
     RECT  77.562 0.108 77.796 0.144 ;
     RECT  77.814 0.108 78.048 0.144 ;
     RECT  78.066 0.108 78.3 0.144 ;
     RECT  78.318 0.108 78.516 0.144 ;
     RECT  78.534 0.108 78.768 0.144 ;
     RECT  78.786 0.108 79.02 0.144 ;
     RECT  79.038 0.108 79.272 0.144 ;
     RECT  79.29 0.108 79.524 0.144 ;
     RECT  79.542 0.108 79.74 0.144 ;
     RECT  79.758 0.108 79.992 0.144 ;
     RECT  80.01 0.108 80.244 0.144 ;
     RECT  80.262 0.108 80.496 0.144 ;
     RECT  80.514 0.108 80.748 0.144 ;
     RECT  80.766 0.108 80.964 0.144 ;
     RECT  80.982 0.108 81.216 0.144 ;
     RECT  81.234 0.108 81.468 0.144 ;
     RECT  81.486 0.108 81.72 0.144 ;
     RECT  81.738 0.108 81.972 0.144 ;
     RECT  81.99 0.108 82.188 0.144 ;
     RECT  82.206 0.108 82.44 0.144 ;
     RECT  82.458 0.108 82.692 0.144 ;
     RECT  82.71 0.108 82.944 0.144 ;
     RECT  82.962 0.108 83.196 0.144 ;
     RECT  83.214 0.108 83.412 0.144 ;
     RECT  83.43 0.108 83.664 0.144 ;
     RECT  83.682 0.108 83.916 0.144 ;
     RECT  83.934 0.108 84.168 0.144 ;
     RECT  84.186 0.108 84.42 0.144 ;
     RECT  84.438 0.108 84.636 0.144 ;
     RECT  84.654 0.108 84.888 0.144 ;
     RECT  84.906 0.108 85.14 0.144 ;
     RECT  85.158 0.108 85.392 0.144 ;
     RECT  85.41 0.108 85.644 0.144 ;
     RECT  85.662 0.108 85.86 0.144 ;
     RECT  85.878 0.108 86.112 0.144 ;
     RECT  86.13 0.108 86.364 0.144 ;
     RECT  86.382 0.108 86.616 0.144 ;
     RECT  86.634 0.108 86.868 0.144 ;
     RECT  86.886 0.108 87.084 0.144 ;
     RECT  87.102 0.108 87.336 0.144 ;
     RECT  87.354 0.108 87.588 0.144 ;
     RECT  87.606 0.108 87.84 0.144 ;
     RECT  87.858 0.108 88.092 0.144 ;
     RECT  88.11 0.108 88.308 0.144 ;
     RECT  88.326 0.108 88.56 0.144 ;
     RECT  88.578 0.108 88.812 0.144 ;
     RECT  88.83 0.108 89.064 0.144 ;
     RECT  89.082 0.108 89.316 0.144 ;
     RECT  89.334 0.108 89.532 0.144 ;
     RECT  89.55 0.108 89.784 0.144 ;
     RECT  89.802 0.108 90.036 0.144 ;
     RECT  90.054 0.108 90.288 0.144 ;
     RECT  90.306 0.108 90.504 0.144 ;
     RECT  90.522 0.108 90.756 0.144 ;
     RECT  90.774 0.108 91.008 0.144 ;
     RECT  91.026 0.108 91.26 0.144 ;
     RECT  91.278 0.108 91.512 0.144 ;
     RECT  91.53 0.108 91.728 0.144 ;
     RECT  91.746 0.108 91.98 0.144 ;
     RECT  91.998 0.108 92.232 0.144 ;
     RECT  92.25 0.108 92.484 0.144 ;
     RECT  92.502 0.108 92.736 0.144 ;
     RECT  92.754 0.108 92.952 0.144 ;
     RECT  92.97 0.108 93.204 0.144 ;
     RECT  93.222 0.108 93.456 0.144 ;
     RECT  93.474 0.108 93.708 0.144 ;
     RECT  93.726 0.108 93.96 0.144 ;
     RECT  93.978 0.108 94.176 0.144 ;
     RECT  94.194 0.108 94.428 0.144 ;
     RECT  94.446 0.108 94.68 0.144 ;
     RECT  94.698 0.108 94.932 0.144 ;
     RECT  94.95 0.108 95.184 0.144 ;
     RECT  95.202 0.108 95.4 0.144 ;
     RECT  95.418 0.108 95.652 0.144 ;
     RECT  95.67 0.108 95.904 0.144 ;
     RECT  95.922 0.108 96.156 0.144 ;
     RECT  96.174 0.108 96.408 0.144 ;
     RECT  96.426 0.108 96.624 0.144 ;
     RECT  96.642 0.108 96.876 0.144 ;
     RECT  96.894 0.108 97.128 0.144 ;
     RECT  4.356 0.144 97.146 0.173 ;
     RECT  4.356 0.173 65.322 0.221 ;
     RECT  24.732 0.221 65.322 0.317 ;
     RECT  61.164 0.317 65.322 0.557 ;
     RECT  66.06 0.173 97.146 0.557 ;
     RECT  66.06 0.557 72.666 0.599 ;
     RECT  4.356 0.221 23.958 1.147 ;
     RECT  24.732 0.317 60.426 1.147 ;
     RECT  4.356 1.147 60.426 1.723 ;
     RECT  61.164 0.557 63.378 1.723 ;
     RECT  64.656 0.557 65.322 1.723 ;
     RECT  66.06 0.599 68.526 1.723 ;
     RECT  69.48 0.599 72.666 1.723 ;
     RECT  73.404 0.557 97.146 1.723 ;
     RECT  4.356 1.723 65.322 2.101 ;
     RECT  3.852 2.101 65.322 2.191 ;
     RECT  66.06 1.723 68.598 2.191 ;
     RECT  69.372 1.723 97.146 2.191 ;
     RECT  3.852 2.191 98.118 2.255 ;
     RECT  2.415 2.143 2.505 2.413 ;
     RECT  4.32 2.255 98.118 2.641 ;
     RECT  4.32 2.641 98.442 2.767 ;
     RECT  2.415 2.413 2.697 3.181 ;
     RECT  4.32 2.767 99.018 3.181 ;
     RECT  2.415 3.181 99.018 3.437 ;
     RECT  3.996 3.437 99.018 3.749 ;
     RECT  4.284 3.749 99.018 3.991 ;
     RECT  4.284 3.991 99.162 4.648 ;
     RECT  4.14 4.648 99.162 4.649 ;
     RECT  4.14 4.649 4.302 4.685 ;
     RECT  5.04 4.649 99.162 6.305 ;
     RECT  77.796 6.305 99.162 7.079 ;
     RECT  77.796 7.079 93.33 7.133 ;
     RECT  5.04 6.305 77.058 8.041 ;
     RECT  77.796 7.133 93.294 8.041 ;
     RECT  5.04 8.041 93.294 8.401 ;
     RECT  94.068 7.079 99.162 8.401 ;
     RECT  4.284 4.685 4.302 10.355 ;
     RECT  5.04 8.401 99.162 10.471 ;
     RECT  4.464 10.471 99.162 10.733 ;
     RECT  4.464 10.733 98.586 17.491 ;
     RECT  4.356 17.491 98.586 17.761 ;
     RECT  4.356 17.761 98.622 18.455 ;
     RECT  4.356 18.455 98.37 18.571 ;
     RECT  4.284 18.571 98.37 18.995 ;
     RECT  4.5 18.995 98.334 28.021 ;
     RECT  4.356 28.021 98.334 28.715 ;
     RECT  2.415 3.437 2.697 34.307 ;
     RECT  2.415 34.307 2.505 34.577 ;
     RECT  4.356 28.715 97.614 35.981 ;
     RECT  4.356 35.981 97.146 36.576 ;
     RECT  4.374 36.576 4.608 36.588 ;
     RECT  4.626 36.576 4.86 36.588 ;
     RECT  4.878 36.576 5.112 36.588 ;
     RECT  5.13 36.576 5.364 36.588 ;
     RECT  5.382 36.576 5.58 36.588 ;
     RECT  5.598 36.576 5.832 36.588 ;
     RECT  5.85 36.576 6.084 36.588 ;
     RECT  6.102 36.576 6.336 36.588 ;
     RECT  6.354 36.576 6.588 36.588 ;
     RECT  6.606 36.576 6.804 36.588 ;
     RECT  6.822 36.576 7.056 36.588 ;
     RECT  7.074 36.576 7.308 36.588 ;
     RECT  7.326 36.576 7.56 36.588 ;
     RECT  7.578 36.576 7.812 36.588 ;
     RECT  7.83 36.576 8.028 36.588 ;
     RECT  8.046 36.576 8.28 36.588 ;
     RECT  8.298 36.576 8.532 36.588 ;
     RECT  8.55 36.576 8.784 36.588 ;
     RECT  8.802 36.576 9.036 36.588 ;
     RECT  9.054 36.576 9.252 36.588 ;
     RECT  9.27 36.576 9.504 36.588 ;
     RECT  9.522 36.576 9.756 36.588 ;
     RECT  9.774 36.576 10.008 36.588 ;
     RECT  10.026 36.576 10.26 36.588 ;
     RECT  10.278 36.576 10.476 36.588 ;
     RECT  10.494 36.576 10.728 36.588 ;
     RECT  10.746 36.576 10.98 36.588 ;
     RECT  10.998 36.576 11.232 36.588 ;
     RECT  11.25 36.576 11.484 36.588 ;
     RECT  11.502 36.576 11.7 36.588 ;
     RECT  11.718 36.576 11.952 36.588 ;
     RECT  11.97 36.576 12.204 36.588 ;
     RECT  12.222 36.576 12.456 36.588 ;
     RECT  12.474 36.576 12.708 36.588 ;
     RECT  12.726 36.576 12.924 36.588 ;
     RECT  12.942 36.576 13.176 36.588 ;
     RECT  13.194 36.576 13.428 36.588 ;
     RECT  13.446 36.576 13.68 36.588 ;
     RECT  13.698 36.576 13.932 36.588 ;
     RECT  13.95 36.576 14.148 36.588 ;
     RECT  14.166 36.576 14.4 36.588 ;
     RECT  14.418 36.576 14.652 36.588 ;
     RECT  14.67 36.576 14.904 36.588 ;
     RECT  14.922 36.576 15.156 36.588 ;
     RECT  15.174 36.576 15.372 36.588 ;
     RECT  15.39 36.576 15.624 36.588 ;
     RECT  15.642 36.576 15.876 36.588 ;
     RECT  15.894 36.576 16.128 36.588 ;
     RECT  16.146 36.576 16.38 36.588 ;
     RECT  16.398 36.576 16.596 36.588 ;
     RECT  16.614 36.576 16.848 36.588 ;
     RECT  16.866 36.576 17.1 36.588 ;
     RECT  17.118 36.576 17.352 36.588 ;
     RECT  17.37 36.576 17.604 36.588 ;
     RECT  17.622 36.576 17.82 36.588 ;
     RECT  17.838 36.576 18.072 36.588 ;
     RECT  18.09 36.576 18.324 36.588 ;
     RECT  18.342 36.576 18.576 36.588 ;
     RECT  18.594 36.576 18.828 36.588 ;
     RECT  18.846 36.576 19.044 36.588 ;
     RECT  19.062 36.576 19.296 36.588 ;
     RECT  19.314 36.576 19.548 36.588 ;
     RECT  19.566 36.576 19.8 36.588 ;
     RECT  19.818 36.576 20.052 36.588 ;
     RECT  20.07 36.576 20.268 36.588 ;
     RECT  20.286 36.576 20.52 36.588 ;
     RECT  20.538 36.576 20.772 36.588 ;
     RECT  20.79 36.576 21.024 36.588 ;
     RECT  21.042 36.576 21.276 36.588 ;
     RECT  21.294 36.576 21.492 36.588 ;
     RECT  21.51 36.576 21.744 36.588 ;
     RECT  21.762 36.576 21.996 36.588 ;
     RECT  22.014 36.576 22.248 36.588 ;
     RECT  22.266 36.576 22.5 36.588 ;
     RECT  22.518 36.576 22.716 36.588 ;
     RECT  22.734 36.576 22.968 36.588 ;
     RECT  22.986 36.576 23.22 36.588 ;
     RECT  23.238 36.576 23.472 36.588 ;
     RECT  23.49 36.576 23.724 36.588 ;
     RECT  23.742 36.576 23.94 36.588 ;
     RECT  23.958 36.576 24.192 36.588 ;
     RECT  24.21 36.576 24.444 36.588 ;
     RECT  24.462 36.576 24.696 36.588 ;
     RECT  24.714 36.576 24.948 36.588 ;
     RECT  24.966 36.576 25.164 36.588 ;
     RECT  25.182 36.576 25.416 36.588 ;
     RECT  25.434 36.576 25.668 36.588 ;
     RECT  25.686 36.576 25.92 36.588 ;
     RECT  25.938 36.576 26.172 36.588 ;
     RECT  26.19 36.576 26.388 36.588 ;
     RECT  26.406 36.576 26.64 36.588 ;
     RECT  26.658 36.576 26.892 36.588 ;
     RECT  26.91 36.576 27.144 36.588 ;
     RECT  27.162 36.576 27.396 36.588 ;
     RECT  27.414 36.576 27.612 36.588 ;
     RECT  27.63 36.576 27.864 36.588 ;
     RECT  27.882 36.576 28.116 36.588 ;
     RECT  28.134 36.576 28.368 36.588 ;
     RECT  28.386 36.576 28.584 36.588 ;
     RECT  28.602 36.576 28.836 36.588 ;
     RECT  28.854 36.576 29.088 36.588 ;
     RECT  29.106 36.576 29.34 36.588 ;
     RECT  29.358 36.576 29.592 36.588 ;
     RECT  29.61 36.576 29.808 36.588 ;
     RECT  29.826 36.576 30.06 36.588 ;
     RECT  30.078 36.576 30.312 36.588 ;
     RECT  30.33 36.576 30.564 36.588 ;
     RECT  30.582 36.576 30.816 36.588 ;
     RECT  30.834 36.576 31.032 36.588 ;
     RECT  31.05 36.576 31.284 36.588 ;
     RECT  31.302 36.576 31.536 36.588 ;
     RECT  31.554 36.576 31.788 36.588 ;
     RECT  31.806 36.576 32.04 36.588 ;
     RECT  32.058 36.576 32.256 36.588 ;
     RECT  32.274 36.576 32.508 36.588 ;
     RECT  32.526 36.576 32.76 36.588 ;
     RECT  32.778 36.576 33.012 36.588 ;
     RECT  33.03 36.576 33.264 36.588 ;
     RECT  33.282 36.576 33.48 36.588 ;
     RECT  33.498 36.576 33.732 36.588 ;
     RECT  33.75 36.576 33.984 36.588 ;
     RECT  34.002 36.576 34.236 36.588 ;
     RECT  34.254 36.576 34.488 36.588 ;
     RECT  34.506 36.576 34.704 36.588 ;
     RECT  34.722 36.576 34.956 36.588 ;
     RECT  34.974 36.576 35.208 36.588 ;
     RECT  35.226 36.576 35.46 36.588 ;
     RECT  35.478 36.576 35.712 36.588 ;
     RECT  35.73 36.576 35.928 36.588 ;
     RECT  35.946 36.576 36.18 36.588 ;
     RECT  36.198 36.576 36.432 36.588 ;
     RECT  36.45 36.576 36.684 36.588 ;
     RECT  36.702 36.576 36.936 36.588 ;
     RECT  36.954 36.576 37.152 36.588 ;
     RECT  37.17 36.576 37.404 36.588 ;
     RECT  37.422 36.576 37.656 36.588 ;
     RECT  37.674 36.576 37.908 36.588 ;
     RECT  37.926 36.576 38.16 36.588 ;
     RECT  38.178 36.576 38.376 36.588 ;
     RECT  38.394 36.576 38.628 36.588 ;
     RECT  38.646 36.576 38.88 36.588 ;
     RECT  38.898 36.576 39.132 36.588 ;
     RECT  39.15 36.576 39.384 36.588 ;
     RECT  39.402 36.576 39.6 36.588 ;
     RECT  39.618 36.576 39.852 36.588 ;
     RECT  39.87 36.576 40.104 36.588 ;
     RECT  40.122 36.576 40.356 36.588 ;
     RECT  40.374 36.576 40.608 36.588 ;
     RECT  40.626 36.576 40.824 36.588 ;
     RECT  40.842 36.576 41.076 36.588 ;
     RECT  41.094 36.576 41.328 36.588 ;
     RECT  41.346 36.576 41.58 36.588 ;
     RECT  41.598 36.576 41.832 36.588 ;
     RECT  41.85 36.576 42.048 36.588 ;
     RECT  42.066 36.576 42.3 36.588 ;
     RECT  42.318 36.576 42.552 36.588 ;
     RECT  42.57 36.576 42.804 36.588 ;
     RECT  42.822 36.576 43.056 36.588 ;
     RECT  43.074 36.576 43.272 36.588 ;
     RECT  43.29 36.576 43.524 36.588 ;
     RECT  43.542 36.576 43.776 36.588 ;
     RECT  43.794 36.576 44.028 36.588 ;
     RECT  44.046 36.576 44.28 36.588 ;
     RECT  44.298 36.576 44.496 36.588 ;
     RECT  44.514 36.576 44.748 36.588 ;
     RECT  44.766 36.576 45 36.588 ;
     RECT  45.018 36.576 45.252 36.588 ;
     RECT  45.27 36.576 45.504 36.588 ;
     RECT  45.522 36.576 45.72 36.588 ;
     RECT  45.738 36.576 45.972 36.588 ;
     RECT  45.99 36.576 46.224 36.588 ;
     RECT  46.242 36.576 46.476 36.588 ;
     RECT  46.494 36.576 46.728 36.588 ;
     RECT  46.746 36.576 46.944 36.588 ;
     RECT  46.962 36.576 47.196 36.588 ;
     RECT  47.214 36.576 47.448 36.588 ;
     RECT  47.466 36.576 47.7 36.588 ;
     RECT  47.718 36.576 47.952 36.588 ;
     RECT  47.97 36.576 48.168 36.588 ;
     RECT  48.186 36.576 48.42 36.588 ;
     RECT  48.438 36.576 48.672 36.588 ;
     RECT  48.69 36.576 48.924 36.588 ;
     RECT  48.942 36.576 49.176 36.588 ;
     RECT  49.194 36.576 49.392 36.588 ;
     RECT  49.41 36.576 49.644 36.588 ;
     RECT  49.662 36.576 49.896 36.588 ;
     RECT  49.914 36.576 50.148 36.588 ;
     RECT  50.166 36.576 50.4 36.588 ;
     RECT  50.418 36.576 50.616 36.588 ;
     RECT  50.634 36.576 50.868 36.588 ;
     RECT  50.886 36.576 51.12 36.588 ;
     RECT  51.138 36.576 51.372 36.588 ;
     RECT  51.39 36.576 51.624 36.588 ;
     RECT  51.642 36.576 51.84 36.588 ;
     RECT  51.858 36.576 52.092 36.588 ;
     RECT  52.11 36.576 52.344 36.588 ;
     RECT  52.362 36.576 52.596 36.588 ;
     RECT  52.614 36.576 52.848 36.588 ;
     RECT  52.866 36.576 53.064 36.588 ;
     RECT  53.082 36.576 53.316 36.588 ;
     RECT  53.334 36.576 53.568 36.588 ;
     RECT  53.586 36.576 53.82 36.588 ;
     RECT  53.838 36.576 54.072 36.588 ;
     RECT  54.09 36.576 54.288 36.588 ;
     RECT  54.306 36.576 54.54 36.588 ;
     RECT  54.558 36.576 54.792 36.588 ;
     RECT  54.81 36.576 55.044 36.588 ;
     RECT  55.062 36.576 55.296 36.588 ;
     RECT  55.314 36.576 55.512 36.588 ;
     RECT  55.53 36.576 55.764 36.588 ;
     RECT  55.782 36.576 56.016 36.588 ;
     RECT  56.034 36.576 56.268 36.588 ;
     RECT  56.286 36.576 56.52 36.588 ;
     RECT  56.538 36.576 56.736 36.588 ;
     RECT  56.754 36.576 56.988 36.588 ;
     RECT  57.006 36.576 57.24 36.588 ;
     RECT  57.258 36.576 57.492 36.588 ;
     RECT  57.51 36.576 57.744 36.588 ;
     RECT  57.762 36.576 57.96 36.588 ;
     RECT  57.978 36.576 58.212 36.588 ;
     RECT  58.23 36.576 58.464 36.588 ;
     RECT  58.482 36.576 58.716 36.588 ;
     RECT  58.734 36.576 58.932 36.588 ;
     RECT  58.95 36.576 59.184 36.588 ;
     RECT  59.202 36.576 59.436 36.588 ;
     RECT  59.454 36.576 59.688 36.588 ;
     RECT  59.706 36.576 59.94 36.588 ;
     RECT  59.958 36.576 60.156 36.588 ;
     RECT  60.174 36.576 60.408 36.588 ;
     RECT  60.426 36.576 60.66 36.588 ;
     RECT  60.678 36.576 60.912 36.588 ;
     RECT  60.93 36.576 61.164 36.588 ;
     RECT  61.182 36.576 61.38 36.588 ;
     RECT  61.398 36.576 61.632 36.588 ;
     RECT  61.65 36.576 61.884 36.588 ;
     RECT  61.902 36.576 62.136 36.588 ;
     RECT  62.154 36.576 62.388 36.588 ;
     RECT  62.406 36.576 62.604 36.588 ;
     RECT  62.622 36.576 62.856 36.588 ;
     RECT  62.874 36.576 63.108 36.588 ;
     RECT  63.126 36.576 63.36 36.588 ;
     RECT  63.378 36.576 63.612 36.588 ;
     RECT  63.63 36.576 63.828 36.588 ;
     RECT  63.846 36.576 64.08 36.588 ;
     RECT  64.098 36.576 64.332 36.588 ;
     RECT  64.35 36.576 64.584 36.588 ;
     RECT  64.602 36.576 64.836 36.588 ;
     RECT  64.854 36.576 65.052 36.588 ;
     RECT  65.07 36.576 65.304 36.588 ;
     RECT  65.322 36.576 65.556 36.588 ;
     RECT  65.574 36.576 65.808 36.588 ;
     RECT  65.826 36.576 66.06 36.588 ;
     RECT  66.078 36.576 66.276 36.588 ;
     RECT  66.294 36.576 66.528 36.588 ;
     RECT  66.546 36.576 66.78 36.588 ;
     RECT  66.798 36.576 67.032 36.588 ;
     RECT  67.05 36.576 67.284 36.588 ;
     RECT  67.302 36.576 67.5 36.588 ;
     RECT  67.518 36.576 67.752 36.588 ;
     RECT  67.77 36.576 68.004 36.588 ;
     RECT  68.022 36.576 68.256 36.588 ;
     RECT  68.274 36.576 68.508 36.588 ;
     RECT  68.526 36.576 68.724 36.588 ;
     RECT  68.742 36.576 68.976 36.588 ;
     RECT  68.994 36.576 69.228 36.588 ;
     RECT  69.246 36.576 69.48 36.588 ;
     RECT  69.498 36.576 69.732 36.588 ;
     RECT  69.75 36.576 69.948 36.588 ;
     RECT  69.966 36.576 70.2 36.588 ;
     RECT  70.218 36.576 70.452 36.588 ;
     RECT  70.47 36.576 70.704 36.588 ;
     RECT  70.722 36.576 70.956 36.588 ;
     RECT  70.974 36.576 71.172 36.588 ;
     RECT  71.19 36.576 71.424 36.588 ;
     RECT  71.442 36.576 71.676 36.588 ;
     RECT  71.694 36.576 71.928 36.588 ;
     RECT  71.946 36.576 72.18 36.588 ;
     RECT  72.198 36.576 72.396 36.588 ;
     RECT  72.414 36.576 72.648 36.588 ;
     RECT  72.666 36.576 72.9 36.588 ;
     RECT  72.918 36.576 73.152 36.588 ;
     RECT  73.17 36.576 73.404 36.588 ;
     RECT  73.422 36.576 73.62 36.588 ;
     RECT  73.638 36.576 73.872 36.588 ;
     RECT  73.89 36.576 74.124 36.588 ;
     RECT  74.142 36.576 74.376 36.588 ;
     RECT  74.394 36.576 74.628 36.588 ;
     RECT  74.646 36.576 74.844 36.588 ;
     RECT  74.862 36.576 75.096 36.588 ;
     RECT  75.114 36.576 75.348 36.588 ;
     RECT  75.366 36.576 75.6 36.588 ;
     RECT  75.618 36.576 75.852 36.588 ;
     RECT  75.87 36.576 76.068 36.588 ;
     RECT  76.086 36.576 76.32 36.588 ;
     RECT  76.338 36.576 76.572 36.588 ;
     RECT  76.59 36.576 76.824 36.588 ;
     RECT  76.842 36.576 77.076 36.588 ;
     RECT  77.094 36.576 77.292 36.588 ;
     RECT  77.31 36.576 77.544 36.588 ;
     RECT  77.562 36.576 77.796 36.588 ;
     RECT  77.814 36.576 78.048 36.588 ;
     RECT  78.066 36.576 78.3 36.588 ;
     RECT  78.318 36.576 78.516 36.588 ;
     RECT  78.534 36.576 78.768 36.588 ;
     RECT  78.786 36.576 79.02 36.588 ;
     RECT  79.038 36.576 79.272 36.588 ;
     RECT  79.29 36.576 79.524 36.588 ;
     RECT  79.542 36.576 79.74 36.588 ;
     RECT  79.758 36.576 79.992 36.588 ;
     RECT  80.01 36.576 80.244 36.588 ;
     RECT  80.262 36.576 80.496 36.588 ;
     RECT  80.514 36.576 80.748 36.588 ;
     RECT  80.766 36.576 80.964 36.588 ;
     RECT  80.982 36.576 81.216 36.588 ;
     RECT  81.234 36.576 81.468 36.588 ;
     RECT  81.486 36.576 81.72 36.588 ;
     RECT  81.738 36.576 81.972 36.588 ;
     RECT  81.99 36.576 82.188 36.588 ;
     RECT  82.206 36.576 82.44 36.588 ;
     RECT  82.458 36.576 82.692 36.588 ;
     RECT  82.71 36.576 82.944 36.588 ;
     RECT  82.962 36.576 83.196 36.588 ;
     RECT  83.214 36.576 83.412 36.588 ;
     RECT  83.43 36.576 83.664 36.588 ;
     RECT  83.682 36.576 83.916 36.588 ;
     RECT  83.934 36.576 84.168 36.588 ;
     RECT  84.186 36.576 84.42 36.588 ;
     RECT  84.438 36.576 84.636 36.588 ;
     RECT  84.654 36.576 84.888 36.588 ;
     RECT  84.906 36.576 85.14 36.588 ;
     RECT  85.158 36.576 85.392 36.588 ;
     RECT  85.41 36.576 85.644 36.588 ;
     RECT  85.662 36.576 85.86 36.588 ;
     RECT  85.878 36.576 86.112 36.588 ;
     RECT  86.13 36.576 86.364 36.588 ;
     RECT  86.382 36.576 86.616 36.588 ;
     RECT  86.634 36.576 86.868 36.588 ;
     RECT  86.886 36.576 87.084 36.588 ;
     RECT  87.102 36.576 87.336 36.588 ;
     RECT  87.354 36.576 87.588 36.588 ;
     RECT  87.606 36.576 87.84 36.588 ;
     RECT  87.858 36.576 88.092 36.588 ;
     RECT  88.11 36.576 88.308 36.588 ;
     RECT  88.326 36.576 88.56 36.588 ;
     RECT  88.578 36.576 88.812 36.588 ;
     RECT  88.83 36.576 89.064 36.588 ;
     RECT  89.082 36.576 89.316 36.588 ;
     RECT  89.334 36.576 89.532 36.588 ;
     RECT  89.55 36.576 89.784 36.588 ;
     RECT  89.802 36.576 90.036 36.588 ;
     RECT  90.054 36.576 90.288 36.588 ;
     RECT  90.306 36.576 90.504 36.588 ;
     RECT  90.522 36.576 90.756 36.588 ;
     RECT  90.774 36.576 91.008 36.588 ;
     RECT  91.026 36.576 91.26 36.588 ;
     RECT  91.278 36.576 91.512 36.588 ;
     RECT  91.53 36.576 91.728 36.588 ;
     RECT  91.746 36.576 91.98 36.588 ;
     RECT  91.998 36.576 92.232 36.588 ;
     RECT  92.25 36.576 92.484 36.588 ;
     RECT  92.502 36.576 92.736 36.588 ;
     RECT  92.754 36.576 92.952 36.588 ;
     RECT  92.97 36.576 93.204 36.588 ;
     RECT  93.222 36.576 93.456 36.588 ;
     RECT  93.474 36.576 93.708 36.588 ;
     RECT  93.726 36.576 93.96 36.588 ;
     RECT  93.978 36.576 94.176 36.588 ;
     RECT  94.194 36.576 94.428 36.588 ;
     RECT  94.446 36.576 94.68 36.588 ;
     RECT  94.698 36.576 94.932 36.588 ;
     RECT  94.95 36.576 95.184 36.588 ;
     RECT  95.202 36.576 95.4 36.588 ;
     RECT  95.418 36.576 95.652 36.588 ;
     RECT  95.67 36.576 95.904 36.588 ;
     RECT  95.922 36.576 96.156 36.588 ;
     RECT  96.174 36.576 96.408 36.588 ;
     RECT  96.426 36.576 96.624 36.588 ;
     RECT  96.642 36.576 96.876 36.588 ;
     RECT  96.894 36.576 97.128 36.588 ;
     RECT  26.676 36.588 26.766 36.653 ;
     RECT  29.484 36.588 29.574 36.653 ;
     RECT  42.84 36.588 42.93 36.653 ;
     RECT  46.98 36.588 47.07 36.653 ;
     RECT  51.408 36.588 51.498 36.653 ;
     RECT  53.856 36.588 53.946 36.653 ;
     RECT  60.3 36.588 60.39 36.653 ;
     RECT  62.172 36.588 62.262 36.653 ;
     RECT  67.068 36.588 67.158 36.653 ;
     RECT  78.804 36.588 78.894 36.653 ;
     RECT  81.36 36.588 81.45 36.653 ;
     RECT  96.192 36.588 96.282 36.653 ;
    LAYER M4 ;
     RECT  0.229 6.576 2.408 6.6 ;
     RECT  2.408 2.148 2.512 34.572 ;
     RECT  2.512 2.418 2.704 34.302 ;
     RECT  4.489 0.192 4.787 0.216 ;
     RECT  4.129 4.656 4.813 4.68 ;
     RECT  4.381 1.728 4.885 1.752 ;
     RECT  4.885 1.728 5.065 2.28 ;
     RECT  5.065 1.104 5.108 2.28 ;
     RECT  2.704 3.408 5.108 3.432 ;
     RECT  4.813 4.416 5.108 4.68 ;
     RECT  2.704 6.576 5.108 6.6 ;
     RECT  4.501 28.32 5.108 28.344 ;
     RECT  4.981 29.616 5.108 29.64 ;
     RECT  4.741 31.872 5.108 31.896 ;
     RECT  5.108 1.104 5.221 34.572 ;
     RECT  5.221 1.104 5.404 34.728 ;
     RECT  5.404 34.704 5.461 34.728 ;
     RECT  5.461 34.704 5.555 34.824 ;
     RECT  5.404 31.872 5.681 31.896 ;
     RECT  5.555 34.8 5.717 34.824 ;
     RECT  5.404 1.104 5.747 1.752 ;
     RECT  5.404 3.408 6.005 5.112 ;
     RECT  6.005 3.696 6.035 5.112 ;
     RECT  5.404 27.888 6.329 28.44 ;
     RECT  6.329 28.032 6.421 28.44 ;
     RECT  5.747 1.728 6.661 1.752 ;
     RECT  6.661 1.728 6.761 1.8 ;
     RECT  6.661 34.224 6.797 34.248 ;
     RECT  6.035 4.416 7.333 5.112 ;
     RECT  5.404 6.576 7.333 6.6 ;
     RECT  7.153 0.528 7.405 0.552 ;
     RECT  6.761 1.728 7.405 1.752 ;
     RECT  6.421 28.032 7.429 28.872 ;
     RECT  7.405 0.528 7.489 1.752 ;
     RECT  7.429 28.032 7.549 28.968 ;
     RECT  7.489 0.528 7.715 0.552 ;
     RECT  7.333 4.416 7.808 6.6 ;
     RECT  7.549 27.744 7.808 28.968 ;
     RECT  7.669 33.264 7.808 33.288 ;
     RECT  7.621 34.704 7.808 34.728 ;
     RECT  7.808 2.016 7.955 34.728 ;
     RECT  7.955 2.016 8.104 34.68 ;
     RECT  8.104 4.416 8.165 6.6 ;
     RECT  8.104 27.888 8.165 28.968 ;
     RECT  8.104 34.56 8.237 34.68 ;
     RECT  8.237 34.56 8.281 34.584 ;
     RECT  8.149 0.192 8.291 0.216 ;
     RECT  8.104 2.88 8.309 3.432 ;
     RECT  8.309 2.88 8.525 2.904 ;
     RECT  8.165 27.888 8.597 28.488 ;
     RECT  8.165 4.896 9.529 6.6 ;
     RECT  9.877 35.328 9.965 35.352 ;
     RECT  8.597 27.936 10.117 28.488 ;
     RECT  10.213 2.784 10.357 2.808 ;
     RECT  8.629 1.728 10.508 1.8 ;
     RECT  10.357 2.784 10.508 2.904 ;
     RECT  9.529 4.896 10.508 6.696 ;
     RECT  10.117 27.936 10.508 28.872 ;
     RECT  10.357 30.864 10.508 30.888 ;
     RECT  10.309 34.704 10.508 34.728 ;
     RECT  10.508 1.728 10.643 34.728 ;
     RECT  10.643 1.728 10.804 34.68 ;
     RECT  10.804 2.88 10.865 2.904 ;
     RECT  10.804 34.56 10.924 34.68 ;
     RECT  10.924 34.56 10.945 34.584 ;
     RECT  10.804 4.128 11.261 6.888 ;
     RECT  10.804 1.728 11.405 1.8 ;
     RECT  10.804 27.936 11.405 28.488 ;
     RECT  10.804 30.864 11.585 30.888 ;
     RECT  11.261 4.128 11.765 6.696 ;
     RECT  10.804 33.024 11.837 33.048 ;
     RECT  11.405 28.32 11.909 28.488 ;
     RECT  11.765 4.128 12.229 6.6 ;
     RECT  12.325 35.904 12.449 35.928 ;
     RECT  12.229 3.984 12.877 6.6 ;
     RECT  11.909 28.416 13.045 28.488 ;
     RECT  13.045 2.976 13.093 3 ;
     RECT  12.877 3.984 13.093 6.888 ;
     RECT  11.405 1.728 13.208 1.752 ;
     RECT  13.093 2.976 13.208 6.888 ;
     RECT  13.045 27.936 13.208 28.488 ;
     RECT  12.565 35.328 13.208 35.352 ;
     RECT  13.208 1.728 13.504 35.352 ;
     RECT  13.093 0.288 13.525 0.312 ;
     RECT  13.504 34.8 13.619 35.352 ;
     RECT  13.504 1.728 13.645 3.48 ;
     RECT  13.525 0.192 13.667 0.312 ;
     RECT  13.619 34.896 13.667 35.352 ;
     RECT  13.645 1.728 13.673 3.384 ;
     RECT  13.504 18.672 13.673 18.696 ;
     RECT  13.504 4.992 13.715 7.368 ;
     RECT  13.504 28.32 13.745 28.488 ;
     RECT  13.673 1.728 13.825 2.328 ;
     RECT  13.745 28.416 13.853 28.488 ;
     RECT  13.673 3.36 13.997 3.384 ;
     RECT  13.667 35.328 14.249 35.352 ;
     RECT  13.825 1.728 14.252 1.752 ;
     RECT  14.252 1.104 14.339 1.752 ;
     RECT  14.293 35.904 14.533 35.928 ;
     RECT  14.533 35.904 14.645 35.976 ;
     RECT  13.715 5.088 14.773 7.368 ;
     RECT  14.645 35.952 14.861 35.976 ;
     RECT  14.773 4.8 14.929 7.368 ;
     RECT  13.853 28.464 15.013 28.488 ;
     RECT  15.013 28.416 15.253 28.488 ;
     RECT  14.339 1.728 15.293 1.752 ;
     RECT  14.929 4.704 15.461 7.368 ;
     RECT  15.461 4.512 15.493 7.368 ;
     RECT  15.253 28.368 15.493 28.488 ;
     RECT  15.253 2.88 15.733 2.904 ;
     RECT  15.493 28.368 15.733 28.872 ;
     RECT  15.733 2.88 15.908 3.432 ;
     RECT  15.493 4.416 15.908 7.368 ;
     RECT  15.733 27.888 15.908 28.872 ;
     RECT  15.908 2.148 16.012 34.572 ;
     RECT  16.012 2.148 16.204 34.302 ;
     RECT  15.973 0.192 16.213 0.216 ;
     RECT  15.973 35.904 16.213 35.928 ;
     RECT  16.213 0.192 16.355 0.312 ;
     RECT  16.355 0.288 16.403 0.312 ;
     RECT  16.204 3.408 16.403 6.84 ;
     RECT  16.213 35.904 16.453 35.976 ;
     RECT  16.403 3.408 16.517 3.48 ;
     RECT  16.403 4.512 16.553 6.84 ;
     RECT  16.204 2.148 16.693 2.328 ;
     RECT  16.693 1.776 16.721 2.328 ;
     RECT  16.517 3.408 16.733 3.432 ;
     RECT  16.453 35.904 16.733 36.024 ;
     RECT  16.204 27.888 17.129 28.488 ;
     RECT  16.721 1.728 17.267 2.328 ;
     RECT  16.553 4.512 17.564 6.6 ;
     RECT  16.733 35.904 18.137 35.976 ;
     RECT  17.441 2.88 18.421 2.904 ;
     RECT  18.421 2.88 18.469 3.048 ;
     RECT  17.564 4.512 18.469 7.32 ;
     RECT  17.129 28.32 18.469 28.488 ;
     RECT  17.267 1.728 18.529 1.8 ;
     RECT  18.469 2.784 18.529 3.048 ;
     RECT  18.529 1.728 18.608 3.048 ;
     RECT  18.469 4.128 18.608 7.32 ;
     RECT  17.989 18.432 18.608 18.456 ;
     RECT  18.277 19.584 18.608 19.608 ;
     RECT  18.469 27.888 18.608 28.488 ;
     RECT  17.941 33.024 18.608 33.048 ;
     RECT  18.469 34.8 18.608 34.824 ;
     RECT  18.608 1.728 18.707 34.824 ;
     RECT  18.707 1.728 18.712 34.572 ;
     RECT  18.712 1.728 18.904 34.302 ;
     RECT  18.904 18.816 19.037 19.08 ;
     RECT  18.904 27.888 19.073 29.064 ;
     RECT  19.037 18.816 19.145 18.84 ;
     RECT  18.904 1.728 19.475 6.888 ;
     RECT  19.475 1.728 19.541 2.904 ;
     RECT  19.073 28.32 19.721 29.064 ;
     RECT  19.475 4.224 19.865 6.888 ;
     RECT  18.137 35.904 20.149 35.928 ;
     RECT  19.865 5.472 20.329 6.888 ;
     RECT  20.149 35.904 20.405 35.976 ;
     RECT  19.541 1.728 20.629 1.752 ;
     RECT  19.541 2.88 20.629 2.904 ;
     RECT  20.405 35.904 20.629 35.928 ;
     RECT  20.629 1.728 20.869 2.904 ;
     RECT  20.629 35.328 20.909 35.928 ;
     RECT  19.721 28.32 21.109 28.344 ;
     RECT  20.869 1.68 21.155 2.904 ;
     RECT  21.155 1.728 21.157 2.904 ;
     RECT  19.865 4.224 21.157 4.248 ;
     RECT  20.329 5.472 21.157 7.128 ;
     RECT  21.157 1.728 21.308 7.128 ;
     RECT  21.109 27.888 21.308 28.344 ;
     RECT  21.157 34.8 21.308 34.824 ;
     RECT  21.157 0.288 21.395 0.312 ;
     RECT  21.308 1.728 21.604 34.824 ;
     RECT  21.604 34.8 21.635 34.824 ;
     RECT  21.604 1.728 21.665 6.84 ;
     RECT  21.604 27.888 21.989 28.488 ;
     RECT  21.989 28.272 22.025 28.488 ;
     RECT  20.909 35.904 22.597 35.928 ;
     RECT  22.46 0.144 22.787 0.168 ;
     RECT  22.597 35.904 22.837 35.976 ;
     RECT  22.025 28.416 23.029 28.488 ;
     RECT  23.029 27.984 23.077 28.488 ;
     RECT  22.837 35.328 23.357 35.976 ;
     RECT  21.665 1.728 23.365 6.6 ;
     RECT  23.357 35.328 23.717 35.352 ;
     RECT  23.077 27.984 23.797 28.872 ;
     RECT  23.365 1.728 23.933 7.464 ;
     RECT  23.933 2.016 24.008 7.464 ;
     RECT  23.797 27.888 24.008 28.872 ;
     RECT  24.008 2.016 24.185 34.92 ;
     RECT  24.185 2.256 24.304 34.92 ;
     RECT  24.181 0.144 24.325 0.168 ;
     RECT  24.304 34.8 24.419 34.92 ;
     RECT  24.304 10.8 24.437 11.64 ;
     RECT  24.437 11.616 24.445 11.64 ;
     RECT  24.325 0.144 24.467 0.264 ;
     RECT  24.419 34.896 24.467 34.92 ;
     RECT  24.467 0.192 24.707 0.264 ;
     RECT  24.707 0.24 24.761 0.264 ;
     RECT  24.304 2.256 25.285 7.416 ;
     RECT  24.304 31.296 25.409 31.32 ;
     RECT  24.304 28.416 25.481 29.064 ;
     RECT  25.285 1.728 25.532 7.416 ;
     RECT  25.481 28.416 25.765 28.968 ;
     RECT  24.565 35.904 25.805 35.928 ;
     RECT  25.765 28.32 26.005 28.968 ;
     RECT  25.957 0.528 26.201 0.552 ;
     RECT  25.532 1.728 26.269 7.608 ;
     RECT  26.269 1.728 26.708 7.992 ;
     RECT  26.005 27.888 26.708 28.968 ;
     RECT  26.485 31.2 26.708 31.224 ;
     RECT  26.708 1.728 26.773 34.572 ;
     RECT  26.773 1.728 26.812 35.352 ;
     RECT  26.812 1.728 27.004 34.302 ;
     RECT  26.812 35.328 27.013 35.352 ;
     RECT  27.013 0.192 27.155 0.216 ;
     RECT  27.004 9.12 27.173 9.144 ;
     RECT  27.004 1.728 27.251 7.656 ;
     RECT  27.004 31.2 27.389 31.224 ;
     RECT  27.013 35.328 27.749 35.928 ;
     RECT  27.749 35.904 27.965 35.928 ;
     RECT  27.004 28.464 27.973 28.488 ;
     RECT  27.251 1.728 28.316 5.208 ;
     RECT  27.251 6.288 28.316 7.656 ;
     RECT  28.316 1.728 28.961 7.656 ;
     RECT  28.249 18.672 29.185 18.696 ;
     RECT  28.556 0.144 29.269 0.168 ;
     RECT  29.269 0.144 29.369 0.552 ;
     RECT  28.961 1.728 29.408 7.992 ;
     RECT  29.149 10.8 29.408 10.824 ;
     RECT  29.185 18.672 29.408 18.84 ;
     RECT  27.973 27.792 29.408 28.488 ;
     RECT  29.269 34.8 29.408 34.824 ;
     RECT  29.408 1.728 29.704 34.824 ;
     RECT  29.369 0.144 29.843 0.168 ;
     RECT  29.704 34.8 29.843 34.824 ;
     RECT  29.704 28.272 30.017 28.872 ;
     RECT  29.704 18.768 30.161 18.792 ;
     RECT  29.704 1.728 30.413 7.992 ;
     RECT  29.941 35.904 30.421 35.928 ;
     RECT  30.413 1.728 30.521 7.656 ;
     RECT  30.521 1.728 30.845 7.512 ;
     RECT  30.421 35.904 30.953 35.976 ;
     RECT  30.017 28.32 31.133 28.872 ;
     RECT  31.133 28.32 31.381 28.488 ;
     RECT  30.953 35.904 31.385 35.928 ;
     RECT  30.845 1.728 31.909 7.128 ;
     RECT  31.909 1.728 31.957 7.992 ;
     RECT  31.957 1.152 32.108 7.992 ;
     RECT  31.381 27.888 32.108 28.488 ;
     RECT  31.909 35.328 32.108 35.4 ;
     RECT  32.108 1.152 32.195 35.4 ;
     RECT  32.195 1.728 32.212 35.4 ;
     RECT  32.212 35.328 32.389 35.4 ;
     RECT  32.212 1.728 32.404 34.302 ;
     RECT  32.404 7.968 32.465 7.992 ;
     RECT  32.492 0.144 32.579 0.168 ;
     RECT  32.404 27.888 32.645 28.488 ;
     RECT  32.389 35.328 33.041 35.928 ;
     RECT  32.404 1.728 33.445 6.792 ;
     RECT  32.404 31.296 33.589 31.32 ;
     RECT  33.445 1.728 33.613 7.128 ;
     RECT  33.589 31.248 33.725 31.32 ;
     RECT  33.041 35.904 33.725 35.928 ;
     RECT  33.685 14.832 33.797 14.856 ;
     RECT  33.613 1.728 33.973 7.464 ;
     RECT  33.541 8.544 33.973 8.568 ;
     RECT  32.645 28.464 34.117 28.488 ;
     RECT  33.973 1.728 34.403 8.568 ;
     RECT  34.403 2.148 34.808 8.568 ;
     RECT  34.081 10.848 34.808 10.872 ;
     RECT  34.117 28.416 34.808 28.488 ;
     RECT  33.725 31.248 34.808 31.272 ;
     RECT  34.357 35.328 34.808 35.352 ;
     RECT  33.932 0.144 34.837 0.168 ;
     RECT  34.808 2.148 35.104 35.352 ;
     RECT  35.104 2.148 35.219 6.84 ;
     RECT  35.104 34.8 35.219 35.352 ;
     RECT  35.219 35.328 35.273 35.352 ;
     RECT  35.219 2.148 35.549 2.904 ;
     RECT  34.837 0.144 35.555 0.312 ;
     RECT  35.317 35.376 35.597 35.4 ;
     RECT  35.555 0.144 35.987 0.168 ;
     RECT  35.219 3.936 36.083 6.84 ;
     RECT  35.104 28.464 36.565 28.488 ;
     RECT  35.549 1.728 36.893 2.904 ;
     RECT  36.893 2.148 37.045 2.904 ;
     RECT  35.797 35.904 37.045 35.928 ;
     RECT  37.045 2.148 37.285 2.952 ;
     RECT  36.083 3.936 37.285 6.6 ;
     RECT  37.045 35.328 37.381 35.928 ;
     RECT  37.381 34.8 37.397 35.928 ;
     RECT  37.285 2.148 37.508 6.6 ;
     RECT  35.104 7.968 37.508 7.992 ;
     RECT  36.565 28.32 37.508 28.488 ;
     RECT  35.104 33.024 37.508 33.048 ;
     RECT  37.397 34.8 37.508 34.824 ;
     RECT  37.508 2.148 37.571 34.824 ;
     RECT  37.571 2.148 37.612 34.572 ;
     RECT  37.612 2.148 37.804 34.302 ;
     RECT  37.381 0.192 37.955 0.216 ;
     RECT  37.804 2.784 37.955 6.6 ;
     RECT  37.397 35.904 38.005 35.928 ;
     RECT  37.955 3.936 38.189 6.6 ;
     RECT  38.005 35.904 38.225 35.976 ;
     RECT  38.225 35.952 38.245 35.976 ;
     RECT  38.245 35.952 38.405 36.024 ;
     RECT  38.245 1.728 38.833 1.752 ;
     RECT  37.955 2.784 38.833 2.952 ;
     RECT  38.405 36 38.981 36.024 ;
     RECT  38.833 1.728 39.164 2.952 ;
     RECT  38.189 3.984 39.164 6.6 ;
     RECT  39.164 1.728 39.205 6.6 ;
     RECT  39.949 18.768 39.985 18.792 ;
     RECT  39.973 35.904 40.097 35.928 ;
     RECT  39.841 0.144 40.115 0.168 ;
     RECT  39.205 1.728 40.208 6.888 ;
     RECT  39.985 18.576 40.208 18.792 ;
     RECT  37.804 28.416 40.208 29.064 ;
     RECT  39.253 31.296 40.208 31.32 ;
     RECT  40.129 35.328 40.208 35.352 ;
     RECT  40.208 1.728 40.504 35.352 ;
     RECT  40.453 0.192 40.643 0.216 ;
     RECT  40.504 5.04 40.643 6.888 ;
     RECT  40.504 34.8 40.643 35.352 ;
     RECT  40.643 5.04 40.853 6.6 ;
     RECT  40.504 1.728 41.501 4.008 ;
     RECT  41.501 3.984 41.557 4.008 ;
     RECT  41.501 1.728 41.603 2.952 ;
     RECT  40.504 28.32 41.701 28.44 ;
     RECT  41.603 1.728 41.897 1.752 ;
     RECT  41.557 3.984 41.929 4.104 ;
     RECT  40.853 5.136 41.929 6.6 ;
     RECT  41.603 2.88 42.661 2.952 ;
     RECT  41.701 28.32 42.661 28.488 ;
     RECT  42.661 2.304 42.757 2.952 ;
     RECT  41.929 3.984 42.757 6.6 ;
     RECT  40.643 35.328 42.901 35.352 ;
     RECT  42.757 2.304 42.908 6.6 ;
     RECT  42.829 9.072 42.908 9.096 ;
     RECT  42.793 18.768 42.908 18.792 ;
     RECT  42.661 28.32 42.908 28.872 ;
     RECT  42.901 34.8 42.908 35.352 ;
     RECT  42.908 2.148 43.141 35.352 ;
     RECT  43.141 2.148 43.204 35.928 ;
     RECT  42.181 0.192 43.331 0.216 ;
     RECT  43.204 2.148 43.331 3.048 ;
     RECT  43.204 4.224 43.331 7.56 ;
     RECT  43.204 10.32 43.331 10.344 ;
     RECT  43.204 34.8 43.331 35.928 ;
     RECT  43.204 28.32 43.373 28.44 ;
     RECT  43.331 2.148 43.381 2.328 ;
     RECT  43.331 35.328 43.589 35.928 ;
     RECT  43.331 4.224 43.661 6.792 ;
     RECT  43.204 18.816 43.697 19.272 ;
     RECT  43.373 28.416 44.389 28.44 ;
     RECT  43.589 35.904 44.417 35.928 ;
     RECT  43.697 19.248 44.633 19.272 ;
     RECT  43.381 1.728 44.732 2.328 ;
     RECT  44.341 0.528 44.777 0.552 ;
     RECT  44.732 1.728 45.097 2.76 ;
     RECT  44.389 28.416 45.109 28.488 ;
     RECT  45.097 1.728 45.349 3.432 ;
     RECT  43.661 4.512 45.349 6.792 ;
     RECT  45.349 1.728 45.445 6.792 ;
     RECT  45.313 7.968 45.445 7.992 ;
     RECT  45.452 0.144 45.539 0.168 ;
     RECT  45.445 1.728 45.608 6.84 ;
     RECT  45.445 7.968 45.608 8.568 ;
     RECT  45.109 27.888 45.608 28.488 ;
     RECT  44.629 31.2 45.608 31.224 ;
     RECT  45.589 34.8 45.608 34.824 ;
     RECT  45.608 1.728 45.829 34.824 ;
     RECT  45.829 1.728 45.904 34.872 ;
     RECT  45.904 34.8 46.019 34.872 ;
     RECT  45.904 28.32 46.253 28.44 ;
     RECT  46.069 35.904 46.309 35.928 ;
     RECT  45.829 0.192 46.549 0.216 ;
     RECT  46.019 34.848 46.721 34.872 ;
     RECT  46.549 0.192 46.757 0.552 ;
     RECT  46.309 35.904 46.837 36.024 ;
     RECT  46.253 28.416 46.901 28.44 ;
     RECT  46.892 0.144 46.979 0.168 ;
     RECT  46.837 35.904 47.153 36.072 ;
     RECT  47.153 35.904 47.189 35.976 ;
     RECT  45.904 1.728 47.473 7.08 ;
     RECT  47.317 27.312 47.557 27.336 ;
     RECT  47.473 1.728 47.801 7.464 ;
     RECT  47.189 35.904 47.873 35.928 ;
     RECT  47.557 27.312 48.037 28.296 ;
     RECT  48.133 0.24 48.14 0.264 ;
     RECT  48.14 0.144 48.227 0.264 ;
     RECT  47.801 1.824 48.308 7.464 ;
     RECT  45.904 8.544 48.308 8.568 ;
     RECT  48.037 27.312 48.308 28.824 ;
     RECT  48.229 35.328 48.308 35.352 ;
     RECT  48.308 1.824 48.412 35.352 ;
     RECT  48.412 1.824 48.449 34.302 ;
     RECT  48.449 2.256 48.604 34.302 ;
     RECT  48.227 0.192 48.661 0.264 ;
     RECT  48.661 0.192 48.755 0.312 ;
     RECT  48.604 8.544 48.803 8.568 ;
     RECT  48.604 2.256 48.853 6.888 ;
     RECT  48.755 0.192 48.947 0.216 ;
     RECT  48.853 2.256 48.995 3.432 ;
     RECT  48.412 35.328 49.045 35.352 ;
     RECT  48.853 4.416 49.061 6.888 ;
     RECT  49.045 35.328 49.285 35.928 ;
     RECT  49.285 35.328 49.709 35.976 ;
     RECT  48.995 2.496 49.811 3.432 ;
     RECT  49.811 2.496 49.817 3.336 ;
     RECT  48.604 28.32 49.817 28.44 ;
     RECT  49.061 4.416 49.889 6.84 ;
     RECT  49.889 4.416 49.997 6.696 ;
     RECT  49.817 2.832 50.821 3.336 ;
     RECT  49.997 4.416 50.821 6.6 ;
     RECT  50.821 0.288 50.869 0.312 ;
     RECT  50.245 28.464 50.869 28.488 ;
     RECT  49.709 35.328 50.869 35.928 ;
     RECT  50.101 1.728 51.008 1.752 ;
     RECT  50.821 2.832 51.008 6.6 ;
     RECT  50.281 7.968 51.008 7.992 ;
     RECT  50.869 28.416 51.008 28.488 ;
     RECT  50.485 33.024 51.008 33.048 ;
     RECT  50.869 34.8 51.008 35.928 ;
     RECT  50.869 0.192 51.011 0.312 ;
     RECT  51.008 1.728 51.112 35.928 ;
     RECT  51.112 35.328 51.185 35.928 ;
     RECT  51.011 0.288 51.251 0.312 ;
     RECT  51.112 1.728 51.304 34.302 ;
     RECT  51.304 33.024 51.689 33.048 ;
     RECT  51.304 1.728 52.373 1.8 ;
     RECT  52.373 1.728 52.453 1.752 ;
     RECT  51.185 35.904 52.453 35.928 ;
     RECT  51.304 3.84 52.499 6.84 ;
     RECT  52.453 2.832 52.549 2.856 ;
     RECT  52.549 2.832 52.589 3.432 ;
     RECT  52.453 1.152 52.595 1.752 ;
     RECT  52.453 35.904 52.661 35.976 ;
     RECT  52.661 35.952 52.693 35.976 ;
     RECT  52.499 4.656 53.077 6.84 ;
     RECT  51.304 28.416 53.173 28.488 ;
     RECT  53.077 4.656 53.297 6.888 ;
     RECT  52.595 1.728 53.381 1.752 ;
     RECT  52.589 2.88 53.516 3.432 ;
     RECT  53.297 4.656 53.516 7.464 ;
     RECT  52.693 35.952 53.561 36.024 ;
     RECT  53.516 2.88 53.708 7.464 ;
     RECT  53.665 18.432 53.708 18.456 ;
     RECT  53.173 28.416 53.708 29.064 ;
     RECT  53.653 34.8 53.708 34.824 ;
     RECT  53.708 2.148 54.004 34.824 ;
     RECT  53.557 0.192 54.131 0.216 ;
     RECT  54.004 34.8 54.131 34.824 ;
     RECT  54.004 2.148 54.145 6.84 ;
     RECT  54.145 2.148 54.217 2.904 ;
     RECT  54.217 2.148 54.227 2.328 ;
     RECT  53.941 35.904 54.389 35.928 ;
     RECT  54.227 2.148 54.421 2.28 ;
     RECT  54.421 1.728 54.707 2.28 ;
     RECT  54.145 3.984 55.133 6.84 ;
     RECT  55.133 3.408 55.145 6.84 ;
     RECT  55.145 3.408 55.217 3.432 ;
     RECT  54.707 1.728 55.861 1.848 ;
     RECT  55.621 2.88 55.861 3.24 ;
     RECT  55.861 1.728 56.009 3.24 ;
     RECT  55.145 4.416 56.101 6.84 ;
     RECT  54.901 35.328 56.225 35.352 ;
     RECT  55.724 0.144 56.245 0.168 ;
     RECT  56.009 2.148 56.245 3.24 ;
     RECT  56.101 4.416 56.245 7.128 ;
     RECT  56.245 0.144 56.339 0.264 ;
     RECT  56.245 2.148 56.408 7.128 ;
     RECT  54.004 27.888 56.408 28.488 ;
     RECT  54.004 31.296 56.408 31.32 ;
     RECT  56.293 34.8 56.408 34.824 ;
     RECT  56.339 0.192 56.435 0.264 ;
     RECT  56.408 2.148 56.704 34.824 ;
     RECT  56.435 0.192 56.819 0.216 ;
     RECT  56.704 10.896 56.819 10.92 ;
     RECT  56.704 34.8 56.819 34.824 ;
     RECT  56.704 2.148 57.017 7.368 ;
     RECT  57.017 2.148 57.109 2.952 ;
     RECT  56.704 27.888 57.197 28.488 ;
     RECT  57.197 27.888 57.269 28.44 ;
     RECT  57.109 1.728 57.385 2.952 ;
     RECT  56.704 33.024 57.521 33.048 ;
     RECT  57.452 0.144 57.539 0.168 ;
     RECT  57.017 3.936 57.557 7.368 ;
     RECT  57.269 28.32 57.593 28.44 ;
     RECT  57.557 3.936 57.676 6.936 ;
     RECT  57.589 35.328 57.881 35.352 ;
     RECT  57.385 2.832 58.028 2.952 ;
     RECT  57.385 1.728 58.133 1.8 ;
     RECT  58.069 35.904 58.421 35.928 ;
     RECT  58.133 1.728 58.673 1.752 ;
     RECT  58.028 2.832 58.837 3.336 ;
     RECT  57.676 4.56 58.981 6.936 ;
     RECT  57.593 28.32 58.981 28.392 ;
     RECT  58.837 2.832 59.108 3.432 ;
     RECT  58.981 4.416 59.108 6.936 ;
     RECT  58.981 7.968 59.108 7.992 ;
     RECT  56.704 18.672 59.108 18.696 ;
     RECT  58.981 27.888 59.108 28.392 ;
     RECT  58.837 31.2 59.108 31.224 ;
     RECT  58.981 34.8 59.108 34.824 ;
     RECT  58.981 0.192 59.123 0.216 ;
     RECT  59.108 2.016 59.404 34.824 ;
     RECT  59.404 34.8 59.555 34.824 ;
     RECT  59.404 33.024 59.681 33.048 ;
     RECT  59.557 35.904 59.797 35.928 ;
     RECT  59.404 31.2 59.969 31.224 ;
     RECT  59.404 2.016 60.037 6.84 ;
     RECT  59.797 35.904 60.113 35.976 ;
     RECT  59.404 8.544 60.473 8.568 ;
     RECT  60.037 1.728 60.709 6.84 ;
     RECT  60.709 1.728 60.721 6.888 ;
     RECT  59.404 27.888 60.761 28.488 ;
     RECT  60.721 1.728 60.805 7.464 ;
     RECT  59.66 0.144 60.901 0.168 ;
     RECT  60.761 27.888 60.997 28.44 ;
     RECT  60.901 0.144 61.477 0.312 ;
     RECT  60.997 27.84 61.525 28.44 ;
     RECT  61.477 0.144 61.667 0.552 ;
     RECT  61.621 34.896 61.669 34.92 ;
     RECT  60.805 1.728 61.808 6.888 ;
     RECT  61.297 7.968 61.808 7.992 ;
     RECT  61.525 27.792 61.808 28.44 ;
     RECT  61.669 34.8 61.808 34.92 ;
     RECT  61.667 0.288 61.811 0.552 ;
     RECT  61.808 1.728 62.051 34.92 ;
     RECT  62.051 1.728 62.104 34.302 ;
     RECT  61.811 0.528 62.165 0.552 ;
     RECT  62.104 27.888 62.273 28.488 ;
     RECT  62.104 7.968 62.705 8.568 ;
     RECT  63.013 0.288 63.541 0.312 ;
     RECT  62.273 28.32 63.685 28.488 ;
     RECT  60.113 35.904 63.785 35.928 ;
     RECT  63.685 28.32 63.973 28.872 ;
     RECT  63.541 0.288 64.028 0.552 ;
     RECT  64.028 0.144 64.361 0.552 ;
     RECT  62.104 1.728 64.508 6.888 ;
     RECT  63.745 9.12 64.508 9.144 ;
     RECT  63.973 27.792 64.508 28.872 ;
     RECT  64.453 34.8 64.508 34.824 ;
     RECT  64.508 1.728 64.693 34.824 ;
     RECT  64.693 1.728 64.804 34.92 ;
     RECT  64.804 1.728 64.893 6.84 ;
     RECT  64.804 11.664 64.901 11.688 ;
     RECT  64.361 0.144 64.931 0.312 ;
     RECT  64.804 7.968 64.931 8.568 ;
     RECT  64.804 34.8 64.931 34.92 ;
     RECT  64.931 34.8 64.979 34.824 ;
     RECT  64.931 8.544 65.017 8.568 ;
     RECT  64.893 1.824 65.02 6.84 ;
     RECT  64.804 27.888 65.045 28.488 ;
     RECT  64.933 35.904 65.173 35.928 ;
     RECT  64.931 0.144 65.843 0.168 ;
     RECT  65.02 1.824 65.893 6.696 ;
     RECT  65.173 35.904 66.197 35.976 ;
     RECT  65.893 1.728 66.332 6.696 ;
     RECT  65.045 27.888 66.421 28.296 ;
     RECT  66.421 27.888 66.661 28.44 ;
     RECT  66.157 7.968 66.985 7.992 ;
     RECT  66.373 9.12 66.985 9.144 ;
     RECT  67.004 0.144 67.091 0.168 ;
     RECT  66.332 1.728 67.208 6.84 ;
     RECT  66.985 7.968 67.208 9.144 ;
     RECT  66.661 27.888 67.208 28.872 ;
     RECT  67.208 1.728 67.381 34.572 ;
     RECT  67.381 1.728 67.504 34.824 ;
     RECT  67.381 0.288 67.619 0.312 ;
     RECT  67.504 34.8 67.619 34.824 ;
     RECT  67.504 1.728 67.763 6.888 ;
     RECT  67.504 27.888 67.889 28.488 ;
     RECT  67.504 14.832 67.925 14.856 ;
     RECT  67.889 28.128 67.961 28.488 ;
     RECT  67.763 3.888 68.339 6.888 ;
     RECT  68.339 3.888 68.465 6.84 ;
     RECT  67.961 28.32 68.537 28.488 ;
     RECT  68.465 3.984 68.579 6.84 ;
     RECT  68.497 8.544 68.581 8.568 ;
     RECT  66.197 35.904 68.581 35.928 ;
     RECT  68.149 0.528 68.753 0.552 ;
     RECT  68.581 35.328 68.861 35.928 ;
     RECT  67.763 1.728 68.869 2.856 ;
     RECT  68.924 0.144 69.011 0.168 ;
     RECT  68.861 35.904 69.077 35.928 ;
     RECT  68.537 28.32 69.109 28.44 ;
     RECT  69.109 27.888 69.589 28.44 ;
     RECT  69.733 0.192 69.781 0.216 ;
     RECT  69.781 0.192 69.875 0.552 ;
     RECT  68.869 1.728 69.908 2.904 ;
     RECT  68.579 3.984 69.908 6.6 ;
     RECT  69.589 27.888 69.908 28.488 ;
     RECT  69.733 34.8 69.908 34.92 ;
     RECT  69.875 0.528 69.977 0.552 ;
     RECT  69.908 1.728 70.115 34.92 ;
     RECT  70.115 1.728 70.204 34.302 ;
     RECT  70.204 27.888 70.265 28.488 ;
     RECT  70.204 3.984 70.451 6.84 ;
     RECT  70.265 27.888 70.589 28.44 ;
     RECT  70.204 1.728 71.189 2.952 ;
     RECT  70.451 3.984 71.189 6.552 ;
     RECT  71.132 0.144 71.219 0.168 ;
     RECT  70.589 28.32 71.317 28.44 ;
     RECT  71.189 1.728 71.485 6.552 ;
     RECT  70.789 35.328 71.797 35.352 ;
     RECT  71.317 28.32 72.037 28.488 ;
     RECT  71.485 1.728 72.325 6.792 ;
     RECT  72.313 8.544 72.421 8.568 ;
     RECT  71.797 0.192 72.469 0.216 ;
     RECT  72.325 1.728 72.469 6.84 ;
     RECT  72.421 7.968 72.469 8.568 ;
     RECT  72.469 1.728 72.608 8.568 ;
     RECT  71.845 18.768 72.608 18.792 ;
     RECT  72.037 27.888 72.608 28.488 ;
     RECT  71.797 35.328 72.608 35.4 ;
     RECT  72.608 1.728 72.712 35.4 ;
     RECT  72.712 35.328 72.757 35.4 ;
     RECT  72.712 1.728 72.904 34.302 ;
     RECT  72.469 0.192 72.929 0.552 ;
     RECT  72.904 1.728 72.965 6.84 ;
     RECT  73.1 0.144 73.187 0.168 ;
     RECT  72.757 35.328 73.253 35.928 ;
     RECT  72.904 7.968 73.523 8.568 ;
     RECT  72.965 4.128 73.649 6.84 ;
     RECT  73.649 4.128 73.907 6.744 ;
     RECT  72.965 1.728 74.005 2.952 ;
     RECT  73.907 4.128 74.005 6.408 ;
     RECT  73.253 35.904 74.005 35.928 ;
     RECT  74.005 35.904 74.045 35.976 ;
     RECT  72.904 28.416 74.245 28.488 ;
     RECT  74.005 1.728 74.261 6.408 ;
     RECT  74.045 35.952 74.441 35.976 ;
     RECT  74.245 28.416 74.485 29.064 ;
     RECT  74.261 1.776 74.513 6.408 ;
     RECT  74.485 28.272 74.725 29.064 ;
     RECT  74.513 2.148 74.977 6.408 ;
     RECT  74.581 0.528 75.109 0.552 ;
     RECT  75.109 0.192 75.125 0.552 ;
     RECT  75.149 34.56 75.164 34.584 ;
     RECT  75.125 0.192 75.251 0.312 ;
     RECT  75.164 34.56 75.251 34.68 ;
     RECT  74.977 2.148 75.308 6.648 ;
     RECT  73.523 7.968 75.308 7.992 ;
     RECT  74.725 27.888 75.308 29.064 ;
     RECT  75.251 34.56 75.308 34.572 ;
     RECT  75.308 2.148 75.412 34.572 ;
     RECT  75.412 2.256 75.604 34.302 ;
     RECT  75.445 35.904 75.685 35.928 ;
     RECT  75.604 28.416 75.737 28.872 ;
     RECT  75.251 0.288 75.779 0.312 ;
     RECT  75.685 35.904 75.925 35.976 ;
     RECT  75.604 2.88 76.313 6.648 ;
     RECT  76.313 2.88 76.349 2.904 ;
     RECT  75.737 28.464 76.493 28.872 ;
     RECT  76.453 1.728 76.672 1.752 ;
     RECT  75.925 35.904 76.673 36.024 ;
     RECT  76.672 1.728 76.741 1.8 ;
     RECT  76.741 1.68 76.853 1.8 ;
     RECT  76.493 28.464 76.933 28.488 ;
     RECT  76.853 1.68 77.219 1.752 ;
     RECT  76.313 4.272 77.413 6.648 ;
     RECT  77.413 3.408 77.653 6.648 ;
     RECT  76.933 27.888 77.653 28.488 ;
     RECT  76.673 35.904 77.969 35.928 ;
     RECT  77.653 2.88 78.008 6.648 ;
     RECT  77.653 27.792 78.008 28.488 ;
     RECT  78.008 2.148 78.112 34.572 ;
     RECT  78.112 2.148 78.304 34.302 ;
     RECT  78.133 0.288 78.373 0.312 ;
     RECT  78.373 0.192 78.419 0.312 ;
     RECT  78.419 0.192 78.515 0.216 ;
     RECT  78.304 11.664 78.581 11.688 ;
     RECT  78.304 2.88 78.661 6.696 ;
     RECT  78.304 28.32 78.797 29.064 ;
     RECT  78.133 35.328 79.121 35.352 ;
     RECT  78.661 2.88 79.265 2.904 ;
     RECT  78.797 28.32 79.381 28.488 ;
     RECT  78.661 3.936 79.427 6.696 ;
     RECT  79.141 35.904 79.445 35.928 ;
     RECT  79.427 3.936 79.589 4.536 ;
     RECT  79.427 5.616 79.717 6.696 ;
     RECT  79.381 27.888 80.101 28.488 ;
     RECT  79.589 4.272 80.449 4.536 ;
     RECT  79.717 5.616 80.449 6.84 ;
     RECT  80.333 2.88 80.581 2.904 ;
     RECT  80.449 4.272 80.581 6.84 ;
     RECT  80.101 27.888 80.581 29.064 ;
     RECT  78.661 1.728 80.629 1.8 ;
     RECT  80.629 1.728 80.708 1.848 ;
     RECT  80.581 2.88 80.708 6.84 ;
     RECT  80.581 27.696 80.708 29.064 ;
     RECT  80.533 34.8 80.708 34.824 ;
     RECT  80.708 1.728 80.867 34.824 ;
     RECT  80.867 1.728 81.004 34.302 ;
     RECT  81.004 27.696 81.065 27.912 ;
     RECT  81.109 35.328 81.349 35.352 ;
     RECT  81.004 3.408 81.395 6.84 ;
     RECT  81.349 35.328 81.425 35.928 ;
     RECT  81.004 1.728 81.491 2.28 ;
     RECT  81.395 4.08 81.821 6.84 ;
     RECT  81.065 27.888 82.069 27.912 ;
     RECT  81.004 28.944 82.069 29.064 ;
     RECT  82.069 2.88 82.997 2.952 ;
     RECT  81.821 4.128 82.997 6.84 ;
     RECT  81.491 1.728 83.269 1.752 ;
     RECT  83.269 1.728 83.408 1.848 ;
     RECT  82.997 2.88 83.408 6.84 ;
     RECT  82.069 27.888 83.408 29.064 ;
     RECT  83.408 1.728 83.512 34.572 ;
     RECT  83.512 1.728 83.704 34.302 ;
     RECT  81.425 35.904 83.797 35.928 ;
     RECT  83.797 35.904 84.269 35.976 ;
     RECT  83.704 33.024 84.305 33.048 ;
     RECT  83.704 1.728 84.349 1.848 ;
     RECT  83.704 27.792 85.061 28.488 ;
     RECT  85.061 27.792 85.133 28.44 ;
     RECT  84.269 35.952 85.237 35.976 ;
     RECT  84.349 1.728 85.421 1.8 ;
     RECT  85.237 35.904 85.457 35.976 ;
     RECT  83.704 2.88 85.717 2.904 ;
     RECT  83.704 4.128 85.717 7.368 ;
     RECT  85.457 35.952 85.853 35.976 ;
     RECT  85.717 2.88 86.108 7.368 ;
     RECT  85.133 27.888 86.108 28.344 ;
     RECT  86.108 2.148 86.245 34.572 ;
     RECT  86.245 2.148 86.404 34.824 ;
     RECT  86.404 34.8 86.531 34.824 ;
     RECT  86.245 0.288 86.579 0.312 ;
     RECT  86.404 2.88 86.579 6.936 ;
     RECT  86.404 27.888 86.681 28.296 ;
     RECT  86.579 3.936 86.717 6.936 ;
     RECT  86.485 36 86.965 36.024 ;
     RECT  86.579 2.88 87.041 2.904 ;
     RECT  86.965 35.904 87.205 36.024 ;
     RECT  86.681 28.272 87.257 28.296 ;
     RECT  86.725 1.728 87.541 1.8 ;
     RECT  87.205 35.328 87.653 36.024 ;
     RECT  87.653 35.904 87.685 36.024 ;
     RECT  86.717 3.936 87.781 5.592 ;
     RECT  86.717 6.768 87.781 6.936 ;
     RECT  87.781 6.768 88.009 7.608 ;
     RECT  87.685 35.904 88.121 36.072 ;
     RECT  87.781 3.936 88.145 5.736 ;
     RECT  88.297 0.288 88.403 0.312 ;
     RECT  87.925 28.32 88.405 28.44 ;
     RECT  88.145 3.408 88.657 5.736 ;
     RECT  88.121 35.904 88.693 35.928 ;
     RECT  88.693 35.328 88.805 35.928 ;
     RECT  87.541 1.728 88.808 2.28 ;
     RECT  88.657 3.312 88.808 5.736 ;
     RECT  88.009 6.72 88.808 7.608 ;
     RECT  88.405 27.888 88.808 28.44 ;
     RECT  88.808 1.728 88.912 34.572 ;
     RECT  88.912 1.728 89.104 34.302 ;
     RECT  89.104 27.888 89.165 27.912 ;
     RECT  88.805 35.904 89.173 35.928 ;
     RECT  89.104 2.88 89.237 7.416 ;
     RECT  89.237 2.928 89.417 7.416 ;
     RECT  89.417 2.928 89.459 2.952 ;
     RECT  89.417 3.936 89.489 7.416 ;
     RECT  89.173 35.904 89.653 35.976 ;
     RECT  89.653 35.904 89.849 36.024 ;
     RECT  89.489 3.936 90.209 7.224 ;
     RECT  89.849 35.952 90.245 36.024 ;
     RECT  90.133 28.416 90.373 28.44 ;
     RECT  90.245 36 90.389 36.024 ;
     RECT  90.373 28.32 90.613 28.44 ;
     RECT  89.104 1.728 90.853 1.752 ;
     RECT  90.209 3.936 91.189 5.832 ;
     RECT  90.209 6.816 91.189 7.224 ;
     RECT  91.189 3.936 91.249 7.224 ;
     RECT  90.853 1.728 91.508 1.8 ;
     RECT  91.249 3.216 91.508 7.224 ;
     RECT  91.381 27.168 91.508 27.192 ;
     RECT  90.613 28.32 91.508 28.488 ;
     RECT  90.853 31.2 91.508 31.224 ;
     RECT  91.508 1.728 91.804 34.572 ;
     RECT  91.804 34.56 91.861 34.572 ;
     RECT  91.804 6.816 91.865 7.368 ;
     RECT  91.804 31.2 91.865 31.224 ;
     RECT  91.861 34.56 91.948 34.68 ;
     RECT  91.948 34.56 91.981 34.584 ;
     RECT  91.861 0.192 92.003 0.216 ;
     RECT  91.621 35.904 92.101 35.928 ;
     RECT  91.804 10.8 92.153 10.824 ;
     RECT  91.804 3.312 92.189 5.832 ;
     RECT  91.865 7.104 92.225 7.368 ;
     RECT  91.804 28.272 92.369 28.44 ;
     RECT  91.804 27.168 92.513 27.192 ;
     RECT  91.804 1.728 92.701 2.28 ;
     RECT  92.189 3.408 92.905 5.832 ;
     RECT  92.225 7.104 92.905 7.128 ;
     RECT  92.905 3.408 93.445 7.128 ;
     RECT  92.369 28.272 93.589 28.296 ;
     RECT  92.101 35.904 93.737 35.976 ;
     RECT  92.701 1.728 93.829 1.752 ;
     RECT  93.829 1.728 94.208 1.848 ;
     RECT  93.445 3.216 94.208 7.128 ;
     RECT  94.093 10.992 94.208 11.016 ;
     RECT  93.589 28.272 94.208 28.488 ;
     RECT  93.061 33.024 94.208 33.048 ;
     RECT  94.069 34.224 94.208 34.248 ;
     RECT  94.208 1.728 94.309 34.572 ;
     RECT  94.309 1.104 94.504 34.728 ;
     RECT  94.504 1.104 94.601 6.264 ;
     RECT  94.504 10.992 94.637 11.016 ;
     RECT  94.504 34.224 94.637 34.728 ;
     RECT  94.601 2.88 94.643 6.264 ;
     RECT  94.601 1.104 94.673 1.848 ;
     RECT  94.504 9.024 94.673 9.096 ;
     RECT  94.673 1.2 94.684 1.848 ;
     RECT  94.504 31.872 95.105 31.896 ;
     RECT  94.643 2.88 95.315 2.904 ;
     RECT  94.673 9.024 95.393 9.048 ;
     RECT  94.643 4.224 95.465 6.264 ;
     RECT  94.684 1.728 95.581 1.848 ;
     RECT  94.637 34.224 95.717 34.344 ;
     RECT  95.717 34.32 95.753 34.344 ;
     RECT  94.504 28.464 95.789 28.488 ;
     RECT  93.737 35.904 96.277 35.928 ;
     RECT  95.465 4.224 96.505 4.536 ;
     RECT  95.465 5.664 96.505 6.264 ;
     RECT  95.581 1.728 96.749 1.8 ;
     RECT  96.277 35.904 96.833 35.976 ;
     RECT  96.749 1.728 96.908 1.848 ;
     RECT  96.505 4.224 96.908 6.264 ;
     RECT  96.517 31.2 96.908 31.224 ;
     RECT  95.749 32.448 96.908 32.472 ;
     RECT  96.908 1.728 96.997 34.572 ;
     RECT  96.997 1.728 97.085 34.824 ;
     RECT  97.085 2.418 97.204 34.824 ;
     RECT  97.204 34.8 97.331 34.824 ;
     RECT  97.204 32.448 97.373 32.472 ;
     RECT  97.204 31.2 97.589 31.224 ;
     RECT  96.833 35.952 97.625 35.976 ;
     RECT  97.204 3.936 97.769 5.304 ;
     RECT  97.769 3.936 97.841 5.16 ;
     RECT  97.841 5.136 98.051 5.16 ;
     RECT  97.841 3.936 98.237 3.96 ;
    LAYER M5 ;
     RECT  24.432 0.133 24.456 0.144 ;
     RECT  28.608 0.133 28.704 0.144 ;
     RECT  28.728 0.133 28.944 0.144 ;
     RECT  28.968 0.133 29.232 0.144 ;
     RECT  29.256 0.133 29.472 0.144 ;
     RECT  29.496 0.133 29.712 0.144 ;
     RECT  29.736 0.133 29.832 0.144 ;
     RECT  32.544 0.133 32.568 0.144 ;
     RECT  33.984 0.133 34.128 0.144 ;
     RECT  34.152 0.133 34.368 0.144 ;
     RECT  34.392 0.133 34.608 0.144 ;
     RECT  34.632 0.133 34.728 0.144 ;
     RECT  35.952 0.133 35.976 0.144 ;
     RECT  40.08 0.133 40.104 0.144 ;
     RECT  45.504 0.133 45.528 0.144 ;
     RECT  46.944 0.133 46.968 0.144 ;
     RECT  48.192 0.133 48.216 0.144 ;
     RECT  55.776 0.133 55.872 0.144 ;
     RECT  55.896 0.133 56.112 0.144 ;
     RECT  56.136 0.133 56.328 0.144 ;
     RECT  57.504 0.133 57.528 0.144 ;
     RECT  59.712 0.133 59.808 0.144 ;
     RECT  59.832 0.133 60.048 0.144 ;
     RECT  60.072 0.133 60.288 0.144 ;
     RECT  60.312 0.133 60.528 0.144 ;
     RECT  60.552 0.133 60.768 0.144 ;
     RECT  60.792 0.133 61.008 0.144 ;
     RECT  61.032 0.133 61.248 0.144 ;
     RECT  61.272 0.133 61.536 0.144 ;
     RECT  61.56 0.133 61.656 0.144 ;
     RECT  64.08 0.133 64.104 0.144 ;
     RECT  65.088 0.133 65.184 0.144 ;
     RECT  65.208 0.133 65.424 0.144 ;
     RECT  65.448 0.133 65.664 0.144 ;
     RECT  65.688 0.133 65.832 0.144 ;
     RECT  67.056 0.133 67.08 0.144 ;
     RECT  68.976 0.133 69 0.144 ;
     RECT  71.184 0.133 71.208 0.144 ;
     RECT  73.152 0.133 73.176 0.144 ;
     RECT  4.536 0.144 4.752 0.192 ;
     RECT  4.776 0.144 4.992 0.192 ;
     RECT  5.016 0.144 5.232 0.192 ;
     RECT  5.256 0.144 5.472 0.192 ;
     RECT  5.496 0.144 5.712 0.192 ;
     RECT  5.736 0.144 5.952 0.192 ;
     RECT  5.976 0.144 6.192 0.192 ;
     RECT  6.216 0.144 6.432 0.192 ;
     RECT  6.456 0.144 6.672 0.192 ;
     RECT  6.696 0.144 6.96 0.192 ;
     RECT  6.984 0.144 7.2 0.192 ;
     RECT  7.224 0.144 7.44 0.192 ;
     RECT  7.464 0.144 7.68 0.192 ;
     RECT  7.704 0.144 7.92 0.192 ;
     RECT  7.944 0.144 8.16 0.192 ;
     RECT  8.184 0.144 8.4 0.192 ;
     RECT  8.424 0.144 8.64 0.192 ;
     RECT  8.664 0.144 8.88 0.192 ;
     RECT  8.904 0.144 9.12 0.192 ;
     RECT  9.144 0.144 9.408 0.192 ;
     RECT  9.432 0.144 9.648 0.192 ;
     RECT  9.672 0.144 9.888 0.192 ;
     RECT  9.912 0.144 10.128 0.192 ;
     RECT  10.152 0.144 10.368 0.192 ;
     RECT  10.392 0.144 10.608 0.192 ;
     RECT  10.632 0.144 10.848 0.192 ;
     RECT  10.872 0.144 11.088 0.192 ;
     RECT  11.112 0.144 11.328 0.192 ;
     RECT  11.352 0.144 11.568 0.192 ;
     RECT  11.592 0.144 11.856 0.192 ;
     RECT  11.88 0.144 12.096 0.192 ;
     RECT  12.12 0.144 12.336 0.192 ;
     RECT  12.36 0.144 12.576 0.192 ;
     RECT  12.6 0.144 12.816 0.192 ;
     RECT  12.84 0.144 13.056 0.192 ;
     RECT  13.08 0.144 13.296 0.192 ;
     RECT  13.32 0.144 13.536 0.192 ;
     RECT  13.56 0.144 13.776 0.192 ;
     RECT  13.8 0.144 14.016 0.192 ;
     RECT  14.04 0.144 14.304 0.192 ;
     RECT  14.328 0.144 14.544 0.192 ;
     RECT  14.568 0.144 14.784 0.192 ;
     RECT  14.808 0.144 15.024 0.192 ;
     RECT  15.048 0.144 15.264 0.192 ;
     RECT  15.288 0.144 15.504 0.192 ;
     RECT  15.528 0.144 15.744 0.192 ;
     RECT  15.768 0.144 15.984 0.192 ;
     RECT  16.008 0.144 16.224 0.192 ;
     RECT  16.248 0.144 16.464 0.192 ;
     RECT  16.488 0.144 16.752 0.192 ;
     RECT  16.776 0.144 16.992 0.192 ;
     RECT  17.016 0.144 17.232 0.192 ;
     RECT  17.256 0.144 17.472 0.192 ;
     RECT  17.496 0.144 17.712 0.192 ;
     RECT  17.736 0.144 17.952 0.192 ;
     RECT  17.976 0.144 18.192 0.192 ;
     RECT  18.216 0.144 18.432 0.192 ;
     RECT  18.456 0.144 18.672 0.192 ;
     RECT  18.696 0.144 18.912 0.192 ;
     RECT  18.936 0.144 19.2 0.192 ;
     RECT  19.224 0.144 19.44 0.192 ;
     RECT  19.464 0.144 19.68 0.192 ;
     RECT  19.704 0.144 19.92 0.192 ;
     RECT  19.944 0.144 20.16 0.192 ;
     RECT  20.184 0.144 20.4 0.192 ;
     RECT  20.424 0.144 20.64 0.192 ;
     RECT  20.664 0.144 20.88 0.192 ;
     RECT  20.904 0.144 21.12 0.192 ;
     RECT  21.144 0.144 21.36 0.192 ;
     RECT  21.384 0.144 21.6 0.192 ;
     RECT  21.624 0.144 21.888 0.192 ;
     RECT  21.912 0.144 22.128 0.192 ;
     RECT  22.152 0.144 22.368 0.192 ;
     RECT  22.392 0.144 22.608 0.192 ;
     RECT  22.632 0.144 22.848 0.192 ;
     RECT  22.872 0.144 23.088 0.192 ;
     RECT  23.112 0.144 23.328 0.192 ;
     RECT  23.352 0.144 23.568 0.192 ;
     RECT  23.592 0.144 23.808 0.192 ;
     RECT  23.832 0.144 24.048 0.192 ;
     RECT  24.072 0.144 24.336 0.192 ;
     RECT  24.36 0.144 24.576 0.192 ;
     RECT  24.6 0.144 24.816 0.192 ;
     RECT  24.84 0.144 25.056 0.192 ;
     RECT  25.08 0.144 25.296 0.192 ;
     RECT  25.32 0.144 25.536 0.192 ;
     RECT  25.56 0.144 25.776 0.192 ;
     RECT  25.8 0.144 26.016 0.192 ;
     RECT  26.04 0.144 26.256 0.192 ;
     RECT  26.28 0.144 26.496 0.192 ;
     RECT  26.52 0.144 26.784 0.192 ;
     RECT  26.808 0.144 27.024 0.192 ;
     RECT  27.048 0.144 27.264 0.192 ;
     RECT  27.288 0.144 27.504 0.192 ;
     RECT  27.528 0.144 27.744 0.192 ;
     RECT  27.768 0.144 27.984 0.192 ;
     RECT  28.008 0.144 28.224 0.192 ;
     RECT  28.248 0.144 28.464 0.192 ;
     RECT  28.488 0.144 28.704 0.192 ;
     RECT  28.728 0.144 28.944 0.192 ;
     RECT  28.968 0.144 29.232 0.192 ;
     RECT  29.256 0.144 29.472 0.192 ;
     RECT  29.496 0.144 29.712 0.192 ;
     RECT  29.736 0.144 29.952 0.192 ;
     RECT  29.976 0.144 30.192 0.192 ;
     RECT  30.216 0.144 30.432 0.192 ;
     RECT  30.456 0.144 30.672 0.192 ;
     RECT  30.696 0.144 30.912 0.192 ;
     RECT  30.936 0.144 31.152 0.192 ;
     RECT  31.176 0.144 31.392 0.192 ;
     RECT  31.416 0.144 31.68 0.192 ;
     RECT  31.704 0.144 31.92 0.192 ;
     RECT  31.944 0.144 32.16 0.192 ;
     RECT  32.184 0.144 32.4 0.192 ;
     RECT  32.424 0.144 32.64 0.192 ;
     RECT  32.664 0.144 32.88 0.192 ;
     RECT  32.904 0.144 33.12 0.192 ;
     RECT  33.144 0.144 33.36 0.192 ;
     RECT  33.384 0.144 33.6 0.192 ;
     RECT  33.624 0.144 33.84 0.192 ;
     RECT  33.864 0.144 34.128 0.192 ;
     RECT  34.152 0.144 34.368 0.192 ;
     RECT  34.392 0.144 34.608 0.192 ;
     RECT  34.632 0.144 34.848 0.192 ;
     RECT  34.872 0.144 35.088 0.192 ;
     RECT  35.112 0.144 35.328 0.192 ;
     RECT  35.352 0.144 35.568 0.192 ;
     RECT  35.592 0.144 35.808 0.192 ;
     RECT  35.832 0.144 36.048 0.192 ;
     RECT  36.072 0.144 36.288 0.192 ;
     RECT  36.312 0.144 36.576 0.192 ;
     RECT  36.6 0.144 36.816 0.192 ;
     RECT  36.84 0.144 37.056 0.192 ;
     RECT  37.08 0.144 37.296 0.192 ;
     RECT  37.32 0.144 37.536 0.192 ;
     RECT  37.56 0.144 37.776 0.192 ;
     RECT  37.8 0.144 38.016 0.192 ;
     RECT  38.04 0.144 38.256 0.192 ;
     RECT  38.28 0.144 38.496 0.192 ;
     RECT  38.52 0.144 38.736 0.192 ;
     RECT  38.76 0.144 39.024 0.192 ;
     RECT  39.048 0.144 39.264 0.192 ;
     RECT  39.288 0.144 39.504 0.192 ;
     RECT  39.528 0.144 39.744 0.192 ;
     RECT  39.768 0.144 39.984 0.192 ;
     RECT  40.008 0.144 40.224 0.192 ;
     RECT  40.248 0.144 40.464 0.192 ;
     RECT  40.488 0.144 40.704 0.192 ;
     RECT  40.728 0.144 40.944 0.192 ;
     RECT  40.968 0.144 41.184 0.192 ;
     RECT  41.208 0.144 41.424 0.192 ;
     RECT  41.448 0.144 41.712 0.192 ;
     RECT  41.736 0.144 41.952 0.192 ;
     RECT  41.976 0.144 42.192 0.192 ;
     RECT  42.216 0.144 42.432 0.192 ;
     RECT  42.456 0.144 42.672 0.192 ;
     RECT  42.696 0.144 42.912 0.192 ;
     RECT  42.936 0.144 43.152 0.192 ;
     RECT  43.176 0.144 43.392 0.192 ;
     RECT  43.416 0.144 43.632 0.192 ;
     RECT  43.656 0.144 43.872 0.192 ;
     RECT  43.896 0.144 44.16 0.192 ;
     RECT  44.184 0.144 44.4 0.192 ;
     RECT  44.424 0.144 44.64 0.192 ;
     RECT  44.664 0.144 44.88 0.192 ;
     RECT  44.904 0.144 45.12 0.192 ;
     RECT  45.144 0.144 45.36 0.192 ;
     RECT  45.384 0.144 45.6 0.192 ;
     RECT  45.624 0.144 45.84 0.192 ;
     RECT  45.864 0.144 46.08 0.192 ;
     RECT  46.104 0.144 46.32 0.192 ;
     RECT  46.344 0.144 46.608 0.192 ;
     RECT  46.632 0.144 46.848 0.192 ;
     RECT  46.872 0.144 47.088 0.192 ;
     RECT  47.112 0.144 47.328 0.192 ;
     RECT  47.352 0.144 47.568 0.192 ;
     RECT  47.592 0.144 47.808 0.192 ;
     RECT  47.832 0.144 48.048 0.192 ;
     RECT  48.072 0.144 48.288 0.192 ;
     RECT  48.312 0.144 48.528 0.192 ;
     RECT  48.552 0.144 48.768 0.192 ;
     RECT  48.792 0.144 49.056 0.192 ;
     RECT  49.08 0.144 49.296 0.192 ;
     RECT  49.32 0.144 49.536 0.192 ;
     RECT  49.56 0.144 49.776 0.192 ;
     RECT  49.8 0.144 50.016 0.192 ;
     RECT  50.04 0.144 50.256 0.192 ;
     RECT  50.28 0.144 50.496 0.192 ;
     RECT  50.52 0.144 50.736 0.192 ;
     RECT  50.76 0.144 50.976 0.192 ;
     RECT  51 0.144 51.216 0.192 ;
     RECT  51.24 0.144 51.504 0.192 ;
     RECT  51.528 0.144 51.744 0.192 ;
     RECT  51.768 0.144 51.984 0.192 ;
     RECT  52.008 0.144 52.224 0.192 ;
     RECT  52.248 0.144 52.464 0.192 ;
     RECT  52.488 0.144 52.704 0.192 ;
     RECT  52.728 0.144 52.944 0.192 ;
     RECT  52.968 0.144 53.184 0.192 ;
     RECT  53.208 0.144 53.424 0.192 ;
     RECT  53.448 0.144 53.664 0.192 ;
     RECT  53.688 0.144 53.952 0.192 ;
     RECT  53.976 0.144 54.192 0.192 ;
     RECT  54.216 0.144 54.432 0.192 ;
     RECT  54.456 0.144 54.672 0.192 ;
     RECT  54.696 0.144 54.912 0.192 ;
     RECT  54.936 0.144 55.152 0.192 ;
     RECT  55.176 0.144 55.392 0.192 ;
     RECT  55.416 0.144 55.632 0.192 ;
     RECT  55.656 0.144 55.872 0.192 ;
     RECT  55.896 0.144 56.112 0.192 ;
     RECT  56.136 0.144 56.4 0.192 ;
     RECT  56.424 0.144 56.64 0.192 ;
     RECT  56.664 0.144 56.88 0.192 ;
     RECT  56.904 0.144 57.12 0.192 ;
     RECT  57.144 0.144 57.36 0.192 ;
     RECT  57.384 0.144 57.6 0.192 ;
     RECT  57.624 0.144 57.84 0.192 ;
     RECT  57.864 0.144 58.08 0.192 ;
     RECT  58.104 0.144 58.32 0.192 ;
     RECT  58.344 0.144 58.56 0.192 ;
     RECT  58.584 0.144 58.848 0.192 ;
     RECT  58.872 0.144 59.088 0.192 ;
     RECT  59.112 0.144 59.328 0.192 ;
     RECT  59.352 0.144 59.568 0.192 ;
     RECT  59.592 0.144 59.808 0.192 ;
     RECT  59.832 0.144 60.048 0.192 ;
     RECT  60.072 0.144 60.288 0.192 ;
     RECT  60.312 0.144 60.528 0.192 ;
     RECT  60.552 0.144 60.768 0.192 ;
     RECT  60.792 0.144 61.008 0.192 ;
     RECT  61.032 0.144 61.248 0.192 ;
     RECT  61.272 0.144 61.536 0.192 ;
     RECT  61.56 0.144 61.776 0.192 ;
     RECT  61.8 0.144 62.016 0.192 ;
     RECT  62.04 0.144 62.256 0.192 ;
     RECT  62.28 0.144 62.496 0.192 ;
     RECT  62.52 0.144 62.736 0.192 ;
     RECT  62.76 0.144 62.976 0.192 ;
     RECT  63 0.144 63.216 0.192 ;
     RECT  63.24 0.144 63.456 0.192 ;
     RECT  63.48 0.144 63.696 0.192 ;
     RECT  63.72 0.144 63.984 0.192 ;
     RECT  64.008 0.144 64.224 0.192 ;
     RECT  64.248 0.144 64.464 0.192 ;
     RECT  64.488 0.144 64.704 0.192 ;
     RECT  64.728 0.144 64.944 0.192 ;
     RECT  64.968 0.144 65.184 0.192 ;
     RECT  65.208 0.144 65.424 0.192 ;
     RECT  65.448 0.144 65.664 0.192 ;
     RECT  65.688 0.144 65.904 0.192 ;
     RECT  65.928 0.144 66.144 0.192 ;
     RECT  66.168 0.144 66.432 0.192 ;
     RECT  66.456 0.144 66.672 0.192 ;
     RECT  66.696 0.144 66.912 0.192 ;
     RECT  66.936 0.144 67.152 0.192 ;
     RECT  67.176 0.144 67.392 0.192 ;
     RECT  67.416 0.144 67.632 0.192 ;
     RECT  67.656 0.144 67.872 0.192 ;
     RECT  67.896 0.144 68.112 0.192 ;
     RECT  68.136 0.144 68.352 0.192 ;
     RECT  68.376 0.144 68.592 0.192 ;
     RECT  68.616 0.144 68.88 0.192 ;
     RECT  68.904 0.144 69.12 0.192 ;
     RECT  69.144 0.144 69.36 0.192 ;
     RECT  69.384 0.144 69.6 0.192 ;
     RECT  69.624 0.144 69.84 0.192 ;
     RECT  69.864 0.144 70.08 0.192 ;
     RECT  70.104 0.144 70.32 0.192 ;
     RECT  70.344 0.144 70.56 0.192 ;
     RECT  70.584 0.144 70.8 0.192 ;
     RECT  70.824 0.144 71.04 0.192 ;
     RECT  71.064 0.144 71.328 0.192 ;
     RECT  71.352 0.144 71.568 0.192 ;
     RECT  71.592 0.144 71.808 0.192 ;
     RECT  71.832 0.144 72.048 0.192 ;
     RECT  72.072 0.144 72.288 0.192 ;
     RECT  72.312 0.144 72.528 0.192 ;
     RECT  72.552 0.144 72.768 0.192 ;
     RECT  72.792 0.144 73.008 0.192 ;
     RECT  73.032 0.144 73.248 0.192 ;
     RECT  73.272 0.144 73.488 0.192 ;
     RECT  73.512 0.144 73.776 0.192 ;
     RECT  73.8 0.144 74.016 0.192 ;
     RECT  74.04 0.144 74.256 0.192 ;
     RECT  74.28 0.144 74.496 0.192 ;
     RECT  74.52 0.144 74.736 0.192 ;
     RECT  74.76 0.144 74.976 0.192 ;
     RECT  75 0.144 75.216 0.192 ;
     RECT  75.24 0.144 75.456 0.192 ;
     RECT  75.48 0.144 75.696 0.192 ;
     RECT  75.72 0.144 75.936 0.192 ;
     RECT  75.96 0.144 76.224 0.192 ;
     RECT  76.248 0.144 76.464 0.192 ;
     RECT  76.488 0.144 76.704 0.192 ;
     RECT  76.728 0.144 76.944 0.192 ;
     RECT  76.968 0.144 77.184 0.192 ;
     RECT  77.208 0.144 77.424 0.192 ;
     RECT  77.448 0.144 77.664 0.192 ;
     RECT  77.688 0.144 77.904 0.192 ;
     RECT  77.928 0.144 78.144 0.192 ;
     RECT  78.168 0.144 78.384 0.192 ;
     RECT  78.408 0.144 78.672 0.192 ;
     RECT  78.696 0.144 78.912 0.192 ;
     RECT  78.936 0.144 79.152 0.192 ;
     RECT  79.176 0.144 79.392 0.192 ;
     RECT  79.416 0.144 79.632 0.192 ;
     RECT  79.656 0.144 79.872 0.192 ;
     RECT  79.896 0.144 80.112 0.192 ;
     RECT  80.136 0.144 80.352 0.192 ;
     RECT  80.376 0.144 80.592 0.192 ;
     RECT  80.616 0.144 80.832 0.192 ;
     RECT  80.856 0.144 81.12 0.192 ;
     RECT  81.144 0.144 81.36 0.192 ;
     RECT  81.384 0.144 81.6 0.192 ;
     RECT  81.624 0.144 81.84 0.192 ;
     RECT  81.864 0.144 82.08 0.192 ;
     RECT  82.104 0.144 82.32 0.192 ;
     RECT  82.344 0.144 82.56 0.192 ;
     RECT  82.584 0.144 82.8 0.192 ;
     RECT  82.824 0.144 83.04 0.192 ;
     RECT  83.064 0.144 83.28 0.192 ;
     RECT  83.304 0.144 83.52 0.192 ;
     RECT  83.544 0.144 83.808 0.192 ;
     RECT  83.832 0.144 84.048 0.192 ;
     RECT  84.072 0.144 84.288 0.192 ;
     RECT  84.312 0.144 84.528 0.192 ;
     RECT  84.552 0.144 84.768 0.192 ;
     RECT  84.792 0.144 85.008 0.192 ;
     RECT  85.032 0.144 85.248 0.192 ;
     RECT  85.272 0.144 85.488 0.192 ;
     RECT  85.512 0.144 85.728 0.192 ;
     RECT  85.752 0.144 85.968 0.192 ;
     RECT  85.992 0.144 86.256 0.192 ;
     RECT  86.28 0.144 86.496 0.192 ;
     RECT  86.52 0.144 86.736 0.192 ;
     RECT  86.76 0.144 86.976 0.192 ;
     RECT  87 0.144 87.216 0.192 ;
     RECT  87.24 0.144 87.456 0.192 ;
     RECT  87.48 0.144 87.696 0.192 ;
     RECT  87.72 0.144 87.936 0.192 ;
     RECT  87.96 0.144 88.176 0.192 ;
     RECT  88.2 0.144 88.416 0.192 ;
     RECT  88.44 0.144 88.704 0.192 ;
     RECT  88.728 0.144 88.944 0.192 ;
     RECT  88.968 0.144 89.184 0.192 ;
     RECT  89.208 0.144 89.424 0.192 ;
     RECT  89.448 0.144 89.664 0.192 ;
     RECT  89.688 0.144 89.904 0.192 ;
     RECT  89.928 0.144 90.144 0.192 ;
     RECT  90.168 0.144 90.384 0.192 ;
     RECT  90.408 0.144 90.624 0.192 ;
     RECT  90.648 0.144 90.864 0.192 ;
     RECT  90.888 0.144 91.152 0.192 ;
     RECT  91.176 0.144 91.392 0.192 ;
     RECT  91.416 0.144 91.632 0.192 ;
     RECT  91.656 0.144 91.872 0.192 ;
     RECT  91.896 0.144 92.112 0.192 ;
     RECT  92.136 0.144 92.352 0.192 ;
     RECT  92.376 0.144 92.592 0.192 ;
     RECT  92.616 0.144 92.832 0.192 ;
     RECT  92.856 0.144 93.072 0.192 ;
     RECT  93.096 0.144 93.312 0.192 ;
     RECT  93.336 0.144 93.6 0.192 ;
     RECT  93.624 0.144 93.84 0.192 ;
     RECT  93.864 0.144 94.08 0.192 ;
     RECT  94.104 0.144 94.32 0.192 ;
     RECT  94.344 0.144 94.56 0.192 ;
     RECT  94.584 0.144 94.8 0.192 ;
     RECT  94.824 0.144 95.04 0.192 ;
     RECT  95.064 0.144 95.28 0.192 ;
     RECT  95.304 0.144 95.52 0.192 ;
     RECT  95.544 0.144 95.76 0.192 ;
     RECT  95.784 0.144 96.048 0.192 ;
     RECT  96.072 0.144 96.288 0.192 ;
     RECT  96.312 0.144 96.528 0.192 ;
     RECT  96.552 0.144 96.768 0.192 ;
     RECT  96.792 0.144 97.008 0.192 ;
     RECT  4.512 0.192 97.032 1.763 ;
     RECT  6.672 1.763 6.696 1.811 ;
     RECT  7.8 1.763 11.592 1.811 ;
     RECT  15.264 1.763 95.544 1.811 ;
     RECT  91.5 1.811 95.544 1.859 ;
     RECT  96.768 1.763 97.032 1.859 ;
     RECT  80.352 1.811 89.928 1.907 ;
     RECT  2.4 2.137 2.52 2.151 ;
     RECT  96.9 1.859 97.032 2.151 ;
     RECT  4.992 1.763 5.412 2.291 ;
     RECT  13.104 1.763 13.8 2.339 ;
     RECT  15.264 1.811 57.624 2.339 ;
     RECT  17.472 2.339 57.624 2.821 ;
     RECT  58.848 1.811 76.248 2.821 ;
     RECT  7.8 1.811 8.424 2.915 ;
     RECT  10.368 1.811 11.592 2.915 ;
     RECT  13.104 2.339 13.656 2.915 ;
     RECT  15.264 2.339 16.488 2.915 ;
     RECT  17.472 2.821 76.248 2.915 ;
     RECT  77.424 1.811 79.176 2.915 ;
     RECT  80.352 1.907 87 2.915 ;
     RECT  21.168 2.915 52.584 2.963 ;
     RECT  80.592 2.915 83.712 2.963 ;
     RECT  13.104 2.915 13.608 2.965 ;
     RECT  18.432 2.915 19.464 3.059 ;
     RECT  7.8 2.915 8.28 3.443 ;
     RECT  42.72 2.963 52.584 3.443 ;
     RECT  69.744 2.915 76.248 3.443 ;
     RECT  77.424 2.915 78.648 3.443 ;
     RECT  83.04 2.963 83.712 3.443 ;
     RECT  85.728 2.915 86.568 3.443 ;
     RECT  88.176 1.907 89.928 3.443 ;
     RECT  13.056 2.965 13.608 3.491 ;
     RECT  15.504 2.915 16.488 3.491 ;
     RECT  18.48 3.059 19.464 3.491 ;
     RECT  77.904 3.443 78.648 3.491 ;
     RECT  15.504 3.491 16.392 3.635 ;
     RECT  5.1 2.291 5.412 3.685 ;
     RECT  78 3.491 78.648 3.925 ;
     RECT  88.368 3.443 89.928 3.925 ;
     RECT  91.5 1.859 95.448 3.925 ;
     RECT  96.9 2.151 97.212 3.925 ;
     RECT  21.168 2.963 37.992 3.973 ;
     RECT  15.504 3.635 16.344 4.019 ;
     RECT  53.568 2.915 68.664 4.019 ;
     RECT  69.744 3.443 75.768 4.019 ;
     RECT  88.368 3.925 95.448 4.019 ;
     RECT  39.216 2.963 41.592 4.115 ;
     RECT  78 3.925 79.56 4.115 ;
     RECT  53.568 4.019 54.168 4.163 ;
     RECT  21.168 3.973 38.232 4.213 ;
     RECT  79.344 4.115 79.56 4.261 ;
     RECT  80.592 2.963 81.48 4.261 ;
     RECT  86.1 3.443 86.568 4.261 ;
     RECT  96.9 3.925 98.04 4.357 ;
     RECT  86.1 4.261 87 4.405 ;
     RECT  88.368 4.019 89.112 4.405 ;
     RECT  13.056 3.491 13.512 4.451 ;
     RECT  18.48 3.491 19.032 4.501 ;
     RECT  42.72 3.443 52.488 4.595 ;
     RECT  42.72 4.595 51.312 4.643 ;
     RECT  55.872 4.019 68.664 4.645 ;
     RECT  69.744 4.019 75.72 4.645 ;
     RECT  42.72 4.643 43.896 4.693 ;
     RECT  52.464 4.595 52.488 4.741 ;
     RECT  53.568 4.163 54.012 4.741 ;
     RECT  15.504 4.019 16.212 4.789 ;
     RECT  55.872 4.645 75.72 4.883 ;
     RECT  13.2 4.451 13.512 4.981 ;
     RECT  5.1 3.685 6.024 5.027 ;
     RECT  7.8 3.443 8.112 5.029 ;
     RECT  79.344 4.261 81.48 5.029 ;
     RECT  52.464 4.741 54.012 5.171 ;
     RECT  55.872 4.883 71.256 5.171 ;
     RECT  72.384 4.883 75.72 5.171 ;
     RECT  86.1 4.405 89.112 5.171 ;
     RECT  96.624 4.357 98.04 5.171 ;
     RECT  75.3 5.171 75.72 5.173 ;
     RECT  44.976 4.643 51.312 5.219 ;
     RECT  90.576 4.019 95.448 5.267 ;
     RECT  55.872 5.171 68.568 5.363 ;
     RECT  55.872 5.363 57.24 5.365 ;
     RECT  79.344 5.029 81.528 5.365 ;
     RECT  92.88 5.267 95.448 5.411 ;
     RECT  86.1 5.171 87.816 5.603 ;
     RECT  92.88 5.411 92.904 5.603 ;
     RECT  7.8 5.029 8.472 5.747 ;
     RECT  10.5 2.915 11.592 5.747 ;
     RECT  17.808 4.501 19.032 5.747 ;
     RECT  21.072 4.213 38.232 5.747 ;
     RECT  42.24 4.693 43.896 5.747 ;
     RECT  69.552 5.171 71.256 5.747 ;
     RECT  79.344 5.365 81.576 5.747 ;
     RECT  39.216 4.115 41.016 5.795 ;
     RECT  58.224 5.363 68.568 5.795 ;
     RECT  72.384 5.171 73.128 5.795 ;
     RECT  83.28 3.443 83.712 5.795 ;
     RECT  94.2 5.411 95.448 5.795 ;
     RECT  96.624 5.171 97.212 5.795 ;
     RECT  37.392 5.747 38.184 5.843 ;
     RECT  65.952 5.795 68.376 5.843 ;
     RECT  69.552 5.747 71.208 5.987 ;
     RECT  17.808 5.747 18.912 6.133 ;
     RECT  44.976 5.219 49.56 6.229 ;
     RECT  51 5.219 51.312 6.229 ;
     RECT  13.2 4.981 13.704 6.323 ;
     RECT  14.784 4.789 16.212 6.323 ;
     RECT  44.976 6.229 51.312 6.323 ;
     RECT  58.224 5.795 64.92 6.323 ;
     RECT  69.9 5.987 71.208 6.323 ;
     RECT  23.328 5.747 32.412 6.371 ;
     RECT  42.9 5.747 43.896 6.371 ;
     RECT  44.976 6.323 48.984 6.371 ;
     RECT  65.952 5.843 68.328 6.371 ;
     RECT  23.328 6.371 25.608 6.419 ;
     RECT  39.216 5.795 40.968 6.515 ;
     RECT  42.9 6.371 43.848 6.515 ;
     RECT  75.3 5.173 75.816 6.515 ;
     RECT  66.096 6.371 68.328 6.563 ;
     RECT  55.248 5.365 57.24 6.659 ;
     RECT  10.5 5.747 11.256 6.707 ;
     RECT  26.592 6.371 32.412 6.707 ;
     RECT  55.248 6.659 56.808 6.707 ;
     RECT  79.392 5.747 81.576 6.707 ;
     RECT  72.432 5.795 73.128 6.709 ;
     RECT  33.456 5.747 35.88 6.805 ;
     RECT  58.992 6.323 64.92 6.805 ;
     RECT  66.192 6.563 68.328 6.805 ;
     RECT  72.432 6.709 73.896 6.805 ;
     RECT  15.36 6.323 16.212 6.851 ;
     RECT  69.9 6.323 70.44 6.851 ;
     RECT  79.728 6.707 81.012 6.851 ;
     RECT  86.1 5.603 86.52 6.851 ;
     RECT  10.5 6.707 11.208 6.899 ;
     RECT  26.592 6.707 30.408 6.899 ;
     RECT  31.488 6.707 32.412 6.899 ;
     RECT  39.216 6.515 40.632 6.899 ;
     RECT  45.456 6.371 48.984 6.899 ;
     RECT  53.088 5.171 54.012 6.899 ;
     RECT  58.992 6.805 64.968 6.899 ;
     RECT  66.192 6.805 68.568 6.899 ;
     RECT  90.576 5.267 91.812 6.899 ;
     RECT  45.456 6.899 48.792 6.947 ;
     RECT  33.456 6.805 36.072 7.139 ;
     RECT  56.112 6.707 56.808 7.139 ;
     RECT  17.616 6.133 18.912 7.331 ;
     RECT  23.376 6.419 25.608 7.427 ;
     RECT  23.376 7.427 24.312 7.475 ;
     RECT  28.368 6.899 30.408 7.475 ;
     RECT  53.328 6.899 54.012 7.475 ;
     RECT  58.992 6.899 62.664 7.475 ;
     RECT  28.992 7.475 30.12 7.523 ;
     RECT  42.9 6.515 43.212 7.525 ;
     RECT  25.584 7.427 25.608 7.619 ;
     RECT  87.792 5.603 87.816 7.619 ;
     RECT  26.592 6.899 27.336 7.667 ;
     RECT  26.592 7.667 27.144 8.003 ;
     RECT  28.992 7.523 29.928 8.003 ;
     RECT  31.92 6.899 32.412 8.003 ;
     RECT  33.552 7.139 36.072 8.003 ;
     RECT  50.448 6.323 51.312 8.003 ;
     RECT  58.992 7.475 60.312 8.003 ;
     RECT  61.392 7.475 62.664 8.003 ;
     RECT  66.192 6.899 67.512 8.003 ;
     RECT  72.336 6.805 73.896 8.003 ;
     RECT  33.552 8.003 35.112 8.579 ;
     RECT  45.456 6.947 46.632 8.579 ;
     RECT  47.616 6.947 48.792 8.579 ;
     RECT  59.1 8.003 60.312 8.579 ;
     RECT  61.8 8.003 62.664 8.579 ;
     RECT  63.792 6.899 64.968 8.579 ;
     RECT  68.544 6.899 68.568 8.579 ;
     RECT  72.336 8.003 73.512 8.579 ;
     RECT  26.7 8.003 27.144 9.155 ;
     RECT  63.792 8.579 64.812 9.155 ;
     RECT  66.384 8.003 67.512 9.155 ;
     RECT  42.9 7.525 43.32 10.355 ;
     RECT  34.128 8.579 35.112 10.883 ;
     RECT  56.4 7.139 56.808 10.931 ;
     RECT  24 7.475 24.312 11.221 ;
     RECT  24 11.221 24.408 11.651 ;
     RECT  0.24 6.565 0.264 18.419 ;
     RECT  91.5 6.899 91.812 27.157 ;
     RECT  48.3 8.579 48.612 27.301 ;
     RECT  80.7 6.851 81.012 27.685 ;
     RECT  61.8 8.579 62.112 27.781 ;
     RECT  64.5 9.155 64.812 27.781 ;
     RECT  78 4.115 78.312 27.781 ;
     RECT  83.4 5.795 83.712 27.781 ;
     RECT  61.536 27.781 62.112 27.829 ;
     RECT  5.1 5.027 5.412 27.877 ;
     RECT  7.8 5.747 8.112 27.877 ;
     RECT  15.9 6.851 16.212 27.877 ;
     RECT  18.6 7.331 18.912 27.877 ;
     RECT  21.3 5.747 21.612 27.877 ;
     RECT  24 11.651 24.312 27.877 ;
     RECT  26.7 9.155 27.012 27.877 ;
     RECT  32.1 8.003 32.412 27.877 ;
     RECT  45.6 8.579 45.912 27.877 ;
     RECT  53.7 7.475 54.012 27.877 ;
     RECT  56.4 10.931 56.712 27.877 ;
     RECT  59.1 8.579 59.412 27.877 ;
     RECT  61.008 27.829 62.112 27.877 ;
     RECT  63.984 27.781 64.812 27.877 ;
     RECT  67.2 9.155 67.512 27.877 ;
     RECT  69.9 6.851 70.212 27.877 ;
     RECT  72.6 8.579 72.912 27.877 ;
     RECT  75.3 6.515 75.612 27.877 ;
     RECT  77.664 27.781 78.312 27.877 ;
     RECT  80.592 27.685 81.012 27.877 ;
     RECT  83.4 27.781 84.552 27.877 ;
     RECT  86.1 6.851 86.412 27.877 ;
     RECT  88.8 5.171 89.112 27.877 ;
     RECT  10.5 6.899 10.812 27.925 ;
     RECT  13.2 6.323 13.512 27.925 ;
     RECT  7.632 27.877 8.112 28.021 ;
     RECT  29.4 8.003 29.712 28.261 ;
     RECT  74.736 27.877 75.612 28.261 ;
     RECT  85.728 27.877 86.52 28.261 ;
     RECT  91.392 27.157 91.812 28.261 ;
     RECT  5.1 27.877 5.736 28.309 ;
     RECT  10.5 27.925 10.92 28.309 ;
     RECT  13.056 27.925 13.512 28.309 ;
     RECT  18.48 27.877 18.912 28.309 ;
     RECT  21.12 27.877 21.612 28.309 ;
     RECT  26.016 27.877 27.012 28.309 ;
     RECT  27.984 27.781 28.008 28.309 ;
     RECT  29.28 28.261 29.712 28.309 ;
     RECT  31.392 27.877 32.412 28.309 ;
     RECT  37.5 5.843 37.812 28.309 ;
     RECT  40.2 6.899 40.512 28.309 ;
     RECT  42.9 10.355 43.212 28.309 ;
     RECT  45.12 27.877 45.912 28.309 ;
     RECT  47.328 27.301 48.612 28.309 ;
     RECT  56.304 27.877 56.712 28.309 ;
     RECT  58.992 27.877 59.412 28.309 ;
     RECT  60.528 27.877 62.112 28.309 ;
     RECT  67.2 27.877 67.608 28.309 ;
     RECT  69.12 27.877 70.212 28.309 ;
     RECT  76.944 27.877 78.312 28.309 ;
     RECT  79.392 27.877 81.624 28.309 ;
     RECT  82.8 27.877 84.552 28.309 ;
     RECT  85.728 28.261 86.76 28.309 ;
     RECT  88.416 27.877 89.112 28.309 ;
     RECT  7.2 28.021 8.112 28.357 ;
     RECT  9.408 27.925 9.432 28.357 ;
     RECT  15.744 27.877 16.212 28.357 ;
     RECT  40.2 28.309 41.448 28.357 ;
     RECT  42.9 28.309 43.32 28.357 ;
     RECT  53.7 27.877 54.696 28.357 ;
     RECT  56.112 28.309 59.412 28.357 ;
     RECT  4.512 28.309 5.976 28.405 ;
     RECT  7.2 28.357 9.432 28.405 ;
     RECT  10.5 28.309 11.112 28.405 ;
     RECT  13.056 28.309 13.656 28.405 ;
     RECT  15.264 28.357 16.212 28.405 ;
     RECT  20.88 28.309 21.612 28.405 ;
     RECT  23.808 27.877 24.312 28.405 ;
     RECT  25.776 28.309 27.012 28.405 ;
     RECT  34.8 10.883 35.112 28.405 ;
     RECT  40.2 28.357 43.32 28.405 ;
     RECT  45.12 28.309 46.104 28.405 ;
     RECT  51 8.003 51.312 28.405 ;
     RECT  53.7 28.357 59.412 28.405 ;
     RECT  60.528 28.309 63 28.405 ;
     RECT  63.984 27.877 65.688 28.405 ;
     RECT  67.2 28.309 68.136 28.405 ;
     RECT  69.12 28.309 71.064 28.405 ;
     RECT  72.048 27.877 72.912 28.405 ;
     RECT  88.176 28.309 89.112 28.405 ;
     RECT  90.384 28.309 90.408 28.405 ;
     RECT  91.392 28.261 92.616 28.405 ;
     RECT  94.2 5.795 94.512 28.405 ;
     RECT  4.512 28.405 6.216 28.453 ;
     RECT  7.2 28.405 13.656 28.453 ;
     RECT  15.024 28.405 16.212 28.453 ;
     RECT  17.232 28.309 17.256 28.453 ;
     RECT  18.48 28.309 19.704 28.453 ;
     RECT  23.328 28.405 24.312 28.453 ;
     RECT  25.296 28.405 27.012 28.453 ;
     RECT  27.984 28.309 32.412 28.453 ;
     RECT  34.128 28.405 35.112 28.453 ;
     RECT  36.576 28.309 37.812 28.453 ;
     RECT  39.024 28.405 43.656 28.453 ;
     RECT  44.88 28.405 46.104 28.453 ;
     RECT  47.328 28.309 49.56 28.453 ;
     RECT  50.88 28.405 59.412 28.453 ;
     RECT  60.528 28.405 71.064 28.453 ;
     RECT  72.048 28.405 73.272 28.453 ;
     RECT  76.944 28.309 86.76 28.453 ;
     RECT  93.84 28.405 94.512 28.453 ;
     RECT  20.88 28.405 22.152 28.837 ;
     RECT  23.328 28.453 46.104 28.837 ;
     RECT  74.496 28.261 75.612 28.837 ;
     RECT  76.704 28.453 86.76 28.837 ;
     RECT  47.328 28.453 73.512 29.029 ;
     RECT  74.496 28.837 86.76 29.029 ;
     RECT  96.9 5.795 97.212 31.189 ;
     RECT  93.6 28.453 95.064 32.437 ;
     RECT  96.528 31.189 97.212 32.437 ;
     RECT  90.144 28.405 92.616 33.013 ;
     RECT  93.6 32.437 97.32 33.013 ;
     RECT  2.4 2.151 2.712 34.569 ;
     RECT  4.512 28.453 19.704 34.569 ;
     RECT  87.936 28.405 89.112 34.569 ;
     RECT  2.4 34.569 2.52 34.583 ;
     RECT  4.512 34.569 16.02 34.583 ;
     RECT  47.328 29.029 86.76 34.583 ;
     RECT  87.936 34.569 88.92 34.583 ;
     RECT  90.144 33.013 97.32 34.835 ;
     RECT  20.88 28.837 46.104 34.883 ;
     RECT  16.992 34.569 19.704 35.317 ;
     RECT  20.88 34.883 45.864 35.317 ;
     RECT  76.224 34.583 86.76 35.317 ;
     RECT  87.936 34.583 88.728 35.317 ;
     RECT  4.512 34.583 15.768 35.893 ;
     RECT  16.992 35.317 45.864 35.893 ;
     RECT  47.328 34.583 75.24 35.893 ;
     RECT  76.224 35.317 88.728 35.893 ;
     RECT  90.144 34.835 97.032 35.893 ;
     RECT  4.512 35.893 97.032 36.528 ;
     RECT  4.536 36.528 4.752 36.56 ;
     RECT  4.776 36.528 4.992 36.56 ;
     RECT  5.016 36.528 5.232 36.56 ;
     RECT  5.256 36.528 5.472 36.56 ;
     RECT  5.496 36.528 5.712 36.56 ;
     RECT  5.736 36.528 5.952 36.56 ;
     RECT  5.976 36.528 6.192 36.56 ;
     RECT  6.216 36.528 6.432 36.56 ;
     RECT  6.456 36.528 6.672 36.56 ;
     RECT  6.696 36.528 6.96 36.56 ;
     RECT  6.984 36.528 7.2 36.56 ;
     RECT  7.224 36.528 7.44 36.56 ;
     RECT  7.464 36.528 7.68 36.56 ;
     RECT  7.704 36.528 7.92 36.56 ;
     RECT  7.944 36.528 8.16 36.56 ;
     RECT  8.184 36.528 8.4 36.56 ;
     RECT  8.424 36.528 8.64 36.56 ;
     RECT  8.664 36.528 8.88 36.56 ;
     RECT  8.904 36.528 9.12 36.56 ;
     RECT  9.144 36.528 9.408 36.56 ;
     RECT  9.432 36.528 9.648 36.56 ;
     RECT  9.672 36.528 9.888 36.56 ;
     RECT  9.912 36.528 10.128 36.56 ;
     RECT  10.152 36.528 10.368 36.56 ;
     RECT  10.392 36.528 10.608 36.56 ;
     RECT  10.632 36.528 10.848 36.56 ;
     RECT  10.872 36.528 11.088 36.56 ;
     RECT  11.112 36.528 11.328 36.56 ;
     RECT  11.352 36.528 11.568 36.56 ;
     RECT  11.592 36.528 11.856 36.56 ;
     RECT  11.88 36.528 12.096 36.56 ;
     RECT  12.12 36.528 12.336 36.56 ;
     RECT  12.36 36.528 12.576 36.56 ;
     RECT  12.6 36.528 12.816 36.56 ;
     RECT  12.84 36.528 13.056 36.56 ;
     RECT  13.08 36.528 13.296 36.56 ;
     RECT  13.32 36.528 13.536 36.56 ;
     RECT  13.56 36.528 13.776 36.56 ;
     RECT  13.8 36.528 14.016 36.56 ;
     RECT  14.04 36.528 14.304 36.56 ;
     RECT  14.328 36.528 14.544 36.56 ;
     RECT  14.568 36.528 14.784 36.56 ;
     RECT  14.808 36.528 15.024 36.56 ;
     RECT  15.048 36.528 15.264 36.56 ;
     RECT  15.288 36.528 15.504 36.56 ;
     RECT  15.528 36.528 15.744 36.56 ;
     RECT  15.768 36.528 15.984 36.56 ;
     RECT  16.008 36.528 16.224 36.56 ;
     RECT  16.248 36.528 16.464 36.56 ;
     RECT  16.488 36.528 16.752 36.56 ;
     RECT  16.776 36.528 16.992 36.56 ;
     RECT  17.016 36.528 17.232 36.56 ;
     RECT  17.256 36.528 17.472 36.56 ;
     RECT  17.496 36.528 17.712 36.56 ;
     RECT  17.736 36.528 17.952 36.56 ;
     RECT  17.976 36.528 18.192 36.56 ;
     RECT  18.216 36.528 18.432 36.56 ;
     RECT  18.456 36.528 18.672 36.56 ;
     RECT  18.696 36.528 18.912 36.56 ;
     RECT  18.936 36.528 19.2 36.56 ;
     RECT  19.224 36.528 19.44 36.56 ;
     RECT  19.464 36.528 19.68 36.56 ;
     RECT  19.704 36.528 19.92 36.56 ;
     RECT  19.944 36.528 20.16 36.56 ;
     RECT  20.184 36.528 20.4 36.56 ;
     RECT  20.424 36.528 20.64 36.56 ;
     RECT  20.664 36.528 20.88 36.56 ;
     RECT  20.904 36.528 21.12 36.56 ;
     RECT  21.144 36.528 21.36 36.56 ;
     RECT  21.384 36.528 21.6 36.56 ;
     RECT  21.624 36.528 21.888 36.56 ;
     RECT  21.912 36.528 22.128 36.56 ;
     RECT  22.152 36.528 22.368 36.56 ;
     RECT  22.392 36.528 22.608 36.56 ;
     RECT  22.632 36.528 22.848 36.56 ;
     RECT  22.872 36.528 23.088 36.56 ;
     RECT  23.112 36.528 23.328 36.56 ;
     RECT  23.352 36.528 23.568 36.56 ;
     RECT  23.592 36.528 23.808 36.56 ;
     RECT  23.832 36.528 24.048 36.56 ;
     RECT  24.072 36.528 24.336 36.56 ;
     RECT  24.36 36.528 24.576 36.56 ;
     RECT  24.6 36.528 24.816 36.56 ;
     RECT  24.84 36.528 25.056 36.56 ;
     RECT  25.08 36.528 25.296 36.56 ;
     RECT  25.32 36.528 25.536 36.56 ;
     RECT  25.56 36.528 25.776 36.56 ;
     RECT  25.8 36.528 26.016 36.56 ;
     RECT  26.04 36.528 26.256 36.56 ;
     RECT  26.28 36.528 26.496 36.56 ;
     RECT  26.52 36.528 26.784 36.56 ;
     RECT  26.808 36.528 27.024 36.56 ;
     RECT  27.048 36.528 27.264 36.56 ;
     RECT  27.288 36.528 27.504 36.56 ;
     RECT  27.528 36.528 27.744 36.56 ;
     RECT  27.768 36.528 27.984 36.56 ;
     RECT  28.008 36.528 28.224 36.56 ;
     RECT  28.248 36.528 28.464 36.56 ;
     RECT  28.488 36.528 28.704 36.56 ;
     RECT  28.728 36.528 28.944 36.56 ;
     RECT  28.968 36.528 29.232 36.56 ;
     RECT  29.256 36.528 29.472 36.56 ;
     RECT  29.496 36.528 29.712 36.56 ;
     RECT  29.736 36.528 29.952 36.56 ;
     RECT  29.976 36.528 30.192 36.56 ;
     RECT  30.216 36.528 30.432 36.56 ;
     RECT  30.456 36.528 30.672 36.56 ;
     RECT  30.696 36.528 30.912 36.56 ;
     RECT  30.936 36.528 31.152 36.56 ;
     RECT  31.176 36.528 31.392 36.56 ;
     RECT  31.416 36.528 31.68 36.56 ;
     RECT  31.704 36.528 31.92 36.56 ;
     RECT  31.944 36.528 32.16 36.56 ;
     RECT  32.184 36.528 32.4 36.56 ;
     RECT  32.424 36.528 32.64 36.56 ;
     RECT  32.664 36.528 32.88 36.56 ;
     RECT  32.904 36.528 33.12 36.56 ;
     RECT  33.144 36.528 33.36 36.56 ;
     RECT  33.384 36.528 33.6 36.56 ;
     RECT  33.624 36.528 33.84 36.56 ;
     RECT  33.864 36.528 34.128 36.56 ;
     RECT  34.152 36.528 34.368 36.56 ;
     RECT  34.392 36.528 34.608 36.56 ;
     RECT  34.632 36.528 34.848 36.56 ;
     RECT  34.872 36.528 35.088 36.56 ;
     RECT  35.112 36.528 35.328 36.56 ;
     RECT  35.352 36.528 35.568 36.56 ;
     RECT  35.592 36.528 35.808 36.56 ;
     RECT  35.832 36.528 36.048 36.56 ;
     RECT  36.072 36.528 36.288 36.56 ;
     RECT  36.312 36.528 36.576 36.56 ;
     RECT  36.6 36.528 36.816 36.56 ;
     RECT  36.84 36.528 37.056 36.56 ;
     RECT  37.08 36.528 37.296 36.56 ;
     RECT  37.32 36.528 37.536 36.56 ;
     RECT  37.56 36.528 37.776 36.56 ;
     RECT  37.8 36.528 38.016 36.56 ;
     RECT  38.04 36.528 38.256 36.56 ;
     RECT  38.28 36.528 38.496 36.56 ;
     RECT  38.52 36.528 38.736 36.56 ;
     RECT  38.76 36.528 39.024 36.56 ;
     RECT  39.048 36.528 39.264 36.56 ;
     RECT  39.288 36.528 39.504 36.56 ;
     RECT  39.528 36.528 39.744 36.56 ;
     RECT  39.768 36.528 39.984 36.56 ;
     RECT  40.008 36.528 40.224 36.56 ;
     RECT  40.248 36.528 40.464 36.56 ;
     RECT  40.488 36.528 40.704 36.56 ;
     RECT  40.728 36.528 40.944 36.56 ;
     RECT  40.968 36.528 41.184 36.56 ;
     RECT  41.208 36.528 41.424 36.56 ;
     RECT  41.448 36.528 41.712 36.56 ;
     RECT  41.736 36.528 41.952 36.56 ;
     RECT  41.976 36.528 42.192 36.56 ;
     RECT  42.216 36.528 42.432 36.56 ;
     RECT  42.456 36.528 42.672 36.56 ;
     RECT  42.696 36.528 42.912 36.56 ;
     RECT  42.936 36.528 43.152 36.56 ;
     RECT  43.176 36.528 43.392 36.56 ;
     RECT  43.416 36.528 43.632 36.56 ;
     RECT  43.656 36.528 43.872 36.56 ;
     RECT  43.896 36.528 44.16 36.56 ;
     RECT  44.184 36.528 44.4 36.56 ;
     RECT  44.424 36.528 44.64 36.56 ;
     RECT  44.664 36.528 44.88 36.56 ;
     RECT  44.904 36.528 45.12 36.56 ;
     RECT  45.144 36.528 45.36 36.56 ;
     RECT  45.384 36.528 45.6 36.56 ;
     RECT  45.624 36.528 45.84 36.56 ;
     RECT  45.864 36.528 46.08 36.56 ;
     RECT  46.104 36.528 46.32 36.56 ;
     RECT  46.344 36.528 46.608 36.56 ;
     RECT  46.632 36.528 46.848 36.56 ;
     RECT  46.872 36.528 47.088 36.56 ;
     RECT  47.112 36.528 47.328 36.56 ;
     RECT  47.352 36.528 47.568 36.56 ;
     RECT  47.592 36.528 47.808 36.56 ;
     RECT  47.832 36.528 48.048 36.56 ;
     RECT  48.072 36.528 48.288 36.56 ;
     RECT  48.312 36.528 48.528 36.56 ;
     RECT  48.552 36.528 48.768 36.56 ;
     RECT  48.792 36.528 49.056 36.56 ;
     RECT  49.08 36.528 49.296 36.56 ;
     RECT  49.32 36.528 49.536 36.56 ;
     RECT  49.56 36.528 49.776 36.56 ;
     RECT  49.8 36.528 50.016 36.56 ;
     RECT  50.04 36.528 50.256 36.56 ;
     RECT  50.28 36.528 50.496 36.56 ;
     RECT  50.52 36.528 50.736 36.56 ;
     RECT  50.76 36.528 50.976 36.56 ;
     RECT  51 36.528 51.216 36.56 ;
     RECT  51.24 36.528 51.504 36.56 ;
     RECT  51.528 36.528 51.744 36.56 ;
     RECT  51.768 36.528 51.984 36.56 ;
     RECT  52.008 36.528 52.224 36.56 ;
     RECT  52.248 36.528 52.464 36.56 ;
     RECT  52.488 36.528 52.704 36.56 ;
     RECT  52.728 36.528 52.944 36.56 ;
     RECT  52.968 36.528 53.184 36.56 ;
     RECT  53.208 36.528 53.424 36.56 ;
     RECT  53.448 36.528 53.664 36.56 ;
     RECT  53.688 36.528 53.952 36.56 ;
     RECT  53.976 36.528 54.192 36.56 ;
     RECT  54.216 36.528 54.432 36.56 ;
     RECT  54.456 36.528 54.672 36.56 ;
     RECT  54.696 36.528 54.912 36.56 ;
     RECT  54.936 36.528 55.152 36.56 ;
     RECT  55.176 36.528 55.392 36.56 ;
     RECT  55.416 36.528 55.632 36.56 ;
     RECT  55.656 36.528 55.872 36.56 ;
     RECT  55.896 36.528 56.112 36.56 ;
     RECT  56.136 36.528 56.4 36.56 ;
     RECT  56.424 36.528 56.64 36.56 ;
     RECT  56.664 36.528 56.88 36.56 ;
     RECT  56.904 36.528 57.12 36.56 ;
     RECT  57.144 36.528 57.36 36.56 ;
     RECT  57.384 36.528 57.6 36.56 ;
     RECT  57.624 36.528 57.84 36.56 ;
     RECT  57.864 36.528 58.08 36.56 ;
     RECT  58.104 36.528 58.32 36.56 ;
     RECT  58.344 36.528 58.56 36.56 ;
     RECT  58.584 36.528 58.848 36.56 ;
     RECT  58.872 36.528 59.088 36.56 ;
     RECT  59.112 36.528 59.328 36.56 ;
     RECT  59.352 36.528 59.568 36.56 ;
     RECT  59.592 36.528 59.808 36.56 ;
     RECT  59.832 36.528 60.048 36.56 ;
     RECT  60.072 36.528 60.288 36.56 ;
     RECT  60.312 36.528 60.528 36.56 ;
     RECT  60.552 36.528 60.768 36.56 ;
     RECT  60.792 36.528 61.008 36.56 ;
     RECT  61.032 36.528 61.248 36.56 ;
     RECT  61.272 36.528 61.536 36.56 ;
     RECT  61.56 36.528 61.776 36.56 ;
     RECT  61.8 36.528 62.016 36.56 ;
     RECT  62.04 36.528 62.256 36.56 ;
     RECT  62.28 36.528 62.496 36.56 ;
     RECT  62.52 36.528 62.736 36.56 ;
     RECT  62.76 36.528 62.976 36.56 ;
     RECT  63 36.528 63.216 36.56 ;
     RECT  63.24 36.528 63.456 36.56 ;
     RECT  63.48 36.528 63.696 36.56 ;
     RECT  63.72 36.528 63.984 36.56 ;
     RECT  64.008 36.528 64.224 36.56 ;
     RECT  64.248 36.528 64.464 36.56 ;
     RECT  64.488 36.528 64.704 36.56 ;
     RECT  64.728 36.528 64.944 36.56 ;
     RECT  64.968 36.528 65.184 36.56 ;
     RECT  65.208 36.528 65.424 36.56 ;
     RECT  65.448 36.528 65.664 36.56 ;
     RECT  65.688 36.528 65.904 36.56 ;
     RECT  65.928 36.528 66.144 36.56 ;
     RECT  66.168 36.528 66.432 36.56 ;
     RECT  66.456 36.528 66.672 36.56 ;
     RECT  66.696 36.528 66.912 36.56 ;
     RECT  66.936 36.528 67.152 36.56 ;
     RECT  67.176 36.528 67.392 36.56 ;
     RECT  67.416 36.528 67.632 36.56 ;
     RECT  67.656 36.528 67.872 36.56 ;
     RECT  67.896 36.528 68.112 36.56 ;
     RECT  68.136 36.528 68.352 36.56 ;
     RECT  68.376 36.528 68.592 36.56 ;
     RECT  68.616 36.528 68.88 36.56 ;
     RECT  68.904 36.528 69.12 36.56 ;
     RECT  69.144 36.528 69.36 36.56 ;
     RECT  69.384 36.528 69.6 36.56 ;
     RECT  69.624 36.528 69.84 36.56 ;
     RECT  69.864 36.528 70.08 36.56 ;
     RECT  70.104 36.528 70.32 36.56 ;
     RECT  70.344 36.528 70.56 36.56 ;
     RECT  70.584 36.528 70.8 36.56 ;
     RECT  70.824 36.528 71.04 36.56 ;
     RECT  71.064 36.528 71.328 36.56 ;
     RECT  71.352 36.528 71.568 36.56 ;
     RECT  71.592 36.528 71.808 36.56 ;
     RECT  71.832 36.528 72.048 36.56 ;
     RECT  72.072 36.528 72.288 36.56 ;
     RECT  72.312 36.528 72.528 36.56 ;
     RECT  72.552 36.528 72.768 36.56 ;
     RECT  72.792 36.528 73.008 36.56 ;
     RECT  73.032 36.528 73.248 36.56 ;
     RECT  73.272 36.528 73.488 36.56 ;
     RECT  73.512 36.528 73.776 36.56 ;
     RECT  73.8 36.528 74.016 36.56 ;
     RECT  74.04 36.528 74.256 36.56 ;
     RECT  74.28 36.528 74.496 36.56 ;
     RECT  74.52 36.528 74.736 36.56 ;
     RECT  74.76 36.528 74.976 36.56 ;
     RECT  75 36.528 75.216 36.56 ;
     RECT  75.24 36.528 75.456 36.56 ;
     RECT  75.48 36.528 75.696 36.56 ;
     RECT  75.72 36.528 75.936 36.56 ;
     RECT  75.96 36.528 76.224 36.56 ;
     RECT  76.248 36.528 76.464 36.56 ;
     RECT  76.488 36.528 76.704 36.56 ;
     RECT  76.728 36.528 76.944 36.56 ;
     RECT  76.968 36.528 77.184 36.56 ;
     RECT  77.208 36.528 77.424 36.56 ;
     RECT  77.448 36.528 77.664 36.56 ;
     RECT  77.688 36.528 77.904 36.56 ;
     RECT  77.928 36.528 78.144 36.56 ;
     RECT  78.168 36.528 78.384 36.56 ;
     RECT  78.408 36.528 78.672 36.56 ;
     RECT  78.696 36.528 78.912 36.56 ;
     RECT  78.936 36.528 79.152 36.56 ;
     RECT  79.176 36.528 79.392 36.56 ;
     RECT  79.416 36.528 79.632 36.56 ;
     RECT  79.656 36.528 79.872 36.56 ;
     RECT  79.896 36.528 80.112 36.56 ;
     RECT  80.136 36.528 80.352 36.56 ;
     RECT  80.376 36.528 80.592 36.56 ;
     RECT  80.616 36.528 80.832 36.56 ;
     RECT  80.856 36.528 81.12 36.56 ;
     RECT  81.144 36.528 81.36 36.56 ;
     RECT  81.384 36.528 81.6 36.56 ;
     RECT  81.624 36.528 81.84 36.56 ;
     RECT  81.864 36.528 82.08 36.56 ;
     RECT  82.104 36.528 82.32 36.56 ;
     RECT  82.344 36.528 82.56 36.56 ;
     RECT  82.584 36.528 82.8 36.56 ;
     RECT  82.824 36.528 83.04 36.56 ;
     RECT  83.064 36.528 83.28 36.56 ;
     RECT  83.304 36.528 83.52 36.56 ;
     RECT  83.544 36.528 83.808 36.56 ;
     RECT  83.832 36.528 84.048 36.56 ;
     RECT  84.072 36.528 84.288 36.56 ;
     RECT  84.312 36.528 84.528 36.56 ;
     RECT  84.552 36.528 84.768 36.56 ;
     RECT  84.792 36.528 85.008 36.56 ;
     RECT  85.032 36.528 85.248 36.56 ;
     RECT  85.272 36.528 85.488 36.56 ;
     RECT  85.512 36.528 85.728 36.56 ;
     RECT  85.752 36.528 85.968 36.56 ;
     RECT  85.992 36.528 86.256 36.56 ;
     RECT  86.28 36.528 86.496 36.56 ;
     RECT  86.52 36.528 86.736 36.56 ;
     RECT  86.76 36.528 86.976 36.56 ;
     RECT  87 36.528 87.216 36.56 ;
     RECT  87.24 36.528 87.456 36.56 ;
     RECT  87.48 36.528 87.696 36.56 ;
     RECT  87.72 36.528 87.936 36.56 ;
     RECT  87.96 36.528 88.176 36.56 ;
     RECT  88.2 36.528 88.416 36.56 ;
     RECT  88.44 36.528 88.704 36.56 ;
     RECT  88.728 36.528 88.944 36.56 ;
     RECT  88.968 36.528 89.184 36.56 ;
     RECT  89.208 36.528 89.424 36.56 ;
     RECT  89.448 36.528 89.664 36.56 ;
     RECT  89.688 36.528 89.904 36.56 ;
     RECT  89.928 36.528 90.144 36.56 ;
     RECT  90.168 36.528 90.384 36.56 ;
     RECT  90.408 36.528 90.624 36.56 ;
     RECT  90.648 36.528 90.864 36.56 ;
     RECT  90.888 36.528 91.152 36.56 ;
     RECT  91.176 36.528 91.392 36.56 ;
     RECT  91.416 36.528 91.632 36.56 ;
     RECT  91.656 36.528 91.872 36.56 ;
     RECT  91.896 36.528 92.112 36.56 ;
     RECT  92.136 36.528 92.352 36.56 ;
     RECT  92.376 36.528 92.592 36.56 ;
     RECT  92.616 36.528 92.832 36.56 ;
     RECT  92.856 36.528 93.072 36.56 ;
     RECT  93.096 36.528 93.312 36.56 ;
     RECT  93.336 36.528 93.6 36.56 ;
     RECT  93.624 36.528 93.84 36.56 ;
     RECT  93.864 36.528 94.08 36.56 ;
     RECT  94.104 36.528 94.32 36.56 ;
     RECT  94.344 36.528 94.56 36.56 ;
     RECT  94.584 36.528 94.8 36.56 ;
     RECT  94.824 36.528 95.04 36.56 ;
     RECT  95.064 36.528 95.28 36.56 ;
     RECT  95.304 36.528 95.52 36.56 ;
     RECT  95.544 36.528 95.76 36.56 ;
     RECT  95.784 36.528 96.048 36.56 ;
     RECT  96.072 36.528 96.288 36.56 ;
     RECT  96.312 36.528 96.528 36.56 ;
     RECT  96.552 36.528 96.768 36.56 ;
     RECT  96.792 36.528 97.008 36.56 ;
     RECT  32.568 0.133 32.592 0.144 ;
     RECT  32.712 0.133 32.832 0.144 ;
     RECT  32.952 0.133 33.072 0.144 ;
     RECT  33.192 0.133 33.312 0.144 ;
     RECT  33.432 0.133 33.552 0.144 ;
     RECT  33.672 0.133 33.792 0.144 ;
     RECT  33.912 0.133 33.984 0.144 ;
     RECT  34.728 0.133 34.8 0.144 ;
     RECT  34.92 0.133 35.04 0.144 ;
     RECT  35.16 0.133 35.28 0.144 ;
     RECT  35.4 0.133 35.52 0.144 ;
     RECT  35.64 0.133 35.76 0.144 ;
     RECT  35.88 0.133 35.952 0.144 ;
     RECT  45.528 0.133 45.552 0.144 ;
     RECT  45.672 0.133 45.792 0.144 ;
     RECT  45.912 0.133 46.032 0.144 ;
     RECT  46.152 0.133 46.272 0.144 ;
     RECT  46.392 0.133 46.56 0.144 ;
     RECT  46.68 0.133 46.8 0.144 ;
     RECT  46.92 0.133 46.944 0.144 ;
     RECT  46.968 0.133 47.04 0.144 ;
     RECT  47.16 0.133 47.28 0.144 ;
     RECT  47.4 0.133 47.52 0.144 ;
     RECT  47.64 0.133 47.76 0.144 ;
     RECT  47.88 0.133 48 0.144 ;
     RECT  48.12 0.133 48.192 0.144 ;
     RECT  56.328 0.133 56.352 0.144 ;
     RECT  56.472 0.133 56.592 0.144 ;
     RECT  56.712 0.133 56.832 0.144 ;
     RECT  56.952 0.133 57.072 0.144 ;
     RECT  57.192 0.133 57.312 0.144 ;
     RECT  57.432 0.133 57.504 0.144 ;
     RECT  64.104 0.133 64.176 0.144 ;
     RECT  64.296 0.133 64.416 0.144 ;
     RECT  64.536 0.133 64.656 0.144 ;
     RECT  64.776 0.133 64.896 0.144 ;
     RECT  65.016 0.133 65.088 0.144 ;
     RECT  65.832 0.133 65.856 0.144 ;
     RECT  65.976 0.133 66.096 0.144 ;
     RECT  66.216 0.133 66.384 0.144 ;
     RECT  66.504 0.133 66.624 0.144 ;
     RECT  66.744 0.133 66.864 0.144 ;
     RECT  66.984 0.133 67.056 0.144 ;
     RECT  5.412 1.763 6.672 1.811 ;
     RECT  6.696 1.763 7.8 1.811 ;
     RECT  11.592 1.763 13.104 2.965 ;
     RECT  13.8 1.763 15.264 2.339 ;
     RECT  95.544 1.763 96.768 1.859 ;
     RECT  57.624 1.811 58.848 2.821 ;
     RECT  76.248 1.811 77.424 3.443 ;
     RECT  79.176 1.811 80.352 2.915 ;
     RECT  95.448 1.859 96.9 4.357 ;
     RECT  87 1.907 88.176 2.915 ;
     RECT  16.488 2.339 17.472 2.915 ;
     RECT  21.072 2.915 21.168 4.213 ;
     RECT  52.584 2.915 53.568 3.443 ;
     RECT  68.664 2.915 69.744 4.645 ;
     RECT  78.648 2.915 80.592 3.925 ;
     RECT  86.568 2.915 88.176 3.443 ;
     RECT  37.992 2.963 39.216 3.973 ;
     RECT  41.592 2.963 42.72 4.115 ;
     RECT  11.592 2.965 13.056 4.451 ;
     RECT  18.432 3.059 18.48 4.501 ;
     RECT  52.488 3.443 53.568 4.741 ;
     RECT  86.568 3.443 88.368 4.261 ;
     RECT  13.512 3.491 13.608 4.789 ;
     RECT  79.56 3.925 80.592 4.261 ;
     RECT  38.232 3.973 39.216 5.747 ;
     RECT  54.168 4.019 55.872 4.163 ;
     RECT  75.72 4.019 75.768 5.173 ;
     RECT  89.112 4.019 90.576 6.899 ;
     RECT  41.016 4.115 42.72 4.693 ;
     RECT  78.312 4.115 79.344 5.747 ;
     RECT  54.012 4.163 55.872 5.365 ;
     RECT  87 4.261 88.368 4.405 ;
     RECT  95.448 4.357 96.624 5.795 ;
     RECT  51.312 4.595 52.464 5.171 ;
     RECT  43.896 4.643 44.976 6.371 ;
     RECT  41.016 4.693 42.24 5.747 ;
     RECT  13.512 4.789 14.784 4.981 ;
     RECT  71.256 4.883 72.384 5.747 ;
     RECT  13.704 4.981 14.784 6.323 ;
     RECT  68.568 5.171 69.552 5.795 ;
     RECT  87.816 5.171 88.8 7.619 ;
     RECT  49.56 5.219 51 6.229 ;
     RECT  91.812 5.267 92.88 5.603 ;
     RECT  57.24 5.363 58.224 6.323 ;
     RECT  54.012 5.365 55.248 6.707 ;
     RECT  92.904 5.411 94.2 5.603 ;
     RECT  86.52 5.603 87.792 6.851 ;
     RECT  32.412 5.747 33.456 7.139 ;
     RECT  35.88 5.747 37.392 5.843 ;
     RECT  38.184 5.747 39.216 5.843 ;
     RECT  71.208 5.747 72.384 5.795 ;
     RECT  78.312 5.747 79.392 6.707 ;
     RECT  64.92 5.795 65.952 6.371 ;
     RECT  68.376 5.795 69.552 5.843 ;
     RECT  71.208 5.795 72.432 6.323 ;
     RECT  35.88 5.843 37.5 6.805 ;
     RECT  37.812 5.843 39.216 6.899 ;
     RECT  68.328 5.843 69.552 5.987 ;
     RECT  68.328 5.987 69.9 6.805 ;
     RECT  16.212 6.133 17.616 7.331 ;
     RECT  48.984 6.323 50.448 6.899 ;
     RECT  72.336 6.323 72.432 6.805 ;
     RECT  25.608 6.371 26.592 7.619 ;
     RECT  64.92 6.371 66.096 6.563 ;
     RECT  43.212 6.515 43.32 7.525 ;
     RECT  64.92 6.563 66.192 6.805 ;
     RECT  30.408 6.707 31.488 6.899 ;
     RECT  78.312 6.707 79.728 6.851 ;
     RECT  73.896 6.709 75.3 8.003 ;
     RECT  36.072 6.805 37.5 8.003 ;
     RECT  64.968 6.805 66.192 8.003 ;
     RECT  68.568 6.805 69.9 8.579 ;
     RECT  86.412 6.851 87.792 7.619 ;
     RECT  27.336 6.899 28.368 7.475 ;
     RECT  30.408 6.899 31.92 7.475 ;
     RECT  62.664 6.899 63.792 8.579 ;
     RECT  67.512 6.899 68.544 8.579 ;
     RECT  46.632 6.947 47.616 8.579 ;
     RECT  32.412 7.139 33.552 8.579 ;
     RECT  24.312 7.427 25.584 7.619 ;
     RECT  60.312 7.475 61.392 8.003 ;
     RECT  60.312 8.003 61.8 8.579 ;
     RECT  64.968 8.003 66.384 8.579 ;
     RECT  45.912 27.301 47.328 28.309 ;
     RECT  27.012 27.781 27.984 28.453 ;
     RECT  28.008 27.781 29.4 28.261 ;
     RECT  59.412 27.877 60.528 28.453 ;
     RECT  65.688 27.877 67.2 28.405 ;
     RECT  67.608 27.877 69.12 28.309 ;
     RECT  75.612 27.877 76.944 28.453 ;
     RECT  78.312 27.877 79.392 28.309 ;
     RECT  81.624 27.877 82.8 28.309 ;
     RECT  84.552 27.877 85.728 28.309 ;
     RECT  8.112 27.925 9.408 28.357 ;
     RECT  9.432 27.925 10.5 28.405 ;
     RECT  5.736 28.021 7.2 28.309 ;
     RECT  28.008 28.261 29.28 28.309 ;
     RECT  5.976 28.309 7.2 28.405 ;
     RECT  16.212 28.309 17.232 28.453 ;
     RECT  17.256 28.309 18.48 28.453 ;
     RECT  19.704 28.309 20.88 35.317 ;
     RECT  24.312 28.309 25.776 28.405 ;
     RECT  35.112 28.309 36.576 28.453 ;
     RECT  41.448 28.309 42.9 28.357 ;
     RECT  46.104 28.309 47.328 34.883 ;
     RECT  49.56 28.309 51 28.405 ;
     RECT  54.696 28.309 56.112 28.357 ;
     RECT  63 28.309 63.984 28.405 ;
     RECT  68.136 28.309 69.12 28.405 ;
     RECT  71.064 28.309 72.048 28.453 ;
     RECT  86.76 28.309 88.176 28.405 ;
     RECT  89.112 28.309 90.384 28.405 ;
     RECT  90.408 28.309 91.392 28.405 ;
     RECT  6.216 28.405 7.2 28.453 ;
     RECT  13.656 28.405 15.024 28.453 ;
     RECT  22.152 28.405 23.328 28.837 ;
     RECT  24.312 28.405 25.296 28.453 ;
     RECT  37.812 28.405 39.024 28.453 ;
     RECT  43.656 28.405 44.88 28.453 ;
     RECT  49.56 28.405 50.88 28.453 ;
     RECT  73.272 28.405 74.496 28.453 ;
     RECT  86.76 28.405 87.936 35.317 ;
     RECT  89.112 28.405 90.144 34.569 ;
     RECT  92.616 28.405 93.84 28.453 ;
     RECT  73.512 28.453 74.496 29.029 ;
     RECT  75.612 28.453 76.704 28.837 ;
     RECT  92.616 28.453 93.6 33.013 ;
     RECT  95.064 31.189 96.528 32.437 ;
     RECT  16.02 34.569 16.992 34.583 ;
     RECT  88.92 34.569 90.144 34.583 ;
     RECT  15.768 34.583 16.992 35.893 ;
     RECT  75.24 34.583 76.224 35.893 ;
     RECT  88.728 34.583 90.144 35.893 ;
     RECT  45.864 34.883 47.328 35.893 ;
  END
END dsfd_hstnv_759
END LIBRARY
